VERSION 5.7 ;
BUSBITCHARS "[]" ;
DIVIDERCHAR "/" ;
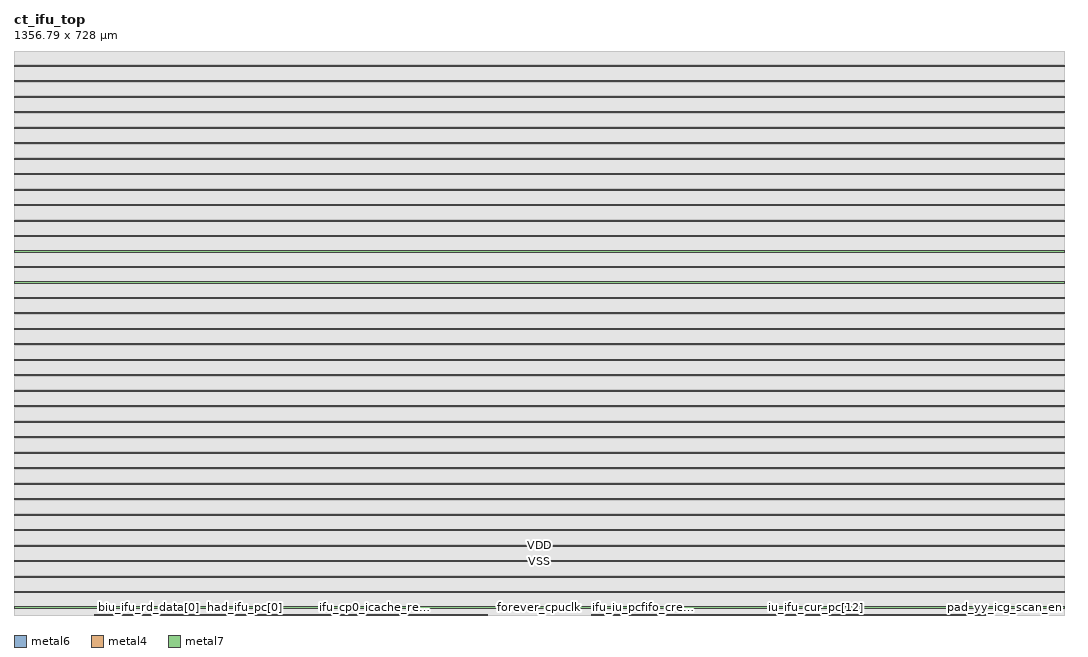
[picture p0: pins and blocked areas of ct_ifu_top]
MACRO ct_ifu_top
  CLASS BLOCK ;
  FOREIGN ct_ifu_top 0 0 ;
  ORIGIN 0 0 ;
  SIZE 1356.79 BY 728 ;
  SYMMETRY X Y ;
  PIN biu_ifu_rd_data[0]
    DIRECTION INPUT ;
    USE SIGNAL ;
    PORT
      LAYER metal6 ;
        RECT 174.185 0.000 174.325 0.560 ;
    END
  END biu_ifu_rd_data[0]
  PIN biu_ifu_rd_data[100]
    DIRECTION INPUT ;
    USE SIGNAL ;
    PORT
      LAYER metal6 ;
        RECT 118.185 0.000 118.325 0.560 ;
    END
  END biu_ifu_rd_data[100]
  PIN biu_ifu_rd_data[101]
    DIRECTION INPUT ;
    USE SIGNAL ;
    PORT
      LAYER metal4 ;
        RECT 118.185 0.000 118.325 0.560 ;
    END
  END biu_ifu_rd_data[101]
  PIN biu_ifu_rd_data[102]
    DIRECTION INPUT ;
    USE SIGNAL ;
    PORT
      LAYER metal6 ;
        RECT 117.065 0.000 117.205 0.560 ;
    END
  END biu_ifu_rd_data[102]
  PIN biu_ifu_rd_data[103]
    DIRECTION INPUT ;
    USE SIGNAL ;
    PORT
      LAYER metal4 ;
        RECT 117.065 0.000 117.205 0.560 ;
    END
  END biu_ifu_rd_data[103]
  PIN biu_ifu_rd_data[104]
    DIRECTION INPUT ;
    USE SIGNAL ;
    PORT
      LAYER metal6 ;
        RECT 115.945 0.000 116.085 0.560 ;
    END
  END biu_ifu_rd_data[104]
  PIN biu_ifu_rd_data[105]
    DIRECTION INPUT ;
    USE SIGNAL ;
    PORT
      LAYER metal4 ;
        RECT 115.945 0.000 116.085 0.560 ;
    END
  END biu_ifu_rd_data[105]
  PIN biu_ifu_rd_data[106]
    DIRECTION INPUT ;
    USE SIGNAL ;
    PORT
      LAYER metal6 ;
        RECT 114.825 0.000 114.965 0.560 ;
    END
  END biu_ifu_rd_data[106]
  PIN biu_ifu_rd_data[107]
    DIRECTION INPUT ;
    USE SIGNAL ;
    PORT
      LAYER metal4 ;
        RECT 114.825 0.000 114.965 0.560 ;
    END
  END biu_ifu_rd_data[107]
  PIN biu_ifu_rd_data[108]
    DIRECTION INPUT ;
    USE SIGNAL ;
    PORT
      LAYER metal6 ;
        RECT 113.705 0.000 113.845 0.560 ;
    END
  END biu_ifu_rd_data[108]
  PIN biu_ifu_rd_data[109]
    DIRECTION INPUT ;
    USE SIGNAL ;
    PORT
      LAYER metal4 ;
        RECT 113.705 0.000 113.845 0.560 ;
    END
  END biu_ifu_rd_data[109]
  PIN biu_ifu_rd_data[10]
    DIRECTION INPUT ;
    USE SIGNAL ;
    PORT
      LAYER metal6 ;
        RECT 168.585 0.000 168.725 0.560 ;
    END
  END biu_ifu_rd_data[10]
  PIN biu_ifu_rd_data[110]
    DIRECTION INPUT ;
    USE SIGNAL ;
    PORT
      LAYER metal6 ;
        RECT 112.585 0.000 112.725 0.560 ;
    END
  END biu_ifu_rd_data[110]
  PIN biu_ifu_rd_data[111]
    DIRECTION INPUT ;
    USE SIGNAL ;
    PORT
      LAYER metal4 ;
        RECT 112.585 0.000 112.725 0.560 ;
    END
  END biu_ifu_rd_data[111]
  PIN biu_ifu_rd_data[112]
    DIRECTION INPUT ;
    USE SIGNAL ;
    PORT
      LAYER metal6 ;
        RECT 111.465 0.000 111.605 0.560 ;
    END
  END biu_ifu_rd_data[112]
  PIN biu_ifu_rd_data[113]
    DIRECTION INPUT ;
    USE SIGNAL ;
    PORT
      LAYER metal4 ;
        RECT 111.465 0.000 111.605 0.560 ;
    END
  END biu_ifu_rd_data[113]
  PIN biu_ifu_rd_data[114]
    DIRECTION INPUT ;
    USE SIGNAL ;
    PORT
      LAYER metal6 ;
        RECT 110.345 0.000 110.485 0.560 ;
    END
  END biu_ifu_rd_data[114]
  PIN biu_ifu_rd_data[115]
    DIRECTION INPUT ;
    USE SIGNAL ;
    PORT
      LAYER metal4 ;
        RECT 110.345 0.000 110.485 0.560 ;
    END
  END biu_ifu_rd_data[115]
  PIN biu_ifu_rd_data[116]
    DIRECTION INPUT ;
    USE SIGNAL ;
    PORT
      LAYER metal6 ;
        RECT 109.225 0.000 109.365 0.560 ;
    END
  END biu_ifu_rd_data[116]
  PIN biu_ifu_rd_data[117]
    DIRECTION INPUT ;
    USE SIGNAL ;
    PORT
      LAYER metal4 ;
        RECT 109.225 0.000 109.365 0.560 ;
    END
  END biu_ifu_rd_data[117]
  PIN biu_ifu_rd_data[118]
    DIRECTION INPUT ;
    USE SIGNAL ;
    PORT
      LAYER metal6 ;
        RECT 108.105 0.000 108.245 0.560 ;
    END
  END biu_ifu_rd_data[118]
  PIN biu_ifu_rd_data[119]
    DIRECTION INPUT ;
    USE SIGNAL ;
    PORT
      LAYER metal4 ;
        RECT 108.105 0.000 108.245 0.560 ;
    END
  END biu_ifu_rd_data[119]
  PIN biu_ifu_rd_data[11]
    DIRECTION INPUT ;
    USE SIGNAL ;
    PORT
      LAYER metal4 ;
        RECT 168.585 0.000 168.725 0.560 ;
    END
  END biu_ifu_rd_data[11]
  PIN biu_ifu_rd_data[120]
    DIRECTION INPUT ;
    USE SIGNAL ;
    PORT
      LAYER metal6 ;
        RECT 106.985 0.000 107.125 0.560 ;
    END
  END biu_ifu_rd_data[120]
  PIN biu_ifu_rd_data[121]
    DIRECTION INPUT ;
    USE SIGNAL ;
    PORT
      LAYER metal4 ;
        RECT 106.985 0.000 107.125 0.560 ;
    END
  END biu_ifu_rd_data[121]
  PIN biu_ifu_rd_data[122]
    DIRECTION INPUT ;
    USE SIGNAL ;
    PORT
      LAYER metal6 ;
        RECT 105.865 0.000 106.005 0.560 ;
    END
  END biu_ifu_rd_data[122]
  PIN biu_ifu_rd_data[123]
    DIRECTION INPUT ;
    USE SIGNAL ;
    PORT
      LAYER metal4 ;
        RECT 105.865 0.000 106.005 0.560 ;
    END
  END biu_ifu_rd_data[123]
  PIN biu_ifu_rd_data[124]
    DIRECTION INPUT ;
    USE SIGNAL ;
    PORT
      LAYER metal6 ;
        RECT 104.745 0.000 104.885 0.560 ;
    END
  END biu_ifu_rd_data[124]
  PIN biu_ifu_rd_data[125]
    DIRECTION INPUT ;
    USE SIGNAL ;
    PORT
      LAYER metal4 ;
        RECT 104.745 0.000 104.885 0.560 ;
    END
  END biu_ifu_rd_data[125]
  PIN biu_ifu_rd_data[126]
    DIRECTION INPUT ;
    USE SIGNAL ;
    PORT
      LAYER metal6 ;
        RECT 103.625 0.000 103.765 0.560 ;
    END
  END biu_ifu_rd_data[126]
  PIN biu_ifu_rd_data[127]
    DIRECTION INPUT ;
    USE SIGNAL ;
    PORT
      LAYER metal4 ;
        RECT 103.625 0.000 103.765 0.560 ;
    END
  END biu_ifu_rd_data[127]
  PIN biu_ifu_rd_data[12]
    DIRECTION INPUT ;
    USE SIGNAL ;
    PORT
      LAYER metal6 ;
        RECT 167.465 0.000 167.605 0.560 ;
    END
  END biu_ifu_rd_data[12]
  PIN biu_ifu_rd_data[13]
    DIRECTION INPUT ;
    USE SIGNAL ;
    PORT
      LAYER metal4 ;
        RECT 167.465 0.000 167.605 0.560 ;
    END
  END biu_ifu_rd_data[13]
  PIN biu_ifu_rd_data[14]
    DIRECTION INPUT ;
    USE SIGNAL ;
    PORT
      LAYER metal6 ;
        RECT 166.345 0.000 166.485 0.560 ;
    END
  END biu_ifu_rd_data[14]
  PIN biu_ifu_rd_data[15]
    DIRECTION INPUT ;
    USE SIGNAL ;
    PORT
      LAYER metal4 ;
        RECT 166.345 0.000 166.485 0.560 ;
    END
  END biu_ifu_rd_data[15]
  PIN biu_ifu_rd_data[16]
    DIRECTION INPUT ;
    USE SIGNAL ;
    PORT
      LAYER metal6 ;
        RECT 165.225 0.000 165.365 0.560 ;
    END
  END biu_ifu_rd_data[16]
  PIN biu_ifu_rd_data[17]
    DIRECTION INPUT ;
    USE SIGNAL ;
    PORT
      LAYER metal4 ;
        RECT 165.225 0.000 165.365 0.560 ;
    END
  END biu_ifu_rd_data[17]
  PIN biu_ifu_rd_data[18]
    DIRECTION INPUT ;
    USE SIGNAL ;
    PORT
      LAYER metal6 ;
        RECT 164.105 0.000 164.245 0.560 ;
    END
  END biu_ifu_rd_data[18]
  PIN biu_ifu_rd_data[19]
    DIRECTION INPUT ;
    USE SIGNAL ;
    PORT
      LAYER metal4 ;
        RECT 164.105 0.000 164.245 0.560 ;
    END
  END biu_ifu_rd_data[19]
  PIN biu_ifu_rd_data[1]
    DIRECTION INPUT ;
    USE SIGNAL ;
    PORT
      LAYER metal4 ;
        RECT 174.185 0.000 174.325 0.560 ;
    END
  END biu_ifu_rd_data[1]
  PIN biu_ifu_rd_data[20]
    DIRECTION INPUT ;
    USE SIGNAL ;
    PORT
      LAYER metal6 ;
        RECT 162.985 0.000 163.125 0.560 ;
    END
  END biu_ifu_rd_data[20]
  PIN biu_ifu_rd_data[21]
    DIRECTION INPUT ;
    USE SIGNAL ;
    PORT
      LAYER metal4 ;
        RECT 162.985 0.000 163.125 0.560 ;
    END
  END biu_ifu_rd_data[21]
  PIN biu_ifu_rd_data[22]
    DIRECTION INPUT ;
    USE SIGNAL ;
    PORT
      LAYER metal6 ;
        RECT 161.865 0.000 162.005 0.560 ;
    END
  END biu_ifu_rd_data[22]
  PIN biu_ifu_rd_data[23]
    DIRECTION INPUT ;
    USE SIGNAL ;
    PORT
      LAYER metal4 ;
        RECT 161.865 0.000 162.005 0.560 ;
    END
  END biu_ifu_rd_data[23]
  PIN biu_ifu_rd_data[24]
    DIRECTION INPUT ;
    USE SIGNAL ;
    PORT
      LAYER metal6 ;
        RECT 160.745 0.000 160.885 0.560 ;
    END
  END biu_ifu_rd_data[24]
  PIN biu_ifu_rd_data[25]
    DIRECTION INPUT ;
    USE SIGNAL ;
    PORT
      LAYER metal4 ;
        RECT 160.745 0.000 160.885 0.560 ;
    END
  END biu_ifu_rd_data[25]
  PIN biu_ifu_rd_data[26]
    DIRECTION INPUT ;
    USE SIGNAL ;
    PORT
      LAYER metal6 ;
        RECT 159.625 0.000 159.765 0.560 ;
    END
  END biu_ifu_rd_data[26]
  PIN biu_ifu_rd_data[27]
    DIRECTION INPUT ;
    USE SIGNAL ;
    PORT
      LAYER metal4 ;
        RECT 159.625 0.000 159.765 0.560 ;
    END
  END biu_ifu_rd_data[27]
  PIN biu_ifu_rd_data[28]
    DIRECTION INPUT ;
    USE SIGNAL ;
    PORT
      LAYER metal6 ;
        RECT 158.505 0.000 158.645 0.560 ;
    END
  END biu_ifu_rd_data[28]
  PIN biu_ifu_rd_data[29]
    DIRECTION INPUT ;
    USE SIGNAL ;
    PORT
      LAYER metal4 ;
        RECT 158.505 0.000 158.645 0.560 ;
    END
  END biu_ifu_rd_data[29]
  PIN biu_ifu_rd_data[2]
    DIRECTION INPUT ;
    USE SIGNAL ;
    PORT
      LAYER metal6 ;
        RECT 173.065 0.000 173.205 0.560 ;
    END
  END biu_ifu_rd_data[2]
  PIN biu_ifu_rd_data[30]
    DIRECTION INPUT ;
    USE SIGNAL ;
    PORT
      LAYER metal6 ;
        RECT 157.385 0.000 157.525 0.560 ;
    END
  END biu_ifu_rd_data[30]
  PIN biu_ifu_rd_data[31]
    DIRECTION INPUT ;
    USE SIGNAL ;
    PORT
      LAYER metal4 ;
        RECT 157.385 0.000 157.525 0.560 ;
    END
  END biu_ifu_rd_data[31]
  PIN biu_ifu_rd_data[32]
    DIRECTION INPUT ;
    USE SIGNAL ;
    PORT
      LAYER metal6 ;
        RECT 156.265 0.000 156.405 0.560 ;
    END
  END biu_ifu_rd_data[32]
  PIN biu_ifu_rd_data[33]
    DIRECTION INPUT ;
    USE SIGNAL ;
    PORT
      LAYER metal4 ;
        RECT 156.265 0.000 156.405 0.560 ;
    END
  END biu_ifu_rd_data[33]
  PIN biu_ifu_rd_data[34]
    DIRECTION INPUT ;
    USE SIGNAL ;
    PORT
      LAYER metal6 ;
        RECT 155.145 0.000 155.285 0.560 ;
    END
  END biu_ifu_rd_data[34]
  PIN biu_ifu_rd_data[35]
    DIRECTION INPUT ;
    USE SIGNAL ;
    PORT
      LAYER metal4 ;
        RECT 155.145 0.000 155.285 0.560 ;
    END
  END biu_ifu_rd_data[35]
  PIN biu_ifu_rd_data[36]
    DIRECTION INPUT ;
    USE SIGNAL ;
    PORT
      LAYER metal6 ;
        RECT 154.025 0.000 154.165 0.560 ;
    END
  END biu_ifu_rd_data[36]
  PIN biu_ifu_rd_data[37]
    DIRECTION INPUT ;
    USE SIGNAL ;
    PORT
      LAYER metal4 ;
        RECT 154.025 0.000 154.165 0.560 ;
    END
  END biu_ifu_rd_data[37]
  PIN biu_ifu_rd_data[38]
    DIRECTION INPUT ;
    USE SIGNAL ;
    PORT
      LAYER metal6 ;
        RECT 152.905 0.000 153.045 0.560 ;
    END
  END biu_ifu_rd_data[38]
  PIN biu_ifu_rd_data[39]
    DIRECTION INPUT ;
    USE SIGNAL ;
    PORT
      LAYER metal4 ;
        RECT 152.905 0.000 153.045 0.560 ;
    END
  END biu_ifu_rd_data[39]
  PIN biu_ifu_rd_data[3]
    DIRECTION INPUT ;
    USE SIGNAL ;
    PORT
      LAYER metal4 ;
        RECT 173.065 0.000 173.205 0.560 ;
    END
  END biu_ifu_rd_data[3]
  PIN biu_ifu_rd_data[40]
    DIRECTION INPUT ;
    USE SIGNAL ;
    PORT
      LAYER metal6 ;
        RECT 151.785 0.000 151.925 0.560 ;
    END
  END biu_ifu_rd_data[40]
  PIN biu_ifu_rd_data[41]
    DIRECTION INPUT ;
    USE SIGNAL ;
    PORT
      LAYER metal4 ;
        RECT 151.785 0.000 151.925 0.560 ;
    END
  END biu_ifu_rd_data[41]
  PIN biu_ifu_rd_data[42]
    DIRECTION INPUT ;
    USE SIGNAL ;
    PORT
      LAYER metal6 ;
        RECT 150.665 0.000 150.805 0.560 ;
    END
  END biu_ifu_rd_data[42]
  PIN biu_ifu_rd_data[43]
    DIRECTION INPUT ;
    USE SIGNAL ;
    PORT
      LAYER metal4 ;
        RECT 150.665 0.000 150.805 0.560 ;
    END
  END biu_ifu_rd_data[43]
  PIN biu_ifu_rd_data[44]
    DIRECTION INPUT ;
    USE SIGNAL ;
    PORT
      LAYER metal6 ;
        RECT 149.545 0.000 149.685 0.560 ;
    END
  END biu_ifu_rd_data[44]
  PIN biu_ifu_rd_data[45]
    DIRECTION INPUT ;
    USE SIGNAL ;
    PORT
      LAYER metal4 ;
        RECT 149.545 0.000 149.685 0.560 ;
    END
  END biu_ifu_rd_data[45]
  PIN biu_ifu_rd_data[46]
    DIRECTION INPUT ;
    USE SIGNAL ;
    PORT
      LAYER metal6 ;
        RECT 148.425 0.000 148.565 0.560 ;
    END
  END biu_ifu_rd_data[46]
  PIN biu_ifu_rd_data[47]
    DIRECTION INPUT ;
    USE SIGNAL ;
    PORT
      LAYER metal4 ;
        RECT 148.425 0.000 148.565 0.560 ;
    END
  END biu_ifu_rd_data[47]
  PIN biu_ifu_rd_data[48]
    DIRECTION INPUT ;
    USE SIGNAL ;
    PORT
      LAYER metal6 ;
        RECT 147.305 0.000 147.445 0.560 ;
    END
  END biu_ifu_rd_data[48]
  PIN biu_ifu_rd_data[49]
    DIRECTION INPUT ;
    USE SIGNAL ;
    PORT
      LAYER metal4 ;
        RECT 147.305 0.000 147.445 0.560 ;
    END
  END biu_ifu_rd_data[49]
  PIN biu_ifu_rd_data[4]
    DIRECTION INPUT ;
    USE SIGNAL ;
    PORT
      LAYER metal6 ;
        RECT 171.945 0.000 172.085 0.560 ;
    END
  END biu_ifu_rd_data[4]
  PIN biu_ifu_rd_data[50]
    DIRECTION INPUT ;
    USE SIGNAL ;
    PORT
      LAYER metal6 ;
        RECT 146.185 0.000 146.325 0.560 ;
    END
  END biu_ifu_rd_data[50]
  PIN biu_ifu_rd_data[51]
    DIRECTION INPUT ;
    USE SIGNAL ;
    PORT
      LAYER metal4 ;
        RECT 146.185 0.000 146.325 0.560 ;
    END
  END biu_ifu_rd_data[51]
  PIN biu_ifu_rd_data[52]
    DIRECTION INPUT ;
    USE SIGNAL ;
    PORT
      LAYER metal6 ;
        RECT 145.065 0.000 145.205 0.560 ;
    END
  END biu_ifu_rd_data[52]
  PIN biu_ifu_rd_data[53]
    DIRECTION INPUT ;
    USE SIGNAL ;
    PORT
      LAYER metal4 ;
        RECT 145.065 0.000 145.205 0.560 ;
    END
  END biu_ifu_rd_data[53]
  PIN biu_ifu_rd_data[54]
    DIRECTION INPUT ;
    USE SIGNAL ;
    PORT
      LAYER metal6 ;
        RECT 143.945 0.000 144.085 0.560 ;
    END
  END biu_ifu_rd_data[54]
  PIN biu_ifu_rd_data[55]
    DIRECTION INPUT ;
    USE SIGNAL ;
    PORT
      LAYER metal4 ;
        RECT 143.945 0.000 144.085 0.560 ;
    END
  END biu_ifu_rd_data[55]
  PIN biu_ifu_rd_data[56]
    DIRECTION INPUT ;
    USE SIGNAL ;
    PORT
      LAYER metal6 ;
        RECT 142.825 0.000 142.965 0.560 ;
    END
  END biu_ifu_rd_data[56]
  PIN biu_ifu_rd_data[57]
    DIRECTION INPUT ;
    USE SIGNAL ;
    PORT
      LAYER metal4 ;
        RECT 142.825 0.000 142.965 0.560 ;
    END
  END biu_ifu_rd_data[57]
  PIN biu_ifu_rd_data[58]
    DIRECTION INPUT ;
    USE SIGNAL ;
    PORT
      LAYER metal6 ;
        RECT 141.705 0.000 141.845 0.560 ;
    END
  END biu_ifu_rd_data[58]
  PIN biu_ifu_rd_data[59]
    DIRECTION INPUT ;
    USE SIGNAL ;
    PORT
      LAYER metal4 ;
        RECT 141.705 0.000 141.845 0.560 ;
    END
  END biu_ifu_rd_data[59]
  PIN biu_ifu_rd_data[5]
    DIRECTION INPUT ;
    USE SIGNAL ;
    PORT
      LAYER metal4 ;
        RECT 171.945 0.000 172.085 0.560 ;
    END
  END biu_ifu_rd_data[5]
  PIN biu_ifu_rd_data[60]
    DIRECTION INPUT ;
    USE SIGNAL ;
    PORT
      LAYER metal6 ;
        RECT 140.585 0.000 140.725 0.560 ;
    END
  END biu_ifu_rd_data[60]
  PIN biu_ifu_rd_data[61]
    DIRECTION INPUT ;
    USE SIGNAL ;
    PORT
      LAYER metal4 ;
        RECT 140.585 0.000 140.725 0.560 ;
    END
  END biu_ifu_rd_data[61]
  PIN biu_ifu_rd_data[62]
    DIRECTION INPUT ;
    USE SIGNAL ;
    PORT
      LAYER metal6 ;
        RECT 139.465 0.000 139.605 0.560 ;
    END
  END biu_ifu_rd_data[62]
  PIN biu_ifu_rd_data[63]
    DIRECTION INPUT ;
    USE SIGNAL ;
    PORT
      LAYER metal4 ;
        RECT 139.465 0.000 139.605 0.560 ;
    END
  END biu_ifu_rd_data[63]
  PIN biu_ifu_rd_data[64]
    DIRECTION INPUT ;
    USE SIGNAL ;
    PORT
      LAYER metal6 ;
        RECT 138.345 0.000 138.485 0.560 ;
    END
  END biu_ifu_rd_data[64]
  PIN biu_ifu_rd_data[65]
    DIRECTION INPUT ;
    USE SIGNAL ;
    PORT
      LAYER metal4 ;
        RECT 138.345 0.000 138.485 0.560 ;
    END
  END biu_ifu_rd_data[65]
  PIN biu_ifu_rd_data[66]
    DIRECTION INPUT ;
    USE SIGNAL ;
    PORT
      LAYER metal6 ;
        RECT 137.225 0.000 137.365 0.560 ;
    END
  END biu_ifu_rd_data[66]
  PIN biu_ifu_rd_data[67]
    DIRECTION INPUT ;
    USE SIGNAL ;
    PORT
      LAYER metal4 ;
        RECT 137.225 0.000 137.365 0.560 ;
    END
  END biu_ifu_rd_data[67]
  PIN biu_ifu_rd_data[68]
    DIRECTION INPUT ;
    USE SIGNAL ;
    PORT
      LAYER metal6 ;
        RECT 136.105 0.000 136.245 0.560 ;
    END
  END biu_ifu_rd_data[68]
  PIN biu_ifu_rd_data[69]
    DIRECTION INPUT ;
    USE SIGNAL ;
    PORT
      LAYER metal4 ;
        RECT 136.105 0.000 136.245 0.560 ;
    END
  END biu_ifu_rd_data[69]
  PIN biu_ifu_rd_data[6]
    DIRECTION INPUT ;
    USE SIGNAL ;
    PORT
      LAYER metal6 ;
        RECT 170.825 0.000 170.965 0.560 ;
    END
  END biu_ifu_rd_data[6]
  PIN biu_ifu_rd_data[70]
    DIRECTION INPUT ;
    USE SIGNAL ;
    PORT
      LAYER metal6 ;
        RECT 134.985 0.000 135.125 0.560 ;
    END
  END biu_ifu_rd_data[70]
  PIN biu_ifu_rd_data[71]
    DIRECTION INPUT ;
    USE SIGNAL ;
    PORT
      LAYER metal4 ;
        RECT 134.985 0.000 135.125 0.560 ;
    END
  END biu_ifu_rd_data[71]
  PIN biu_ifu_rd_data[72]
    DIRECTION INPUT ;
    USE SIGNAL ;
    PORT
      LAYER metal6 ;
        RECT 133.865 0.000 134.005 0.560 ;
    END
  END biu_ifu_rd_data[72]
  PIN biu_ifu_rd_data[73]
    DIRECTION INPUT ;
    USE SIGNAL ;
    PORT
      LAYER metal4 ;
        RECT 133.865 0.000 134.005 0.560 ;
    END
  END biu_ifu_rd_data[73]
  PIN biu_ifu_rd_data[74]
    DIRECTION INPUT ;
    USE SIGNAL ;
    PORT
      LAYER metal6 ;
        RECT 132.745 0.000 132.885 0.560 ;
    END
  END biu_ifu_rd_data[74]
  PIN biu_ifu_rd_data[75]
    DIRECTION INPUT ;
    USE SIGNAL ;
    PORT
      LAYER metal4 ;
        RECT 132.745 0.000 132.885 0.560 ;
    END
  END biu_ifu_rd_data[75]
  PIN biu_ifu_rd_data[76]
    DIRECTION INPUT ;
    USE SIGNAL ;
    PORT
      LAYER metal6 ;
        RECT 131.625 0.000 131.765 0.560 ;
    END
  END biu_ifu_rd_data[76]
  PIN biu_ifu_rd_data[77]
    DIRECTION INPUT ;
    USE SIGNAL ;
    PORT
      LAYER metal4 ;
        RECT 131.625 0.000 131.765 0.560 ;
    END
  END biu_ifu_rd_data[77]
  PIN biu_ifu_rd_data[78]
    DIRECTION INPUT ;
    USE SIGNAL ;
    PORT
      LAYER metal6 ;
        RECT 130.505 0.000 130.645 0.560 ;
    END
  END biu_ifu_rd_data[78]
  PIN biu_ifu_rd_data[79]
    DIRECTION INPUT ;
    USE SIGNAL ;
    PORT
      LAYER metal4 ;
        RECT 130.505 0.000 130.645 0.560 ;
    END
  END biu_ifu_rd_data[79]
  PIN biu_ifu_rd_data[7]
    DIRECTION INPUT ;
    USE SIGNAL ;
    PORT
      LAYER metal4 ;
        RECT 170.825 0.000 170.965 0.560 ;
    END
  END biu_ifu_rd_data[7]
  PIN biu_ifu_rd_data[80]
    DIRECTION INPUT ;
    USE SIGNAL ;
    PORT
      LAYER metal6 ;
        RECT 129.385 0.000 129.525 0.560 ;
    END
  END biu_ifu_rd_data[80]
  PIN biu_ifu_rd_data[81]
    DIRECTION INPUT ;
    USE SIGNAL ;
    PORT
      LAYER metal4 ;
        RECT 129.385 0.000 129.525 0.560 ;
    END
  END biu_ifu_rd_data[81]
  PIN biu_ifu_rd_data[82]
    DIRECTION INPUT ;
    USE SIGNAL ;
    PORT
      LAYER metal6 ;
        RECT 128.265 0.000 128.405 0.560 ;
    END
  END biu_ifu_rd_data[82]
  PIN biu_ifu_rd_data[83]
    DIRECTION INPUT ;
    USE SIGNAL ;
    PORT
      LAYER metal4 ;
        RECT 128.265 0.000 128.405 0.560 ;
    END
  END biu_ifu_rd_data[83]
  PIN biu_ifu_rd_data[84]
    DIRECTION INPUT ;
    USE SIGNAL ;
    PORT
      LAYER metal6 ;
        RECT 127.145 0.000 127.285 0.560 ;
    END
  END biu_ifu_rd_data[84]
  PIN biu_ifu_rd_data[85]
    DIRECTION INPUT ;
    USE SIGNAL ;
    PORT
      LAYER metal4 ;
        RECT 127.145 0.000 127.285 0.560 ;
    END
  END biu_ifu_rd_data[85]
  PIN biu_ifu_rd_data[86]
    DIRECTION INPUT ;
    USE SIGNAL ;
    PORT
      LAYER metal6 ;
        RECT 126.025 0.000 126.165 0.560 ;
    END
  END biu_ifu_rd_data[86]
  PIN biu_ifu_rd_data[87]
    DIRECTION INPUT ;
    USE SIGNAL ;
    PORT
      LAYER metal4 ;
        RECT 126.025 0.000 126.165 0.560 ;
    END
  END biu_ifu_rd_data[87]
  PIN biu_ifu_rd_data[88]
    DIRECTION INPUT ;
    USE SIGNAL ;
    PORT
      LAYER metal6 ;
        RECT 124.905 0.000 125.045 0.560 ;
    END
  END biu_ifu_rd_data[88]
  PIN biu_ifu_rd_data[89]
    DIRECTION INPUT ;
    USE SIGNAL ;
    PORT
      LAYER metal4 ;
        RECT 124.905 0.000 125.045 0.560 ;
    END
  END biu_ifu_rd_data[89]
  PIN biu_ifu_rd_data[8]
    DIRECTION INPUT ;
    USE SIGNAL ;
    PORT
      LAYER metal6 ;
        RECT 169.705 0.000 169.845 0.560 ;
    END
  END biu_ifu_rd_data[8]
  PIN biu_ifu_rd_data[90]
    DIRECTION INPUT ;
    USE SIGNAL ;
    PORT
      LAYER metal6 ;
        RECT 123.785 0.000 123.925 0.560 ;
    END
  END biu_ifu_rd_data[90]
  PIN biu_ifu_rd_data[91]
    DIRECTION INPUT ;
    USE SIGNAL ;
    PORT
      LAYER metal4 ;
        RECT 123.785 0.000 123.925 0.560 ;
    END
  END biu_ifu_rd_data[91]
  PIN biu_ifu_rd_data[92]
    DIRECTION INPUT ;
    USE SIGNAL ;
    PORT
      LAYER metal6 ;
        RECT 122.665 0.000 122.805 0.560 ;
    END
  END biu_ifu_rd_data[92]
  PIN biu_ifu_rd_data[93]
    DIRECTION INPUT ;
    USE SIGNAL ;
    PORT
      LAYER metal4 ;
        RECT 122.665 0.000 122.805 0.560 ;
    END
  END biu_ifu_rd_data[93]
  PIN biu_ifu_rd_data[94]
    DIRECTION INPUT ;
    USE SIGNAL ;
    PORT
      LAYER metal6 ;
        RECT 121.545 0.000 121.685 0.560 ;
    END
  END biu_ifu_rd_data[94]
  PIN biu_ifu_rd_data[95]
    DIRECTION INPUT ;
    USE SIGNAL ;
    PORT
      LAYER metal4 ;
        RECT 121.545 0.000 121.685 0.560 ;
    END
  END biu_ifu_rd_data[95]
  PIN biu_ifu_rd_data[96]
    DIRECTION INPUT ;
    USE SIGNAL ;
    PORT
      LAYER metal6 ;
        RECT 120.425 0.000 120.565 0.560 ;
    END
  END biu_ifu_rd_data[96]
  PIN biu_ifu_rd_data[97]
    DIRECTION INPUT ;
    USE SIGNAL ;
    PORT
      LAYER metal4 ;
        RECT 120.425 0.000 120.565 0.560 ;
    END
  END biu_ifu_rd_data[97]
  PIN biu_ifu_rd_data[98]
    DIRECTION INPUT ;
    USE SIGNAL ;
    PORT
      LAYER metal6 ;
        RECT 119.305 0.000 119.445 0.560 ;
    END
  END biu_ifu_rd_data[98]
  PIN biu_ifu_rd_data[99]
    DIRECTION INPUT ;
    USE SIGNAL ;
    PORT
      LAYER metal4 ;
        RECT 119.305 0.000 119.445 0.560 ;
    END
  END biu_ifu_rd_data[99]
  PIN biu_ifu_rd_data[9]
    DIRECTION INPUT ;
    USE SIGNAL ;
    PORT
      LAYER metal4 ;
        RECT 169.705 0.000 169.845 0.560 ;
    END
  END biu_ifu_rd_data[9]
  PIN biu_ifu_rd_data_vld
    DIRECTION INPUT ;
    USE SIGNAL ;
    PORT
      LAYER metal4 ;
        RECT 175.305 0.000 175.445 0.560 ;
    END
  END biu_ifu_rd_data_vld
  PIN biu_ifu_rd_grnt
    DIRECTION INPUT ;
    USE SIGNAL ;
    PORT
      LAYER metal6 ;
        RECT 175.305 0.000 175.445 0.560 ;
    END
  END biu_ifu_rd_grnt
  PIN biu_ifu_rd_id
    DIRECTION INPUT ;
    USE SIGNAL ;
    PORT
      LAYER metal4 ;
        RECT 176.425 0.000 176.565 0.560 ;
    END
  END biu_ifu_rd_id
  PIN biu_ifu_rd_last
    DIRECTION INPUT ;
    USE SIGNAL ;
    PORT
      LAYER metal6 ;
        RECT 176.425 0.000 176.565 0.560 ;
    END
  END biu_ifu_rd_last
  PIN biu_ifu_rd_resp[0]
    DIRECTION INPUT ;
    USE SIGNAL ;
    PORT
      LAYER metal6 ;
        RECT 177.545 0.000 177.685 0.560 ;
    END
  END biu_ifu_rd_resp[0]
  PIN biu_ifu_rd_resp[1]
    DIRECTION INPUT ;
    USE SIGNAL ;
    PORT
      LAYER metal4 ;
        RECT 177.545 0.000 177.685 0.560 ;
    END
  END biu_ifu_rd_resp[1]
  PIN cp0_idu_cskyee
    DIRECTION INPUT ;
    USE SIGNAL ;
    PORT
      LAYER metal4 ;
        RECT 178.665 0.000 178.805 0.560 ;
    END
  END cp0_idu_cskyee
  PIN cp0_idu_frm[0]
    DIRECTION INPUT ;
    USE SIGNAL ;
    PORT
      LAYER metal6 ;
        RECT 179.785 0.000 179.925 0.560 ;
    END
  END cp0_idu_frm[0]
  PIN cp0_idu_frm[1]
    DIRECTION INPUT ;
    USE SIGNAL ;
    PORT
      LAYER metal4 ;
        RECT 179.785 0.000 179.925 0.560 ;
    END
  END cp0_idu_frm[1]
  PIN cp0_idu_frm[2]
    DIRECTION INPUT ;
    USE SIGNAL ;
    PORT
      LAYER metal6 ;
        RECT 178.665 0.000 178.805 0.560 ;
    END
  END cp0_idu_frm[2]
  PIN cp0_idu_fs[0]
    DIRECTION INPUT ;
    USE SIGNAL ;
    PORT
      LAYER metal6 ;
        RECT 180.905 0.000 181.045 0.560 ;
    END
  END cp0_idu_fs[0]
  PIN cp0_idu_fs[1]
    DIRECTION INPUT ;
    USE SIGNAL ;
    PORT
      LAYER metal4 ;
        RECT 180.905 0.000 181.045 0.560 ;
    END
  END cp0_idu_fs[1]
  PIN cp0_ifu_bht_en
    DIRECTION INPUT ;
    USE SIGNAL ;
    PORT
      LAYER metal4 ;
        RECT 182.025 0.000 182.165 0.560 ;
    END
  END cp0_ifu_bht_en
  PIN cp0_ifu_bht_inv
    DIRECTION INPUT ;
    USE SIGNAL ;
    PORT
      LAYER metal6 ;
        RECT 182.025 0.000 182.165 0.560 ;
    END
  END cp0_ifu_bht_inv
  PIN cp0_ifu_btb_en
    DIRECTION INPUT ;
    USE SIGNAL ;
    PORT
      LAYER metal4 ;
        RECT 183.145 0.000 183.285 0.560 ;
    END
  END cp0_ifu_btb_en
  PIN cp0_ifu_btb_inv
    DIRECTION INPUT ;
    USE SIGNAL ;
    PORT
      LAYER metal6 ;
        RECT 183.145 0.000 183.285 0.560 ;
    END
  END cp0_ifu_btb_inv
  PIN cp0_ifu_icache_en
    DIRECTION INPUT ;
    USE SIGNAL ;
    PORT
      LAYER metal4 ;
        RECT 184.265 0.000 184.405 0.560 ;
    END
  END cp0_ifu_icache_en
  PIN cp0_ifu_icache_inv
    DIRECTION INPUT ;
    USE SIGNAL ;
    PORT
      LAYER metal6 ;
        RECT 184.265 0.000 184.405 0.560 ;
    END
  END cp0_ifu_icache_inv
  PIN cp0_ifu_icache_pref_en
    DIRECTION INPUT ;
    USE SIGNAL ;
    PORT
      LAYER metal4 ;
        RECT 185.385 0.000 185.525 0.560 ;
    END
  END cp0_ifu_icache_pref_en
  PIN cp0_ifu_icache_read_index[0]
    DIRECTION INPUT ;
    USE SIGNAL ;
    PORT
      LAYER metal6 ;
        RECT 194.345 0.000 194.485 0.560 ;
    END
  END cp0_ifu_icache_read_index[0]
  PIN cp0_ifu_icache_read_index[10]
    DIRECTION INPUT ;
    USE SIGNAL ;
    PORT
      LAYER metal6 ;
        RECT 188.745 0.000 188.885 0.560 ;
    END
  END cp0_ifu_icache_read_index[10]
  PIN cp0_ifu_icache_read_index[11]
    DIRECTION INPUT ;
    USE SIGNAL ;
    PORT
      LAYER metal4 ;
        RECT 188.745 0.000 188.885 0.560 ;
    END
  END cp0_ifu_icache_read_index[11]
  PIN cp0_ifu_icache_read_index[12]
    DIRECTION INPUT ;
    USE SIGNAL ;
    PORT
      LAYER metal6 ;
        RECT 187.625 0.000 187.765 0.560 ;
    END
  END cp0_ifu_icache_read_index[12]
  PIN cp0_ifu_icache_read_index[13]
    DIRECTION INPUT ;
    USE SIGNAL ;
    PORT
      LAYER metal4 ;
        RECT 187.625 0.000 187.765 0.560 ;
    END
  END cp0_ifu_icache_read_index[13]
  PIN cp0_ifu_icache_read_index[14]
    DIRECTION INPUT ;
    USE SIGNAL ;
    PORT
      LAYER metal6 ;
        RECT 186.505 0.000 186.645 0.560 ;
    END
  END cp0_ifu_icache_read_index[14]
  PIN cp0_ifu_icache_read_index[15]
    DIRECTION INPUT ;
    USE SIGNAL ;
    PORT
      LAYER metal4 ;
        RECT 186.505 0.000 186.645 0.560 ;
    END
  END cp0_ifu_icache_read_index[15]
  PIN cp0_ifu_icache_read_index[16]
    DIRECTION INPUT ;
    USE SIGNAL ;
    PORT
      LAYER metal6 ;
        RECT 185.385 0.000 185.525 0.560 ;
    END
  END cp0_ifu_icache_read_index[16]
  PIN cp0_ifu_icache_read_index[1]
    DIRECTION INPUT ;
    USE SIGNAL ;
    PORT
      LAYER metal4 ;
        RECT 194.345 0.000 194.485 0.560 ;
    END
  END cp0_ifu_icache_read_index[1]
  PIN cp0_ifu_icache_read_index[2]
    DIRECTION INPUT ;
    USE SIGNAL ;
    PORT
      LAYER metal6 ;
        RECT 193.225 0.000 193.365 0.560 ;
    END
  END cp0_ifu_icache_read_index[2]
  PIN cp0_ifu_icache_read_index[3]
    DIRECTION INPUT ;
    USE SIGNAL ;
    PORT
      LAYER metal4 ;
        RECT 193.225 0.000 193.365 0.560 ;
    END
  END cp0_ifu_icache_read_index[3]
  PIN cp0_ifu_icache_read_index[4]
    DIRECTION INPUT ;
    USE SIGNAL ;
    PORT
      LAYER metal6 ;
        RECT 192.105 0.000 192.245 0.560 ;
    END
  END cp0_ifu_icache_read_index[4]
  PIN cp0_ifu_icache_read_index[5]
    DIRECTION INPUT ;
    USE SIGNAL ;
    PORT
      LAYER metal4 ;
        RECT 192.105 0.000 192.245 0.560 ;
    END
  END cp0_ifu_icache_read_index[5]
  PIN cp0_ifu_icache_read_index[6]
    DIRECTION INPUT ;
    USE SIGNAL ;
    PORT
      LAYER metal6 ;
        RECT 190.985 0.000 191.125 0.560 ;
    END
  END cp0_ifu_icache_read_index[6]
  PIN cp0_ifu_icache_read_index[7]
    DIRECTION INPUT ;
    USE SIGNAL ;
    PORT
      LAYER metal4 ;
        RECT 190.985 0.000 191.125 0.560 ;
    END
  END cp0_ifu_icache_read_index[7]
  PIN cp0_ifu_icache_read_index[8]
    DIRECTION INPUT ;
    USE SIGNAL ;
    PORT
      LAYER metal6 ;
        RECT 189.865 0.000 190.005 0.560 ;
    END
  END cp0_ifu_icache_read_index[8]
  PIN cp0_ifu_icache_read_index[9]
    DIRECTION INPUT ;
    USE SIGNAL ;
    PORT
      LAYER metal4 ;
        RECT 189.865 0.000 190.005 0.560 ;
    END
  END cp0_ifu_icache_read_index[9]
  PIN cp0_ifu_icache_read_req
    DIRECTION INPUT ;
    USE SIGNAL ;
    PORT
      LAYER metal4 ;
        RECT 195.465 0.000 195.605 0.560 ;
    END
  END cp0_ifu_icache_read_req
  PIN cp0_ifu_icache_read_tag
    DIRECTION INPUT ;
    USE SIGNAL ;
    PORT
      LAYER metal6 ;
        RECT 195.465 0.000 195.605 0.560 ;
    END
  END cp0_ifu_icache_read_tag
  PIN cp0_ifu_icache_read_way
    DIRECTION INPUT ;
    USE SIGNAL ;
    PORT
      LAYER metal4 ;
        RECT 196.585 0.000 196.725 0.560 ;
    END
  END cp0_ifu_icache_read_way
  PIN cp0_ifu_icg_en
    DIRECTION INPUT ;
    USE SIGNAL ;
    PORT
      LAYER metal6 ;
        RECT 196.585 0.000 196.725 0.560 ;
    END
  END cp0_ifu_icg_en
  PIN cp0_ifu_ind_btb_en
    DIRECTION INPUT ;
    USE SIGNAL ;
    PORT
      LAYER metal4 ;
        RECT 197.705 0.000 197.845 0.560 ;
    END
  END cp0_ifu_ind_btb_en
  PIN cp0_ifu_ind_btb_inv
    DIRECTION INPUT ;
    USE SIGNAL ;
    PORT
      LAYER metal6 ;
        RECT 197.705 0.000 197.845 0.560 ;
    END
  END cp0_ifu_ind_btb_inv
  PIN cp0_ifu_insde
    DIRECTION INPUT ;
    USE SIGNAL ;
    PORT
      LAYER metal4 ;
        RECT 198.825 0.000 198.965 0.560 ;
    END
  END cp0_ifu_insde
  PIN cp0_ifu_iwpe
    DIRECTION INPUT ;
    USE SIGNAL ;
    PORT
      LAYER metal6 ;
        RECT 198.825 0.000 198.965 0.560 ;
    END
  END cp0_ifu_iwpe
  PIN cp0_ifu_l0btb_en
    DIRECTION INPUT ;
    USE SIGNAL ;
    PORT
      LAYER metal4 ;
        RECT 199.945 0.000 200.085 0.560 ;
    END
  END cp0_ifu_l0btb_en
  PIN cp0_ifu_lbuf_en
    DIRECTION INPUT ;
    USE SIGNAL ;
    PORT
      LAYER metal6 ;
        RECT 199.945 0.000 200.085 0.560 ;
    END
  END cp0_ifu_lbuf_en
  PIN cp0_ifu_no_op_req
    DIRECTION INPUT ;
    USE SIGNAL ;
    PORT
      LAYER metal4 ;
        RECT 201.065 0.000 201.205 0.560 ;
    END
  END cp0_ifu_no_op_req
  PIN cp0_ifu_nsfe
    DIRECTION INPUT ;
    USE SIGNAL ;
    PORT
      LAYER metal6 ;
        RECT 201.065 0.000 201.205 0.560 ;
    END
  END cp0_ifu_nsfe
  PIN cp0_ifu_ras_en
    DIRECTION INPUT ;
    USE SIGNAL ;
    PORT
      LAYER metal4 ;
        RECT 202.185 0.000 202.325 0.560 ;
    END
  END cp0_ifu_ras_en
  PIN cp0_ifu_rst_inv_done
    DIRECTION INPUT ;
    USE SIGNAL ;
    PORT
      LAYER metal6 ;
        RECT 202.185 0.000 202.325 0.560 ;
    END
  END cp0_ifu_rst_inv_done
  PIN cp0_ifu_rvbr[0]
    DIRECTION INPUT ;
    USE SIGNAL ;
    PORT
      LAYER metal6 ;
        RECT 224.585 0.000 224.725 0.560 ;
    END
  END cp0_ifu_rvbr[0]
  PIN cp0_ifu_rvbr[10]
    DIRECTION INPUT ;
    USE SIGNAL ;
    PORT
      LAYER metal6 ;
        RECT 218.985 0.000 219.125 0.560 ;
    END
  END cp0_ifu_rvbr[10]
  PIN cp0_ifu_rvbr[11]
    DIRECTION INPUT ;
    USE SIGNAL ;
    PORT
      LAYER metal4 ;
        RECT 218.985 0.000 219.125 0.560 ;
    END
  END cp0_ifu_rvbr[11]
  PIN cp0_ifu_rvbr[12]
    DIRECTION INPUT ;
    USE SIGNAL ;
    PORT
      LAYER metal6 ;
        RECT 217.865 0.000 218.005 0.560 ;
    END
  END cp0_ifu_rvbr[12]
  PIN cp0_ifu_rvbr[13]
    DIRECTION INPUT ;
    USE SIGNAL ;
    PORT
      LAYER metal4 ;
        RECT 217.865 0.000 218.005 0.560 ;
    END
  END cp0_ifu_rvbr[13]
  PIN cp0_ifu_rvbr[14]
    DIRECTION INPUT ;
    USE SIGNAL ;
    PORT
      LAYER metal6 ;
        RECT 216.745 0.000 216.885 0.560 ;
    END
  END cp0_ifu_rvbr[14]
  PIN cp0_ifu_rvbr[15]
    DIRECTION INPUT ;
    USE SIGNAL ;
    PORT
      LAYER metal4 ;
        RECT 216.745 0.000 216.885 0.560 ;
    END
  END cp0_ifu_rvbr[15]
  PIN cp0_ifu_rvbr[16]
    DIRECTION INPUT ;
    USE SIGNAL ;
    PORT
      LAYER metal6 ;
        RECT 215.625 0.000 215.765 0.560 ;
    END
  END cp0_ifu_rvbr[16]
  PIN cp0_ifu_rvbr[17]
    DIRECTION INPUT ;
    USE SIGNAL ;
    PORT
      LAYER metal4 ;
        RECT 215.625 0.000 215.765 0.560 ;
    END
  END cp0_ifu_rvbr[17]
  PIN cp0_ifu_rvbr[18]
    DIRECTION INPUT ;
    USE SIGNAL ;
    PORT
      LAYER metal6 ;
        RECT 214.505 0.000 214.645 0.560 ;
    END
  END cp0_ifu_rvbr[18]
  PIN cp0_ifu_rvbr[19]
    DIRECTION INPUT ;
    USE SIGNAL ;
    PORT
      LAYER metal4 ;
        RECT 214.505 0.000 214.645 0.560 ;
    END
  END cp0_ifu_rvbr[19]
  PIN cp0_ifu_rvbr[1]
    DIRECTION INPUT ;
    USE SIGNAL ;
    PORT
      LAYER metal4 ;
        RECT 224.585 0.000 224.725 0.560 ;
    END
  END cp0_ifu_rvbr[1]
  PIN cp0_ifu_rvbr[20]
    DIRECTION INPUT ;
    USE SIGNAL ;
    PORT
      LAYER metal6 ;
        RECT 213.385 0.000 213.525 0.560 ;
    END
  END cp0_ifu_rvbr[20]
  PIN cp0_ifu_rvbr[21]
    DIRECTION INPUT ;
    USE SIGNAL ;
    PORT
      LAYER metal4 ;
        RECT 213.385 0.000 213.525 0.560 ;
    END
  END cp0_ifu_rvbr[21]
  PIN cp0_ifu_rvbr[22]
    DIRECTION INPUT ;
    USE SIGNAL ;
    PORT
      LAYER metal6 ;
        RECT 212.265 0.000 212.405 0.560 ;
    END
  END cp0_ifu_rvbr[22]
  PIN cp0_ifu_rvbr[23]
    DIRECTION INPUT ;
    USE SIGNAL ;
    PORT
      LAYER metal4 ;
        RECT 212.265 0.000 212.405 0.560 ;
    END
  END cp0_ifu_rvbr[23]
  PIN cp0_ifu_rvbr[24]
    DIRECTION INPUT ;
    USE SIGNAL ;
    PORT
      LAYER metal6 ;
        RECT 211.145 0.000 211.285 0.560 ;
    END
  END cp0_ifu_rvbr[24]
  PIN cp0_ifu_rvbr[25]
    DIRECTION INPUT ;
    USE SIGNAL ;
    PORT
      LAYER metal4 ;
        RECT 211.145 0.000 211.285 0.560 ;
    END
  END cp0_ifu_rvbr[25]
  PIN cp0_ifu_rvbr[26]
    DIRECTION INPUT ;
    USE SIGNAL ;
    PORT
      LAYER metal6 ;
        RECT 210.025 0.000 210.165 0.560 ;
    END
  END cp0_ifu_rvbr[26]
  PIN cp0_ifu_rvbr[27]
    DIRECTION INPUT ;
    USE SIGNAL ;
    PORT
      LAYER metal4 ;
        RECT 210.025 0.000 210.165 0.560 ;
    END
  END cp0_ifu_rvbr[27]
  PIN cp0_ifu_rvbr[28]
    DIRECTION INPUT ;
    USE SIGNAL ;
    PORT
      LAYER metal6 ;
        RECT 208.905 0.000 209.045 0.560 ;
    END
  END cp0_ifu_rvbr[28]
  PIN cp0_ifu_rvbr[29]
    DIRECTION INPUT ;
    USE SIGNAL ;
    PORT
      LAYER metal4 ;
        RECT 208.905 0.000 209.045 0.560 ;
    END
  END cp0_ifu_rvbr[29]
  PIN cp0_ifu_rvbr[2]
    DIRECTION INPUT ;
    USE SIGNAL ;
    PORT
      LAYER metal6 ;
        RECT 223.465 0.000 223.605 0.560 ;
    END
  END cp0_ifu_rvbr[2]
  PIN cp0_ifu_rvbr[30]
    DIRECTION INPUT ;
    USE SIGNAL ;
    PORT
      LAYER metal6 ;
        RECT 207.785 0.000 207.925 0.560 ;
    END
  END cp0_ifu_rvbr[30]
  PIN cp0_ifu_rvbr[31]
    DIRECTION INPUT ;
    USE SIGNAL ;
    PORT
      LAYER metal4 ;
        RECT 207.785 0.000 207.925 0.560 ;
    END
  END cp0_ifu_rvbr[31]
  PIN cp0_ifu_rvbr[32]
    DIRECTION INPUT ;
    USE SIGNAL ;
    PORT
      LAYER metal6 ;
        RECT 206.665 0.000 206.805 0.560 ;
    END
  END cp0_ifu_rvbr[32]
  PIN cp0_ifu_rvbr[33]
    DIRECTION INPUT ;
    USE SIGNAL ;
    PORT
      LAYER metal4 ;
        RECT 206.665 0.000 206.805 0.560 ;
    END
  END cp0_ifu_rvbr[33]
  PIN cp0_ifu_rvbr[34]
    DIRECTION INPUT ;
    USE SIGNAL ;
    PORT
      LAYER metal6 ;
        RECT 205.545 0.000 205.685 0.560 ;
    END
  END cp0_ifu_rvbr[34]
  PIN cp0_ifu_rvbr[35]
    DIRECTION INPUT ;
    USE SIGNAL ;
    PORT
      LAYER metal4 ;
        RECT 205.545 0.000 205.685 0.560 ;
    END
  END cp0_ifu_rvbr[35]
  PIN cp0_ifu_rvbr[36]
    DIRECTION INPUT ;
    USE SIGNAL ;
    PORT
      LAYER metal6 ;
        RECT 204.425 0.000 204.565 0.560 ;
    END
  END cp0_ifu_rvbr[36]
  PIN cp0_ifu_rvbr[37]
    DIRECTION INPUT ;
    USE SIGNAL ;
    PORT
      LAYER metal4 ;
        RECT 204.425 0.000 204.565 0.560 ;
    END
  END cp0_ifu_rvbr[37]
  PIN cp0_ifu_rvbr[38]
    DIRECTION INPUT ;
    USE SIGNAL ;
    PORT
      LAYER metal6 ;
        RECT 203.305 0.000 203.445 0.560 ;
    END
  END cp0_ifu_rvbr[38]
  PIN cp0_ifu_rvbr[39]
    DIRECTION INPUT ;
    USE SIGNAL ;
    PORT
      LAYER metal4 ;
        RECT 203.305 0.000 203.445 0.560 ;
    END
  END cp0_ifu_rvbr[39]
  PIN cp0_ifu_rvbr[3]
    DIRECTION INPUT ;
    USE SIGNAL ;
    PORT
      LAYER metal4 ;
        RECT 223.465 0.000 223.605 0.560 ;
    END
  END cp0_ifu_rvbr[3]
  PIN cp0_ifu_rvbr[4]
    DIRECTION INPUT ;
    USE SIGNAL ;
    PORT
      LAYER metal6 ;
        RECT 222.345 0.000 222.485 0.560 ;
    END
  END cp0_ifu_rvbr[4]
  PIN cp0_ifu_rvbr[5]
    DIRECTION INPUT ;
    USE SIGNAL ;
    PORT
      LAYER metal4 ;
        RECT 222.345 0.000 222.485 0.560 ;
    END
  END cp0_ifu_rvbr[5]
  PIN cp0_ifu_rvbr[6]
    DIRECTION INPUT ;
    USE SIGNAL ;
    PORT
      LAYER metal6 ;
        RECT 221.225 0.000 221.365 0.560 ;
    END
  END cp0_ifu_rvbr[6]
  PIN cp0_ifu_rvbr[7]
    DIRECTION INPUT ;
    USE SIGNAL ;
    PORT
      LAYER metal4 ;
        RECT 221.225 0.000 221.365 0.560 ;
    END
  END cp0_ifu_rvbr[7]
  PIN cp0_ifu_rvbr[8]
    DIRECTION INPUT ;
    USE SIGNAL ;
    PORT
      LAYER metal6 ;
        RECT 220.105 0.000 220.245 0.560 ;
    END
  END cp0_ifu_rvbr[8]
  PIN cp0_ifu_rvbr[9]
    DIRECTION INPUT ;
    USE SIGNAL ;
    PORT
      LAYER metal4 ;
        RECT 220.105 0.000 220.245 0.560 ;
    END
  END cp0_ifu_rvbr[9]
  PIN cp0_ifu_vbr[0]
    DIRECTION INPUT ;
    USE SIGNAL ;
    PORT
      LAYER metal6 ;
        RECT 246.985 0.000 247.125 0.560 ;
    END
  END cp0_ifu_vbr[0]
  PIN cp0_ifu_vbr[10]
    DIRECTION INPUT ;
    USE SIGNAL ;
    PORT
      LAYER metal6 ;
        RECT 241.385 0.000 241.525 0.560 ;
    END
  END cp0_ifu_vbr[10]
  PIN cp0_ifu_vbr[11]
    DIRECTION INPUT ;
    USE SIGNAL ;
    PORT
      LAYER metal4 ;
        RECT 241.385 0.000 241.525 0.560 ;
    END
  END cp0_ifu_vbr[11]
  PIN cp0_ifu_vbr[12]
    DIRECTION INPUT ;
    USE SIGNAL ;
    PORT
      LAYER metal6 ;
        RECT 240.265 0.000 240.405 0.560 ;
    END
  END cp0_ifu_vbr[12]
  PIN cp0_ifu_vbr[13]
    DIRECTION INPUT ;
    USE SIGNAL ;
    PORT
      LAYER metal4 ;
        RECT 240.265 0.000 240.405 0.560 ;
    END
  END cp0_ifu_vbr[13]
  PIN cp0_ifu_vbr[14]
    DIRECTION INPUT ;
    USE SIGNAL ;
    PORT
      LAYER metal6 ;
        RECT 239.145 0.000 239.285 0.560 ;
    END
  END cp0_ifu_vbr[14]
  PIN cp0_ifu_vbr[15]
    DIRECTION INPUT ;
    USE SIGNAL ;
    PORT
      LAYER metal4 ;
        RECT 239.145 0.000 239.285 0.560 ;
    END
  END cp0_ifu_vbr[15]
  PIN cp0_ifu_vbr[16]
    DIRECTION INPUT ;
    USE SIGNAL ;
    PORT
      LAYER metal6 ;
        RECT 238.025 0.000 238.165 0.560 ;
    END
  END cp0_ifu_vbr[16]
  PIN cp0_ifu_vbr[17]
    DIRECTION INPUT ;
    USE SIGNAL ;
    PORT
      LAYER metal4 ;
        RECT 238.025 0.000 238.165 0.560 ;
    END
  END cp0_ifu_vbr[17]
  PIN cp0_ifu_vbr[18]
    DIRECTION INPUT ;
    USE SIGNAL ;
    PORT
      LAYER metal6 ;
        RECT 236.905 0.000 237.045 0.560 ;
    END
  END cp0_ifu_vbr[18]
  PIN cp0_ifu_vbr[19]
    DIRECTION INPUT ;
    USE SIGNAL ;
    PORT
      LAYER metal4 ;
        RECT 236.905 0.000 237.045 0.560 ;
    END
  END cp0_ifu_vbr[19]
  PIN cp0_ifu_vbr[1]
    DIRECTION INPUT ;
    USE SIGNAL ;
    PORT
      LAYER metal4 ;
        RECT 246.985 0.000 247.125 0.560 ;
    END
  END cp0_ifu_vbr[1]
  PIN cp0_ifu_vbr[20]
    DIRECTION INPUT ;
    USE SIGNAL ;
    PORT
      LAYER metal6 ;
        RECT 235.785 0.000 235.925 0.560 ;
    END
  END cp0_ifu_vbr[20]
  PIN cp0_ifu_vbr[21]
    DIRECTION INPUT ;
    USE SIGNAL ;
    PORT
      LAYER metal4 ;
        RECT 235.785 0.000 235.925 0.560 ;
    END
  END cp0_ifu_vbr[21]
  PIN cp0_ifu_vbr[22]
    DIRECTION INPUT ;
    USE SIGNAL ;
    PORT
      LAYER metal6 ;
        RECT 234.665 0.000 234.805 0.560 ;
    END
  END cp0_ifu_vbr[22]
  PIN cp0_ifu_vbr[23]
    DIRECTION INPUT ;
    USE SIGNAL ;
    PORT
      LAYER metal4 ;
        RECT 234.665 0.000 234.805 0.560 ;
    END
  END cp0_ifu_vbr[23]
  PIN cp0_ifu_vbr[24]
    DIRECTION INPUT ;
    USE SIGNAL ;
    PORT
      LAYER metal6 ;
        RECT 233.545 0.000 233.685 0.560 ;
    END
  END cp0_ifu_vbr[24]
  PIN cp0_ifu_vbr[25]
    DIRECTION INPUT ;
    USE SIGNAL ;
    PORT
      LAYER metal4 ;
        RECT 233.545 0.000 233.685 0.560 ;
    END
  END cp0_ifu_vbr[25]
  PIN cp0_ifu_vbr[26]
    DIRECTION INPUT ;
    USE SIGNAL ;
    PORT
      LAYER metal6 ;
        RECT 232.425 0.000 232.565 0.560 ;
    END
  END cp0_ifu_vbr[26]
  PIN cp0_ifu_vbr[27]
    DIRECTION INPUT ;
    USE SIGNAL ;
    PORT
      LAYER metal4 ;
        RECT 232.425 0.000 232.565 0.560 ;
    END
  END cp0_ifu_vbr[27]
  PIN cp0_ifu_vbr[28]
    DIRECTION INPUT ;
    USE SIGNAL ;
    PORT
      LAYER metal6 ;
        RECT 231.305 0.000 231.445 0.560 ;
    END
  END cp0_ifu_vbr[28]
  PIN cp0_ifu_vbr[29]
    DIRECTION INPUT ;
    USE SIGNAL ;
    PORT
      LAYER metal4 ;
        RECT 231.305 0.000 231.445 0.560 ;
    END
  END cp0_ifu_vbr[29]
  PIN cp0_ifu_vbr[2]
    DIRECTION INPUT ;
    USE SIGNAL ;
    PORT
      LAYER metal6 ;
        RECT 245.865 0.000 246.005 0.560 ;
    END
  END cp0_ifu_vbr[2]
  PIN cp0_ifu_vbr[30]
    DIRECTION INPUT ;
    USE SIGNAL ;
    PORT
      LAYER metal6 ;
        RECT 230.185 0.000 230.325 0.560 ;
    END
  END cp0_ifu_vbr[30]
  PIN cp0_ifu_vbr[31]
    DIRECTION INPUT ;
    USE SIGNAL ;
    PORT
      LAYER metal4 ;
        RECT 230.185 0.000 230.325 0.560 ;
    END
  END cp0_ifu_vbr[31]
  PIN cp0_ifu_vbr[32]
    DIRECTION INPUT ;
    USE SIGNAL ;
    PORT
      LAYER metal6 ;
        RECT 229.065 0.000 229.205 0.560 ;
    END
  END cp0_ifu_vbr[32]
  PIN cp0_ifu_vbr[33]
    DIRECTION INPUT ;
    USE SIGNAL ;
    PORT
      LAYER metal4 ;
        RECT 229.065 0.000 229.205 0.560 ;
    END
  END cp0_ifu_vbr[33]
  PIN cp0_ifu_vbr[34]
    DIRECTION INPUT ;
    USE SIGNAL ;
    PORT
      LAYER metal6 ;
        RECT 227.945 0.000 228.085 0.560 ;
    END
  END cp0_ifu_vbr[34]
  PIN cp0_ifu_vbr[35]
    DIRECTION INPUT ;
    USE SIGNAL ;
    PORT
      LAYER metal4 ;
        RECT 227.945 0.000 228.085 0.560 ;
    END
  END cp0_ifu_vbr[35]
  PIN cp0_ifu_vbr[36]
    DIRECTION INPUT ;
    USE SIGNAL ;
    PORT
      LAYER metal6 ;
        RECT 226.825 0.000 226.965 0.560 ;
    END
  END cp0_ifu_vbr[36]
  PIN cp0_ifu_vbr[37]
    DIRECTION INPUT ;
    USE SIGNAL ;
    PORT
      LAYER metal4 ;
        RECT 226.825 0.000 226.965 0.560 ;
    END
  END cp0_ifu_vbr[37]
  PIN cp0_ifu_vbr[38]
    DIRECTION INPUT ;
    USE SIGNAL ;
    PORT
      LAYER metal6 ;
        RECT 225.705 0.000 225.845 0.560 ;
    END
  END cp0_ifu_vbr[38]
  PIN cp0_ifu_vbr[39]
    DIRECTION INPUT ;
    USE SIGNAL ;
    PORT
      LAYER metal4 ;
        RECT 225.705 0.000 225.845 0.560 ;
    END
  END cp0_ifu_vbr[39]
  PIN cp0_ifu_vbr[3]
    DIRECTION INPUT ;
    USE SIGNAL ;
    PORT
      LAYER metal4 ;
        RECT 245.865 0.000 246.005 0.560 ;
    END
  END cp0_ifu_vbr[3]
  PIN cp0_ifu_vbr[4]
    DIRECTION INPUT ;
    USE SIGNAL ;
    PORT
      LAYER metal6 ;
        RECT 244.745 0.000 244.885 0.560 ;
    END
  END cp0_ifu_vbr[4]
  PIN cp0_ifu_vbr[5]
    DIRECTION INPUT ;
    USE SIGNAL ;
    PORT
      LAYER metal4 ;
        RECT 244.745 0.000 244.885 0.560 ;
    END
  END cp0_ifu_vbr[5]
  PIN cp0_ifu_vbr[6]
    DIRECTION INPUT ;
    USE SIGNAL ;
    PORT
      LAYER metal6 ;
        RECT 243.625 0.000 243.765 0.560 ;
    END
  END cp0_ifu_vbr[6]
  PIN cp0_ifu_vbr[7]
    DIRECTION INPUT ;
    USE SIGNAL ;
    PORT
      LAYER metal4 ;
        RECT 243.625 0.000 243.765 0.560 ;
    END
  END cp0_ifu_vbr[7]
  PIN cp0_ifu_vbr[8]
    DIRECTION INPUT ;
    USE SIGNAL ;
    PORT
      LAYER metal6 ;
        RECT 242.505 0.000 242.645 0.560 ;
    END
  END cp0_ifu_vbr[8]
  PIN cp0_ifu_vbr[9]
    DIRECTION INPUT ;
    USE SIGNAL ;
    PORT
      LAYER metal4 ;
        RECT 242.505 0.000 242.645 0.560 ;
    END
  END cp0_ifu_vbr[9]
  PIN cp0_ifu_vl[0]
    DIRECTION INPUT ;
    USE SIGNAL ;
    PORT
      LAYER metal6 ;
        RECT 251.465 0.000 251.605 0.560 ;
    END
  END cp0_ifu_vl[0]
  PIN cp0_ifu_vl[1]
    DIRECTION INPUT ;
    USE SIGNAL ;
    PORT
      LAYER metal4 ;
        RECT 251.465 0.000 251.605 0.560 ;
    END
  END cp0_ifu_vl[1]
  PIN cp0_ifu_vl[2]
    DIRECTION INPUT ;
    USE SIGNAL ;
    PORT
      LAYER metal6 ;
        RECT 250.345 0.000 250.485 0.560 ;
    END
  END cp0_ifu_vl[2]
  PIN cp0_ifu_vl[3]
    DIRECTION INPUT ;
    USE SIGNAL ;
    PORT
      LAYER metal4 ;
        RECT 250.345 0.000 250.485 0.560 ;
    END
  END cp0_ifu_vl[3]
  PIN cp0_ifu_vl[4]
    DIRECTION INPUT ;
    USE SIGNAL ;
    PORT
      LAYER metal6 ;
        RECT 249.225 0.000 249.365 0.560 ;
    END
  END cp0_ifu_vl[4]
  PIN cp0_ifu_vl[5]
    DIRECTION INPUT ;
    USE SIGNAL ;
    PORT
      LAYER metal4 ;
        RECT 249.225 0.000 249.365 0.560 ;
    END
  END cp0_ifu_vl[5]
  PIN cp0_ifu_vl[6]
    DIRECTION INPUT ;
    USE SIGNAL ;
    PORT
      LAYER metal6 ;
        RECT 248.105 0.000 248.245 0.560 ;
    END
  END cp0_ifu_vl[6]
  PIN cp0_ifu_vl[7]
    DIRECTION INPUT ;
    USE SIGNAL ;
    PORT
      LAYER metal4 ;
        RECT 248.105 0.000 248.245 0.560 ;
    END
  END cp0_ifu_vl[7]
  PIN cp0_ifu_vlmul[0]
    DIRECTION INPUT ;
    USE SIGNAL ;
    PORT
      LAYER metal6 ;
        RECT 252.585 0.000 252.725 0.560 ;
    END
  END cp0_ifu_vlmul[0]
  PIN cp0_ifu_vlmul[1]
    DIRECTION INPUT ;
    USE SIGNAL ;
    PORT
      LAYER metal4 ;
        RECT 252.585 0.000 252.725 0.560 ;
    END
  END cp0_ifu_vlmul[1]
  PIN cp0_ifu_vsetvli_pred_disable
    DIRECTION INPUT ;
    USE SIGNAL ;
    PORT
      LAYER metal4 ;
        RECT 253.705 0.000 253.845 0.560 ;
    END
  END cp0_ifu_vsetvli_pred_disable
  PIN cp0_ifu_vsetvli_pred_mode
    DIRECTION INPUT ;
    USE SIGNAL ;
    PORT
      LAYER metal6 ;
        RECT 253.705 0.000 253.845 0.560 ;
    END
  END cp0_ifu_vsetvli_pred_mode
  PIN cp0_ifu_vsew[0]
    DIRECTION INPUT ;
    USE SIGNAL ;
    PORT
      LAYER metal4 ;
        RECT 255.945 0.000 256.085 0.560 ;
    END
  END cp0_ifu_vsew[0]
  PIN cp0_ifu_vsew[1]
    DIRECTION INPUT ;
    USE SIGNAL ;
    PORT
      LAYER metal6 ;
        RECT 254.825 0.000 254.965 0.560 ;
    END
  END cp0_ifu_vsew[1]
  PIN cp0_ifu_vsew[2]
    DIRECTION INPUT ;
    USE SIGNAL ;
    PORT
      LAYER metal4 ;
        RECT 254.825 0.000 254.965 0.560 ;
    END
  END cp0_ifu_vsew[2]
  PIN cp0_yy_clk_en
    DIRECTION INPUT ;
    USE SIGNAL ;
    PORT
      LAYER metal6 ;
        RECT 255.945 0.000 256.085 0.560 ;
    END
  END cp0_yy_clk_en
  PIN cp0_yy_priv_mode[0]
    DIRECTION INPUT ;
    USE SIGNAL ;
    PORT
      LAYER metal6 ;
        RECT 257.065 0.000 257.205 0.560 ;
    END
  END cp0_yy_priv_mode[0]
  PIN cp0_yy_priv_mode[1]
    DIRECTION INPUT ;
    USE SIGNAL ;
    PORT
      LAYER metal4 ;
        RECT 257.065 0.000 257.205 0.560 ;
    END
  END cp0_yy_priv_mode[1]
  PIN cpurst_b
    DIRECTION INPUT ;
    USE SIGNAL ;
    PORT
      LAYER metal4 ;
        RECT 258.185 0.000 258.325 0.560 ;
    END
  END cpurst_b
  PIN forever_cpuclk
    DIRECTION INPUT ;
    USE CLOCK ;
    PORT
      LAYER metal6 ;
        RECT 678.465 0.000 678.605 0.560 ;
    END
  END forever_cpuclk
  PIN had_ifu_ir[0]
    DIRECTION INPUT ;
    USE SIGNAL ;
    PORT
      LAYER metal4 ;
        RECT 276.105 0.000 276.245 0.560 ;
    END
  END had_ifu_ir[0]
  PIN had_ifu_ir[10]
    DIRECTION INPUT ;
    USE SIGNAL ;
    PORT
      LAYER metal4 ;
        RECT 270.505 0.000 270.645 0.560 ;
    END
  END had_ifu_ir[10]
  PIN had_ifu_ir[11]
    DIRECTION INPUT ;
    USE SIGNAL ;
    PORT
      LAYER metal6 ;
        RECT 269.385 0.000 269.525 0.560 ;
    END
  END had_ifu_ir[11]
  PIN had_ifu_ir[12]
    DIRECTION INPUT ;
    USE SIGNAL ;
    PORT
      LAYER metal4 ;
        RECT 269.385 0.000 269.525 0.560 ;
    END
  END had_ifu_ir[12]
  PIN had_ifu_ir[13]
    DIRECTION INPUT ;
    USE SIGNAL ;
    PORT
      LAYER metal6 ;
        RECT 268.265 0.000 268.405 0.560 ;
    END
  END had_ifu_ir[13]
  PIN had_ifu_ir[14]
    DIRECTION INPUT ;
    USE SIGNAL ;
    PORT
      LAYER metal4 ;
        RECT 268.265 0.000 268.405 0.560 ;
    END
  END had_ifu_ir[14]
  PIN had_ifu_ir[15]
    DIRECTION INPUT ;
    USE SIGNAL ;
    PORT
      LAYER metal6 ;
        RECT 267.145 0.000 267.285 0.560 ;
    END
  END had_ifu_ir[15]
  PIN had_ifu_ir[16]
    DIRECTION INPUT ;
    USE SIGNAL ;
    PORT
      LAYER metal4 ;
        RECT 267.145 0.000 267.285 0.560 ;
    END
  END had_ifu_ir[16]
  PIN had_ifu_ir[17]
    DIRECTION INPUT ;
    USE SIGNAL ;
    PORT
      LAYER metal6 ;
        RECT 266.025 0.000 266.165 0.560 ;
    END
  END had_ifu_ir[17]
  PIN had_ifu_ir[18]
    DIRECTION INPUT ;
    USE SIGNAL ;
    PORT
      LAYER metal4 ;
        RECT 266.025 0.000 266.165 0.560 ;
    END
  END had_ifu_ir[18]
  PIN had_ifu_ir[19]
    DIRECTION INPUT ;
    USE SIGNAL ;
    PORT
      LAYER metal6 ;
        RECT 264.905 0.000 265.045 0.560 ;
    END
  END had_ifu_ir[19]
  PIN had_ifu_ir[1]
    DIRECTION INPUT ;
    USE SIGNAL ;
    PORT
      LAYER metal6 ;
        RECT 274.985 0.000 275.125 0.560 ;
    END
  END had_ifu_ir[1]
  PIN had_ifu_ir[20]
    DIRECTION INPUT ;
    USE SIGNAL ;
    PORT
      LAYER metal4 ;
        RECT 264.905 0.000 265.045 0.560 ;
    END
  END had_ifu_ir[20]
  PIN had_ifu_ir[21]
    DIRECTION INPUT ;
    USE SIGNAL ;
    PORT
      LAYER metal6 ;
        RECT 263.785 0.000 263.925 0.560 ;
    END
  END had_ifu_ir[21]
  PIN had_ifu_ir[22]
    DIRECTION INPUT ;
    USE SIGNAL ;
    PORT
      LAYER metal4 ;
        RECT 263.785 0.000 263.925 0.560 ;
    END
  END had_ifu_ir[22]
  PIN had_ifu_ir[23]
    DIRECTION INPUT ;
    USE SIGNAL ;
    PORT
      LAYER metal6 ;
        RECT 262.665 0.000 262.805 0.560 ;
    END
  END had_ifu_ir[23]
  PIN had_ifu_ir[24]
    DIRECTION INPUT ;
    USE SIGNAL ;
    PORT
      LAYER metal4 ;
        RECT 262.665 0.000 262.805 0.560 ;
    END
  END had_ifu_ir[24]
  PIN had_ifu_ir[25]
    DIRECTION INPUT ;
    USE SIGNAL ;
    PORT
      LAYER metal6 ;
        RECT 261.545 0.000 261.685 0.560 ;
    END
  END had_ifu_ir[25]
  PIN had_ifu_ir[26]
    DIRECTION INPUT ;
    USE SIGNAL ;
    PORT
      LAYER metal4 ;
        RECT 261.545 0.000 261.685 0.560 ;
    END
  END had_ifu_ir[26]
  PIN had_ifu_ir[27]
    DIRECTION INPUT ;
    USE SIGNAL ;
    PORT
      LAYER metal6 ;
        RECT 260.425 0.000 260.565 0.560 ;
    END
  END had_ifu_ir[27]
  PIN had_ifu_ir[28]
    DIRECTION INPUT ;
    USE SIGNAL ;
    PORT
      LAYER metal4 ;
        RECT 260.425 0.000 260.565 0.560 ;
    END
  END had_ifu_ir[28]
  PIN had_ifu_ir[29]
    DIRECTION INPUT ;
    USE SIGNAL ;
    PORT
      LAYER metal6 ;
        RECT 259.305 0.000 259.445 0.560 ;
    END
  END had_ifu_ir[29]
  PIN had_ifu_ir[2]
    DIRECTION INPUT ;
    USE SIGNAL ;
    PORT
      LAYER metal4 ;
        RECT 274.985 0.000 275.125 0.560 ;
    END
  END had_ifu_ir[2]
  PIN had_ifu_ir[30]
    DIRECTION INPUT ;
    USE SIGNAL ;
    PORT
      LAYER metal4 ;
        RECT 259.305 0.000 259.445 0.560 ;
    END
  END had_ifu_ir[30]
  PIN had_ifu_ir[31]
    DIRECTION INPUT ;
    USE SIGNAL ;
    PORT
      LAYER metal6 ;
        RECT 258.185 0.000 258.325 0.560 ;
    END
  END had_ifu_ir[31]
  PIN had_ifu_ir[3]
    DIRECTION INPUT ;
    USE SIGNAL ;
    PORT
      LAYER metal6 ;
        RECT 273.865 0.000 274.005 0.560 ;
    END
  END had_ifu_ir[3]
  PIN had_ifu_ir[4]
    DIRECTION INPUT ;
    USE SIGNAL ;
    PORT
      LAYER metal4 ;
        RECT 273.865 0.000 274.005 0.560 ;
    END
  END had_ifu_ir[4]
  PIN had_ifu_ir[5]
    DIRECTION INPUT ;
    USE SIGNAL ;
    PORT
      LAYER metal6 ;
        RECT 272.745 0.000 272.885 0.560 ;
    END
  END had_ifu_ir[5]
  PIN had_ifu_ir[6]
    DIRECTION INPUT ;
    USE SIGNAL ;
    PORT
      LAYER metal4 ;
        RECT 272.745 0.000 272.885 0.560 ;
    END
  END had_ifu_ir[6]
  PIN had_ifu_ir[7]
    DIRECTION INPUT ;
    USE SIGNAL ;
    PORT
      LAYER metal6 ;
        RECT 271.625 0.000 271.765 0.560 ;
    END
  END had_ifu_ir[7]
  PIN had_ifu_ir[8]
    DIRECTION INPUT ;
    USE SIGNAL ;
    PORT
      LAYER metal4 ;
        RECT 271.625 0.000 271.765 0.560 ;
    END
  END had_ifu_ir[8]
  PIN had_ifu_ir[9]
    DIRECTION INPUT ;
    USE SIGNAL ;
    PORT
      LAYER metal6 ;
        RECT 270.505 0.000 270.645 0.560 ;
    END
  END had_ifu_ir[9]
  PIN had_ifu_ir_vld
    DIRECTION INPUT ;
    USE SIGNAL ;
    PORT
      LAYER metal6 ;
        RECT 276.105 0.000 276.245 0.560 ;
    END
  END had_ifu_ir_vld
  PIN had_ifu_pc[0]
    DIRECTION INPUT ;
    USE SIGNAL ;
    PORT
      LAYER metal4 ;
        RECT 298.505 0.000 298.645 0.560 ;
    END
  END had_ifu_pc[0]
  PIN had_ifu_pc[10]
    DIRECTION INPUT ;
    USE SIGNAL ;
    PORT
      LAYER metal4 ;
        RECT 292.905 0.000 293.045 0.560 ;
    END
  END had_ifu_pc[10]
  PIN had_ifu_pc[11]
    DIRECTION INPUT ;
    USE SIGNAL ;
    PORT
      LAYER metal6 ;
        RECT 291.785 0.000 291.925 0.560 ;
    END
  END had_ifu_pc[11]
  PIN had_ifu_pc[12]
    DIRECTION INPUT ;
    USE SIGNAL ;
    PORT
      LAYER metal4 ;
        RECT 291.785 0.000 291.925 0.560 ;
    END
  END had_ifu_pc[12]
  PIN had_ifu_pc[13]
    DIRECTION INPUT ;
    USE SIGNAL ;
    PORT
      LAYER metal6 ;
        RECT 290.665 0.000 290.805 0.560 ;
    END
  END had_ifu_pc[13]
  PIN had_ifu_pc[14]
    DIRECTION INPUT ;
    USE SIGNAL ;
    PORT
      LAYER metal4 ;
        RECT 290.665 0.000 290.805 0.560 ;
    END
  END had_ifu_pc[14]
  PIN had_ifu_pc[15]
    DIRECTION INPUT ;
    USE SIGNAL ;
    PORT
      LAYER metal6 ;
        RECT 289.545 0.000 289.685 0.560 ;
    END
  END had_ifu_pc[15]
  PIN had_ifu_pc[16]
    DIRECTION INPUT ;
    USE SIGNAL ;
    PORT
      LAYER metal4 ;
        RECT 289.545 0.000 289.685 0.560 ;
    END
  END had_ifu_pc[16]
  PIN had_ifu_pc[17]
    DIRECTION INPUT ;
    USE SIGNAL ;
    PORT
      LAYER metal6 ;
        RECT 288.425 0.000 288.565 0.560 ;
    END
  END had_ifu_pc[17]
  PIN had_ifu_pc[18]
    DIRECTION INPUT ;
    USE SIGNAL ;
    PORT
      LAYER metal4 ;
        RECT 288.425 0.000 288.565 0.560 ;
    END
  END had_ifu_pc[18]
  PIN had_ifu_pc[19]
    DIRECTION INPUT ;
    USE SIGNAL ;
    PORT
      LAYER metal6 ;
        RECT 287.305 0.000 287.445 0.560 ;
    END
  END had_ifu_pc[19]
  PIN had_ifu_pc[1]
    DIRECTION INPUT ;
    USE SIGNAL ;
    PORT
      LAYER metal6 ;
        RECT 297.385 0.000 297.525 0.560 ;
    END
  END had_ifu_pc[1]
  PIN had_ifu_pc[20]
    DIRECTION INPUT ;
    USE SIGNAL ;
    PORT
      LAYER metal4 ;
        RECT 287.305 0.000 287.445 0.560 ;
    END
  END had_ifu_pc[20]
  PIN had_ifu_pc[21]
    DIRECTION INPUT ;
    USE SIGNAL ;
    PORT
      LAYER metal6 ;
        RECT 286.185 0.000 286.325 0.560 ;
    END
  END had_ifu_pc[21]
  PIN had_ifu_pc[22]
    DIRECTION INPUT ;
    USE SIGNAL ;
    PORT
      LAYER metal4 ;
        RECT 286.185 0.000 286.325 0.560 ;
    END
  END had_ifu_pc[22]
  PIN had_ifu_pc[23]
    DIRECTION INPUT ;
    USE SIGNAL ;
    PORT
      LAYER metal6 ;
        RECT 285.065 0.000 285.205 0.560 ;
    END
  END had_ifu_pc[23]
  PIN had_ifu_pc[24]
    DIRECTION INPUT ;
    USE SIGNAL ;
    PORT
      LAYER metal4 ;
        RECT 285.065 0.000 285.205 0.560 ;
    END
  END had_ifu_pc[24]
  PIN had_ifu_pc[25]
    DIRECTION INPUT ;
    USE SIGNAL ;
    PORT
      LAYER metal6 ;
        RECT 283.945 0.000 284.085 0.560 ;
    END
  END had_ifu_pc[25]
  PIN had_ifu_pc[26]
    DIRECTION INPUT ;
    USE SIGNAL ;
    PORT
      LAYER metal4 ;
        RECT 283.945 0.000 284.085 0.560 ;
    END
  END had_ifu_pc[26]
  PIN had_ifu_pc[27]
    DIRECTION INPUT ;
    USE SIGNAL ;
    PORT
      LAYER metal6 ;
        RECT 282.825 0.000 282.965 0.560 ;
    END
  END had_ifu_pc[27]
  PIN had_ifu_pc[28]
    DIRECTION INPUT ;
    USE SIGNAL ;
    PORT
      LAYER metal4 ;
        RECT 282.825 0.000 282.965 0.560 ;
    END
  END had_ifu_pc[28]
  PIN had_ifu_pc[29]
    DIRECTION INPUT ;
    USE SIGNAL ;
    PORT
      LAYER metal6 ;
        RECT 281.705 0.000 281.845 0.560 ;
    END
  END had_ifu_pc[29]
  PIN had_ifu_pc[2]
    DIRECTION INPUT ;
    USE SIGNAL ;
    PORT
      LAYER metal4 ;
        RECT 297.385 0.000 297.525 0.560 ;
    END
  END had_ifu_pc[2]
  PIN had_ifu_pc[30]
    DIRECTION INPUT ;
    USE SIGNAL ;
    PORT
      LAYER metal4 ;
        RECT 281.705 0.000 281.845 0.560 ;
    END
  END had_ifu_pc[30]
  PIN had_ifu_pc[31]
    DIRECTION INPUT ;
    USE SIGNAL ;
    PORT
      LAYER metal6 ;
        RECT 280.585 0.000 280.725 0.560 ;
    END
  END had_ifu_pc[31]
  PIN had_ifu_pc[32]
    DIRECTION INPUT ;
    USE SIGNAL ;
    PORT
      LAYER metal4 ;
        RECT 280.585 0.000 280.725 0.560 ;
    END
  END had_ifu_pc[32]
  PIN had_ifu_pc[33]
    DIRECTION INPUT ;
    USE SIGNAL ;
    PORT
      LAYER metal6 ;
        RECT 279.465 0.000 279.605 0.560 ;
    END
  END had_ifu_pc[33]
  PIN had_ifu_pc[34]
    DIRECTION INPUT ;
    USE SIGNAL ;
    PORT
      LAYER metal4 ;
        RECT 279.465 0.000 279.605 0.560 ;
    END
  END had_ifu_pc[34]
  PIN had_ifu_pc[35]
    DIRECTION INPUT ;
    USE SIGNAL ;
    PORT
      LAYER metal6 ;
        RECT 278.345 0.000 278.485 0.560 ;
    END
  END had_ifu_pc[35]
  PIN had_ifu_pc[36]
    DIRECTION INPUT ;
    USE SIGNAL ;
    PORT
      LAYER metal4 ;
        RECT 278.345 0.000 278.485 0.560 ;
    END
  END had_ifu_pc[36]
  PIN had_ifu_pc[37]
    DIRECTION INPUT ;
    USE SIGNAL ;
    PORT
      LAYER metal6 ;
        RECT 277.225 0.000 277.365 0.560 ;
    END
  END had_ifu_pc[37]
  PIN had_ifu_pc[38]
    DIRECTION INPUT ;
    USE SIGNAL ;
    PORT
      LAYER metal4 ;
        RECT 277.225 0.000 277.365 0.560 ;
    END
  END had_ifu_pc[38]
  PIN had_ifu_pc[3]
    DIRECTION INPUT ;
    USE SIGNAL ;
    PORT
      LAYER metal6 ;
        RECT 296.265 0.000 296.405 0.560 ;
    END
  END had_ifu_pc[3]
  PIN had_ifu_pc[4]
    DIRECTION INPUT ;
    USE SIGNAL ;
    PORT
      LAYER metal4 ;
        RECT 296.265 0.000 296.405 0.560 ;
    END
  END had_ifu_pc[4]
  PIN had_ifu_pc[5]
    DIRECTION INPUT ;
    USE SIGNAL ;
    PORT
      LAYER metal6 ;
        RECT 295.145 0.000 295.285 0.560 ;
    END
  END had_ifu_pc[5]
  PIN had_ifu_pc[6]
    DIRECTION INPUT ;
    USE SIGNAL ;
    PORT
      LAYER metal4 ;
        RECT 295.145 0.000 295.285 0.560 ;
    END
  END had_ifu_pc[6]
  PIN had_ifu_pc[7]
    DIRECTION INPUT ;
    USE SIGNAL ;
    PORT
      LAYER metal6 ;
        RECT 294.025 0.000 294.165 0.560 ;
    END
  END had_ifu_pc[7]
  PIN had_ifu_pc[8]
    DIRECTION INPUT ;
    USE SIGNAL ;
    PORT
      LAYER metal4 ;
        RECT 294.025 0.000 294.165 0.560 ;
    END
  END had_ifu_pc[8]
  PIN had_ifu_pc[9]
    DIRECTION INPUT ;
    USE SIGNAL ;
    PORT
      LAYER metal6 ;
        RECT 292.905 0.000 293.045 0.560 ;
    END
  END had_ifu_pc[9]
  PIN had_ifu_pcload
    DIRECTION INPUT ;
    USE SIGNAL ;
    PORT
      LAYER metal6 ;
        RECT 298.505 0.000 298.645 0.560 ;
    END
  END had_ifu_pcload
  PIN had_rtu_xx_jdbreq
    DIRECTION INPUT ;
    USE SIGNAL ;
    PORT
      LAYER metal4 ;
        RECT 299.625 0.000 299.765 0.560 ;
    END
  END had_rtu_xx_jdbreq
  PIN had_yy_xx_bkpta_base[0]
    DIRECTION INPUT ;
    USE SIGNAL ;
    PORT
      LAYER metal4 ;
        RECT 322.025 0.000 322.165 0.560 ;
    END
  END had_yy_xx_bkpta_base[0]
  PIN had_yy_xx_bkpta_base[10]
    DIRECTION INPUT ;
    USE SIGNAL ;
    PORT
      LAYER metal4 ;
        RECT 316.425 0.000 316.565 0.560 ;
    END
  END had_yy_xx_bkpta_base[10]
  PIN had_yy_xx_bkpta_base[11]
    DIRECTION INPUT ;
    USE SIGNAL ;
    PORT
      LAYER metal6 ;
        RECT 315.305 0.000 315.445 0.560 ;
    END
  END had_yy_xx_bkpta_base[11]
  PIN had_yy_xx_bkpta_base[12]
    DIRECTION INPUT ;
    USE SIGNAL ;
    PORT
      LAYER metal4 ;
        RECT 315.305 0.000 315.445 0.560 ;
    END
  END had_yy_xx_bkpta_base[12]
  PIN had_yy_xx_bkpta_base[13]
    DIRECTION INPUT ;
    USE SIGNAL ;
    PORT
      LAYER metal6 ;
        RECT 314.185 0.000 314.325 0.560 ;
    END
  END had_yy_xx_bkpta_base[13]
  PIN had_yy_xx_bkpta_base[14]
    DIRECTION INPUT ;
    USE SIGNAL ;
    PORT
      LAYER metal4 ;
        RECT 314.185 0.000 314.325 0.560 ;
    END
  END had_yy_xx_bkpta_base[14]
  PIN had_yy_xx_bkpta_base[15]
    DIRECTION INPUT ;
    USE SIGNAL ;
    PORT
      LAYER metal6 ;
        RECT 313.065 0.000 313.205 0.560 ;
    END
  END had_yy_xx_bkpta_base[15]
  PIN had_yy_xx_bkpta_base[16]
    DIRECTION INPUT ;
    USE SIGNAL ;
    PORT
      LAYER metal4 ;
        RECT 313.065 0.000 313.205 0.560 ;
    END
  END had_yy_xx_bkpta_base[16]
  PIN had_yy_xx_bkpta_base[17]
    DIRECTION INPUT ;
    USE SIGNAL ;
    PORT
      LAYER metal6 ;
        RECT 311.945 0.000 312.085 0.560 ;
    END
  END had_yy_xx_bkpta_base[17]
  PIN had_yy_xx_bkpta_base[18]
    DIRECTION INPUT ;
    USE SIGNAL ;
    PORT
      LAYER metal4 ;
        RECT 311.945 0.000 312.085 0.560 ;
    END
  END had_yy_xx_bkpta_base[18]
  PIN had_yy_xx_bkpta_base[19]
    DIRECTION INPUT ;
    USE SIGNAL ;
    PORT
      LAYER metal6 ;
        RECT 310.825 0.000 310.965 0.560 ;
    END
  END had_yy_xx_bkpta_base[19]
  PIN had_yy_xx_bkpta_base[1]
    DIRECTION INPUT ;
    USE SIGNAL ;
    PORT
      LAYER metal6 ;
        RECT 320.905 0.000 321.045 0.560 ;
    END
  END had_yy_xx_bkpta_base[1]
  PIN had_yy_xx_bkpta_base[20]
    DIRECTION INPUT ;
    USE SIGNAL ;
    PORT
      LAYER metal4 ;
        RECT 310.825 0.000 310.965 0.560 ;
    END
  END had_yy_xx_bkpta_base[20]
  PIN had_yy_xx_bkpta_base[21]
    DIRECTION INPUT ;
    USE SIGNAL ;
    PORT
      LAYER metal6 ;
        RECT 309.705 0.000 309.845 0.560 ;
    END
  END had_yy_xx_bkpta_base[21]
  PIN had_yy_xx_bkpta_base[22]
    DIRECTION INPUT ;
    USE SIGNAL ;
    PORT
      LAYER metal4 ;
        RECT 309.705 0.000 309.845 0.560 ;
    END
  END had_yy_xx_bkpta_base[22]
  PIN had_yy_xx_bkpta_base[23]
    DIRECTION INPUT ;
    USE SIGNAL ;
    PORT
      LAYER metal6 ;
        RECT 308.585 0.000 308.725 0.560 ;
    END
  END had_yy_xx_bkpta_base[23]
  PIN had_yy_xx_bkpta_base[24]
    DIRECTION INPUT ;
    USE SIGNAL ;
    PORT
      LAYER metal4 ;
        RECT 308.585 0.000 308.725 0.560 ;
    END
  END had_yy_xx_bkpta_base[24]
  PIN had_yy_xx_bkpta_base[25]
    DIRECTION INPUT ;
    USE SIGNAL ;
    PORT
      LAYER metal6 ;
        RECT 307.465 0.000 307.605 0.560 ;
    END
  END had_yy_xx_bkpta_base[25]
  PIN had_yy_xx_bkpta_base[26]
    DIRECTION INPUT ;
    USE SIGNAL ;
    PORT
      LAYER metal4 ;
        RECT 307.465 0.000 307.605 0.560 ;
    END
  END had_yy_xx_bkpta_base[26]
  PIN had_yy_xx_bkpta_base[27]
    DIRECTION INPUT ;
    USE SIGNAL ;
    PORT
      LAYER metal6 ;
        RECT 306.345 0.000 306.485 0.560 ;
    END
  END had_yy_xx_bkpta_base[27]
  PIN had_yy_xx_bkpta_base[28]
    DIRECTION INPUT ;
    USE SIGNAL ;
    PORT
      LAYER metal4 ;
        RECT 306.345 0.000 306.485 0.560 ;
    END
  END had_yy_xx_bkpta_base[28]
  PIN had_yy_xx_bkpta_base[29]
    DIRECTION INPUT ;
    USE SIGNAL ;
    PORT
      LAYER metal6 ;
        RECT 305.225 0.000 305.365 0.560 ;
    END
  END had_yy_xx_bkpta_base[29]
  PIN had_yy_xx_bkpta_base[2]
    DIRECTION INPUT ;
    USE SIGNAL ;
    PORT
      LAYER metal4 ;
        RECT 320.905 0.000 321.045 0.560 ;
    END
  END had_yy_xx_bkpta_base[2]
  PIN had_yy_xx_bkpta_base[30]
    DIRECTION INPUT ;
    USE SIGNAL ;
    PORT
      LAYER metal4 ;
        RECT 305.225 0.000 305.365 0.560 ;
    END
  END had_yy_xx_bkpta_base[30]
  PIN had_yy_xx_bkpta_base[31]
    DIRECTION INPUT ;
    USE SIGNAL ;
    PORT
      LAYER metal6 ;
        RECT 304.105 0.000 304.245 0.560 ;
    END
  END had_yy_xx_bkpta_base[31]
  PIN had_yy_xx_bkpta_base[32]
    DIRECTION INPUT ;
    USE SIGNAL ;
    PORT
      LAYER metal4 ;
        RECT 304.105 0.000 304.245 0.560 ;
    END
  END had_yy_xx_bkpta_base[32]
  PIN had_yy_xx_bkpta_base[33]
    DIRECTION INPUT ;
    USE SIGNAL ;
    PORT
      LAYER metal6 ;
        RECT 302.985 0.000 303.125 0.560 ;
    END
  END had_yy_xx_bkpta_base[33]
  PIN had_yy_xx_bkpta_base[34]
    DIRECTION INPUT ;
    USE SIGNAL ;
    PORT
      LAYER metal4 ;
        RECT 302.985 0.000 303.125 0.560 ;
    END
  END had_yy_xx_bkpta_base[34]
  PIN had_yy_xx_bkpta_base[35]
    DIRECTION INPUT ;
    USE SIGNAL ;
    PORT
      LAYER metal6 ;
        RECT 301.865 0.000 302.005 0.560 ;
    END
  END had_yy_xx_bkpta_base[35]
  PIN had_yy_xx_bkpta_base[36]
    DIRECTION INPUT ;
    USE SIGNAL ;
    PORT
      LAYER metal4 ;
        RECT 301.865 0.000 302.005 0.560 ;
    END
  END had_yy_xx_bkpta_base[36]
  PIN had_yy_xx_bkpta_base[37]
    DIRECTION INPUT ;
    USE SIGNAL ;
    PORT
      LAYER metal6 ;
        RECT 300.745 0.000 300.885 0.560 ;
    END
  END had_yy_xx_bkpta_base[37]
  PIN had_yy_xx_bkpta_base[38]
    DIRECTION INPUT ;
    USE SIGNAL ;
    PORT
      LAYER metal4 ;
        RECT 300.745 0.000 300.885 0.560 ;
    END
  END had_yy_xx_bkpta_base[38]
  PIN had_yy_xx_bkpta_base[39]
    DIRECTION INPUT ;
    USE SIGNAL ;
    PORT
      LAYER metal6 ;
        RECT 299.625 0.000 299.765 0.560 ;
    END
  END had_yy_xx_bkpta_base[39]
  PIN had_yy_xx_bkpta_base[3]
    DIRECTION INPUT ;
    USE SIGNAL ;
    PORT
      LAYER metal6 ;
        RECT 319.785 0.000 319.925 0.560 ;
    END
  END had_yy_xx_bkpta_base[3]
  PIN had_yy_xx_bkpta_base[4]
    DIRECTION INPUT ;
    USE SIGNAL ;
    PORT
      LAYER metal4 ;
        RECT 319.785 0.000 319.925 0.560 ;
    END
  END had_yy_xx_bkpta_base[4]
  PIN had_yy_xx_bkpta_base[5]
    DIRECTION INPUT ;
    USE SIGNAL ;
    PORT
      LAYER metal6 ;
        RECT 318.665 0.000 318.805 0.560 ;
    END
  END had_yy_xx_bkpta_base[5]
  PIN had_yy_xx_bkpta_base[6]
    DIRECTION INPUT ;
    USE SIGNAL ;
    PORT
      LAYER metal4 ;
        RECT 318.665 0.000 318.805 0.560 ;
    END
  END had_yy_xx_bkpta_base[6]
  PIN had_yy_xx_bkpta_base[7]
    DIRECTION INPUT ;
    USE SIGNAL ;
    PORT
      LAYER metal6 ;
        RECT 317.545 0.000 317.685 0.560 ;
    END
  END had_yy_xx_bkpta_base[7]
  PIN had_yy_xx_bkpta_base[8]
    DIRECTION INPUT ;
    USE SIGNAL ;
    PORT
      LAYER metal4 ;
        RECT 317.545 0.000 317.685 0.560 ;
    END
  END had_yy_xx_bkpta_base[8]
  PIN had_yy_xx_bkpta_base[9]
    DIRECTION INPUT ;
    USE SIGNAL ;
    PORT
      LAYER metal6 ;
        RECT 316.425 0.000 316.565 0.560 ;
    END
  END had_yy_xx_bkpta_base[9]
  PIN had_yy_xx_bkpta_mask[0]
    DIRECTION INPUT ;
    USE SIGNAL ;
    PORT
      LAYER metal4 ;
        RECT 326.505 0.000 326.645 0.560 ;
    END
  END had_yy_xx_bkpta_mask[0]
  PIN had_yy_xx_bkpta_mask[1]
    DIRECTION INPUT ;
    USE SIGNAL ;
    PORT
      LAYER metal6 ;
        RECT 325.385 0.000 325.525 0.560 ;
    END
  END had_yy_xx_bkpta_mask[1]
  PIN had_yy_xx_bkpta_mask[2]
    DIRECTION INPUT ;
    USE SIGNAL ;
    PORT
      LAYER metal4 ;
        RECT 325.385 0.000 325.525 0.560 ;
    END
  END had_yy_xx_bkpta_mask[2]
  PIN had_yy_xx_bkpta_mask[3]
    DIRECTION INPUT ;
    USE SIGNAL ;
    PORT
      LAYER metal6 ;
        RECT 324.265 0.000 324.405 0.560 ;
    END
  END had_yy_xx_bkpta_mask[3]
  PIN had_yy_xx_bkpta_mask[4]
    DIRECTION INPUT ;
    USE SIGNAL ;
    PORT
      LAYER metal4 ;
        RECT 324.265 0.000 324.405 0.560 ;
    END
  END had_yy_xx_bkpta_mask[4]
  PIN had_yy_xx_bkpta_mask[5]
    DIRECTION INPUT ;
    USE SIGNAL ;
    PORT
      LAYER metal6 ;
        RECT 323.145 0.000 323.285 0.560 ;
    END
  END had_yy_xx_bkpta_mask[5]
  PIN had_yy_xx_bkpta_mask[6]
    DIRECTION INPUT ;
    USE SIGNAL ;
    PORT
      LAYER metal4 ;
        RECT 323.145 0.000 323.285 0.560 ;
    END
  END had_yy_xx_bkpta_mask[6]
  PIN had_yy_xx_bkpta_mask[7]
    DIRECTION INPUT ;
    USE SIGNAL ;
    PORT
      LAYER metal6 ;
        RECT 322.025 0.000 322.165 0.560 ;
    END
  END had_yy_xx_bkpta_mask[7]
  PIN had_yy_xx_bkpta_rc
    DIRECTION INPUT ;
    USE SIGNAL ;
    PORT
      LAYER metal6 ;
        RECT 326.505 0.000 326.645 0.560 ;
    END
  END had_yy_xx_bkpta_rc
  PIN had_yy_xx_bkptb_base[0]
    DIRECTION INPUT ;
    USE SIGNAL ;
    PORT
      LAYER metal6 ;
        RECT 348.905 0.000 349.045 0.560 ;
    END
  END had_yy_xx_bkptb_base[0]
  PIN had_yy_xx_bkptb_base[10]
    DIRECTION INPUT ;
    USE SIGNAL ;
    PORT
      LAYER metal6 ;
        RECT 343.305 0.000 343.445 0.560 ;
    END
  END had_yy_xx_bkptb_base[10]
  PIN had_yy_xx_bkptb_base[11]
    DIRECTION INPUT ;
    USE SIGNAL ;
    PORT
      LAYER metal4 ;
        RECT 343.305 0.000 343.445 0.560 ;
    END
  END had_yy_xx_bkptb_base[11]
  PIN had_yy_xx_bkptb_base[12]
    DIRECTION INPUT ;
    USE SIGNAL ;
    PORT
      LAYER metal6 ;
        RECT 342.185 0.000 342.325 0.560 ;
    END
  END had_yy_xx_bkptb_base[12]
  PIN had_yy_xx_bkptb_base[13]
    DIRECTION INPUT ;
    USE SIGNAL ;
    PORT
      LAYER metal4 ;
        RECT 342.185 0.000 342.325 0.560 ;
    END
  END had_yy_xx_bkptb_base[13]
  PIN had_yy_xx_bkptb_base[14]
    DIRECTION INPUT ;
    USE SIGNAL ;
    PORT
      LAYER metal6 ;
        RECT 341.065 0.000 341.205 0.560 ;
    END
  END had_yy_xx_bkptb_base[14]
  PIN had_yy_xx_bkptb_base[15]
    DIRECTION INPUT ;
    USE SIGNAL ;
    PORT
      LAYER metal4 ;
        RECT 341.065 0.000 341.205 0.560 ;
    END
  END had_yy_xx_bkptb_base[15]
  PIN had_yy_xx_bkptb_base[16]
    DIRECTION INPUT ;
    USE SIGNAL ;
    PORT
      LAYER metal6 ;
        RECT 339.945 0.000 340.085 0.560 ;
    END
  END had_yy_xx_bkptb_base[16]
  PIN had_yy_xx_bkptb_base[17]
    DIRECTION INPUT ;
    USE SIGNAL ;
    PORT
      LAYER metal4 ;
        RECT 339.945 0.000 340.085 0.560 ;
    END
  END had_yy_xx_bkptb_base[17]
  PIN had_yy_xx_bkptb_base[18]
    DIRECTION INPUT ;
    USE SIGNAL ;
    PORT
      LAYER metal6 ;
        RECT 338.825 0.000 338.965 0.560 ;
    END
  END had_yy_xx_bkptb_base[18]
  PIN had_yy_xx_bkptb_base[19]
    DIRECTION INPUT ;
    USE SIGNAL ;
    PORT
      LAYER metal4 ;
        RECT 338.825 0.000 338.965 0.560 ;
    END
  END had_yy_xx_bkptb_base[19]
  PIN had_yy_xx_bkptb_base[1]
    DIRECTION INPUT ;
    USE SIGNAL ;
    PORT
      LAYER metal4 ;
        RECT 348.905 0.000 349.045 0.560 ;
    END
  END had_yy_xx_bkptb_base[1]
  PIN had_yy_xx_bkptb_base[20]
    DIRECTION INPUT ;
    USE SIGNAL ;
    PORT
      LAYER metal6 ;
        RECT 337.705 0.000 337.845 0.560 ;
    END
  END had_yy_xx_bkptb_base[20]
  PIN had_yy_xx_bkptb_base[21]
    DIRECTION INPUT ;
    USE SIGNAL ;
    PORT
      LAYER metal4 ;
        RECT 337.705 0.000 337.845 0.560 ;
    END
  END had_yy_xx_bkptb_base[21]
  PIN had_yy_xx_bkptb_base[22]
    DIRECTION INPUT ;
    USE SIGNAL ;
    PORT
      LAYER metal6 ;
        RECT 336.585 0.000 336.725 0.560 ;
    END
  END had_yy_xx_bkptb_base[22]
  PIN had_yy_xx_bkptb_base[23]
    DIRECTION INPUT ;
    USE SIGNAL ;
    PORT
      LAYER metal4 ;
        RECT 336.585 0.000 336.725 0.560 ;
    END
  END had_yy_xx_bkptb_base[23]
  PIN had_yy_xx_bkptb_base[24]
    DIRECTION INPUT ;
    USE SIGNAL ;
    PORT
      LAYER metal6 ;
        RECT 335.465 0.000 335.605 0.560 ;
    END
  END had_yy_xx_bkptb_base[24]
  PIN had_yy_xx_bkptb_base[25]
    DIRECTION INPUT ;
    USE SIGNAL ;
    PORT
      LAYER metal4 ;
        RECT 335.465 0.000 335.605 0.560 ;
    END
  END had_yy_xx_bkptb_base[25]
  PIN had_yy_xx_bkptb_base[26]
    DIRECTION INPUT ;
    USE SIGNAL ;
    PORT
      LAYER metal6 ;
        RECT 334.345 0.000 334.485 0.560 ;
    END
  END had_yy_xx_bkptb_base[26]
  PIN had_yy_xx_bkptb_base[27]
    DIRECTION INPUT ;
    USE SIGNAL ;
    PORT
      LAYER metal4 ;
        RECT 334.345 0.000 334.485 0.560 ;
    END
  END had_yy_xx_bkptb_base[27]
  PIN had_yy_xx_bkptb_base[28]
    DIRECTION INPUT ;
    USE SIGNAL ;
    PORT
      LAYER metal6 ;
        RECT 333.225 0.000 333.365 0.560 ;
    END
  END had_yy_xx_bkptb_base[28]
  PIN had_yy_xx_bkptb_base[29]
    DIRECTION INPUT ;
    USE SIGNAL ;
    PORT
      LAYER metal4 ;
        RECT 333.225 0.000 333.365 0.560 ;
    END
  END had_yy_xx_bkptb_base[29]
  PIN had_yy_xx_bkptb_base[2]
    DIRECTION INPUT ;
    USE SIGNAL ;
    PORT
      LAYER metal6 ;
        RECT 347.785 0.000 347.925 0.560 ;
    END
  END had_yy_xx_bkptb_base[2]
  PIN had_yy_xx_bkptb_base[30]
    DIRECTION INPUT ;
    USE SIGNAL ;
    PORT
      LAYER metal6 ;
        RECT 332.105 0.000 332.245 0.560 ;
    END
  END had_yy_xx_bkptb_base[30]
  PIN had_yy_xx_bkptb_base[31]
    DIRECTION INPUT ;
    USE SIGNAL ;
    PORT
      LAYER metal4 ;
        RECT 332.105 0.000 332.245 0.560 ;
    END
  END had_yy_xx_bkptb_base[31]
  PIN had_yy_xx_bkptb_base[32]
    DIRECTION INPUT ;
    USE SIGNAL ;
    PORT
      LAYER metal6 ;
        RECT 330.985 0.000 331.125 0.560 ;
    END
  END had_yy_xx_bkptb_base[32]
  PIN had_yy_xx_bkptb_base[33]
    DIRECTION INPUT ;
    USE SIGNAL ;
    PORT
      LAYER metal4 ;
        RECT 330.985 0.000 331.125 0.560 ;
    END
  END had_yy_xx_bkptb_base[33]
  PIN had_yy_xx_bkptb_base[34]
    DIRECTION INPUT ;
    USE SIGNAL ;
    PORT
      LAYER metal6 ;
        RECT 329.865 0.000 330.005 0.560 ;
    END
  END had_yy_xx_bkptb_base[34]
  PIN had_yy_xx_bkptb_base[35]
    DIRECTION INPUT ;
    USE SIGNAL ;
    PORT
      LAYER metal4 ;
        RECT 329.865 0.000 330.005 0.560 ;
    END
  END had_yy_xx_bkptb_base[35]
  PIN had_yy_xx_bkptb_base[36]
    DIRECTION INPUT ;
    USE SIGNAL ;
    PORT
      LAYER metal6 ;
        RECT 328.745 0.000 328.885 0.560 ;
    END
  END had_yy_xx_bkptb_base[36]
  PIN had_yy_xx_bkptb_base[37]
    DIRECTION INPUT ;
    USE SIGNAL ;
    PORT
      LAYER metal4 ;
        RECT 328.745 0.000 328.885 0.560 ;
    END
  END had_yy_xx_bkptb_base[37]
  PIN had_yy_xx_bkptb_base[38]
    DIRECTION INPUT ;
    USE SIGNAL ;
    PORT
      LAYER metal6 ;
        RECT 327.625 0.000 327.765 0.560 ;
    END
  END had_yy_xx_bkptb_base[38]
  PIN had_yy_xx_bkptb_base[39]
    DIRECTION INPUT ;
    USE SIGNAL ;
    PORT
      LAYER metal4 ;
        RECT 327.625 0.000 327.765 0.560 ;
    END
  END had_yy_xx_bkptb_base[39]
  PIN had_yy_xx_bkptb_base[3]
    DIRECTION INPUT ;
    USE SIGNAL ;
    PORT
      LAYER metal4 ;
        RECT 347.785 0.000 347.925 0.560 ;
    END
  END had_yy_xx_bkptb_base[3]
  PIN had_yy_xx_bkptb_base[4]
    DIRECTION INPUT ;
    USE SIGNAL ;
    PORT
      LAYER metal6 ;
        RECT 346.665 0.000 346.805 0.560 ;
    END
  END had_yy_xx_bkptb_base[4]
  PIN had_yy_xx_bkptb_base[5]
    DIRECTION INPUT ;
    USE SIGNAL ;
    PORT
      LAYER metal4 ;
        RECT 346.665 0.000 346.805 0.560 ;
    END
  END had_yy_xx_bkptb_base[5]
  PIN had_yy_xx_bkptb_base[6]
    DIRECTION INPUT ;
    USE SIGNAL ;
    PORT
      LAYER metal6 ;
        RECT 345.545 0.000 345.685 0.560 ;
    END
  END had_yy_xx_bkptb_base[6]
  PIN had_yy_xx_bkptb_base[7]
    DIRECTION INPUT ;
    USE SIGNAL ;
    PORT
      LAYER metal4 ;
        RECT 345.545 0.000 345.685 0.560 ;
    END
  END had_yy_xx_bkptb_base[7]
  PIN had_yy_xx_bkptb_base[8]
    DIRECTION INPUT ;
    USE SIGNAL ;
    PORT
      LAYER metal6 ;
        RECT 344.425 0.000 344.565 0.560 ;
    END
  END had_yy_xx_bkptb_base[8]
  PIN had_yy_xx_bkptb_base[9]
    DIRECTION INPUT ;
    USE SIGNAL ;
    PORT
      LAYER metal4 ;
        RECT 344.425 0.000 344.565 0.560 ;
    END
  END had_yy_xx_bkptb_base[9]
  PIN had_yy_xx_bkptb_mask[0]
    DIRECTION INPUT ;
    USE SIGNAL ;
    PORT
      LAYER metal6 ;
        RECT 353.385 0.000 353.525 0.560 ;
    END
  END had_yy_xx_bkptb_mask[0]
  PIN had_yy_xx_bkptb_mask[1]
    DIRECTION INPUT ;
    USE SIGNAL ;
    PORT
      LAYER metal4 ;
        RECT 353.385 0.000 353.525 0.560 ;
    END
  END had_yy_xx_bkptb_mask[1]
  PIN had_yy_xx_bkptb_mask[2]
    DIRECTION INPUT ;
    USE SIGNAL ;
    PORT
      LAYER metal6 ;
        RECT 352.265 0.000 352.405 0.560 ;
    END
  END had_yy_xx_bkptb_mask[2]
  PIN had_yy_xx_bkptb_mask[3]
    DIRECTION INPUT ;
    USE SIGNAL ;
    PORT
      LAYER metal4 ;
        RECT 352.265 0.000 352.405 0.560 ;
    END
  END had_yy_xx_bkptb_mask[3]
  PIN had_yy_xx_bkptb_mask[4]
    DIRECTION INPUT ;
    USE SIGNAL ;
    PORT
      LAYER metal6 ;
        RECT 351.145 0.000 351.285 0.560 ;
    END
  END had_yy_xx_bkptb_mask[4]
  PIN had_yy_xx_bkptb_mask[5]
    DIRECTION INPUT ;
    USE SIGNAL ;
    PORT
      LAYER metal4 ;
        RECT 351.145 0.000 351.285 0.560 ;
    END
  END had_yy_xx_bkptb_mask[5]
  PIN had_yy_xx_bkptb_mask[6]
    DIRECTION INPUT ;
    USE SIGNAL ;
    PORT
      LAYER metal6 ;
        RECT 350.025 0.000 350.165 0.560 ;
    END
  END had_yy_xx_bkptb_mask[6]
  PIN had_yy_xx_bkptb_mask[7]
    DIRECTION INPUT ;
    USE SIGNAL ;
    PORT
      LAYER metal4 ;
        RECT 350.025 0.000 350.165 0.560 ;
    END
  END had_yy_xx_bkptb_mask[7]
  PIN had_yy_xx_bkptb_rc
    DIRECTION INPUT ;
    USE SIGNAL ;
    PORT
      LAYER metal4 ;
        RECT 354.505 0.000 354.645 0.560 ;
    END
  END had_yy_xx_bkptb_rc
  PIN hpcp_ifu_cnt_en
    DIRECTION INPUT ;
    USE SIGNAL ;
    PORT
      LAYER metal6 ;
        RECT 354.505 0.000 354.645 0.560 ;
    END
  END hpcp_ifu_cnt_en
  PIN idu_ifu_id_bypass_stall
    DIRECTION INPUT ;
    USE SIGNAL ;
    PORT
      LAYER metal4 ;
        RECT 355.625 0.000 355.765 0.560 ;
    END
  END idu_ifu_id_bypass_stall
  PIN idu_ifu_id_stall
    DIRECTION INPUT ;
    USE SIGNAL ;
    PORT
      LAYER metal6 ;
        RECT 355.625 0.000 355.765 0.560 ;
    END
  END idu_ifu_id_stall
  PIN ifu_biu_r_ready
    DIRECTION OUTPUT ;
    USE SIGNAL ;
    PORT
      LAYER metal4 ;
        RECT 356.745 0.000 356.885 0.560 ;
    END
  END ifu_biu_r_ready
  PIN ifu_biu_rd_addr[0]
    DIRECTION OUTPUT ;
    USE SIGNAL ;
    PORT
      LAYER metal4 ;
        RECT 379.145 0.000 379.285 0.560 ;
    END
  END ifu_biu_rd_addr[0]
  PIN ifu_biu_rd_addr[10]
    DIRECTION OUTPUT ;
    USE SIGNAL ;
    PORT
      LAYER metal4 ;
        RECT 373.545 0.000 373.685 0.560 ;
    END
  END ifu_biu_rd_addr[10]
  PIN ifu_biu_rd_addr[11]
    DIRECTION OUTPUT ;
    USE SIGNAL ;
    PORT
      LAYER metal6 ;
        RECT 372.425 0.000 372.565 0.560 ;
    END
  END ifu_biu_rd_addr[11]
  PIN ifu_biu_rd_addr[12]
    DIRECTION OUTPUT ;
    USE SIGNAL ;
    PORT
      LAYER metal4 ;
        RECT 372.425 0.000 372.565 0.560 ;
    END
  END ifu_biu_rd_addr[12]
  PIN ifu_biu_rd_addr[13]
    DIRECTION OUTPUT ;
    USE SIGNAL ;
    PORT
      LAYER metal6 ;
        RECT 371.305 0.000 371.445 0.560 ;
    END
  END ifu_biu_rd_addr[13]
  PIN ifu_biu_rd_addr[14]
    DIRECTION OUTPUT ;
    USE SIGNAL ;
    PORT
      LAYER metal4 ;
        RECT 371.305 0.000 371.445 0.560 ;
    END
  END ifu_biu_rd_addr[14]
  PIN ifu_biu_rd_addr[15]
    DIRECTION OUTPUT ;
    USE SIGNAL ;
    PORT
      LAYER metal6 ;
        RECT 370.185 0.000 370.325 0.560 ;
    END
  END ifu_biu_rd_addr[15]
  PIN ifu_biu_rd_addr[16]
    DIRECTION OUTPUT ;
    USE SIGNAL ;
    PORT
      LAYER metal4 ;
        RECT 370.185 0.000 370.325 0.560 ;
    END
  END ifu_biu_rd_addr[16]
  PIN ifu_biu_rd_addr[17]
    DIRECTION OUTPUT ;
    USE SIGNAL ;
    PORT
      LAYER metal6 ;
        RECT 369.065 0.000 369.205 0.560 ;
    END
  END ifu_biu_rd_addr[17]
  PIN ifu_biu_rd_addr[18]
    DIRECTION OUTPUT ;
    USE SIGNAL ;
    PORT
      LAYER metal4 ;
        RECT 369.065 0.000 369.205 0.560 ;
    END
  END ifu_biu_rd_addr[18]
  PIN ifu_biu_rd_addr[19]
    DIRECTION OUTPUT ;
    USE SIGNAL ;
    PORT
      LAYER metal6 ;
        RECT 367.945 0.000 368.085 0.560 ;
    END
  END ifu_biu_rd_addr[19]
  PIN ifu_biu_rd_addr[1]
    DIRECTION OUTPUT ;
    USE SIGNAL ;
    PORT
      LAYER metal6 ;
        RECT 378.025 0.000 378.165 0.560 ;
    END
  END ifu_biu_rd_addr[1]
  PIN ifu_biu_rd_addr[20]
    DIRECTION OUTPUT ;
    USE SIGNAL ;
    PORT
      LAYER metal4 ;
        RECT 367.945 0.000 368.085 0.560 ;
    END
  END ifu_biu_rd_addr[20]
  PIN ifu_biu_rd_addr[21]
    DIRECTION OUTPUT ;
    USE SIGNAL ;
    PORT
      LAYER metal6 ;
        RECT 366.825 0.000 366.965 0.560 ;
    END
  END ifu_biu_rd_addr[21]
  PIN ifu_biu_rd_addr[22]
    DIRECTION OUTPUT ;
    USE SIGNAL ;
    PORT
      LAYER metal4 ;
        RECT 366.825 0.000 366.965 0.560 ;
    END
  END ifu_biu_rd_addr[22]
  PIN ifu_biu_rd_addr[23]
    DIRECTION OUTPUT ;
    USE SIGNAL ;
    PORT
      LAYER metal6 ;
        RECT 365.705 0.000 365.845 0.560 ;
    END
  END ifu_biu_rd_addr[23]
  PIN ifu_biu_rd_addr[24]
    DIRECTION OUTPUT ;
    USE SIGNAL ;
    PORT
      LAYER metal4 ;
        RECT 365.705 0.000 365.845 0.560 ;
    END
  END ifu_biu_rd_addr[24]
  PIN ifu_biu_rd_addr[25]
    DIRECTION OUTPUT ;
    USE SIGNAL ;
    PORT
      LAYER metal6 ;
        RECT 364.585 0.000 364.725 0.560 ;
    END
  END ifu_biu_rd_addr[25]
  PIN ifu_biu_rd_addr[26]
    DIRECTION OUTPUT ;
    USE SIGNAL ;
    PORT
      LAYER metal4 ;
        RECT 364.585 0.000 364.725 0.560 ;
    END
  END ifu_biu_rd_addr[26]
  PIN ifu_biu_rd_addr[27]
    DIRECTION OUTPUT ;
    USE SIGNAL ;
    PORT
      LAYER metal6 ;
        RECT 363.465 0.000 363.605 0.560 ;
    END
  END ifu_biu_rd_addr[27]
  PIN ifu_biu_rd_addr[28]
    DIRECTION OUTPUT ;
    USE SIGNAL ;
    PORT
      LAYER metal4 ;
        RECT 363.465 0.000 363.605 0.560 ;
    END
  END ifu_biu_rd_addr[28]
  PIN ifu_biu_rd_addr[29]
    DIRECTION OUTPUT ;
    USE SIGNAL ;
    PORT
      LAYER metal6 ;
        RECT 362.345 0.000 362.485 0.560 ;
    END
  END ifu_biu_rd_addr[29]
  PIN ifu_biu_rd_addr[2]
    DIRECTION OUTPUT ;
    USE SIGNAL ;
    PORT
      LAYER metal4 ;
        RECT 378.025 0.000 378.165 0.560 ;
    END
  END ifu_biu_rd_addr[2]
  PIN ifu_biu_rd_addr[30]
    DIRECTION OUTPUT ;
    USE SIGNAL ;
    PORT
      LAYER metal4 ;
        RECT 362.345 0.000 362.485 0.560 ;
    END
  END ifu_biu_rd_addr[30]
  PIN ifu_biu_rd_addr[31]
    DIRECTION OUTPUT ;
    USE SIGNAL ;
    PORT
      LAYER metal6 ;
        RECT 361.225 0.000 361.365 0.560 ;
    END
  END ifu_biu_rd_addr[31]
  PIN ifu_biu_rd_addr[32]
    DIRECTION OUTPUT ;
    USE SIGNAL ;
    PORT
      LAYER metal4 ;
        RECT 361.225 0.000 361.365 0.560 ;
    END
  END ifu_biu_rd_addr[32]
  PIN ifu_biu_rd_addr[33]
    DIRECTION OUTPUT ;
    USE SIGNAL ;
    PORT
      LAYER metal6 ;
        RECT 360.105 0.000 360.245 0.560 ;
    END
  END ifu_biu_rd_addr[33]
  PIN ifu_biu_rd_addr[34]
    DIRECTION OUTPUT ;
    USE SIGNAL ;
    PORT
      LAYER metal4 ;
        RECT 360.105 0.000 360.245 0.560 ;
    END
  END ifu_biu_rd_addr[34]
  PIN ifu_biu_rd_addr[35]
    DIRECTION OUTPUT ;
    USE SIGNAL ;
    PORT
      LAYER metal6 ;
        RECT 358.985 0.000 359.125 0.560 ;
    END
  END ifu_biu_rd_addr[35]
  PIN ifu_biu_rd_addr[36]
    DIRECTION OUTPUT ;
    USE SIGNAL ;
    PORT
      LAYER metal4 ;
        RECT 358.985 0.000 359.125 0.560 ;
    END
  END ifu_biu_rd_addr[36]
  PIN ifu_biu_rd_addr[37]
    DIRECTION OUTPUT ;
    USE SIGNAL ;
    PORT
      LAYER metal6 ;
        RECT 357.865 0.000 358.005 0.560 ;
    END
  END ifu_biu_rd_addr[37]
  PIN ifu_biu_rd_addr[38]
    DIRECTION OUTPUT ;
    USE SIGNAL ;
    PORT
      LAYER metal4 ;
        RECT 357.865 0.000 358.005 0.560 ;
    END
  END ifu_biu_rd_addr[38]
  PIN ifu_biu_rd_addr[39]
    DIRECTION OUTPUT ;
    USE SIGNAL ;
    PORT
      LAYER metal6 ;
        RECT 356.745 0.000 356.885 0.560 ;
    END
  END ifu_biu_rd_addr[39]
  PIN ifu_biu_rd_addr[3]
    DIRECTION OUTPUT ;
    USE SIGNAL ;
    PORT
      LAYER metal6 ;
        RECT 376.905 0.000 377.045 0.560 ;
    END
  END ifu_biu_rd_addr[3]
  PIN ifu_biu_rd_addr[4]
    DIRECTION OUTPUT ;
    USE SIGNAL ;
    PORT
      LAYER metal4 ;
        RECT 376.905 0.000 377.045 0.560 ;
    END
  END ifu_biu_rd_addr[4]
  PIN ifu_biu_rd_addr[5]
    DIRECTION OUTPUT ;
    USE SIGNAL ;
    PORT
      LAYER metal6 ;
        RECT 375.785 0.000 375.925 0.560 ;
    END
  END ifu_biu_rd_addr[5]
  PIN ifu_biu_rd_addr[6]
    DIRECTION OUTPUT ;
    USE SIGNAL ;
    PORT
      LAYER metal4 ;
        RECT 375.785 0.000 375.925 0.560 ;
    END
  END ifu_biu_rd_addr[6]
  PIN ifu_biu_rd_addr[7]
    DIRECTION OUTPUT ;
    USE SIGNAL ;
    PORT
      LAYER metal6 ;
        RECT 374.665 0.000 374.805 0.560 ;
    END
  END ifu_biu_rd_addr[7]
  PIN ifu_biu_rd_addr[8]
    DIRECTION OUTPUT ;
    USE SIGNAL ;
    PORT
      LAYER metal4 ;
        RECT 374.665 0.000 374.805 0.560 ;
    END
  END ifu_biu_rd_addr[8]
  PIN ifu_biu_rd_addr[9]
    DIRECTION OUTPUT ;
    USE SIGNAL ;
    PORT
      LAYER metal6 ;
        RECT 373.545 0.000 373.685 0.560 ;
    END
  END ifu_biu_rd_addr[9]
  PIN ifu_biu_rd_burst[0]
    DIRECTION OUTPUT ;
    USE SIGNAL ;
    PORT
      LAYER metal4 ;
        RECT 380.265 0.000 380.405 0.560 ;
    END
  END ifu_biu_rd_burst[0]
  PIN ifu_biu_rd_burst[1]
    DIRECTION OUTPUT ;
    USE SIGNAL ;
    PORT
      LAYER metal6 ;
        RECT 379.145 0.000 379.285 0.560 ;
    END
  END ifu_biu_rd_burst[1]
  PIN ifu_biu_rd_cache[0]
    DIRECTION OUTPUT ;
    USE SIGNAL ;
    PORT
      LAYER metal4 ;
        RECT 382.505 0.000 382.645 0.560 ;
    END
  END ifu_biu_rd_cache[0]
  PIN ifu_biu_rd_cache[1]
    DIRECTION OUTPUT ;
    USE SIGNAL ;
    PORT
      LAYER metal6 ;
        RECT 381.385 0.000 381.525 0.560 ;
    END
  END ifu_biu_rd_cache[1]
  PIN ifu_biu_rd_cache[2]
    DIRECTION OUTPUT ;
    USE SIGNAL ;
    PORT
      LAYER metal4 ;
        RECT 381.385 0.000 381.525 0.560 ;
    END
  END ifu_biu_rd_cache[2]
  PIN ifu_biu_rd_cache[3]
    DIRECTION OUTPUT ;
    USE SIGNAL ;
    PORT
      LAYER metal6 ;
        RECT 380.265 0.000 380.405 0.560 ;
    END
  END ifu_biu_rd_cache[3]
  PIN ifu_biu_rd_domain[0]
    DIRECTION OUTPUT ;
    USE SIGNAL ;
    PORT
      LAYER metal4 ;
        RECT 383.625 0.000 383.765 0.560 ;
    END
  END ifu_biu_rd_domain[0]
  PIN ifu_biu_rd_domain[1]
    DIRECTION OUTPUT ;
    USE SIGNAL ;
    PORT
      LAYER metal6 ;
        RECT 382.505 0.000 382.645 0.560 ;
    END
  END ifu_biu_rd_domain[1]
  PIN ifu_biu_rd_id
    DIRECTION OUTPUT ;
    USE SIGNAL ;
    PORT
      LAYER metal6 ;
        RECT 383.625 0.000 383.765 0.560 ;
    END
  END ifu_biu_rd_id
  PIN ifu_biu_rd_len[0]
    DIRECTION OUTPUT ;
    USE SIGNAL ;
    PORT
      LAYER metal6 ;
        RECT 384.745 0.000 384.885 0.560 ;
    END
  END ifu_biu_rd_len[0]
  PIN ifu_biu_rd_len[1]
    DIRECTION OUTPUT ;
    USE SIGNAL ;
    PORT
      LAYER metal4 ;
        RECT 384.745 0.000 384.885 0.560 ;
    END
  END ifu_biu_rd_len[1]
  PIN ifu_biu_rd_prot[0]
    DIRECTION OUTPUT ;
    USE SIGNAL ;
    PORT
      LAYER metal4 ;
        RECT 386.985 0.000 387.125 0.560 ;
    END
  END ifu_biu_rd_prot[0]
  PIN ifu_biu_rd_prot[1]
    DIRECTION OUTPUT ;
    USE SIGNAL ;
    PORT
      LAYER metal6 ;
        RECT 385.865 0.000 386.005 0.560 ;
    END
  END ifu_biu_rd_prot[1]
  PIN ifu_biu_rd_prot[2]
    DIRECTION OUTPUT ;
    USE SIGNAL ;
    PORT
      LAYER metal4 ;
        RECT 385.865 0.000 386.005 0.560 ;
    END
  END ifu_biu_rd_prot[2]
  PIN ifu_biu_rd_req
    DIRECTION OUTPUT ;
    USE SIGNAL ;
    PORT
      LAYER metal6 ;
        RECT 386.985 0.000 387.125 0.560 ;
    END
  END ifu_biu_rd_req
  PIN ifu_biu_rd_req_gate
    DIRECTION OUTPUT ;
    USE SIGNAL ;
    PORT
      LAYER metal4 ;
        RECT 388.105 0.000 388.245 0.560 ;
    END
  END ifu_biu_rd_req_gate
  PIN ifu_biu_rd_size[0]
    DIRECTION OUTPUT ;
    USE SIGNAL ;
    PORT
      LAYER metal6 ;
        RECT 389.225 0.000 389.365 0.560 ;
    END
  END ifu_biu_rd_size[0]
  PIN ifu_biu_rd_size[1]
    DIRECTION OUTPUT ;
    USE SIGNAL ;
    PORT
      LAYER metal4 ;
        RECT 389.225 0.000 389.365 0.560 ;
    END
  END ifu_biu_rd_size[1]
  PIN ifu_biu_rd_size[2]
    DIRECTION OUTPUT ;
    USE SIGNAL ;
    PORT
      LAYER metal6 ;
        RECT 388.105 0.000 388.245 0.560 ;
    END
  END ifu_biu_rd_size[2]
  PIN ifu_biu_rd_snoop[0]
    DIRECTION OUTPUT ;
    USE SIGNAL ;
    PORT
      LAYER metal6 ;
        RECT 391.465 0.000 391.605 0.560 ;
    END
  END ifu_biu_rd_snoop[0]
  PIN ifu_biu_rd_snoop[1]
    DIRECTION OUTPUT ;
    USE SIGNAL ;
    PORT
      LAYER metal4 ;
        RECT 391.465 0.000 391.605 0.560 ;
    END
  END ifu_biu_rd_snoop[1]
  PIN ifu_biu_rd_snoop[2]
    DIRECTION OUTPUT ;
    USE SIGNAL ;
    PORT
      LAYER metal6 ;
        RECT 390.345 0.000 390.485 0.560 ;
    END
  END ifu_biu_rd_snoop[2]
  PIN ifu_biu_rd_snoop[3]
    DIRECTION OUTPUT ;
    USE SIGNAL ;
    PORT
      LAYER metal4 ;
        RECT 390.345 0.000 390.485 0.560 ;
    END
  END ifu_biu_rd_snoop[3]
  PIN ifu_biu_rd_user[0]
    DIRECTION OUTPUT ;
    USE SIGNAL ;
    PORT
      LAYER metal6 ;
        RECT 392.585 0.000 392.725 0.560 ;
    END
  END ifu_biu_rd_user[0]
  PIN ifu_biu_rd_user[1]
    DIRECTION OUTPUT ;
    USE SIGNAL ;
    PORT
      LAYER metal4 ;
        RECT 392.585 0.000 392.725 0.560 ;
    END
  END ifu_biu_rd_user[1]
  PIN ifu_cp0_bht_inv_done
    DIRECTION OUTPUT ;
    USE SIGNAL ;
    PORT
      LAYER metal4 ;
        RECT 393.705 0.000 393.845 0.560 ;
    END
  END ifu_cp0_bht_inv_done
  PIN ifu_cp0_btb_inv_done
    DIRECTION OUTPUT ;
    USE SIGNAL ;
    PORT
      LAYER metal6 ;
        RECT 393.705 0.000 393.845 0.560 ;
    END
  END ifu_cp0_btb_inv_done
  PIN ifu_cp0_icache_inv_done
    DIRECTION OUTPUT ;
    USE SIGNAL ;
    PORT
      LAYER metal4 ;
        RECT 394.825 0.000 394.965 0.560 ;
    END
  END ifu_cp0_icache_inv_done
  PIN ifu_cp0_icache_read_data[0]
    DIRECTION OUTPUT ;
    USE SIGNAL ;
    PORT
      LAYER metal4 ;
        RECT 466.505 0.000 466.645 0.560 ;
    END
  END ifu_cp0_icache_read_data[0]
  PIN ifu_cp0_icache_read_data[100]
    DIRECTION OUTPUT ;
    USE SIGNAL ;
    PORT
      LAYER metal4 ;
        RECT 410.505 0.000 410.645 0.560 ;
    END
  END ifu_cp0_icache_read_data[100]
  PIN ifu_cp0_icache_read_data[101]
    DIRECTION OUTPUT ;
    USE SIGNAL ;
    PORT
      LAYER metal6 ;
        RECT 409.385 0.000 409.525 0.560 ;
    END
  END ifu_cp0_icache_read_data[101]
  PIN ifu_cp0_icache_read_data[102]
    DIRECTION OUTPUT ;
    USE SIGNAL ;
    PORT
      LAYER metal4 ;
        RECT 409.385 0.000 409.525 0.560 ;
    END
  END ifu_cp0_icache_read_data[102]
  PIN ifu_cp0_icache_read_data[103]
    DIRECTION OUTPUT ;
    USE SIGNAL ;
    PORT
      LAYER metal6 ;
        RECT 408.265 0.000 408.405 0.560 ;
    END
  END ifu_cp0_icache_read_data[103]
  PIN ifu_cp0_icache_read_data[104]
    DIRECTION OUTPUT ;
    USE SIGNAL ;
    PORT
      LAYER metal4 ;
        RECT 408.265 0.000 408.405 0.560 ;
    END
  END ifu_cp0_icache_read_data[104]
  PIN ifu_cp0_icache_read_data[105]
    DIRECTION OUTPUT ;
    USE SIGNAL ;
    PORT
      LAYER metal6 ;
        RECT 407.145 0.000 407.285 0.560 ;
    END
  END ifu_cp0_icache_read_data[105]
  PIN ifu_cp0_icache_read_data[106]
    DIRECTION OUTPUT ;
    USE SIGNAL ;
    PORT
      LAYER metal4 ;
        RECT 407.145 0.000 407.285 0.560 ;
    END
  END ifu_cp0_icache_read_data[106]
  PIN ifu_cp0_icache_read_data[107]
    DIRECTION OUTPUT ;
    USE SIGNAL ;
    PORT
      LAYER metal6 ;
        RECT 406.025 0.000 406.165 0.560 ;
    END
  END ifu_cp0_icache_read_data[107]
  PIN ifu_cp0_icache_read_data[108]
    DIRECTION OUTPUT ;
    USE SIGNAL ;
    PORT
      LAYER metal4 ;
        RECT 406.025 0.000 406.165 0.560 ;
    END
  END ifu_cp0_icache_read_data[108]
  PIN ifu_cp0_icache_read_data[109]
    DIRECTION OUTPUT ;
    USE SIGNAL ;
    PORT
      LAYER metal6 ;
        RECT 404.905 0.000 405.045 0.560 ;
    END
  END ifu_cp0_icache_read_data[109]
  PIN ifu_cp0_icache_read_data[10]
    DIRECTION OUTPUT ;
    USE SIGNAL ;
    PORT
      LAYER metal4 ;
        RECT 460.905 0.000 461.045 0.560 ;
    END
  END ifu_cp0_icache_read_data[10]
  PIN ifu_cp0_icache_read_data[110]
    DIRECTION OUTPUT ;
    USE SIGNAL ;
    PORT
      LAYER metal4 ;
        RECT 404.905 0.000 405.045 0.560 ;
    END
  END ifu_cp0_icache_read_data[110]
  PIN ifu_cp0_icache_read_data[111]
    DIRECTION OUTPUT ;
    USE SIGNAL ;
    PORT
      LAYER metal6 ;
        RECT 403.785 0.000 403.925 0.560 ;
    END
  END ifu_cp0_icache_read_data[111]
  PIN ifu_cp0_icache_read_data[112]
    DIRECTION OUTPUT ;
    USE SIGNAL ;
    PORT
      LAYER metal4 ;
        RECT 403.785 0.000 403.925 0.560 ;
    END
  END ifu_cp0_icache_read_data[112]
  PIN ifu_cp0_icache_read_data[113]
    DIRECTION OUTPUT ;
    USE SIGNAL ;
    PORT
      LAYER metal6 ;
        RECT 402.665 0.000 402.805 0.560 ;
    END
  END ifu_cp0_icache_read_data[113]
  PIN ifu_cp0_icache_read_data[114]
    DIRECTION OUTPUT ;
    USE SIGNAL ;
    PORT
      LAYER metal4 ;
        RECT 402.665 0.000 402.805 0.560 ;
    END
  END ifu_cp0_icache_read_data[114]
  PIN ifu_cp0_icache_read_data[115]
    DIRECTION OUTPUT ;
    USE SIGNAL ;
    PORT
      LAYER metal6 ;
        RECT 401.545 0.000 401.685 0.560 ;
    END
  END ifu_cp0_icache_read_data[115]
  PIN ifu_cp0_icache_read_data[116]
    DIRECTION OUTPUT ;
    USE SIGNAL ;
    PORT
      LAYER metal4 ;
        RECT 401.545 0.000 401.685 0.560 ;
    END
  END ifu_cp0_icache_read_data[116]
  PIN ifu_cp0_icache_read_data[117]
    DIRECTION OUTPUT ;
    USE SIGNAL ;
    PORT
      LAYER metal6 ;
        RECT 400.425 0.000 400.565 0.560 ;
    END
  END ifu_cp0_icache_read_data[117]
  PIN ifu_cp0_icache_read_data[118]
    DIRECTION OUTPUT ;
    USE SIGNAL ;
    PORT
      LAYER metal4 ;
        RECT 400.425 0.000 400.565 0.560 ;
    END
  END ifu_cp0_icache_read_data[118]
  PIN ifu_cp0_icache_read_data[119]
    DIRECTION OUTPUT ;
    USE SIGNAL ;
    PORT
      LAYER metal6 ;
        RECT 399.305 0.000 399.445 0.560 ;
    END
  END ifu_cp0_icache_read_data[119]
  PIN ifu_cp0_icache_read_data[11]
    DIRECTION OUTPUT ;
    USE SIGNAL ;
    PORT
      LAYER metal6 ;
        RECT 459.785 0.000 459.925 0.560 ;
    END
  END ifu_cp0_icache_read_data[11]
  PIN ifu_cp0_icache_read_data[120]
    DIRECTION OUTPUT ;
    USE SIGNAL ;
    PORT
      LAYER metal4 ;
        RECT 399.305 0.000 399.445 0.560 ;
    END
  END ifu_cp0_icache_read_data[120]
  PIN ifu_cp0_icache_read_data[121]
    DIRECTION OUTPUT ;
    USE SIGNAL ;
    PORT
      LAYER metal6 ;
        RECT 398.185 0.000 398.325 0.560 ;
    END
  END ifu_cp0_icache_read_data[121]
  PIN ifu_cp0_icache_read_data[122]
    DIRECTION OUTPUT ;
    USE SIGNAL ;
    PORT
      LAYER metal4 ;
        RECT 398.185 0.000 398.325 0.560 ;
    END
  END ifu_cp0_icache_read_data[122]
  PIN ifu_cp0_icache_read_data[123]
    DIRECTION OUTPUT ;
    USE SIGNAL ;
    PORT
      LAYER metal6 ;
        RECT 397.065 0.000 397.205 0.560 ;
    END
  END ifu_cp0_icache_read_data[123]
  PIN ifu_cp0_icache_read_data[124]
    DIRECTION OUTPUT ;
    USE SIGNAL ;
    PORT
      LAYER metal4 ;
        RECT 397.065 0.000 397.205 0.560 ;
    END
  END ifu_cp0_icache_read_data[124]
  PIN ifu_cp0_icache_read_data[125]
    DIRECTION OUTPUT ;
    USE SIGNAL ;
    PORT
      LAYER metal6 ;
        RECT 395.945 0.000 396.085 0.560 ;
    END
  END ifu_cp0_icache_read_data[125]
  PIN ifu_cp0_icache_read_data[126]
    DIRECTION OUTPUT ;
    USE SIGNAL ;
    PORT
      LAYER metal4 ;
        RECT 395.945 0.000 396.085 0.560 ;
    END
  END ifu_cp0_icache_read_data[126]
  PIN ifu_cp0_icache_read_data[127]
    DIRECTION OUTPUT ;
    USE SIGNAL ;
    PORT
      LAYER metal6 ;
        RECT 394.825 0.000 394.965 0.560 ;
    END
  END ifu_cp0_icache_read_data[127]
  PIN ifu_cp0_icache_read_data[12]
    DIRECTION OUTPUT ;
    USE SIGNAL ;
    PORT
      LAYER metal4 ;
        RECT 459.785 0.000 459.925 0.560 ;
    END
  END ifu_cp0_icache_read_data[12]
  PIN ifu_cp0_icache_read_data[13]
    DIRECTION OUTPUT ;
    USE SIGNAL ;
    PORT
      LAYER metal6 ;
        RECT 458.665 0.000 458.805 0.560 ;
    END
  END ifu_cp0_icache_read_data[13]
  PIN ifu_cp0_icache_read_data[14]
    DIRECTION OUTPUT ;
    USE SIGNAL ;
    PORT
      LAYER metal4 ;
        RECT 458.665 0.000 458.805 0.560 ;
    END
  END ifu_cp0_icache_read_data[14]
  PIN ifu_cp0_icache_read_data[15]
    DIRECTION OUTPUT ;
    USE SIGNAL ;
    PORT
      LAYER metal6 ;
        RECT 457.545 0.000 457.685 0.560 ;
    END
  END ifu_cp0_icache_read_data[15]
  PIN ifu_cp0_icache_read_data[16]
    DIRECTION OUTPUT ;
    USE SIGNAL ;
    PORT
      LAYER metal4 ;
        RECT 457.545 0.000 457.685 0.560 ;
    END
  END ifu_cp0_icache_read_data[16]
  PIN ifu_cp0_icache_read_data[17]
    DIRECTION OUTPUT ;
    USE SIGNAL ;
    PORT
      LAYER metal6 ;
        RECT 456.425 0.000 456.565 0.560 ;
    END
  END ifu_cp0_icache_read_data[17]
  PIN ifu_cp0_icache_read_data[18]
    DIRECTION OUTPUT ;
    USE SIGNAL ;
    PORT
      LAYER metal4 ;
        RECT 456.425 0.000 456.565 0.560 ;
    END
  END ifu_cp0_icache_read_data[18]
  PIN ifu_cp0_icache_read_data[19]
    DIRECTION OUTPUT ;
    USE SIGNAL ;
    PORT
      LAYER metal6 ;
        RECT 455.305 0.000 455.445 0.560 ;
    END
  END ifu_cp0_icache_read_data[19]
  PIN ifu_cp0_icache_read_data[1]
    DIRECTION OUTPUT ;
    USE SIGNAL ;
    PORT
      LAYER metal6 ;
        RECT 465.385 0.000 465.525 0.560 ;
    END
  END ifu_cp0_icache_read_data[1]
  PIN ifu_cp0_icache_read_data[20]
    DIRECTION OUTPUT ;
    USE SIGNAL ;
    PORT
      LAYER metal4 ;
        RECT 455.305 0.000 455.445 0.560 ;
    END
  END ifu_cp0_icache_read_data[20]
  PIN ifu_cp0_icache_read_data[21]
    DIRECTION OUTPUT ;
    USE SIGNAL ;
    PORT
      LAYER metal6 ;
        RECT 454.185 0.000 454.325 0.560 ;
    END
  END ifu_cp0_icache_read_data[21]
  PIN ifu_cp0_icache_read_data[22]
    DIRECTION OUTPUT ;
    USE SIGNAL ;
    PORT
      LAYER metal4 ;
        RECT 454.185 0.000 454.325 0.560 ;
    END
  END ifu_cp0_icache_read_data[22]
  PIN ifu_cp0_icache_read_data[23]
    DIRECTION OUTPUT ;
    USE SIGNAL ;
    PORT
      LAYER metal6 ;
        RECT 453.065 0.000 453.205 0.560 ;
    END
  END ifu_cp0_icache_read_data[23]
  PIN ifu_cp0_icache_read_data[24]
    DIRECTION OUTPUT ;
    USE SIGNAL ;
    PORT
      LAYER metal4 ;
        RECT 453.065 0.000 453.205 0.560 ;
    END
  END ifu_cp0_icache_read_data[24]
  PIN ifu_cp0_icache_read_data[25]
    DIRECTION OUTPUT ;
    USE SIGNAL ;
    PORT
      LAYER metal6 ;
        RECT 451.945 0.000 452.085 0.560 ;
    END
  END ifu_cp0_icache_read_data[25]
  PIN ifu_cp0_icache_read_data[26]
    DIRECTION OUTPUT ;
    USE SIGNAL ;
    PORT
      LAYER metal4 ;
        RECT 451.945 0.000 452.085 0.560 ;
    END
  END ifu_cp0_icache_read_data[26]
  PIN ifu_cp0_icache_read_data[27]
    DIRECTION OUTPUT ;
    USE SIGNAL ;
    PORT
      LAYER metal6 ;
        RECT 450.825 0.000 450.965 0.560 ;
    END
  END ifu_cp0_icache_read_data[27]
  PIN ifu_cp0_icache_read_data[28]
    DIRECTION OUTPUT ;
    USE SIGNAL ;
    PORT
      LAYER metal4 ;
        RECT 450.825 0.000 450.965 0.560 ;
    END
  END ifu_cp0_icache_read_data[28]
  PIN ifu_cp0_icache_read_data[29]
    DIRECTION OUTPUT ;
    USE SIGNAL ;
    PORT
      LAYER metal6 ;
        RECT 449.705 0.000 449.845 0.560 ;
    END
  END ifu_cp0_icache_read_data[29]
  PIN ifu_cp0_icache_read_data[2]
    DIRECTION OUTPUT ;
    USE SIGNAL ;
    PORT
      LAYER metal4 ;
        RECT 465.385 0.000 465.525 0.560 ;
    END
  END ifu_cp0_icache_read_data[2]
  PIN ifu_cp0_icache_read_data[30]
    DIRECTION OUTPUT ;
    USE SIGNAL ;
    PORT
      LAYER metal4 ;
        RECT 449.705 0.000 449.845 0.560 ;
    END
  END ifu_cp0_icache_read_data[30]
  PIN ifu_cp0_icache_read_data[31]
    DIRECTION OUTPUT ;
    USE SIGNAL ;
    PORT
      LAYER metal6 ;
        RECT 448.585 0.000 448.725 0.560 ;
    END
  END ifu_cp0_icache_read_data[31]
  PIN ifu_cp0_icache_read_data[32]
    DIRECTION OUTPUT ;
    USE SIGNAL ;
    PORT
      LAYER metal4 ;
        RECT 448.585 0.000 448.725 0.560 ;
    END
  END ifu_cp0_icache_read_data[32]
  PIN ifu_cp0_icache_read_data[33]
    DIRECTION OUTPUT ;
    USE SIGNAL ;
    PORT
      LAYER metal6 ;
        RECT 447.465 0.000 447.605 0.560 ;
    END
  END ifu_cp0_icache_read_data[33]
  PIN ifu_cp0_icache_read_data[34]
    DIRECTION OUTPUT ;
    USE SIGNAL ;
    PORT
      LAYER metal4 ;
        RECT 447.465 0.000 447.605 0.560 ;
    END
  END ifu_cp0_icache_read_data[34]
  PIN ifu_cp0_icache_read_data[35]
    DIRECTION OUTPUT ;
    USE SIGNAL ;
    PORT
      LAYER metal6 ;
        RECT 446.345 0.000 446.485 0.560 ;
    END
  END ifu_cp0_icache_read_data[35]
  PIN ifu_cp0_icache_read_data[36]
    DIRECTION OUTPUT ;
    USE SIGNAL ;
    PORT
      LAYER metal4 ;
        RECT 446.345 0.000 446.485 0.560 ;
    END
  END ifu_cp0_icache_read_data[36]
  PIN ifu_cp0_icache_read_data[37]
    DIRECTION OUTPUT ;
    USE SIGNAL ;
    PORT
      LAYER metal6 ;
        RECT 445.225 0.000 445.365 0.560 ;
    END
  END ifu_cp0_icache_read_data[37]
  PIN ifu_cp0_icache_read_data[38]
    DIRECTION OUTPUT ;
    USE SIGNAL ;
    PORT
      LAYER metal4 ;
        RECT 445.225 0.000 445.365 0.560 ;
    END
  END ifu_cp0_icache_read_data[38]
  PIN ifu_cp0_icache_read_data[39]
    DIRECTION OUTPUT ;
    USE SIGNAL ;
    PORT
      LAYER metal6 ;
        RECT 444.105 0.000 444.245 0.560 ;
    END
  END ifu_cp0_icache_read_data[39]
  PIN ifu_cp0_icache_read_data[3]
    DIRECTION OUTPUT ;
    USE SIGNAL ;
    PORT
      LAYER metal6 ;
        RECT 464.265 0.000 464.405 0.560 ;
    END
  END ifu_cp0_icache_read_data[3]
  PIN ifu_cp0_icache_read_data[40]
    DIRECTION OUTPUT ;
    USE SIGNAL ;
    PORT
      LAYER metal4 ;
        RECT 444.105 0.000 444.245 0.560 ;
    END
  END ifu_cp0_icache_read_data[40]
  PIN ifu_cp0_icache_read_data[41]
    DIRECTION OUTPUT ;
    USE SIGNAL ;
    PORT
      LAYER metal6 ;
        RECT 442.985 0.000 443.125 0.560 ;
    END
  END ifu_cp0_icache_read_data[41]
  PIN ifu_cp0_icache_read_data[42]
    DIRECTION OUTPUT ;
    USE SIGNAL ;
    PORT
      LAYER metal4 ;
        RECT 442.985 0.000 443.125 0.560 ;
    END
  END ifu_cp0_icache_read_data[42]
  PIN ifu_cp0_icache_read_data[43]
    DIRECTION OUTPUT ;
    USE SIGNAL ;
    PORT
      LAYER metal6 ;
        RECT 441.865 0.000 442.005 0.560 ;
    END
  END ifu_cp0_icache_read_data[43]
  PIN ifu_cp0_icache_read_data[44]
    DIRECTION OUTPUT ;
    USE SIGNAL ;
    PORT
      LAYER metal4 ;
        RECT 441.865 0.000 442.005 0.560 ;
    END
  END ifu_cp0_icache_read_data[44]
  PIN ifu_cp0_icache_read_data[45]
    DIRECTION OUTPUT ;
    USE SIGNAL ;
    PORT
      LAYER metal6 ;
        RECT 440.745 0.000 440.885 0.560 ;
    END
  END ifu_cp0_icache_read_data[45]
  PIN ifu_cp0_icache_read_data[46]
    DIRECTION OUTPUT ;
    USE SIGNAL ;
    PORT
      LAYER metal4 ;
        RECT 440.745 0.000 440.885 0.560 ;
    END
  END ifu_cp0_icache_read_data[46]
  PIN ifu_cp0_icache_read_data[47]
    DIRECTION OUTPUT ;
    USE SIGNAL ;
    PORT
      LAYER metal6 ;
        RECT 439.625 0.000 439.765 0.560 ;
    END
  END ifu_cp0_icache_read_data[47]
  PIN ifu_cp0_icache_read_data[48]
    DIRECTION OUTPUT ;
    USE SIGNAL ;
    PORT
      LAYER metal4 ;
        RECT 439.625 0.000 439.765 0.560 ;
    END
  END ifu_cp0_icache_read_data[48]
  PIN ifu_cp0_icache_read_data[49]
    DIRECTION OUTPUT ;
    USE SIGNAL ;
    PORT
      LAYER metal6 ;
        RECT 438.505 0.000 438.645 0.560 ;
    END
  END ifu_cp0_icache_read_data[49]
  PIN ifu_cp0_icache_read_data[4]
    DIRECTION OUTPUT ;
    USE SIGNAL ;
    PORT
      LAYER metal4 ;
        RECT 464.265 0.000 464.405 0.560 ;
    END
  END ifu_cp0_icache_read_data[4]
  PIN ifu_cp0_icache_read_data[50]
    DIRECTION OUTPUT ;
    USE SIGNAL ;
    PORT
      LAYER metal4 ;
        RECT 438.505 0.000 438.645 0.560 ;
    END
  END ifu_cp0_icache_read_data[50]
  PIN ifu_cp0_icache_read_data[51]
    DIRECTION OUTPUT ;
    USE SIGNAL ;
    PORT
      LAYER metal6 ;
        RECT 437.385 0.000 437.525 0.560 ;
    END
  END ifu_cp0_icache_read_data[51]
  PIN ifu_cp0_icache_read_data[52]
    DIRECTION OUTPUT ;
    USE SIGNAL ;
    PORT
      LAYER metal4 ;
        RECT 437.385 0.000 437.525 0.560 ;
    END
  END ifu_cp0_icache_read_data[52]
  PIN ifu_cp0_icache_read_data[53]
    DIRECTION OUTPUT ;
    USE SIGNAL ;
    PORT
      LAYER metal6 ;
        RECT 436.265 0.000 436.405 0.560 ;
    END
  END ifu_cp0_icache_read_data[53]
  PIN ifu_cp0_icache_read_data[54]
    DIRECTION OUTPUT ;
    USE SIGNAL ;
    PORT
      LAYER metal4 ;
        RECT 436.265 0.000 436.405 0.560 ;
    END
  END ifu_cp0_icache_read_data[54]
  PIN ifu_cp0_icache_read_data[55]
    DIRECTION OUTPUT ;
    USE SIGNAL ;
    PORT
      LAYER metal6 ;
        RECT 435.145 0.000 435.285 0.560 ;
    END
  END ifu_cp0_icache_read_data[55]
  PIN ifu_cp0_icache_read_data[56]
    DIRECTION OUTPUT ;
    USE SIGNAL ;
    PORT
      LAYER metal4 ;
        RECT 435.145 0.000 435.285 0.560 ;
    END
  END ifu_cp0_icache_read_data[56]
  PIN ifu_cp0_icache_read_data[57]
    DIRECTION OUTPUT ;
    USE SIGNAL ;
    PORT
      LAYER metal6 ;
        RECT 434.025 0.000 434.165 0.560 ;
    END
  END ifu_cp0_icache_read_data[57]
  PIN ifu_cp0_icache_read_data[58]
    DIRECTION OUTPUT ;
    USE SIGNAL ;
    PORT
      LAYER metal4 ;
        RECT 434.025 0.000 434.165 0.560 ;
    END
  END ifu_cp0_icache_read_data[58]
  PIN ifu_cp0_icache_read_data[59]
    DIRECTION OUTPUT ;
    USE SIGNAL ;
    PORT
      LAYER metal6 ;
        RECT 432.905 0.000 433.045 0.560 ;
    END
  END ifu_cp0_icache_read_data[59]
  PIN ifu_cp0_icache_read_data[5]
    DIRECTION OUTPUT ;
    USE SIGNAL ;
    PORT
      LAYER metal6 ;
        RECT 463.145 0.000 463.285 0.560 ;
    END
  END ifu_cp0_icache_read_data[5]
  PIN ifu_cp0_icache_read_data[60]
    DIRECTION OUTPUT ;
    USE SIGNAL ;
    PORT
      LAYER metal4 ;
        RECT 432.905 0.000 433.045 0.560 ;
    END
  END ifu_cp0_icache_read_data[60]
  PIN ifu_cp0_icache_read_data[61]
    DIRECTION OUTPUT ;
    USE SIGNAL ;
    PORT
      LAYER metal6 ;
        RECT 431.785 0.000 431.925 0.560 ;
    END
  END ifu_cp0_icache_read_data[61]
  PIN ifu_cp0_icache_read_data[62]
    DIRECTION OUTPUT ;
    USE SIGNAL ;
    PORT
      LAYER metal4 ;
        RECT 431.785 0.000 431.925 0.560 ;
    END
  END ifu_cp0_icache_read_data[62]
  PIN ifu_cp0_icache_read_data[63]
    DIRECTION OUTPUT ;
    USE SIGNAL ;
    PORT
      LAYER metal6 ;
        RECT 430.665 0.000 430.805 0.560 ;
    END
  END ifu_cp0_icache_read_data[63]
  PIN ifu_cp0_icache_read_data[64]
    DIRECTION OUTPUT ;
    USE SIGNAL ;
    PORT
      LAYER metal4 ;
        RECT 430.665 0.000 430.805 0.560 ;
    END
  END ifu_cp0_icache_read_data[64]
  PIN ifu_cp0_icache_read_data[65]
    DIRECTION OUTPUT ;
    USE SIGNAL ;
    PORT
      LAYER metal6 ;
        RECT 429.545 0.000 429.685 0.560 ;
    END
  END ifu_cp0_icache_read_data[65]
  PIN ifu_cp0_icache_read_data[66]
    DIRECTION OUTPUT ;
    USE SIGNAL ;
    PORT
      LAYER metal4 ;
        RECT 429.545 0.000 429.685 0.560 ;
    END
  END ifu_cp0_icache_read_data[66]
  PIN ifu_cp0_icache_read_data[67]
    DIRECTION OUTPUT ;
    USE SIGNAL ;
    PORT
      LAYER metal6 ;
        RECT 428.425 0.000 428.565 0.560 ;
    END
  END ifu_cp0_icache_read_data[67]
  PIN ifu_cp0_icache_read_data[68]
    DIRECTION OUTPUT ;
    USE SIGNAL ;
    PORT
      LAYER metal4 ;
        RECT 428.425 0.000 428.565 0.560 ;
    END
  END ifu_cp0_icache_read_data[68]
  PIN ifu_cp0_icache_read_data[69]
    DIRECTION OUTPUT ;
    USE SIGNAL ;
    PORT
      LAYER metal6 ;
        RECT 427.305 0.000 427.445 0.560 ;
    END
  END ifu_cp0_icache_read_data[69]
  PIN ifu_cp0_icache_read_data[6]
    DIRECTION OUTPUT ;
    USE SIGNAL ;
    PORT
      LAYER metal4 ;
        RECT 463.145 0.000 463.285 0.560 ;
    END
  END ifu_cp0_icache_read_data[6]
  PIN ifu_cp0_icache_read_data[70]
    DIRECTION OUTPUT ;
    USE SIGNAL ;
    PORT
      LAYER metal4 ;
        RECT 427.305 0.000 427.445 0.560 ;
    END
  END ifu_cp0_icache_read_data[70]
  PIN ifu_cp0_icache_read_data[71]
    DIRECTION OUTPUT ;
    USE SIGNAL ;
    PORT
      LAYER metal6 ;
        RECT 426.185 0.000 426.325 0.560 ;
    END
  END ifu_cp0_icache_read_data[71]
  PIN ifu_cp0_icache_read_data[72]
    DIRECTION OUTPUT ;
    USE SIGNAL ;
    PORT
      LAYER metal4 ;
        RECT 426.185 0.000 426.325 0.560 ;
    END
  END ifu_cp0_icache_read_data[72]
  PIN ifu_cp0_icache_read_data[73]
    DIRECTION OUTPUT ;
    USE SIGNAL ;
    PORT
      LAYER metal6 ;
        RECT 425.065 0.000 425.205 0.560 ;
    END
  END ifu_cp0_icache_read_data[73]
  PIN ifu_cp0_icache_read_data[74]
    DIRECTION OUTPUT ;
    USE SIGNAL ;
    PORT
      LAYER metal4 ;
        RECT 425.065 0.000 425.205 0.560 ;
    END
  END ifu_cp0_icache_read_data[74]
  PIN ifu_cp0_icache_read_data[75]
    DIRECTION OUTPUT ;
    USE SIGNAL ;
    PORT
      LAYER metal6 ;
        RECT 423.945 0.000 424.085 0.560 ;
    END
  END ifu_cp0_icache_read_data[75]
  PIN ifu_cp0_icache_read_data[76]
    DIRECTION OUTPUT ;
    USE SIGNAL ;
    PORT
      LAYER metal4 ;
        RECT 423.945 0.000 424.085 0.560 ;
    END
  END ifu_cp0_icache_read_data[76]
  PIN ifu_cp0_icache_read_data[77]
    DIRECTION OUTPUT ;
    USE SIGNAL ;
    PORT
      LAYER metal6 ;
        RECT 422.825 0.000 422.965 0.560 ;
    END
  END ifu_cp0_icache_read_data[77]
  PIN ifu_cp0_icache_read_data[78]
    DIRECTION OUTPUT ;
    USE SIGNAL ;
    PORT
      LAYER metal4 ;
        RECT 422.825 0.000 422.965 0.560 ;
    END
  END ifu_cp0_icache_read_data[78]
  PIN ifu_cp0_icache_read_data[79]
    DIRECTION OUTPUT ;
    USE SIGNAL ;
    PORT
      LAYER metal6 ;
        RECT 421.705 0.000 421.845 0.560 ;
    END
  END ifu_cp0_icache_read_data[79]
  PIN ifu_cp0_icache_read_data[7]
    DIRECTION OUTPUT ;
    USE SIGNAL ;
    PORT
      LAYER metal6 ;
        RECT 462.025 0.000 462.165 0.560 ;
    END
  END ifu_cp0_icache_read_data[7]
  PIN ifu_cp0_icache_read_data[80]
    DIRECTION OUTPUT ;
    USE SIGNAL ;
    PORT
      LAYER metal4 ;
        RECT 421.705 0.000 421.845 0.560 ;
    END
  END ifu_cp0_icache_read_data[80]
  PIN ifu_cp0_icache_read_data[81]
    DIRECTION OUTPUT ;
    USE SIGNAL ;
    PORT
      LAYER metal6 ;
        RECT 420.585 0.000 420.725 0.560 ;
    END
  END ifu_cp0_icache_read_data[81]
  PIN ifu_cp0_icache_read_data[82]
    DIRECTION OUTPUT ;
    USE SIGNAL ;
    PORT
      LAYER metal4 ;
        RECT 420.585 0.000 420.725 0.560 ;
    END
  END ifu_cp0_icache_read_data[82]
  PIN ifu_cp0_icache_read_data[83]
    DIRECTION OUTPUT ;
    USE SIGNAL ;
    PORT
      LAYER metal6 ;
        RECT 419.465 0.000 419.605 0.560 ;
    END
  END ifu_cp0_icache_read_data[83]
  PIN ifu_cp0_icache_read_data[84]
    DIRECTION OUTPUT ;
    USE SIGNAL ;
    PORT
      LAYER metal4 ;
        RECT 419.465 0.000 419.605 0.560 ;
    END
  END ifu_cp0_icache_read_data[84]
  PIN ifu_cp0_icache_read_data[85]
    DIRECTION OUTPUT ;
    USE SIGNAL ;
    PORT
      LAYER metal6 ;
        RECT 418.345 0.000 418.485 0.560 ;
    END
  END ifu_cp0_icache_read_data[85]
  PIN ifu_cp0_icache_read_data[86]
    DIRECTION OUTPUT ;
    USE SIGNAL ;
    PORT
      LAYER metal4 ;
        RECT 418.345 0.000 418.485 0.560 ;
    END
  END ifu_cp0_icache_read_data[86]
  PIN ifu_cp0_icache_read_data[87]
    DIRECTION OUTPUT ;
    USE SIGNAL ;
    PORT
      LAYER metal6 ;
        RECT 417.225 0.000 417.365 0.560 ;
    END
  END ifu_cp0_icache_read_data[87]
  PIN ifu_cp0_icache_read_data[88]
    DIRECTION OUTPUT ;
    USE SIGNAL ;
    PORT
      LAYER metal4 ;
        RECT 417.225 0.000 417.365 0.560 ;
    END
  END ifu_cp0_icache_read_data[88]
  PIN ifu_cp0_icache_read_data[89]
    DIRECTION OUTPUT ;
    USE SIGNAL ;
    PORT
      LAYER metal6 ;
        RECT 416.105 0.000 416.245 0.560 ;
    END
  END ifu_cp0_icache_read_data[89]
  PIN ifu_cp0_icache_read_data[8]
    DIRECTION OUTPUT ;
    USE SIGNAL ;
    PORT
      LAYER metal4 ;
        RECT 462.025 0.000 462.165 0.560 ;
    END
  END ifu_cp0_icache_read_data[8]
  PIN ifu_cp0_icache_read_data[90]
    DIRECTION OUTPUT ;
    USE SIGNAL ;
    PORT
      LAYER metal4 ;
        RECT 416.105 0.000 416.245 0.560 ;
    END
  END ifu_cp0_icache_read_data[90]
  PIN ifu_cp0_icache_read_data[91]
    DIRECTION OUTPUT ;
    USE SIGNAL ;
    PORT
      LAYER metal6 ;
        RECT 414.985 0.000 415.125 0.560 ;
    END
  END ifu_cp0_icache_read_data[91]
  PIN ifu_cp0_icache_read_data[92]
    DIRECTION OUTPUT ;
    USE SIGNAL ;
    PORT
      LAYER metal4 ;
        RECT 414.985 0.000 415.125 0.560 ;
    END
  END ifu_cp0_icache_read_data[92]
  PIN ifu_cp0_icache_read_data[93]
    DIRECTION OUTPUT ;
    USE SIGNAL ;
    PORT
      LAYER metal6 ;
        RECT 413.865 0.000 414.005 0.560 ;
    END
  END ifu_cp0_icache_read_data[93]
  PIN ifu_cp0_icache_read_data[94]
    DIRECTION OUTPUT ;
    USE SIGNAL ;
    PORT
      LAYER metal4 ;
        RECT 413.865 0.000 414.005 0.560 ;
    END
  END ifu_cp0_icache_read_data[94]
  PIN ifu_cp0_icache_read_data[95]
    DIRECTION OUTPUT ;
    USE SIGNAL ;
    PORT
      LAYER metal6 ;
        RECT 412.745 0.000 412.885 0.560 ;
    END
  END ifu_cp0_icache_read_data[95]
  PIN ifu_cp0_icache_read_data[96]
    DIRECTION OUTPUT ;
    USE SIGNAL ;
    PORT
      LAYER metal4 ;
        RECT 412.745 0.000 412.885 0.560 ;
    END
  END ifu_cp0_icache_read_data[96]
  PIN ifu_cp0_icache_read_data[97]
    DIRECTION OUTPUT ;
    USE SIGNAL ;
    PORT
      LAYER metal6 ;
        RECT 411.625 0.000 411.765 0.560 ;
    END
  END ifu_cp0_icache_read_data[97]
  PIN ifu_cp0_icache_read_data[98]
    DIRECTION OUTPUT ;
    USE SIGNAL ;
    PORT
      LAYER metal4 ;
        RECT 411.625 0.000 411.765 0.560 ;
    END
  END ifu_cp0_icache_read_data[98]
  PIN ifu_cp0_icache_read_data[99]
    DIRECTION OUTPUT ;
    USE SIGNAL ;
    PORT
      LAYER metal6 ;
        RECT 410.505 0.000 410.645 0.560 ;
    END
  END ifu_cp0_icache_read_data[99]
  PIN ifu_cp0_icache_read_data[9]
    DIRECTION OUTPUT ;
    USE SIGNAL ;
    PORT
      LAYER metal6 ;
        RECT 460.905 0.000 461.045 0.560 ;
    END
  END ifu_cp0_icache_read_data[9]
  PIN ifu_cp0_icache_read_data_vld
    DIRECTION OUTPUT ;
    USE SIGNAL ;
    PORT
      LAYER metal6 ;
        RECT 466.505 0.000 466.645 0.560 ;
    END
  END ifu_cp0_icache_read_data_vld
  PIN ifu_cp0_ind_btb_inv_done
    DIRECTION OUTPUT ;
    USE SIGNAL ;
    PORT
      LAYER metal4 ;
        RECT 467.625 0.000 467.765 0.560 ;
    END
  END ifu_cp0_ind_btb_inv_done
  PIN ifu_cp0_rst_inv_req
    DIRECTION OUTPUT ;
    USE SIGNAL ;
    PORT
      LAYER metal6 ;
        RECT 467.625 0.000 467.765 0.560 ;
    END
  END ifu_cp0_rst_inv_req
  PIN ifu_had_debug_info[0]
    DIRECTION OUTPUT ;
    USE SIGNAL ;
    PORT
      LAYER metal4 ;
        RECT 514.665 0.000 514.805 0.560 ;
    END
  END ifu_had_debug_info[0]
  PIN ifu_had_debug_info[10]
    DIRECTION OUTPUT ;
    USE SIGNAL ;
    PORT
      LAYER metal4 ;
        RECT 509.065 0.000 509.205 0.560 ;
    END
  END ifu_had_debug_info[10]
  PIN ifu_had_debug_info[11]
    DIRECTION OUTPUT ;
    USE SIGNAL ;
    PORT
      LAYER metal6 ;
        RECT 507.945 0.000 508.085 0.560 ;
    END
  END ifu_had_debug_info[11]
  PIN ifu_had_debug_info[12]
    DIRECTION OUTPUT ;
    USE SIGNAL ;
    PORT
      LAYER metal4 ;
        RECT 507.945 0.000 508.085 0.560 ;
    END
  END ifu_had_debug_info[12]
  PIN ifu_had_debug_info[13]
    DIRECTION OUTPUT ;
    USE SIGNAL ;
    PORT
      LAYER metal6 ;
        RECT 506.825 0.000 506.965 0.560 ;
    END
  END ifu_had_debug_info[13]
  PIN ifu_had_debug_info[14]
    DIRECTION OUTPUT ;
    USE SIGNAL ;
    PORT
      LAYER metal4 ;
        RECT 506.825 0.000 506.965 0.560 ;
    END
  END ifu_had_debug_info[14]
  PIN ifu_had_debug_info[15]
    DIRECTION OUTPUT ;
    USE SIGNAL ;
    PORT
      LAYER metal6 ;
        RECT 505.705 0.000 505.845 0.560 ;
    END
  END ifu_had_debug_info[15]
  PIN ifu_had_debug_info[16]
    DIRECTION OUTPUT ;
    USE SIGNAL ;
    PORT
      LAYER metal4 ;
        RECT 505.705 0.000 505.845 0.560 ;
    END
  END ifu_had_debug_info[16]
  PIN ifu_had_debug_info[17]
    DIRECTION OUTPUT ;
    USE SIGNAL ;
    PORT
      LAYER metal6 ;
        RECT 504.585 0.000 504.725 0.560 ;
    END
  END ifu_had_debug_info[17]
  PIN ifu_had_debug_info[18]
    DIRECTION OUTPUT ;
    USE SIGNAL ;
    PORT
      LAYER metal4 ;
        RECT 504.585 0.000 504.725 0.560 ;
    END
  END ifu_had_debug_info[18]
  PIN ifu_had_debug_info[19]
    DIRECTION OUTPUT ;
    USE SIGNAL ;
    PORT
      LAYER metal6 ;
        RECT 503.465 0.000 503.605 0.560 ;
    END
  END ifu_had_debug_info[19]
  PIN ifu_had_debug_info[1]
    DIRECTION OUTPUT ;
    USE SIGNAL ;
    PORT
      LAYER metal6 ;
        RECT 513.545 0.000 513.685 0.560 ;
    END
  END ifu_had_debug_info[1]
  PIN ifu_had_debug_info[20]
    DIRECTION OUTPUT ;
    USE SIGNAL ;
    PORT
      LAYER metal4 ;
        RECT 503.465 0.000 503.605 0.560 ;
    END
  END ifu_had_debug_info[20]
  PIN ifu_had_debug_info[21]
    DIRECTION OUTPUT ;
    USE SIGNAL ;
    PORT
      LAYER metal6 ;
        RECT 502.345 0.000 502.485 0.560 ;
    END
  END ifu_had_debug_info[21]
  PIN ifu_had_debug_info[22]
    DIRECTION OUTPUT ;
    USE SIGNAL ;
    PORT
      LAYER metal4 ;
        RECT 502.345 0.000 502.485 0.560 ;
    END
  END ifu_had_debug_info[22]
  PIN ifu_had_debug_info[23]
    DIRECTION OUTPUT ;
    USE SIGNAL ;
    PORT
      LAYER metal6 ;
        RECT 501.225 0.000 501.365 0.560 ;
    END
  END ifu_had_debug_info[23]
  PIN ifu_had_debug_info[24]
    DIRECTION OUTPUT ;
    USE SIGNAL ;
    PORT
      LAYER metal4 ;
        RECT 501.225 0.000 501.365 0.560 ;
    END
  END ifu_had_debug_info[24]
  PIN ifu_had_debug_info[25]
    DIRECTION OUTPUT ;
    USE SIGNAL ;
    PORT
      LAYER metal6 ;
        RECT 500.105 0.000 500.245 0.560 ;
    END
  END ifu_had_debug_info[25]
  PIN ifu_had_debug_info[26]
    DIRECTION OUTPUT ;
    USE SIGNAL ;
    PORT
      LAYER metal4 ;
        RECT 500.105 0.000 500.245 0.560 ;
    END
  END ifu_had_debug_info[26]
  PIN ifu_had_debug_info[27]
    DIRECTION OUTPUT ;
    USE SIGNAL ;
    PORT
      LAYER metal6 ;
        RECT 498.985 0.000 499.125 0.560 ;
    END
  END ifu_had_debug_info[27]
  PIN ifu_had_debug_info[28]
    DIRECTION OUTPUT ;
    USE SIGNAL ;
    PORT
      LAYER metal4 ;
        RECT 498.985 0.000 499.125 0.560 ;
    END
  END ifu_had_debug_info[28]
  PIN ifu_had_debug_info[29]
    DIRECTION OUTPUT ;
    USE SIGNAL ;
    PORT
      LAYER metal6 ;
        RECT 497.865 0.000 498.005 0.560 ;
    END
  END ifu_had_debug_info[29]
  PIN ifu_had_debug_info[2]
    DIRECTION OUTPUT ;
    USE SIGNAL ;
    PORT
      LAYER metal4 ;
        RECT 513.545 0.000 513.685 0.560 ;
    END
  END ifu_had_debug_info[2]
  PIN ifu_had_debug_info[30]
    DIRECTION OUTPUT ;
    USE SIGNAL ;
    PORT
      LAYER metal4 ;
        RECT 497.865 0.000 498.005 0.560 ;
    END
  END ifu_had_debug_info[30]
  PIN ifu_had_debug_info[31]
    DIRECTION OUTPUT ;
    USE SIGNAL ;
    PORT
      LAYER metal6 ;
        RECT 496.745 0.000 496.885 0.560 ;
    END
  END ifu_had_debug_info[31]
  PIN ifu_had_debug_info[32]
    DIRECTION OUTPUT ;
    USE SIGNAL ;
    PORT
      LAYER metal4 ;
        RECT 496.745 0.000 496.885 0.560 ;
    END
  END ifu_had_debug_info[32]
  PIN ifu_had_debug_info[33]
    DIRECTION OUTPUT ;
    USE SIGNAL ;
    PORT
      LAYER metal6 ;
        RECT 495.625 0.000 495.765 0.560 ;
    END
  END ifu_had_debug_info[33]
  PIN ifu_had_debug_info[34]
    DIRECTION OUTPUT ;
    USE SIGNAL ;
    PORT
      LAYER metal4 ;
        RECT 495.625 0.000 495.765 0.560 ;
    END
  END ifu_had_debug_info[34]
  PIN ifu_had_debug_info[35]
    DIRECTION OUTPUT ;
    USE SIGNAL ;
    PORT
      LAYER metal6 ;
        RECT 494.505 0.000 494.645 0.560 ;
    END
  END ifu_had_debug_info[35]
  PIN ifu_had_debug_info[36]
    DIRECTION OUTPUT ;
    USE SIGNAL ;
    PORT
      LAYER metal4 ;
        RECT 494.505 0.000 494.645 0.560 ;
    END
  END ifu_had_debug_info[36]
  PIN ifu_had_debug_info[37]
    DIRECTION OUTPUT ;
    USE SIGNAL ;
    PORT
      LAYER metal6 ;
        RECT 493.385 0.000 493.525 0.560 ;
    END
  END ifu_had_debug_info[37]
  PIN ifu_had_debug_info[38]
    DIRECTION OUTPUT ;
    USE SIGNAL ;
    PORT
      LAYER metal4 ;
        RECT 493.385 0.000 493.525 0.560 ;
    END
  END ifu_had_debug_info[38]
  PIN ifu_had_debug_info[39]
    DIRECTION OUTPUT ;
    USE SIGNAL ;
    PORT
      LAYER metal6 ;
        RECT 492.265 0.000 492.405 0.560 ;
    END
  END ifu_had_debug_info[39]
  PIN ifu_had_debug_info[3]
    DIRECTION OUTPUT ;
    USE SIGNAL ;
    PORT
      LAYER metal6 ;
        RECT 512.425 0.000 512.565 0.560 ;
    END
  END ifu_had_debug_info[3]
  PIN ifu_had_debug_info[40]
    DIRECTION OUTPUT ;
    USE SIGNAL ;
    PORT
      LAYER metal4 ;
        RECT 492.265 0.000 492.405 0.560 ;
    END
  END ifu_had_debug_info[40]
  PIN ifu_had_debug_info[41]
    DIRECTION OUTPUT ;
    USE SIGNAL ;
    PORT
      LAYER metal6 ;
        RECT 491.145 0.000 491.285 0.560 ;
    END
  END ifu_had_debug_info[41]
  PIN ifu_had_debug_info[42]
    DIRECTION OUTPUT ;
    USE SIGNAL ;
    PORT
      LAYER metal4 ;
        RECT 491.145 0.000 491.285 0.560 ;
    END
  END ifu_had_debug_info[42]
  PIN ifu_had_debug_info[43]
    DIRECTION OUTPUT ;
    USE SIGNAL ;
    PORT
      LAYER metal6 ;
        RECT 490.025 0.000 490.165 0.560 ;
    END
  END ifu_had_debug_info[43]
  PIN ifu_had_debug_info[44]
    DIRECTION OUTPUT ;
    USE SIGNAL ;
    PORT
      LAYER metal4 ;
        RECT 490.025 0.000 490.165 0.560 ;
    END
  END ifu_had_debug_info[44]
  PIN ifu_had_debug_info[45]
    DIRECTION OUTPUT ;
    USE SIGNAL ;
    PORT
      LAYER metal6 ;
        RECT 488.905 0.000 489.045 0.560 ;
    END
  END ifu_had_debug_info[45]
  PIN ifu_had_debug_info[46]
    DIRECTION OUTPUT ;
    USE SIGNAL ;
    PORT
      LAYER metal4 ;
        RECT 488.905 0.000 489.045 0.560 ;
    END
  END ifu_had_debug_info[46]
  PIN ifu_had_debug_info[47]
    DIRECTION OUTPUT ;
    USE SIGNAL ;
    PORT
      LAYER metal6 ;
        RECT 487.785 0.000 487.925 0.560 ;
    END
  END ifu_had_debug_info[47]
  PIN ifu_had_debug_info[48]
    DIRECTION OUTPUT ;
    USE SIGNAL ;
    PORT
      LAYER metal4 ;
        RECT 487.785 0.000 487.925 0.560 ;
    END
  END ifu_had_debug_info[48]
  PIN ifu_had_debug_info[49]
    DIRECTION OUTPUT ;
    USE SIGNAL ;
    PORT
      LAYER metal6 ;
        RECT 486.665 0.000 486.805 0.560 ;
    END
  END ifu_had_debug_info[49]
  PIN ifu_had_debug_info[4]
    DIRECTION OUTPUT ;
    USE SIGNAL ;
    PORT
      LAYER metal4 ;
        RECT 512.425 0.000 512.565 0.560 ;
    END
  END ifu_had_debug_info[4]
  PIN ifu_had_debug_info[50]
    DIRECTION OUTPUT ;
    USE SIGNAL ;
    PORT
      LAYER metal4 ;
        RECT 486.665 0.000 486.805 0.560 ;
    END
  END ifu_had_debug_info[50]
  PIN ifu_had_debug_info[51]
    DIRECTION OUTPUT ;
    USE SIGNAL ;
    PORT
      LAYER metal6 ;
        RECT 485.545 0.000 485.685 0.560 ;
    END
  END ifu_had_debug_info[51]
  PIN ifu_had_debug_info[52]
    DIRECTION OUTPUT ;
    USE SIGNAL ;
    PORT
      LAYER metal4 ;
        RECT 485.545 0.000 485.685 0.560 ;
    END
  END ifu_had_debug_info[52]
  PIN ifu_had_debug_info[53]
    DIRECTION OUTPUT ;
    USE SIGNAL ;
    PORT
      LAYER metal6 ;
        RECT 484.425 0.000 484.565 0.560 ;
    END
  END ifu_had_debug_info[53]
  PIN ifu_had_debug_info[54]
    DIRECTION OUTPUT ;
    USE SIGNAL ;
    PORT
      LAYER metal4 ;
        RECT 484.425 0.000 484.565 0.560 ;
    END
  END ifu_had_debug_info[54]
  PIN ifu_had_debug_info[55]
    DIRECTION OUTPUT ;
    USE SIGNAL ;
    PORT
      LAYER metal6 ;
        RECT 483.305 0.000 483.445 0.560 ;
    END
  END ifu_had_debug_info[55]
  PIN ifu_had_debug_info[56]
    DIRECTION OUTPUT ;
    USE SIGNAL ;
    PORT
      LAYER metal4 ;
        RECT 483.305 0.000 483.445 0.560 ;
    END
  END ifu_had_debug_info[56]
  PIN ifu_had_debug_info[57]
    DIRECTION OUTPUT ;
    USE SIGNAL ;
    PORT
      LAYER metal6 ;
        RECT 482.185 0.000 482.325 0.560 ;
    END
  END ifu_had_debug_info[57]
  PIN ifu_had_debug_info[58]
    DIRECTION OUTPUT ;
    USE SIGNAL ;
    PORT
      LAYER metal4 ;
        RECT 482.185 0.000 482.325 0.560 ;
    END
  END ifu_had_debug_info[58]
  PIN ifu_had_debug_info[59]
    DIRECTION OUTPUT ;
    USE SIGNAL ;
    PORT
      LAYER metal6 ;
        RECT 481.065 0.000 481.205 0.560 ;
    END
  END ifu_had_debug_info[59]
  PIN ifu_had_debug_info[5]
    DIRECTION OUTPUT ;
    USE SIGNAL ;
    PORT
      LAYER metal6 ;
        RECT 511.305 0.000 511.445 0.560 ;
    END
  END ifu_had_debug_info[5]
  PIN ifu_had_debug_info[60]
    DIRECTION OUTPUT ;
    USE SIGNAL ;
    PORT
      LAYER metal4 ;
        RECT 481.065 0.000 481.205 0.560 ;
    END
  END ifu_had_debug_info[60]
  PIN ifu_had_debug_info[61]
    DIRECTION OUTPUT ;
    USE SIGNAL ;
    PORT
      LAYER metal6 ;
        RECT 479.945 0.000 480.085 0.560 ;
    END
  END ifu_had_debug_info[61]
  PIN ifu_had_debug_info[62]
    DIRECTION OUTPUT ;
    USE SIGNAL ;
    PORT
      LAYER metal4 ;
        RECT 479.945 0.000 480.085 0.560 ;
    END
  END ifu_had_debug_info[62]
  PIN ifu_had_debug_info[63]
    DIRECTION OUTPUT ;
    USE SIGNAL ;
    PORT
      LAYER metal6 ;
        RECT 478.825 0.000 478.965 0.560 ;
    END
  END ifu_had_debug_info[63]
  PIN ifu_had_debug_info[64]
    DIRECTION OUTPUT ;
    USE SIGNAL ;
    PORT
      LAYER metal4 ;
        RECT 478.825 0.000 478.965 0.560 ;
    END
  END ifu_had_debug_info[64]
  PIN ifu_had_debug_info[65]
    DIRECTION OUTPUT ;
    USE SIGNAL ;
    PORT
      LAYER metal6 ;
        RECT 477.705 0.000 477.845 0.560 ;
    END
  END ifu_had_debug_info[65]
  PIN ifu_had_debug_info[66]
    DIRECTION OUTPUT ;
    USE SIGNAL ;
    PORT
      LAYER metal4 ;
        RECT 477.705 0.000 477.845 0.560 ;
    END
  END ifu_had_debug_info[66]
  PIN ifu_had_debug_info[67]
    DIRECTION OUTPUT ;
    USE SIGNAL ;
    PORT
      LAYER metal6 ;
        RECT 476.585 0.000 476.725 0.560 ;
    END
  END ifu_had_debug_info[67]
  PIN ifu_had_debug_info[68]
    DIRECTION OUTPUT ;
    USE SIGNAL ;
    PORT
      LAYER metal4 ;
        RECT 476.585 0.000 476.725 0.560 ;
    END
  END ifu_had_debug_info[68]
  PIN ifu_had_debug_info[69]
    DIRECTION OUTPUT ;
    USE SIGNAL ;
    PORT
      LAYER metal6 ;
        RECT 475.465 0.000 475.605 0.560 ;
    END
  END ifu_had_debug_info[69]
  PIN ifu_had_debug_info[6]
    DIRECTION OUTPUT ;
    USE SIGNAL ;
    PORT
      LAYER metal4 ;
        RECT 511.305 0.000 511.445 0.560 ;
    END
  END ifu_had_debug_info[6]
  PIN ifu_had_debug_info[70]
    DIRECTION OUTPUT ;
    USE SIGNAL ;
    PORT
      LAYER metal4 ;
        RECT 475.465 0.000 475.605 0.560 ;
    END
  END ifu_had_debug_info[70]
  PIN ifu_had_debug_info[71]
    DIRECTION OUTPUT ;
    USE SIGNAL ;
    PORT
      LAYER metal6 ;
        RECT 474.345 0.000 474.485 0.560 ;
    END
  END ifu_had_debug_info[71]
  PIN ifu_had_debug_info[72]
    DIRECTION OUTPUT ;
    USE SIGNAL ;
    PORT
      LAYER metal4 ;
        RECT 474.345 0.000 474.485 0.560 ;
    END
  END ifu_had_debug_info[72]
  PIN ifu_had_debug_info[73]
    DIRECTION OUTPUT ;
    USE SIGNAL ;
    PORT
      LAYER metal6 ;
        RECT 473.225 0.000 473.365 0.560 ;
    END
  END ifu_had_debug_info[73]
  PIN ifu_had_debug_info[74]
    DIRECTION OUTPUT ;
    USE SIGNAL ;
    PORT
      LAYER metal4 ;
        RECT 473.225 0.000 473.365 0.560 ;
    END
  END ifu_had_debug_info[74]
  PIN ifu_had_debug_info[75]
    DIRECTION OUTPUT ;
    USE SIGNAL ;
    PORT
      LAYER metal6 ;
        RECT 472.105 0.000 472.245 0.560 ;
    END
  END ifu_had_debug_info[75]
  PIN ifu_had_debug_info[76]
    DIRECTION OUTPUT ;
    USE SIGNAL ;
    PORT
      LAYER metal4 ;
        RECT 472.105 0.000 472.245 0.560 ;
    END
  END ifu_had_debug_info[76]
  PIN ifu_had_debug_info[77]
    DIRECTION OUTPUT ;
    USE SIGNAL ;
    PORT
      LAYER metal6 ;
        RECT 470.985 0.000 471.125 0.560 ;
    END
  END ifu_had_debug_info[77]
  PIN ifu_had_debug_info[78]
    DIRECTION OUTPUT ;
    USE SIGNAL ;
    PORT
      LAYER metal4 ;
        RECT 470.985 0.000 471.125 0.560 ;
    END
  END ifu_had_debug_info[78]
  PIN ifu_had_debug_info[79]
    DIRECTION OUTPUT ;
    USE SIGNAL ;
    PORT
      LAYER metal6 ;
        RECT 469.865 0.000 470.005 0.560 ;
    END
  END ifu_had_debug_info[79]
  PIN ifu_had_debug_info[7]
    DIRECTION OUTPUT ;
    USE SIGNAL ;
    PORT
      LAYER metal6 ;
        RECT 510.185 0.000 510.325 0.560 ;
    END
  END ifu_had_debug_info[7]
  PIN ifu_had_debug_info[80]
    DIRECTION OUTPUT ;
    USE SIGNAL ;
    PORT
      LAYER metal4 ;
        RECT 469.865 0.000 470.005 0.560 ;
    END
  END ifu_had_debug_info[80]
  PIN ifu_had_debug_info[81]
    DIRECTION OUTPUT ;
    USE SIGNAL ;
    PORT
      LAYER metal6 ;
        RECT 468.745 0.000 468.885 0.560 ;
    END
  END ifu_had_debug_info[81]
  PIN ifu_had_debug_info[82]
    DIRECTION OUTPUT ;
    USE SIGNAL ;
    PORT
      LAYER metal4 ;
        RECT 468.745 0.000 468.885 0.560 ;
    END
  END ifu_had_debug_info[82]
  PIN ifu_had_debug_info[8]
    DIRECTION OUTPUT ;
    USE SIGNAL ;
    PORT
      LAYER metal4 ;
        RECT 510.185 0.000 510.325 0.560 ;
    END
  END ifu_had_debug_info[8]
  PIN ifu_had_debug_info[9]
    DIRECTION OUTPUT ;
    USE SIGNAL ;
    PORT
      LAYER metal6 ;
        RECT 509.065 0.000 509.205 0.560 ;
    END
  END ifu_had_debug_info[9]
  PIN ifu_had_no_inst
    DIRECTION OUTPUT ;
    USE SIGNAL ;
    PORT
      LAYER metal6 ;
        RECT 514.665 0.000 514.805 0.560 ;
    END
  END ifu_had_no_inst
  PIN ifu_had_no_op
    DIRECTION OUTPUT ;
    USE SIGNAL ;
    PORT
      LAYER metal4 ;
        RECT 515.785 0.000 515.925 0.560 ;
    END
  END ifu_had_no_op
  PIN ifu_had_reset_on
    DIRECTION OUTPUT ;
    USE SIGNAL ;
    PORT
      LAYER metal6 ;
        RECT 515.785 0.000 515.925 0.560 ;
    END
  END ifu_had_reset_on
  PIN ifu_hpcp_btb_inst
    DIRECTION OUTPUT ;
    USE SIGNAL ;
    PORT
      LAYER metal4 ;
        RECT 516.905 0.000 517.045 0.560 ;
    END
  END ifu_hpcp_btb_inst
  PIN ifu_hpcp_btb_mispred
    DIRECTION OUTPUT ;
    USE SIGNAL ;
    PORT
      LAYER metal6 ;
        RECT 516.905 0.000 517.045 0.560 ;
    END
  END ifu_hpcp_btb_mispred
  PIN ifu_hpcp_frontend_stall
    DIRECTION OUTPUT ;
    USE SIGNAL ;
    PORT
      LAYER metal4 ;
        RECT 518.025 0.000 518.165 0.560 ;
    END
  END ifu_hpcp_frontend_stall
  PIN ifu_hpcp_icache_access
    DIRECTION OUTPUT ;
    USE SIGNAL ;
    PORT
      LAYER metal6 ;
        RECT 518.025 0.000 518.165 0.560 ;
    END
  END ifu_hpcp_icache_access
  PIN ifu_hpcp_icache_miss
    DIRECTION OUTPUT ;
    USE SIGNAL ;
    PORT
      LAYER metal4 ;
        RECT 519.145 0.000 519.285 0.560 ;
    END
  END ifu_hpcp_icache_miss
  PIN ifu_idu_ib_inst0_data[0]
    DIRECTION OUTPUT ;
    USE SIGNAL ;
    PORT
      LAYER metal6 ;
        RECT 559.465 0.000 559.605 0.560 ;
    END
  END ifu_idu_ib_inst0_data[0]
  PIN ifu_idu_ib_inst0_data[10]
    DIRECTION OUTPUT ;
    USE SIGNAL ;
    PORT
      LAYER metal6 ;
        RECT 553.865 0.000 554.005 0.560 ;
    END
  END ifu_idu_ib_inst0_data[10]
  PIN ifu_idu_ib_inst0_data[11]
    DIRECTION OUTPUT ;
    USE SIGNAL ;
    PORT
      LAYER metal4 ;
        RECT 553.865 0.000 554.005 0.560 ;
    END
  END ifu_idu_ib_inst0_data[11]
  PIN ifu_idu_ib_inst0_data[12]
    DIRECTION OUTPUT ;
    USE SIGNAL ;
    PORT
      LAYER metal6 ;
        RECT 552.745 0.000 552.885 0.560 ;
    END
  END ifu_idu_ib_inst0_data[12]
  PIN ifu_idu_ib_inst0_data[13]
    DIRECTION OUTPUT ;
    USE SIGNAL ;
    PORT
      LAYER metal4 ;
        RECT 552.745 0.000 552.885 0.560 ;
    END
  END ifu_idu_ib_inst0_data[13]
  PIN ifu_idu_ib_inst0_data[14]
    DIRECTION OUTPUT ;
    USE SIGNAL ;
    PORT
      LAYER metal6 ;
        RECT 551.625 0.000 551.765 0.560 ;
    END
  END ifu_idu_ib_inst0_data[14]
  PIN ifu_idu_ib_inst0_data[15]
    DIRECTION OUTPUT ;
    USE SIGNAL ;
    PORT
      LAYER metal4 ;
        RECT 551.625 0.000 551.765 0.560 ;
    END
  END ifu_idu_ib_inst0_data[15]
  PIN ifu_idu_ib_inst0_data[16]
    DIRECTION OUTPUT ;
    USE SIGNAL ;
    PORT
      LAYER metal6 ;
        RECT 550.505 0.000 550.645 0.560 ;
    END
  END ifu_idu_ib_inst0_data[16]
  PIN ifu_idu_ib_inst0_data[17]
    DIRECTION OUTPUT ;
    USE SIGNAL ;
    PORT
      LAYER metal4 ;
        RECT 550.505 0.000 550.645 0.560 ;
    END
  END ifu_idu_ib_inst0_data[17]
  PIN ifu_idu_ib_inst0_data[18]
    DIRECTION OUTPUT ;
    USE SIGNAL ;
    PORT
      LAYER metal6 ;
        RECT 549.385 0.000 549.525 0.560 ;
    END
  END ifu_idu_ib_inst0_data[18]
  PIN ifu_idu_ib_inst0_data[19]
    DIRECTION OUTPUT ;
    USE SIGNAL ;
    PORT
      LAYER metal4 ;
        RECT 549.385 0.000 549.525 0.560 ;
    END
  END ifu_idu_ib_inst0_data[19]
  PIN ifu_idu_ib_inst0_data[1]
    DIRECTION OUTPUT ;
    USE SIGNAL ;
    PORT
      LAYER metal4 ;
        RECT 559.465 0.000 559.605 0.560 ;
    END
  END ifu_idu_ib_inst0_data[1]
  PIN ifu_idu_ib_inst0_data[20]
    DIRECTION OUTPUT ;
    USE SIGNAL ;
    PORT
      LAYER metal6 ;
        RECT 548.265 0.000 548.405 0.560 ;
    END
  END ifu_idu_ib_inst0_data[20]
  PIN ifu_idu_ib_inst0_data[21]
    DIRECTION OUTPUT ;
    USE SIGNAL ;
    PORT
      LAYER metal4 ;
        RECT 548.265 0.000 548.405 0.560 ;
    END
  END ifu_idu_ib_inst0_data[21]
  PIN ifu_idu_ib_inst0_data[22]
    DIRECTION OUTPUT ;
    USE SIGNAL ;
    PORT
      LAYER metal6 ;
        RECT 547.145 0.000 547.285 0.560 ;
    END
  END ifu_idu_ib_inst0_data[22]
  PIN ifu_idu_ib_inst0_data[23]
    DIRECTION OUTPUT ;
    USE SIGNAL ;
    PORT
      LAYER metal4 ;
        RECT 547.145 0.000 547.285 0.560 ;
    END
  END ifu_idu_ib_inst0_data[23]
  PIN ifu_idu_ib_inst0_data[24]
    DIRECTION OUTPUT ;
    USE SIGNAL ;
    PORT
      LAYER metal6 ;
        RECT 546.025 0.000 546.165 0.560 ;
    END
  END ifu_idu_ib_inst0_data[24]
  PIN ifu_idu_ib_inst0_data[25]
    DIRECTION OUTPUT ;
    USE SIGNAL ;
    PORT
      LAYER metal4 ;
        RECT 546.025 0.000 546.165 0.560 ;
    END
  END ifu_idu_ib_inst0_data[25]
  PIN ifu_idu_ib_inst0_data[26]
    DIRECTION OUTPUT ;
    USE SIGNAL ;
    PORT
      LAYER metal6 ;
        RECT 544.905 0.000 545.045 0.560 ;
    END
  END ifu_idu_ib_inst0_data[26]
  PIN ifu_idu_ib_inst0_data[27]
    DIRECTION OUTPUT ;
    USE SIGNAL ;
    PORT
      LAYER metal4 ;
        RECT 544.905 0.000 545.045 0.560 ;
    END
  END ifu_idu_ib_inst0_data[27]
  PIN ifu_idu_ib_inst0_data[28]
    DIRECTION OUTPUT ;
    USE SIGNAL ;
    PORT
      LAYER metal6 ;
        RECT 543.785 0.000 543.925 0.560 ;
    END
  END ifu_idu_ib_inst0_data[28]
  PIN ifu_idu_ib_inst0_data[29]
    DIRECTION OUTPUT ;
    USE SIGNAL ;
    PORT
      LAYER metal4 ;
        RECT 543.785 0.000 543.925 0.560 ;
    END
  END ifu_idu_ib_inst0_data[29]
  PIN ifu_idu_ib_inst0_data[2]
    DIRECTION OUTPUT ;
    USE SIGNAL ;
    PORT
      LAYER metal6 ;
        RECT 558.345 0.000 558.485 0.560 ;
    END
  END ifu_idu_ib_inst0_data[2]
  PIN ifu_idu_ib_inst0_data[30]
    DIRECTION OUTPUT ;
    USE SIGNAL ;
    PORT
      LAYER metal6 ;
        RECT 542.665 0.000 542.805 0.560 ;
    END
  END ifu_idu_ib_inst0_data[30]
  PIN ifu_idu_ib_inst0_data[31]
    DIRECTION OUTPUT ;
    USE SIGNAL ;
    PORT
      LAYER metal4 ;
        RECT 542.665 0.000 542.805 0.560 ;
    END
  END ifu_idu_ib_inst0_data[31]
  PIN ifu_idu_ib_inst0_data[32]
    DIRECTION OUTPUT ;
    USE SIGNAL ;
    PORT
      LAYER metal6 ;
        RECT 541.545 0.000 541.685 0.560 ;
    END
  END ifu_idu_ib_inst0_data[32]
  PIN ifu_idu_ib_inst0_data[33]
    DIRECTION OUTPUT ;
    USE SIGNAL ;
    PORT
      LAYER metal4 ;
        RECT 541.545 0.000 541.685 0.560 ;
    END
  END ifu_idu_ib_inst0_data[33]
  PIN ifu_idu_ib_inst0_data[34]
    DIRECTION OUTPUT ;
    USE SIGNAL ;
    PORT
      LAYER metal6 ;
        RECT 540.425 0.000 540.565 0.560 ;
    END
  END ifu_idu_ib_inst0_data[34]
  PIN ifu_idu_ib_inst0_data[35]
    DIRECTION OUTPUT ;
    USE SIGNAL ;
    PORT
      LAYER metal4 ;
        RECT 540.425 0.000 540.565 0.560 ;
    END
  END ifu_idu_ib_inst0_data[35]
  PIN ifu_idu_ib_inst0_data[36]
    DIRECTION OUTPUT ;
    USE SIGNAL ;
    PORT
      LAYER metal6 ;
        RECT 539.305 0.000 539.445 0.560 ;
    END
  END ifu_idu_ib_inst0_data[36]
  PIN ifu_idu_ib_inst0_data[37]
    DIRECTION OUTPUT ;
    USE SIGNAL ;
    PORT
      LAYER metal4 ;
        RECT 539.305 0.000 539.445 0.560 ;
    END
  END ifu_idu_ib_inst0_data[37]
  PIN ifu_idu_ib_inst0_data[38]
    DIRECTION OUTPUT ;
    USE SIGNAL ;
    PORT
      LAYER metal6 ;
        RECT 538.185 0.000 538.325 0.560 ;
    END
  END ifu_idu_ib_inst0_data[38]
  PIN ifu_idu_ib_inst0_data[39]
    DIRECTION OUTPUT ;
    USE SIGNAL ;
    PORT
      LAYER metal4 ;
        RECT 538.185 0.000 538.325 0.560 ;
    END
  END ifu_idu_ib_inst0_data[39]
  PIN ifu_idu_ib_inst0_data[3]
    DIRECTION OUTPUT ;
    USE SIGNAL ;
    PORT
      LAYER metal4 ;
        RECT 558.345 0.000 558.485 0.560 ;
    END
  END ifu_idu_ib_inst0_data[3]
  PIN ifu_idu_ib_inst0_data[40]
    DIRECTION OUTPUT ;
    USE SIGNAL ;
    PORT
      LAYER metal6 ;
        RECT 537.065 0.000 537.205 0.560 ;
    END
  END ifu_idu_ib_inst0_data[40]
  PIN ifu_idu_ib_inst0_data[41]
    DIRECTION OUTPUT ;
    USE SIGNAL ;
    PORT
      LAYER metal4 ;
        RECT 537.065 0.000 537.205 0.560 ;
    END
  END ifu_idu_ib_inst0_data[41]
  PIN ifu_idu_ib_inst0_data[42]
    DIRECTION OUTPUT ;
    USE SIGNAL ;
    PORT
      LAYER metal6 ;
        RECT 535.945 0.000 536.085 0.560 ;
    END
  END ifu_idu_ib_inst0_data[42]
  PIN ifu_idu_ib_inst0_data[43]
    DIRECTION OUTPUT ;
    USE SIGNAL ;
    PORT
      LAYER metal4 ;
        RECT 535.945 0.000 536.085 0.560 ;
    END
  END ifu_idu_ib_inst0_data[43]
  PIN ifu_idu_ib_inst0_data[44]
    DIRECTION OUTPUT ;
    USE SIGNAL ;
    PORT
      LAYER metal6 ;
        RECT 534.825 0.000 534.965 0.560 ;
    END
  END ifu_idu_ib_inst0_data[44]
  PIN ifu_idu_ib_inst0_data[45]
    DIRECTION OUTPUT ;
    USE SIGNAL ;
    PORT
      LAYER metal4 ;
        RECT 534.825 0.000 534.965 0.560 ;
    END
  END ifu_idu_ib_inst0_data[45]
  PIN ifu_idu_ib_inst0_data[46]
    DIRECTION OUTPUT ;
    USE SIGNAL ;
    PORT
      LAYER metal6 ;
        RECT 533.705 0.000 533.845 0.560 ;
    END
  END ifu_idu_ib_inst0_data[46]
  PIN ifu_idu_ib_inst0_data[47]
    DIRECTION OUTPUT ;
    USE SIGNAL ;
    PORT
      LAYER metal4 ;
        RECT 533.705 0.000 533.845 0.560 ;
    END
  END ifu_idu_ib_inst0_data[47]
  PIN ifu_idu_ib_inst0_data[48]
    DIRECTION OUTPUT ;
    USE SIGNAL ;
    PORT
      LAYER metal6 ;
        RECT 532.585 0.000 532.725 0.560 ;
    END
  END ifu_idu_ib_inst0_data[48]
  PIN ifu_idu_ib_inst0_data[49]
    DIRECTION OUTPUT ;
    USE SIGNAL ;
    PORT
      LAYER metal4 ;
        RECT 532.585 0.000 532.725 0.560 ;
    END
  END ifu_idu_ib_inst0_data[49]
  PIN ifu_idu_ib_inst0_data[4]
    DIRECTION OUTPUT ;
    USE SIGNAL ;
    PORT
      LAYER metal6 ;
        RECT 557.225 0.000 557.365 0.560 ;
    END
  END ifu_idu_ib_inst0_data[4]
  PIN ifu_idu_ib_inst0_data[50]
    DIRECTION OUTPUT ;
    USE SIGNAL ;
    PORT
      LAYER metal6 ;
        RECT 531.465 0.000 531.605 0.560 ;
    END
  END ifu_idu_ib_inst0_data[50]
  PIN ifu_idu_ib_inst0_data[51]
    DIRECTION OUTPUT ;
    USE SIGNAL ;
    PORT
      LAYER metal4 ;
        RECT 531.465 0.000 531.605 0.560 ;
    END
  END ifu_idu_ib_inst0_data[51]
  PIN ifu_idu_ib_inst0_data[52]
    DIRECTION OUTPUT ;
    USE SIGNAL ;
    PORT
      LAYER metal6 ;
        RECT 530.345 0.000 530.485 0.560 ;
    END
  END ifu_idu_ib_inst0_data[52]
  PIN ifu_idu_ib_inst0_data[53]
    DIRECTION OUTPUT ;
    USE SIGNAL ;
    PORT
      LAYER metal4 ;
        RECT 530.345 0.000 530.485 0.560 ;
    END
  END ifu_idu_ib_inst0_data[53]
  PIN ifu_idu_ib_inst0_data[54]
    DIRECTION OUTPUT ;
    USE SIGNAL ;
    PORT
      LAYER metal6 ;
        RECT 529.225 0.000 529.365 0.560 ;
    END
  END ifu_idu_ib_inst0_data[54]
  PIN ifu_idu_ib_inst0_data[55]
    DIRECTION OUTPUT ;
    USE SIGNAL ;
    PORT
      LAYER metal4 ;
        RECT 529.225 0.000 529.365 0.560 ;
    END
  END ifu_idu_ib_inst0_data[55]
  PIN ifu_idu_ib_inst0_data[56]
    DIRECTION OUTPUT ;
    USE SIGNAL ;
    PORT
      LAYER metal6 ;
        RECT 528.105 0.000 528.245 0.560 ;
    END
  END ifu_idu_ib_inst0_data[56]
  PIN ifu_idu_ib_inst0_data[57]
    DIRECTION OUTPUT ;
    USE SIGNAL ;
    PORT
      LAYER metal4 ;
        RECT 528.105 0.000 528.245 0.560 ;
    END
  END ifu_idu_ib_inst0_data[57]
  PIN ifu_idu_ib_inst0_data[58]
    DIRECTION OUTPUT ;
    USE SIGNAL ;
    PORT
      LAYER metal6 ;
        RECT 526.985 0.000 527.125 0.560 ;
    END
  END ifu_idu_ib_inst0_data[58]
  PIN ifu_idu_ib_inst0_data[59]
    DIRECTION OUTPUT ;
    USE SIGNAL ;
    PORT
      LAYER metal4 ;
        RECT 526.985 0.000 527.125 0.560 ;
    END
  END ifu_idu_ib_inst0_data[59]
  PIN ifu_idu_ib_inst0_data[5]
    DIRECTION OUTPUT ;
    USE SIGNAL ;
    PORT
      LAYER metal4 ;
        RECT 557.225 0.000 557.365 0.560 ;
    END
  END ifu_idu_ib_inst0_data[5]
  PIN ifu_idu_ib_inst0_data[60]
    DIRECTION OUTPUT ;
    USE SIGNAL ;
    PORT
      LAYER metal6 ;
        RECT 525.865 0.000 526.005 0.560 ;
    END
  END ifu_idu_ib_inst0_data[60]
  PIN ifu_idu_ib_inst0_data[61]
    DIRECTION OUTPUT ;
    USE SIGNAL ;
    PORT
      LAYER metal4 ;
        RECT 525.865 0.000 526.005 0.560 ;
    END
  END ifu_idu_ib_inst0_data[61]
  PIN ifu_idu_ib_inst0_data[62]
    DIRECTION OUTPUT ;
    USE SIGNAL ;
    PORT
      LAYER metal6 ;
        RECT 524.745 0.000 524.885 0.560 ;
    END
  END ifu_idu_ib_inst0_data[62]
  PIN ifu_idu_ib_inst0_data[63]
    DIRECTION OUTPUT ;
    USE SIGNAL ;
    PORT
      LAYER metal4 ;
        RECT 524.745 0.000 524.885 0.560 ;
    END
  END ifu_idu_ib_inst0_data[63]
  PIN ifu_idu_ib_inst0_data[64]
    DIRECTION OUTPUT ;
    USE SIGNAL ;
    PORT
      LAYER metal6 ;
        RECT 523.625 0.000 523.765 0.560 ;
    END
  END ifu_idu_ib_inst0_data[64]
  PIN ifu_idu_ib_inst0_data[65]
    DIRECTION OUTPUT ;
    USE SIGNAL ;
    PORT
      LAYER metal4 ;
        RECT 523.625 0.000 523.765 0.560 ;
    END
  END ifu_idu_ib_inst0_data[65]
  PIN ifu_idu_ib_inst0_data[66]
    DIRECTION OUTPUT ;
    USE SIGNAL ;
    PORT
      LAYER metal6 ;
        RECT 522.505 0.000 522.645 0.560 ;
    END
  END ifu_idu_ib_inst0_data[66]
  PIN ifu_idu_ib_inst0_data[67]
    DIRECTION OUTPUT ;
    USE SIGNAL ;
    PORT
      LAYER metal4 ;
        RECT 522.505 0.000 522.645 0.560 ;
    END
  END ifu_idu_ib_inst0_data[67]
  PIN ifu_idu_ib_inst0_data[68]
    DIRECTION OUTPUT ;
    USE SIGNAL ;
    PORT
      LAYER metal6 ;
        RECT 521.385 0.000 521.525 0.560 ;
    END
  END ifu_idu_ib_inst0_data[68]
  PIN ifu_idu_ib_inst0_data[69]
    DIRECTION OUTPUT ;
    USE SIGNAL ;
    PORT
      LAYER metal4 ;
        RECT 521.385 0.000 521.525 0.560 ;
    END
  END ifu_idu_ib_inst0_data[69]
  PIN ifu_idu_ib_inst0_data[6]
    DIRECTION OUTPUT ;
    USE SIGNAL ;
    PORT
      LAYER metal6 ;
        RECT 556.105 0.000 556.245 0.560 ;
    END
  END ifu_idu_ib_inst0_data[6]
  PIN ifu_idu_ib_inst0_data[70]
    DIRECTION OUTPUT ;
    USE SIGNAL ;
    PORT
      LAYER metal6 ;
        RECT 520.265 0.000 520.405 0.560 ;
    END
  END ifu_idu_ib_inst0_data[70]
  PIN ifu_idu_ib_inst0_data[71]
    DIRECTION OUTPUT ;
    USE SIGNAL ;
    PORT
      LAYER metal4 ;
        RECT 520.265 0.000 520.405 0.560 ;
    END
  END ifu_idu_ib_inst0_data[71]
  PIN ifu_idu_ib_inst0_data[72]
    DIRECTION OUTPUT ;
    USE SIGNAL ;
    PORT
      LAYER metal6 ;
        RECT 519.145 0.000 519.285 0.560 ;
    END
  END ifu_idu_ib_inst0_data[72]
  PIN ifu_idu_ib_inst0_data[7]
    DIRECTION OUTPUT ;
    USE SIGNAL ;
    PORT
      LAYER metal4 ;
        RECT 556.105 0.000 556.245 0.560 ;
    END
  END ifu_idu_ib_inst0_data[7]
  PIN ifu_idu_ib_inst0_data[8]
    DIRECTION OUTPUT ;
    USE SIGNAL ;
    PORT
      LAYER metal6 ;
        RECT 554.985 0.000 555.125 0.560 ;
    END
  END ifu_idu_ib_inst0_data[8]
  PIN ifu_idu_ib_inst0_data[9]
    DIRECTION OUTPUT ;
    USE SIGNAL ;
    PORT
      LAYER metal4 ;
        RECT 554.985 0.000 555.125 0.560 ;
    END
  END ifu_idu_ib_inst0_data[9]
  PIN ifu_idu_ib_inst0_vld
    DIRECTION OUTPUT ;
    USE SIGNAL ;
    PORT
      LAYER metal4 ;
        RECT 560.585 0.000 560.725 0.560 ;
    END
  END ifu_idu_ib_inst0_vld
  PIN ifu_idu_ib_inst1_data[0]
    DIRECTION OUTPUT ;
    USE SIGNAL ;
    PORT
      LAYER metal6 ;
        RECT 600.905 0.000 601.045 0.560 ;
    END
  END ifu_idu_ib_inst1_data[0]
  PIN ifu_idu_ib_inst1_data[10]
    DIRECTION OUTPUT ;
    USE SIGNAL ;
    PORT
      LAYER metal6 ;
        RECT 595.305 0.000 595.445 0.560 ;
    END
  END ifu_idu_ib_inst1_data[10]
  PIN ifu_idu_ib_inst1_data[11]
    DIRECTION OUTPUT ;
    USE SIGNAL ;
    PORT
      LAYER metal4 ;
        RECT 595.305 0.000 595.445 0.560 ;
    END
  END ifu_idu_ib_inst1_data[11]
  PIN ifu_idu_ib_inst1_data[12]
    DIRECTION OUTPUT ;
    USE SIGNAL ;
    PORT
      LAYER metal6 ;
        RECT 594.185 0.000 594.325 0.560 ;
    END
  END ifu_idu_ib_inst1_data[12]
  PIN ifu_idu_ib_inst1_data[13]
    DIRECTION OUTPUT ;
    USE SIGNAL ;
    PORT
      LAYER metal4 ;
        RECT 594.185 0.000 594.325 0.560 ;
    END
  END ifu_idu_ib_inst1_data[13]
  PIN ifu_idu_ib_inst1_data[14]
    DIRECTION OUTPUT ;
    USE SIGNAL ;
    PORT
      LAYER metal6 ;
        RECT 593.065 0.000 593.205 0.560 ;
    END
  END ifu_idu_ib_inst1_data[14]
  PIN ifu_idu_ib_inst1_data[15]
    DIRECTION OUTPUT ;
    USE SIGNAL ;
    PORT
      LAYER metal4 ;
        RECT 593.065 0.000 593.205 0.560 ;
    END
  END ifu_idu_ib_inst1_data[15]
  PIN ifu_idu_ib_inst1_data[16]
    DIRECTION OUTPUT ;
    USE SIGNAL ;
    PORT
      LAYER metal6 ;
        RECT 591.945 0.000 592.085 0.560 ;
    END
  END ifu_idu_ib_inst1_data[16]
  PIN ifu_idu_ib_inst1_data[17]
    DIRECTION OUTPUT ;
    USE SIGNAL ;
    PORT
      LAYER metal4 ;
        RECT 591.945 0.000 592.085 0.560 ;
    END
  END ifu_idu_ib_inst1_data[17]
  PIN ifu_idu_ib_inst1_data[18]
    DIRECTION OUTPUT ;
    USE SIGNAL ;
    PORT
      LAYER metal6 ;
        RECT 590.825 0.000 590.965 0.560 ;
    END
  END ifu_idu_ib_inst1_data[18]
  PIN ifu_idu_ib_inst1_data[19]
    DIRECTION OUTPUT ;
    USE SIGNAL ;
    PORT
      LAYER metal4 ;
        RECT 590.825 0.000 590.965 0.560 ;
    END
  END ifu_idu_ib_inst1_data[19]
  PIN ifu_idu_ib_inst1_data[1]
    DIRECTION OUTPUT ;
    USE SIGNAL ;
    PORT
      LAYER metal4 ;
        RECT 600.905 0.000 601.045 0.560 ;
    END
  END ifu_idu_ib_inst1_data[1]
  PIN ifu_idu_ib_inst1_data[20]
    DIRECTION OUTPUT ;
    USE SIGNAL ;
    PORT
      LAYER metal6 ;
        RECT 589.705 0.000 589.845 0.560 ;
    END
  END ifu_idu_ib_inst1_data[20]
  PIN ifu_idu_ib_inst1_data[21]
    DIRECTION OUTPUT ;
    USE SIGNAL ;
    PORT
      LAYER metal4 ;
        RECT 589.705 0.000 589.845 0.560 ;
    END
  END ifu_idu_ib_inst1_data[21]
  PIN ifu_idu_ib_inst1_data[22]
    DIRECTION OUTPUT ;
    USE SIGNAL ;
    PORT
      LAYER metal6 ;
        RECT 588.585 0.000 588.725 0.560 ;
    END
  END ifu_idu_ib_inst1_data[22]
  PIN ifu_idu_ib_inst1_data[23]
    DIRECTION OUTPUT ;
    USE SIGNAL ;
    PORT
      LAYER metal4 ;
        RECT 588.585 0.000 588.725 0.560 ;
    END
  END ifu_idu_ib_inst1_data[23]
  PIN ifu_idu_ib_inst1_data[24]
    DIRECTION OUTPUT ;
    USE SIGNAL ;
    PORT
      LAYER metal6 ;
        RECT 587.465 0.000 587.605 0.560 ;
    END
  END ifu_idu_ib_inst1_data[24]
  PIN ifu_idu_ib_inst1_data[25]
    DIRECTION OUTPUT ;
    USE SIGNAL ;
    PORT
      LAYER metal4 ;
        RECT 587.465 0.000 587.605 0.560 ;
    END
  END ifu_idu_ib_inst1_data[25]
  PIN ifu_idu_ib_inst1_data[26]
    DIRECTION OUTPUT ;
    USE SIGNAL ;
    PORT
      LAYER metal6 ;
        RECT 586.345 0.000 586.485 0.560 ;
    END
  END ifu_idu_ib_inst1_data[26]
  PIN ifu_idu_ib_inst1_data[27]
    DIRECTION OUTPUT ;
    USE SIGNAL ;
    PORT
      LAYER metal4 ;
        RECT 586.345 0.000 586.485 0.560 ;
    END
  END ifu_idu_ib_inst1_data[27]
  PIN ifu_idu_ib_inst1_data[28]
    DIRECTION OUTPUT ;
    USE SIGNAL ;
    PORT
      LAYER metal6 ;
        RECT 585.225 0.000 585.365 0.560 ;
    END
  END ifu_idu_ib_inst1_data[28]
  PIN ifu_idu_ib_inst1_data[29]
    DIRECTION OUTPUT ;
    USE SIGNAL ;
    PORT
      LAYER metal4 ;
        RECT 585.225 0.000 585.365 0.560 ;
    END
  END ifu_idu_ib_inst1_data[29]
  PIN ifu_idu_ib_inst1_data[2]
    DIRECTION OUTPUT ;
    USE SIGNAL ;
    PORT
      LAYER metal6 ;
        RECT 599.785 0.000 599.925 0.560 ;
    END
  END ifu_idu_ib_inst1_data[2]
  PIN ifu_idu_ib_inst1_data[30]
    DIRECTION OUTPUT ;
    USE SIGNAL ;
    PORT
      LAYER metal6 ;
        RECT 584.105 0.000 584.245 0.560 ;
    END
  END ifu_idu_ib_inst1_data[30]
  PIN ifu_idu_ib_inst1_data[31]
    DIRECTION OUTPUT ;
    USE SIGNAL ;
    PORT
      LAYER metal4 ;
        RECT 584.105 0.000 584.245 0.560 ;
    END
  END ifu_idu_ib_inst1_data[31]
  PIN ifu_idu_ib_inst1_data[32]
    DIRECTION OUTPUT ;
    USE SIGNAL ;
    PORT
      LAYER metal6 ;
        RECT 582.985 0.000 583.125 0.560 ;
    END
  END ifu_idu_ib_inst1_data[32]
  PIN ifu_idu_ib_inst1_data[33]
    DIRECTION OUTPUT ;
    USE SIGNAL ;
    PORT
      LAYER metal4 ;
        RECT 582.985 0.000 583.125 0.560 ;
    END
  END ifu_idu_ib_inst1_data[33]
  PIN ifu_idu_ib_inst1_data[34]
    DIRECTION OUTPUT ;
    USE SIGNAL ;
    PORT
      LAYER metal6 ;
        RECT 581.865 0.000 582.005 0.560 ;
    END
  END ifu_idu_ib_inst1_data[34]
  PIN ifu_idu_ib_inst1_data[35]
    DIRECTION OUTPUT ;
    USE SIGNAL ;
    PORT
      LAYER metal4 ;
        RECT 581.865 0.000 582.005 0.560 ;
    END
  END ifu_idu_ib_inst1_data[35]
  PIN ifu_idu_ib_inst1_data[36]
    DIRECTION OUTPUT ;
    USE SIGNAL ;
    PORT
      LAYER metal6 ;
        RECT 580.745 0.000 580.885 0.560 ;
    END
  END ifu_idu_ib_inst1_data[36]
  PIN ifu_idu_ib_inst1_data[37]
    DIRECTION OUTPUT ;
    USE SIGNAL ;
    PORT
      LAYER metal4 ;
        RECT 580.745 0.000 580.885 0.560 ;
    END
  END ifu_idu_ib_inst1_data[37]
  PIN ifu_idu_ib_inst1_data[38]
    DIRECTION OUTPUT ;
    USE SIGNAL ;
    PORT
      LAYER metal6 ;
        RECT 579.625 0.000 579.765 0.560 ;
    END
  END ifu_idu_ib_inst1_data[38]
  PIN ifu_idu_ib_inst1_data[39]
    DIRECTION OUTPUT ;
    USE SIGNAL ;
    PORT
      LAYER metal4 ;
        RECT 579.625 0.000 579.765 0.560 ;
    END
  END ifu_idu_ib_inst1_data[39]
  PIN ifu_idu_ib_inst1_data[3]
    DIRECTION OUTPUT ;
    USE SIGNAL ;
    PORT
      LAYER metal4 ;
        RECT 599.785 0.000 599.925 0.560 ;
    END
  END ifu_idu_ib_inst1_data[3]
  PIN ifu_idu_ib_inst1_data[40]
    DIRECTION OUTPUT ;
    USE SIGNAL ;
    PORT
      LAYER metal6 ;
        RECT 578.505 0.000 578.645 0.560 ;
    END
  END ifu_idu_ib_inst1_data[40]
  PIN ifu_idu_ib_inst1_data[41]
    DIRECTION OUTPUT ;
    USE SIGNAL ;
    PORT
      LAYER metal4 ;
        RECT 578.505 0.000 578.645 0.560 ;
    END
  END ifu_idu_ib_inst1_data[41]
  PIN ifu_idu_ib_inst1_data[42]
    DIRECTION OUTPUT ;
    USE SIGNAL ;
    PORT
      LAYER metal6 ;
        RECT 577.385 0.000 577.525 0.560 ;
    END
  END ifu_idu_ib_inst1_data[42]
  PIN ifu_idu_ib_inst1_data[43]
    DIRECTION OUTPUT ;
    USE SIGNAL ;
    PORT
      LAYER metal4 ;
        RECT 577.385 0.000 577.525 0.560 ;
    END
  END ifu_idu_ib_inst1_data[43]
  PIN ifu_idu_ib_inst1_data[44]
    DIRECTION OUTPUT ;
    USE SIGNAL ;
    PORT
      LAYER metal6 ;
        RECT 576.265 0.000 576.405 0.560 ;
    END
  END ifu_idu_ib_inst1_data[44]
  PIN ifu_idu_ib_inst1_data[45]
    DIRECTION OUTPUT ;
    USE SIGNAL ;
    PORT
      LAYER metal4 ;
        RECT 576.265 0.000 576.405 0.560 ;
    END
  END ifu_idu_ib_inst1_data[45]
  PIN ifu_idu_ib_inst1_data[46]
    DIRECTION OUTPUT ;
    USE SIGNAL ;
    PORT
      LAYER metal6 ;
        RECT 575.145 0.000 575.285 0.560 ;
    END
  END ifu_idu_ib_inst1_data[46]
  PIN ifu_idu_ib_inst1_data[47]
    DIRECTION OUTPUT ;
    USE SIGNAL ;
    PORT
      LAYER metal4 ;
        RECT 575.145 0.000 575.285 0.560 ;
    END
  END ifu_idu_ib_inst1_data[47]
  PIN ifu_idu_ib_inst1_data[48]
    DIRECTION OUTPUT ;
    USE SIGNAL ;
    PORT
      LAYER metal6 ;
        RECT 574.025 0.000 574.165 0.560 ;
    END
  END ifu_idu_ib_inst1_data[48]
  PIN ifu_idu_ib_inst1_data[49]
    DIRECTION OUTPUT ;
    USE SIGNAL ;
    PORT
      LAYER metal4 ;
        RECT 574.025 0.000 574.165 0.560 ;
    END
  END ifu_idu_ib_inst1_data[49]
  PIN ifu_idu_ib_inst1_data[4]
    DIRECTION OUTPUT ;
    USE SIGNAL ;
    PORT
      LAYER metal6 ;
        RECT 598.665 0.000 598.805 0.560 ;
    END
  END ifu_idu_ib_inst1_data[4]
  PIN ifu_idu_ib_inst1_data[50]
    DIRECTION OUTPUT ;
    USE SIGNAL ;
    PORT
      LAYER metal6 ;
        RECT 572.905 0.000 573.045 0.560 ;
    END
  END ifu_idu_ib_inst1_data[50]
  PIN ifu_idu_ib_inst1_data[51]
    DIRECTION OUTPUT ;
    USE SIGNAL ;
    PORT
      LAYER metal4 ;
        RECT 572.905 0.000 573.045 0.560 ;
    END
  END ifu_idu_ib_inst1_data[51]
  PIN ifu_idu_ib_inst1_data[52]
    DIRECTION OUTPUT ;
    USE SIGNAL ;
    PORT
      LAYER metal6 ;
        RECT 571.785 0.000 571.925 0.560 ;
    END
  END ifu_idu_ib_inst1_data[52]
  PIN ifu_idu_ib_inst1_data[53]
    DIRECTION OUTPUT ;
    USE SIGNAL ;
    PORT
      LAYER metal4 ;
        RECT 571.785 0.000 571.925 0.560 ;
    END
  END ifu_idu_ib_inst1_data[53]
  PIN ifu_idu_ib_inst1_data[54]
    DIRECTION OUTPUT ;
    USE SIGNAL ;
    PORT
      LAYER metal6 ;
        RECT 570.665 0.000 570.805 0.560 ;
    END
  END ifu_idu_ib_inst1_data[54]
  PIN ifu_idu_ib_inst1_data[55]
    DIRECTION OUTPUT ;
    USE SIGNAL ;
    PORT
      LAYER metal4 ;
        RECT 570.665 0.000 570.805 0.560 ;
    END
  END ifu_idu_ib_inst1_data[55]
  PIN ifu_idu_ib_inst1_data[56]
    DIRECTION OUTPUT ;
    USE SIGNAL ;
    PORT
      LAYER metal6 ;
        RECT 569.545 0.000 569.685 0.560 ;
    END
  END ifu_idu_ib_inst1_data[56]
  PIN ifu_idu_ib_inst1_data[57]
    DIRECTION OUTPUT ;
    USE SIGNAL ;
    PORT
      LAYER metal4 ;
        RECT 569.545 0.000 569.685 0.560 ;
    END
  END ifu_idu_ib_inst1_data[57]
  PIN ifu_idu_ib_inst1_data[58]
    DIRECTION OUTPUT ;
    USE SIGNAL ;
    PORT
      LAYER metal6 ;
        RECT 568.425 0.000 568.565 0.560 ;
    END
  END ifu_idu_ib_inst1_data[58]
  PIN ifu_idu_ib_inst1_data[59]
    DIRECTION OUTPUT ;
    USE SIGNAL ;
    PORT
      LAYER metal4 ;
        RECT 568.425 0.000 568.565 0.560 ;
    END
  END ifu_idu_ib_inst1_data[59]
  PIN ifu_idu_ib_inst1_data[5]
    DIRECTION OUTPUT ;
    USE SIGNAL ;
    PORT
      LAYER metal4 ;
        RECT 598.665 0.000 598.805 0.560 ;
    END
  END ifu_idu_ib_inst1_data[5]
  PIN ifu_idu_ib_inst1_data[60]
    DIRECTION OUTPUT ;
    USE SIGNAL ;
    PORT
      LAYER metal6 ;
        RECT 567.305 0.000 567.445 0.560 ;
    END
  END ifu_idu_ib_inst1_data[60]
  PIN ifu_idu_ib_inst1_data[61]
    DIRECTION OUTPUT ;
    USE SIGNAL ;
    PORT
      LAYER metal4 ;
        RECT 567.305 0.000 567.445 0.560 ;
    END
  END ifu_idu_ib_inst1_data[61]
  PIN ifu_idu_ib_inst1_data[62]
    DIRECTION OUTPUT ;
    USE SIGNAL ;
    PORT
      LAYER metal6 ;
        RECT 566.185 0.000 566.325 0.560 ;
    END
  END ifu_idu_ib_inst1_data[62]
  PIN ifu_idu_ib_inst1_data[63]
    DIRECTION OUTPUT ;
    USE SIGNAL ;
    PORT
      LAYER metal4 ;
        RECT 566.185 0.000 566.325 0.560 ;
    END
  END ifu_idu_ib_inst1_data[63]
  PIN ifu_idu_ib_inst1_data[64]
    DIRECTION OUTPUT ;
    USE SIGNAL ;
    PORT
      LAYER metal6 ;
        RECT 565.065 0.000 565.205 0.560 ;
    END
  END ifu_idu_ib_inst1_data[64]
  PIN ifu_idu_ib_inst1_data[65]
    DIRECTION OUTPUT ;
    USE SIGNAL ;
    PORT
      LAYER metal4 ;
        RECT 565.065 0.000 565.205 0.560 ;
    END
  END ifu_idu_ib_inst1_data[65]
  PIN ifu_idu_ib_inst1_data[66]
    DIRECTION OUTPUT ;
    USE SIGNAL ;
    PORT
      LAYER metal6 ;
        RECT 563.945 0.000 564.085 0.560 ;
    END
  END ifu_idu_ib_inst1_data[66]
  PIN ifu_idu_ib_inst1_data[67]
    DIRECTION OUTPUT ;
    USE SIGNAL ;
    PORT
      LAYER metal4 ;
        RECT 563.945 0.000 564.085 0.560 ;
    END
  END ifu_idu_ib_inst1_data[67]
  PIN ifu_idu_ib_inst1_data[68]
    DIRECTION OUTPUT ;
    USE SIGNAL ;
    PORT
      LAYER metal6 ;
        RECT 562.825 0.000 562.965 0.560 ;
    END
  END ifu_idu_ib_inst1_data[68]
  PIN ifu_idu_ib_inst1_data[69]
    DIRECTION OUTPUT ;
    USE SIGNAL ;
    PORT
      LAYER metal4 ;
        RECT 562.825 0.000 562.965 0.560 ;
    END
  END ifu_idu_ib_inst1_data[69]
  PIN ifu_idu_ib_inst1_data[6]
    DIRECTION OUTPUT ;
    USE SIGNAL ;
    PORT
      LAYER metal6 ;
        RECT 597.545 0.000 597.685 0.560 ;
    END
  END ifu_idu_ib_inst1_data[6]
  PIN ifu_idu_ib_inst1_data[70]
    DIRECTION OUTPUT ;
    USE SIGNAL ;
    PORT
      LAYER metal6 ;
        RECT 561.705 0.000 561.845 0.560 ;
    END
  END ifu_idu_ib_inst1_data[70]
  PIN ifu_idu_ib_inst1_data[71]
    DIRECTION OUTPUT ;
    USE SIGNAL ;
    PORT
      LAYER metal4 ;
        RECT 561.705 0.000 561.845 0.560 ;
    END
  END ifu_idu_ib_inst1_data[71]
  PIN ifu_idu_ib_inst1_data[72]
    DIRECTION OUTPUT ;
    USE SIGNAL ;
    PORT
      LAYER metal6 ;
        RECT 560.585 0.000 560.725 0.560 ;
    END
  END ifu_idu_ib_inst1_data[72]
  PIN ifu_idu_ib_inst1_data[7]
    DIRECTION OUTPUT ;
    USE SIGNAL ;
    PORT
      LAYER metal4 ;
        RECT 597.545 0.000 597.685 0.560 ;
    END
  END ifu_idu_ib_inst1_data[7]
  PIN ifu_idu_ib_inst1_data[8]
    DIRECTION OUTPUT ;
    USE SIGNAL ;
    PORT
      LAYER metal6 ;
        RECT 596.425 0.000 596.565 0.560 ;
    END
  END ifu_idu_ib_inst1_data[8]
  PIN ifu_idu_ib_inst1_data[9]
    DIRECTION OUTPUT ;
    USE SIGNAL ;
    PORT
      LAYER metal4 ;
        RECT 596.425 0.000 596.565 0.560 ;
    END
  END ifu_idu_ib_inst1_data[9]
  PIN ifu_idu_ib_inst1_vld
    DIRECTION OUTPUT ;
    USE SIGNAL ;
    PORT
      LAYER metal4 ;
        RECT 602.025 0.000 602.165 0.560 ;
    END
  END ifu_idu_ib_inst1_vld
  PIN ifu_idu_ib_inst2_data[0]
    DIRECTION OUTPUT ;
    USE SIGNAL ;
    PORT
      LAYER metal6 ;
        RECT 775.065 0.000 775.205 0.560 ;
    END
  END ifu_idu_ib_inst2_data[0]
  PIN ifu_idu_ib_inst2_data[10]
    DIRECTION OUTPUT ;
    USE SIGNAL ;
    PORT
      LAYER metal6 ;
        RECT 769.465 0.000 769.605 0.560 ;
    END
  END ifu_idu_ib_inst2_data[10]
  PIN ifu_idu_ib_inst2_data[11]
    DIRECTION OUTPUT ;
    USE SIGNAL ;
    PORT
      LAYER metal4 ;
        RECT 769.465 0.000 769.605 0.560 ;
    END
  END ifu_idu_ib_inst2_data[11]
  PIN ifu_idu_ib_inst2_data[12]
    DIRECTION OUTPUT ;
    USE SIGNAL ;
    PORT
      LAYER metal6 ;
        RECT 768.345 0.000 768.485 0.560 ;
    END
  END ifu_idu_ib_inst2_data[12]
  PIN ifu_idu_ib_inst2_data[13]
    DIRECTION OUTPUT ;
    USE SIGNAL ;
    PORT
      LAYER metal4 ;
        RECT 768.345 0.000 768.485 0.560 ;
    END
  END ifu_idu_ib_inst2_data[13]
  PIN ifu_idu_ib_inst2_data[14]
    DIRECTION OUTPUT ;
    USE SIGNAL ;
    PORT
      LAYER metal6 ;
        RECT 767.225 0.000 767.365 0.560 ;
    END
  END ifu_idu_ib_inst2_data[14]
  PIN ifu_idu_ib_inst2_data[15]
    DIRECTION OUTPUT ;
    USE SIGNAL ;
    PORT
      LAYER metal4 ;
        RECT 767.225 0.000 767.365 0.560 ;
    END
  END ifu_idu_ib_inst2_data[15]
  PIN ifu_idu_ib_inst2_data[16]
    DIRECTION OUTPUT ;
    USE SIGNAL ;
    PORT
      LAYER metal6 ;
        RECT 766.105 0.000 766.245 0.560 ;
    END
  END ifu_idu_ib_inst2_data[16]
  PIN ifu_idu_ib_inst2_data[17]
    DIRECTION OUTPUT ;
    USE SIGNAL ;
    PORT
      LAYER metal4 ;
        RECT 766.105 0.000 766.245 0.560 ;
    END
  END ifu_idu_ib_inst2_data[17]
  PIN ifu_idu_ib_inst2_data[18]
    DIRECTION OUTPUT ;
    USE SIGNAL ;
    PORT
      LAYER metal6 ;
        RECT 764.985 0.000 765.125 0.560 ;
    END
  END ifu_idu_ib_inst2_data[18]
  PIN ifu_idu_ib_inst2_data[19]
    DIRECTION OUTPUT ;
    USE SIGNAL ;
    PORT
      LAYER metal4 ;
        RECT 764.985 0.000 765.125 0.560 ;
    END
  END ifu_idu_ib_inst2_data[19]
  PIN ifu_idu_ib_inst2_data[1]
    DIRECTION OUTPUT ;
    USE SIGNAL ;
    PORT
      LAYER metal4 ;
        RECT 775.065 0.000 775.205 0.560 ;
    END
  END ifu_idu_ib_inst2_data[1]
  PIN ifu_idu_ib_inst2_data[20]
    DIRECTION OUTPUT ;
    USE SIGNAL ;
    PORT
      LAYER metal6 ;
        RECT 763.865 0.000 764.005 0.560 ;
    END
  END ifu_idu_ib_inst2_data[20]
  PIN ifu_idu_ib_inst2_data[21]
    DIRECTION OUTPUT ;
    USE SIGNAL ;
    PORT
      LAYER metal4 ;
        RECT 763.865 0.000 764.005 0.560 ;
    END
  END ifu_idu_ib_inst2_data[21]
  PIN ifu_idu_ib_inst2_data[22]
    DIRECTION OUTPUT ;
    USE SIGNAL ;
    PORT
      LAYER metal6 ;
        RECT 762.745 0.000 762.885 0.560 ;
    END
  END ifu_idu_ib_inst2_data[22]
  PIN ifu_idu_ib_inst2_data[23]
    DIRECTION OUTPUT ;
    USE SIGNAL ;
    PORT
      LAYER metal4 ;
        RECT 762.745 0.000 762.885 0.560 ;
    END
  END ifu_idu_ib_inst2_data[23]
  PIN ifu_idu_ib_inst2_data[24]
    DIRECTION OUTPUT ;
    USE SIGNAL ;
    PORT
      LAYER metal6 ;
        RECT 761.625 0.000 761.765 0.560 ;
    END
  END ifu_idu_ib_inst2_data[24]
  PIN ifu_idu_ib_inst2_data[25]
    DIRECTION OUTPUT ;
    USE SIGNAL ;
    PORT
      LAYER metal4 ;
        RECT 761.625 0.000 761.765 0.560 ;
    END
  END ifu_idu_ib_inst2_data[25]
  PIN ifu_idu_ib_inst2_data[26]
    DIRECTION OUTPUT ;
    USE SIGNAL ;
    PORT
      LAYER metal6 ;
        RECT 760.505 0.000 760.645 0.560 ;
    END
  END ifu_idu_ib_inst2_data[26]
  PIN ifu_idu_ib_inst2_data[27]
    DIRECTION OUTPUT ;
    USE SIGNAL ;
    PORT
      LAYER metal4 ;
        RECT 760.505 0.000 760.645 0.560 ;
    END
  END ifu_idu_ib_inst2_data[27]
  PIN ifu_idu_ib_inst2_data[28]
    DIRECTION OUTPUT ;
    USE SIGNAL ;
    PORT
      LAYER metal6 ;
        RECT 759.385 0.000 759.525 0.560 ;
    END
  END ifu_idu_ib_inst2_data[28]
  PIN ifu_idu_ib_inst2_data[29]
    DIRECTION OUTPUT ;
    USE SIGNAL ;
    PORT
      LAYER metal4 ;
        RECT 759.385 0.000 759.525 0.560 ;
    END
  END ifu_idu_ib_inst2_data[29]
  PIN ifu_idu_ib_inst2_data[2]
    DIRECTION OUTPUT ;
    USE SIGNAL ;
    PORT
      LAYER metal6 ;
        RECT 773.945 0.000 774.085 0.560 ;
    END
  END ifu_idu_ib_inst2_data[2]
  PIN ifu_idu_ib_inst2_data[30]
    DIRECTION OUTPUT ;
    USE SIGNAL ;
    PORT
      LAYER metal6 ;
        RECT 758.265 0.000 758.405 0.560 ;
    END
  END ifu_idu_ib_inst2_data[30]
  PIN ifu_idu_ib_inst2_data[31]
    DIRECTION OUTPUT ;
    USE SIGNAL ;
    PORT
      LAYER metal4 ;
        RECT 758.265 0.000 758.405 0.560 ;
    END
  END ifu_idu_ib_inst2_data[31]
  PIN ifu_idu_ib_inst2_data[32]
    DIRECTION OUTPUT ;
    USE SIGNAL ;
    PORT
      LAYER metal6 ;
        RECT 757.145 0.000 757.285 0.560 ;
    END
  END ifu_idu_ib_inst2_data[32]
  PIN ifu_idu_ib_inst2_data[33]
    DIRECTION OUTPUT ;
    USE SIGNAL ;
    PORT
      LAYER metal4 ;
        RECT 757.145 0.000 757.285 0.560 ;
    END
  END ifu_idu_ib_inst2_data[33]
  PIN ifu_idu_ib_inst2_data[34]
    DIRECTION OUTPUT ;
    USE SIGNAL ;
    PORT
      LAYER metal6 ;
        RECT 756.025 0.000 756.165 0.560 ;
    END
  END ifu_idu_ib_inst2_data[34]
  PIN ifu_idu_ib_inst2_data[35]
    DIRECTION OUTPUT ;
    USE SIGNAL ;
    PORT
      LAYER metal4 ;
        RECT 756.025 0.000 756.165 0.560 ;
    END
  END ifu_idu_ib_inst2_data[35]
  PIN ifu_idu_ib_inst2_data[36]
    DIRECTION OUTPUT ;
    USE SIGNAL ;
    PORT
      LAYER metal6 ;
        RECT 754.905 0.000 755.045 0.560 ;
    END
  END ifu_idu_ib_inst2_data[36]
  PIN ifu_idu_ib_inst2_data[37]
    DIRECTION OUTPUT ;
    USE SIGNAL ;
    PORT
      LAYER metal4 ;
        RECT 754.905 0.000 755.045 0.560 ;
    END
  END ifu_idu_ib_inst2_data[37]
  PIN ifu_idu_ib_inst2_data[38]
    DIRECTION OUTPUT ;
    USE SIGNAL ;
    PORT
      LAYER metal6 ;
        RECT 753.785 0.000 753.925 0.560 ;
    END
  END ifu_idu_ib_inst2_data[38]
  PIN ifu_idu_ib_inst2_data[39]
    DIRECTION OUTPUT ;
    USE SIGNAL ;
    PORT
      LAYER metal4 ;
        RECT 753.785 0.000 753.925 0.560 ;
    END
  END ifu_idu_ib_inst2_data[39]
  PIN ifu_idu_ib_inst2_data[3]
    DIRECTION OUTPUT ;
    USE SIGNAL ;
    PORT
      LAYER metal4 ;
        RECT 773.945 0.000 774.085 0.560 ;
    END
  END ifu_idu_ib_inst2_data[3]
  PIN ifu_idu_ib_inst2_data[40]
    DIRECTION OUTPUT ;
    USE SIGNAL ;
    PORT
      LAYER metal6 ;
        RECT 752.665 0.000 752.805 0.560 ;
    END
  END ifu_idu_ib_inst2_data[40]
  PIN ifu_idu_ib_inst2_data[41]
    DIRECTION OUTPUT ;
    USE SIGNAL ;
    PORT
      LAYER metal4 ;
        RECT 752.665 0.000 752.805 0.560 ;
    END
  END ifu_idu_ib_inst2_data[41]
  PIN ifu_idu_ib_inst2_data[42]
    DIRECTION OUTPUT ;
    USE SIGNAL ;
    PORT
      LAYER metal6 ;
        RECT 751.545 0.000 751.685 0.560 ;
    END
  END ifu_idu_ib_inst2_data[42]
  PIN ifu_idu_ib_inst2_data[43]
    DIRECTION OUTPUT ;
    USE SIGNAL ;
    PORT
      LAYER metal4 ;
        RECT 751.545 0.000 751.685 0.560 ;
    END
  END ifu_idu_ib_inst2_data[43]
  PIN ifu_idu_ib_inst2_data[44]
    DIRECTION OUTPUT ;
    USE SIGNAL ;
    PORT
      LAYER metal6 ;
        RECT 750.425 0.000 750.565 0.560 ;
    END
  END ifu_idu_ib_inst2_data[44]
  PIN ifu_idu_ib_inst2_data[45]
    DIRECTION OUTPUT ;
    USE SIGNAL ;
    PORT
      LAYER metal4 ;
        RECT 750.425 0.000 750.565 0.560 ;
    END
  END ifu_idu_ib_inst2_data[45]
  PIN ifu_idu_ib_inst2_data[46]
    DIRECTION OUTPUT ;
    USE SIGNAL ;
    PORT
      LAYER metal6 ;
        RECT 749.305 0.000 749.445 0.560 ;
    END
  END ifu_idu_ib_inst2_data[46]
  PIN ifu_idu_ib_inst2_data[47]
    DIRECTION OUTPUT ;
    USE SIGNAL ;
    PORT
      LAYER metal4 ;
        RECT 749.305 0.000 749.445 0.560 ;
    END
  END ifu_idu_ib_inst2_data[47]
  PIN ifu_idu_ib_inst2_data[48]
    DIRECTION OUTPUT ;
    USE SIGNAL ;
    PORT
      LAYER metal6 ;
        RECT 748.185 0.000 748.325 0.560 ;
    END
  END ifu_idu_ib_inst2_data[48]
  PIN ifu_idu_ib_inst2_data[49]
    DIRECTION OUTPUT ;
    USE SIGNAL ;
    PORT
      LAYER metal4 ;
        RECT 748.185 0.000 748.325 0.560 ;
    END
  END ifu_idu_ib_inst2_data[49]
  PIN ifu_idu_ib_inst2_data[4]
    DIRECTION OUTPUT ;
    USE SIGNAL ;
    PORT
      LAYER metal6 ;
        RECT 772.825 0.000 772.965 0.560 ;
    END
  END ifu_idu_ib_inst2_data[4]
  PIN ifu_idu_ib_inst2_data[50]
    DIRECTION OUTPUT ;
    USE SIGNAL ;
    PORT
      LAYER metal6 ;
        RECT 747.065 0.000 747.205 0.560 ;
    END
  END ifu_idu_ib_inst2_data[50]
  PIN ifu_idu_ib_inst2_data[51]
    DIRECTION OUTPUT ;
    USE SIGNAL ;
    PORT
      LAYER metal4 ;
        RECT 747.065 0.000 747.205 0.560 ;
    END
  END ifu_idu_ib_inst2_data[51]
  PIN ifu_idu_ib_inst2_data[52]
    DIRECTION OUTPUT ;
    USE SIGNAL ;
    PORT
      LAYER metal6 ;
        RECT 745.945 0.000 746.085 0.560 ;
    END
  END ifu_idu_ib_inst2_data[52]
  PIN ifu_idu_ib_inst2_data[53]
    DIRECTION OUTPUT ;
    USE SIGNAL ;
    PORT
      LAYER metal4 ;
        RECT 745.945 0.000 746.085 0.560 ;
    END
  END ifu_idu_ib_inst2_data[53]
  PIN ifu_idu_ib_inst2_data[54]
    DIRECTION OUTPUT ;
    USE SIGNAL ;
    PORT
      LAYER metal6 ;
        RECT 612.105 0.000 612.245 0.560 ;
    END
  END ifu_idu_ib_inst2_data[54]
  PIN ifu_idu_ib_inst2_data[55]
    DIRECTION OUTPUT ;
    USE SIGNAL ;
    PORT
      LAYER metal4 ;
        RECT 612.105 0.000 612.245 0.560 ;
    END
  END ifu_idu_ib_inst2_data[55]
  PIN ifu_idu_ib_inst2_data[56]
    DIRECTION OUTPUT ;
    USE SIGNAL ;
    PORT
      LAYER metal6 ;
        RECT 610.985 0.000 611.125 0.560 ;
    END
  END ifu_idu_ib_inst2_data[56]
  PIN ifu_idu_ib_inst2_data[57]
    DIRECTION OUTPUT ;
    USE SIGNAL ;
    PORT
      LAYER metal4 ;
        RECT 610.985 0.000 611.125 0.560 ;
    END
  END ifu_idu_ib_inst2_data[57]
  PIN ifu_idu_ib_inst2_data[58]
    DIRECTION OUTPUT ;
    USE SIGNAL ;
    PORT
      LAYER metal6 ;
        RECT 609.865 0.000 610.005 0.560 ;
    END
  END ifu_idu_ib_inst2_data[58]
  PIN ifu_idu_ib_inst2_data[59]
    DIRECTION OUTPUT ;
    USE SIGNAL ;
    PORT
      LAYER metal4 ;
        RECT 609.865 0.000 610.005 0.560 ;
    END
  END ifu_idu_ib_inst2_data[59]
  PIN ifu_idu_ib_inst2_data[5]
    DIRECTION OUTPUT ;
    USE SIGNAL ;
    PORT
      LAYER metal4 ;
        RECT 772.825 0.000 772.965 0.560 ;
    END
  END ifu_idu_ib_inst2_data[5]
  PIN ifu_idu_ib_inst2_data[60]
    DIRECTION OUTPUT ;
    USE SIGNAL ;
    PORT
      LAYER metal6 ;
        RECT 608.745 0.000 608.885 0.560 ;
    END
  END ifu_idu_ib_inst2_data[60]
  PIN ifu_idu_ib_inst2_data[61]
    DIRECTION OUTPUT ;
    USE SIGNAL ;
    PORT
      LAYER metal4 ;
        RECT 608.745 0.000 608.885 0.560 ;
    END
  END ifu_idu_ib_inst2_data[61]
  PIN ifu_idu_ib_inst2_data[62]
    DIRECTION OUTPUT ;
    USE SIGNAL ;
    PORT
      LAYER metal6 ;
        RECT 607.625 0.000 607.765 0.560 ;
    END
  END ifu_idu_ib_inst2_data[62]
  PIN ifu_idu_ib_inst2_data[63]
    DIRECTION OUTPUT ;
    USE SIGNAL ;
    PORT
      LAYER metal4 ;
        RECT 607.625 0.000 607.765 0.560 ;
    END
  END ifu_idu_ib_inst2_data[63]
  PIN ifu_idu_ib_inst2_data[64]
    DIRECTION OUTPUT ;
    USE SIGNAL ;
    PORT
      LAYER metal6 ;
        RECT 606.505 0.000 606.645 0.560 ;
    END
  END ifu_idu_ib_inst2_data[64]
  PIN ifu_idu_ib_inst2_data[65]
    DIRECTION OUTPUT ;
    USE SIGNAL ;
    PORT
      LAYER metal4 ;
        RECT 606.505 0.000 606.645 0.560 ;
    END
  END ifu_idu_ib_inst2_data[65]
  PIN ifu_idu_ib_inst2_data[66]
    DIRECTION OUTPUT ;
    USE SIGNAL ;
    PORT
      LAYER metal6 ;
        RECT 605.385 0.000 605.525 0.560 ;
    END
  END ifu_idu_ib_inst2_data[66]
  PIN ifu_idu_ib_inst2_data[67]
    DIRECTION OUTPUT ;
    USE SIGNAL ;
    PORT
      LAYER metal4 ;
        RECT 605.385 0.000 605.525 0.560 ;
    END
  END ifu_idu_ib_inst2_data[67]
  PIN ifu_idu_ib_inst2_data[68]
    DIRECTION OUTPUT ;
    USE SIGNAL ;
    PORT
      LAYER metal6 ;
        RECT 604.265 0.000 604.405 0.560 ;
    END
  END ifu_idu_ib_inst2_data[68]
  PIN ifu_idu_ib_inst2_data[69]
    DIRECTION OUTPUT ;
    USE SIGNAL ;
    PORT
      LAYER metal4 ;
        RECT 604.265 0.000 604.405 0.560 ;
    END
  END ifu_idu_ib_inst2_data[69]
  PIN ifu_idu_ib_inst2_data[6]
    DIRECTION OUTPUT ;
    USE SIGNAL ;
    PORT
      LAYER metal6 ;
        RECT 771.705 0.000 771.845 0.560 ;
    END
  END ifu_idu_ib_inst2_data[6]
  PIN ifu_idu_ib_inst2_data[70]
    DIRECTION OUTPUT ;
    USE SIGNAL ;
    PORT
      LAYER metal6 ;
        RECT 603.145 0.000 603.285 0.560 ;
    END
  END ifu_idu_ib_inst2_data[70]
  PIN ifu_idu_ib_inst2_data[71]
    DIRECTION OUTPUT ;
    USE SIGNAL ;
    PORT
      LAYER metal4 ;
        RECT 603.145 0.000 603.285 0.560 ;
    END
  END ifu_idu_ib_inst2_data[71]
  PIN ifu_idu_ib_inst2_data[72]
    DIRECTION OUTPUT ;
    USE SIGNAL ;
    PORT
      LAYER metal6 ;
        RECT 602.025 0.000 602.165 0.560 ;
    END
  END ifu_idu_ib_inst2_data[72]
  PIN ifu_idu_ib_inst2_data[7]
    DIRECTION OUTPUT ;
    USE SIGNAL ;
    PORT
      LAYER metal4 ;
        RECT 771.705 0.000 771.845 0.560 ;
    END
  END ifu_idu_ib_inst2_data[7]
  PIN ifu_idu_ib_inst2_data[8]
    DIRECTION OUTPUT ;
    USE SIGNAL ;
    PORT
      LAYER metal6 ;
        RECT 770.585 0.000 770.725 0.560 ;
    END
  END ifu_idu_ib_inst2_data[8]
  PIN ifu_idu_ib_inst2_data[9]
    DIRECTION OUTPUT ;
    USE SIGNAL ;
    PORT
      LAYER metal4 ;
        RECT 770.585 0.000 770.725 0.560 ;
    END
  END ifu_idu_ib_inst2_data[9]
  PIN ifu_idu_ib_inst2_vld
    DIRECTION OUTPUT ;
    USE SIGNAL ;
    PORT
      LAYER metal4 ;
        RECT 776.185 0.000 776.325 0.560 ;
    END
  END ifu_idu_ib_inst2_vld
  PIN ifu_idu_ib_pipedown_gateclk
    DIRECTION OUTPUT ;
    USE SIGNAL ;
    PORT
      LAYER metal6 ;
        RECT 776.185 0.000 776.325 0.560 ;
    END
  END ifu_idu_ib_pipedown_gateclk
  PIN ifu_iu_pcfifo_create0_bht_pred
    DIRECTION OUTPUT ;
    USE SIGNAL ;
    PORT
      LAYER metal4 ;
        RECT 777.305 0.000 777.445 0.560 ;
    END
  END ifu_iu_pcfifo_create0_bht_pred
  PIN ifu_iu_pcfifo_create0_chk_idx[0]
    DIRECTION OUTPUT ;
    USE SIGNAL ;
    PORT
      LAYER metal6 ;
        RECT 790.745 0.000 790.885 0.560 ;
    END
  END ifu_iu_pcfifo_create0_chk_idx[0]
  PIN ifu_iu_pcfifo_create0_chk_idx[10]
    DIRECTION OUTPUT ;
    USE SIGNAL ;
    PORT
      LAYER metal6 ;
        RECT 785.145 0.000 785.285 0.560 ;
    END
  END ifu_iu_pcfifo_create0_chk_idx[10]
  PIN ifu_iu_pcfifo_create0_chk_idx[11]
    DIRECTION OUTPUT ;
    USE SIGNAL ;
    PORT
      LAYER metal4 ;
        RECT 785.145 0.000 785.285 0.560 ;
    END
  END ifu_iu_pcfifo_create0_chk_idx[11]
  PIN ifu_iu_pcfifo_create0_chk_idx[12]
    DIRECTION OUTPUT ;
    USE SIGNAL ;
    PORT
      LAYER metal6 ;
        RECT 784.025 0.000 784.165 0.560 ;
    END
  END ifu_iu_pcfifo_create0_chk_idx[12]
  PIN ifu_iu_pcfifo_create0_chk_idx[13]
    DIRECTION OUTPUT ;
    USE SIGNAL ;
    PORT
      LAYER metal4 ;
        RECT 784.025 0.000 784.165 0.560 ;
    END
  END ifu_iu_pcfifo_create0_chk_idx[13]
  PIN ifu_iu_pcfifo_create0_chk_idx[14]
    DIRECTION OUTPUT ;
    USE SIGNAL ;
    PORT
      LAYER metal6 ;
        RECT 782.905 0.000 783.045 0.560 ;
    END
  END ifu_iu_pcfifo_create0_chk_idx[14]
  PIN ifu_iu_pcfifo_create0_chk_idx[15]
    DIRECTION OUTPUT ;
    USE SIGNAL ;
    PORT
      LAYER metal4 ;
        RECT 782.905 0.000 783.045 0.560 ;
    END
  END ifu_iu_pcfifo_create0_chk_idx[15]
  PIN ifu_iu_pcfifo_create0_chk_idx[16]
    DIRECTION OUTPUT ;
    USE SIGNAL ;
    PORT
      LAYER metal6 ;
        RECT 781.785 0.000 781.925 0.560 ;
    END
  END ifu_iu_pcfifo_create0_chk_idx[16]
  PIN ifu_iu_pcfifo_create0_chk_idx[17]
    DIRECTION OUTPUT ;
    USE SIGNAL ;
    PORT
      LAYER metal4 ;
        RECT 781.785 0.000 781.925 0.560 ;
    END
  END ifu_iu_pcfifo_create0_chk_idx[17]
  PIN ifu_iu_pcfifo_create0_chk_idx[18]
    DIRECTION OUTPUT ;
    USE SIGNAL ;
    PORT
      LAYER metal6 ;
        RECT 780.665 0.000 780.805 0.560 ;
    END
  END ifu_iu_pcfifo_create0_chk_idx[18]
  PIN ifu_iu_pcfifo_create0_chk_idx[19]
    DIRECTION OUTPUT ;
    USE SIGNAL ;
    PORT
      LAYER metal4 ;
        RECT 780.665 0.000 780.805 0.560 ;
    END
  END ifu_iu_pcfifo_create0_chk_idx[19]
  PIN ifu_iu_pcfifo_create0_chk_idx[1]
    DIRECTION OUTPUT ;
    USE SIGNAL ;
    PORT
      LAYER metal4 ;
        RECT 790.745 0.000 790.885 0.560 ;
    END
  END ifu_iu_pcfifo_create0_chk_idx[1]
  PIN ifu_iu_pcfifo_create0_chk_idx[20]
    DIRECTION OUTPUT ;
    USE SIGNAL ;
    PORT
      LAYER metal6 ;
        RECT 779.545 0.000 779.685 0.560 ;
    END
  END ifu_iu_pcfifo_create0_chk_idx[20]
  PIN ifu_iu_pcfifo_create0_chk_idx[21]
    DIRECTION OUTPUT ;
    USE SIGNAL ;
    PORT
      LAYER metal4 ;
        RECT 779.545 0.000 779.685 0.560 ;
    END
  END ifu_iu_pcfifo_create0_chk_idx[21]
  PIN ifu_iu_pcfifo_create0_chk_idx[22]
    DIRECTION OUTPUT ;
    USE SIGNAL ;
    PORT
      LAYER metal6 ;
        RECT 778.425 0.000 778.565 0.560 ;
    END
  END ifu_iu_pcfifo_create0_chk_idx[22]
  PIN ifu_iu_pcfifo_create0_chk_idx[23]
    DIRECTION OUTPUT ;
    USE SIGNAL ;
    PORT
      LAYER metal4 ;
        RECT 778.425 0.000 778.565 0.560 ;
    END
  END ifu_iu_pcfifo_create0_chk_idx[23]
  PIN ifu_iu_pcfifo_create0_chk_idx[24]
    DIRECTION OUTPUT ;
    USE SIGNAL ;
    PORT
      LAYER metal6 ;
        RECT 777.305 0.000 777.445 0.560 ;
    END
  END ifu_iu_pcfifo_create0_chk_idx[24]
  PIN ifu_iu_pcfifo_create0_chk_idx[2]
    DIRECTION OUTPUT ;
    USE SIGNAL ;
    PORT
      LAYER metal6 ;
        RECT 789.625 0.000 789.765 0.560 ;
    END
  END ifu_iu_pcfifo_create0_chk_idx[2]
  PIN ifu_iu_pcfifo_create0_chk_idx[3]
    DIRECTION OUTPUT ;
    USE SIGNAL ;
    PORT
      LAYER metal4 ;
        RECT 789.625 0.000 789.765 0.560 ;
    END
  END ifu_iu_pcfifo_create0_chk_idx[3]
  PIN ifu_iu_pcfifo_create0_chk_idx[4]
    DIRECTION OUTPUT ;
    USE SIGNAL ;
    PORT
      LAYER metal6 ;
        RECT 788.505 0.000 788.645 0.560 ;
    END
  END ifu_iu_pcfifo_create0_chk_idx[4]
  PIN ifu_iu_pcfifo_create0_chk_idx[5]
    DIRECTION OUTPUT ;
    USE SIGNAL ;
    PORT
      LAYER metal4 ;
        RECT 788.505 0.000 788.645 0.560 ;
    END
  END ifu_iu_pcfifo_create0_chk_idx[5]
  PIN ifu_iu_pcfifo_create0_chk_idx[6]
    DIRECTION OUTPUT ;
    USE SIGNAL ;
    PORT
      LAYER metal6 ;
        RECT 787.385 0.000 787.525 0.560 ;
    END
  END ifu_iu_pcfifo_create0_chk_idx[6]
  PIN ifu_iu_pcfifo_create0_chk_idx[7]
    DIRECTION OUTPUT ;
    USE SIGNAL ;
    PORT
      LAYER metal4 ;
        RECT 787.385 0.000 787.525 0.560 ;
    END
  END ifu_iu_pcfifo_create0_chk_idx[7]
  PIN ifu_iu_pcfifo_create0_chk_idx[8]
    DIRECTION OUTPUT ;
    USE SIGNAL ;
    PORT
      LAYER metal6 ;
        RECT 786.265 0.000 786.405 0.560 ;
    END
  END ifu_iu_pcfifo_create0_chk_idx[8]
  PIN ifu_iu_pcfifo_create0_chk_idx[9]
    DIRECTION OUTPUT ;
    USE SIGNAL ;
    PORT
      LAYER metal4 ;
        RECT 786.265 0.000 786.405 0.560 ;
    END
  END ifu_iu_pcfifo_create0_chk_idx[9]
  PIN ifu_iu_pcfifo_create0_cur_pc[0]
    DIRECTION OUTPUT ;
    USE SIGNAL ;
    PORT
      LAYER metal6 ;
        RECT 813.145 0.000 813.285 0.560 ;
    END
  END ifu_iu_pcfifo_create0_cur_pc[0]
  PIN ifu_iu_pcfifo_create0_cur_pc[10]
    DIRECTION OUTPUT ;
    USE SIGNAL ;
    PORT
      LAYER metal6 ;
        RECT 807.545 0.000 807.685 0.560 ;
    END
  END ifu_iu_pcfifo_create0_cur_pc[10]
  PIN ifu_iu_pcfifo_create0_cur_pc[11]
    DIRECTION OUTPUT ;
    USE SIGNAL ;
    PORT
      LAYER metal4 ;
        RECT 807.545 0.000 807.685 0.560 ;
    END
  END ifu_iu_pcfifo_create0_cur_pc[11]
  PIN ifu_iu_pcfifo_create0_cur_pc[12]
    DIRECTION OUTPUT ;
    USE SIGNAL ;
    PORT
      LAYER metal6 ;
        RECT 806.425 0.000 806.565 0.560 ;
    END
  END ifu_iu_pcfifo_create0_cur_pc[12]
  PIN ifu_iu_pcfifo_create0_cur_pc[13]
    DIRECTION OUTPUT ;
    USE SIGNAL ;
    PORT
      LAYER metal4 ;
        RECT 806.425 0.000 806.565 0.560 ;
    END
  END ifu_iu_pcfifo_create0_cur_pc[13]
  PIN ifu_iu_pcfifo_create0_cur_pc[14]
    DIRECTION OUTPUT ;
    USE SIGNAL ;
    PORT
      LAYER metal6 ;
        RECT 805.305 0.000 805.445 0.560 ;
    END
  END ifu_iu_pcfifo_create0_cur_pc[14]
  PIN ifu_iu_pcfifo_create0_cur_pc[15]
    DIRECTION OUTPUT ;
    USE SIGNAL ;
    PORT
      LAYER metal4 ;
        RECT 805.305 0.000 805.445 0.560 ;
    END
  END ifu_iu_pcfifo_create0_cur_pc[15]
  PIN ifu_iu_pcfifo_create0_cur_pc[16]
    DIRECTION OUTPUT ;
    USE SIGNAL ;
    PORT
      LAYER metal6 ;
        RECT 804.185 0.000 804.325 0.560 ;
    END
  END ifu_iu_pcfifo_create0_cur_pc[16]
  PIN ifu_iu_pcfifo_create0_cur_pc[17]
    DIRECTION OUTPUT ;
    USE SIGNAL ;
    PORT
      LAYER metal4 ;
        RECT 804.185 0.000 804.325 0.560 ;
    END
  END ifu_iu_pcfifo_create0_cur_pc[17]
  PIN ifu_iu_pcfifo_create0_cur_pc[18]
    DIRECTION OUTPUT ;
    USE SIGNAL ;
    PORT
      LAYER metal6 ;
        RECT 803.065 0.000 803.205 0.560 ;
    END
  END ifu_iu_pcfifo_create0_cur_pc[18]
  PIN ifu_iu_pcfifo_create0_cur_pc[19]
    DIRECTION OUTPUT ;
    USE SIGNAL ;
    PORT
      LAYER metal4 ;
        RECT 803.065 0.000 803.205 0.560 ;
    END
  END ifu_iu_pcfifo_create0_cur_pc[19]
  PIN ifu_iu_pcfifo_create0_cur_pc[1]
    DIRECTION OUTPUT ;
    USE SIGNAL ;
    PORT
      LAYER metal4 ;
        RECT 813.145 0.000 813.285 0.560 ;
    END
  END ifu_iu_pcfifo_create0_cur_pc[1]
  PIN ifu_iu_pcfifo_create0_cur_pc[20]
    DIRECTION OUTPUT ;
    USE SIGNAL ;
    PORT
      LAYER metal6 ;
        RECT 801.945 0.000 802.085 0.560 ;
    END
  END ifu_iu_pcfifo_create0_cur_pc[20]
  PIN ifu_iu_pcfifo_create0_cur_pc[21]
    DIRECTION OUTPUT ;
    USE SIGNAL ;
    PORT
      LAYER metal4 ;
        RECT 801.945 0.000 802.085 0.560 ;
    END
  END ifu_iu_pcfifo_create0_cur_pc[21]
  PIN ifu_iu_pcfifo_create0_cur_pc[22]
    DIRECTION OUTPUT ;
    USE SIGNAL ;
    PORT
      LAYER metal6 ;
        RECT 800.825 0.000 800.965 0.560 ;
    END
  END ifu_iu_pcfifo_create0_cur_pc[22]
  PIN ifu_iu_pcfifo_create0_cur_pc[23]
    DIRECTION OUTPUT ;
    USE SIGNAL ;
    PORT
      LAYER metal4 ;
        RECT 800.825 0.000 800.965 0.560 ;
    END
  END ifu_iu_pcfifo_create0_cur_pc[23]
  PIN ifu_iu_pcfifo_create0_cur_pc[24]
    DIRECTION OUTPUT ;
    USE SIGNAL ;
    PORT
      LAYER metal6 ;
        RECT 799.705 0.000 799.845 0.560 ;
    END
  END ifu_iu_pcfifo_create0_cur_pc[24]
  PIN ifu_iu_pcfifo_create0_cur_pc[25]
    DIRECTION OUTPUT ;
    USE SIGNAL ;
    PORT
      LAYER metal4 ;
        RECT 799.705 0.000 799.845 0.560 ;
    END
  END ifu_iu_pcfifo_create0_cur_pc[25]
  PIN ifu_iu_pcfifo_create0_cur_pc[26]
    DIRECTION OUTPUT ;
    USE SIGNAL ;
    PORT
      LAYER metal6 ;
        RECT 798.585 0.000 798.725 0.560 ;
    END
  END ifu_iu_pcfifo_create0_cur_pc[26]
  PIN ifu_iu_pcfifo_create0_cur_pc[27]
    DIRECTION OUTPUT ;
    USE SIGNAL ;
    PORT
      LAYER metal4 ;
        RECT 798.585 0.000 798.725 0.560 ;
    END
  END ifu_iu_pcfifo_create0_cur_pc[27]
  PIN ifu_iu_pcfifo_create0_cur_pc[28]
    DIRECTION OUTPUT ;
    USE SIGNAL ;
    PORT
      LAYER metal6 ;
        RECT 797.465 0.000 797.605 0.560 ;
    END
  END ifu_iu_pcfifo_create0_cur_pc[28]
  PIN ifu_iu_pcfifo_create0_cur_pc[29]
    DIRECTION OUTPUT ;
    USE SIGNAL ;
    PORT
      LAYER metal4 ;
        RECT 797.465 0.000 797.605 0.560 ;
    END
  END ifu_iu_pcfifo_create0_cur_pc[29]
  PIN ifu_iu_pcfifo_create0_cur_pc[2]
    DIRECTION OUTPUT ;
    USE SIGNAL ;
    PORT
      LAYER metal6 ;
        RECT 812.025 0.000 812.165 0.560 ;
    END
  END ifu_iu_pcfifo_create0_cur_pc[2]
  PIN ifu_iu_pcfifo_create0_cur_pc[30]
    DIRECTION OUTPUT ;
    USE SIGNAL ;
    PORT
      LAYER metal6 ;
        RECT 796.345 0.000 796.485 0.560 ;
    END
  END ifu_iu_pcfifo_create0_cur_pc[30]
  PIN ifu_iu_pcfifo_create0_cur_pc[31]
    DIRECTION OUTPUT ;
    USE SIGNAL ;
    PORT
      LAYER metal4 ;
        RECT 796.345 0.000 796.485 0.560 ;
    END
  END ifu_iu_pcfifo_create0_cur_pc[31]
  PIN ifu_iu_pcfifo_create0_cur_pc[32]
    DIRECTION OUTPUT ;
    USE SIGNAL ;
    PORT
      LAYER metal6 ;
        RECT 795.225 0.000 795.365 0.560 ;
    END
  END ifu_iu_pcfifo_create0_cur_pc[32]
  PIN ifu_iu_pcfifo_create0_cur_pc[33]
    DIRECTION OUTPUT ;
    USE SIGNAL ;
    PORT
      LAYER metal4 ;
        RECT 795.225 0.000 795.365 0.560 ;
    END
  END ifu_iu_pcfifo_create0_cur_pc[33]
  PIN ifu_iu_pcfifo_create0_cur_pc[34]
    DIRECTION OUTPUT ;
    USE SIGNAL ;
    PORT
      LAYER metal6 ;
        RECT 794.105 0.000 794.245 0.560 ;
    END
  END ifu_iu_pcfifo_create0_cur_pc[34]
  PIN ifu_iu_pcfifo_create0_cur_pc[35]
    DIRECTION OUTPUT ;
    USE SIGNAL ;
    PORT
      LAYER metal4 ;
        RECT 794.105 0.000 794.245 0.560 ;
    END
  END ifu_iu_pcfifo_create0_cur_pc[35]
  PIN ifu_iu_pcfifo_create0_cur_pc[36]
    DIRECTION OUTPUT ;
    USE SIGNAL ;
    PORT
      LAYER metal6 ;
        RECT 792.985 0.000 793.125 0.560 ;
    END
  END ifu_iu_pcfifo_create0_cur_pc[36]
  PIN ifu_iu_pcfifo_create0_cur_pc[37]
    DIRECTION OUTPUT ;
    USE SIGNAL ;
    PORT
      LAYER metal4 ;
        RECT 792.985 0.000 793.125 0.560 ;
    END
  END ifu_iu_pcfifo_create0_cur_pc[37]
  PIN ifu_iu_pcfifo_create0_cur_pc[38]
    DIRECTION OUTPUT ;
    USE SIGNAL ;
    PORT
      LAYER metal6 ;
        RECT 791.865 0.000 792.005 0.560 ;
    END
  END ifu_iu_pcfifo_create0_cur_pc[38]
  PIN ifu_iu_pcfifo_create0_cur_pc[39]
    DIRECTION OUTPUT ;
    USE SIGNAL ;
    PORT
      LAYER metal4 ;
        RECT 791.865 0.000 792.005 0.560 ;
    END
  END ifu_iu_pcfifo_create0_cur_pc[39]
  PIN ifu_iu_pcfifo_create0_cur_pc[3]
    DIRECTION OUTPUT ;
    USE SIGNAL ;
    PORT
      LAYER metal4 ;
        RECT 812.025 0.000 812.165 0.560 ;
    END
  END ifu_iu_pcfifo_create0_cur_pc[3]
  PIN ifu_iu_pcfifo_create0_cur_pc[4]
    DIRECTION OUTPUT ;
    USE SIGNAL ;
    PORT
      LAYER metal6 ;
        RECT 810.905 0.000 811.045 0.560 ;
    END
  END ifu_iu_pcfifo_create0_cur_pc[4]
  PIN ifu_iu_pcfifo_create0_cur_pc[5]
    DIRECTION OUTPUT ;
    USE SIGNAL ;
    PORT
      LAYER metal4 ;
        RECT 810.905 0.000 811.045 0.560 ;
    END
  END ifu_iu_pcfifo_create0_cur_pc[5]
  PIN ifu_iu_pcfifo_create0_cur_pc[6]
    DIRECTION OUTPUT ;
    USE SIGNAL ;
    PORT
      LAYER metal6 ;
        RECT 809.785 0.000 809.925 0.560 ;
    END
  END ifu_iu_pcfifo_create0_cur_pc[6]
  PIN ifu_iu_pcfifo_create0_cur_pc[7]
    DIRECTION OUTPUT ;
    USE SIGNAL ;
    PORT
      LAYER metal4 ;
        RECT 809.785 0.000 809.925 0.560 ;
    END
  END ifu_iu_pcfifo_create0_cur_pc[7]
  PIN ifu_iu_pcfifo_create0_cur_pc[8]
    DIRECTION OUTPUT ;
    USE SIGNAL ;
    PORT
      LAYER metal6 ;
        RECT 808.665 0.000 808.805 0.560 ;
    END
  END ifu_iu_pcfifo_create0_cur_pc[8]
  PIN ifu_iu_pcfifo_create0_cur_pc[9]
    DIRECTION OUTPUT ;
    USE SIGNAL ;
    PORT
      LAYER metal4 ;
        RECT 808.665 0.000 808.805 0.560 ;
    END
  END ifu_iu_pcfifo_create0_cur_pc[9]
  PIN ifu_iu_pcfifo_create0_dst_vld
    DIRECTION OUTPUT ;
    USE SIGNAL ;
    PORT
      LAYER metal4 ;
        RECT 814.265 0.000 814.405 0.560 ;
    END
  END ifu_iu_pcfifo_create0_dst_vld
  PIN ifu_iu_pcfifo_create0_en
    DIRECTION OUTPUT ;
    USE SIGNAL ;
    PORT
      LAYER metal6 ;
        RECT 814.265 0.000 814.405 0.560 ;
    END
  END ifu_iu_pcfifo_create0_en
  PIN ifu_iu_pcfifo_create0_gateclk_en
    DIRECTION OUTPUT ;
    USE SIGNAL ;
    PORT
      LAYER metal4 ;
        RECT 815.385 0.000 815.525 0.560 ;
    END
  END ifu_iu_pcfifo_create0_gateclk_en
  PIN ifu_iu_pcfifo_create0_jal
    DIRECTION OUTPUT ;
    USE SIGNAL ;
    PORT
      LAYER metal6 ;
        RECT 815.385 0.000 815.525 0.560 ;
    END
  END ifu_iu_pcfifo_create0_jal
  PIN ifu_iu_pcfifo_create0_jalr
    DIRECTION OUTPUT ;
    USE SIGNAL ;
    PORT
      LAYER metal4 ;
        RECT 816.505 0.000 816.645 0.560 ;
    END
  END ifu_iu_pcfifo_create0_jalr
  PIN ifu_iu_pcfifo_create0_jmp_mispred
    DIRECTION OUTPUT ;
    USE SIGNAL ;
    PORT
      LAYER metal6 ;
        RECT 816.505 0.000 816.645 0.560 ;
    END
  END ifu_iu_pcfifo_create0_jmp_mispred
  PIN ifu_iu_pcfifo_create0_tar_pc[0]
    DIRECTION OUTPUT ;
    USE SIGNAL ;
    PORT
      LAYER metal6 ;
        RECT 838.905 0.000 839.045 0.560 ;
    END
  END ifu_iu_pcfifo_create0_tar_pc[0]
  PIN ifu_iu_pcfifo_create0_tar_pc[10]
    DIRECTION OUTPUT ;
    USE SIGNAL ;
    PORT
      LAYER metal6 ;
        RECT 833.305 0.000 833.445 0.560 ;
    END
  END ifu_iu_pcfifo_create0_tar_pc[10]
  PIN ifu_iu_pcfifo_create0_tar_pc[11]
    DIRECTION OUTPUT ;
    USE SIGNAL ;
    PORT
      LAYER metal4 ;
        RECT 833.305 0.000 833.445 0.560 ;
    END
  END ifu_iu_pcfifo_create0_tar_pc[11]
  PIN ifu_iu_pcfifo_create0_tar_pc[12]
    DIRECTION OUTPUT ;
    USE SIGNAL ;
    PORT
      LAYER metal6 ;
        RECT 832.185 0.000 832.325 0.560 ;
    END
  END ifu_iu_pcfifo_create0_tar_pc[12]
  PIN ifu_iu_pcfifo_create0_tar_pc[13]
    DIRECTION OUTPUT ;
    USE SIGNAL ;
    PORT
      LAYER metal4 ;
        RECT 832.185 0.000 832.325 0.560 ;
    END
  END ifu_iu_pcfifo_create0_tar_pc[13]
  PIN ifu_iu_pcfifo_create0_tar_pc[14]
    DIRECTION OUTPUT ;
    USE SIGNAL ;
    PORT
      LAYER metal6 ;
        RECT 831.065 0.000 831.205 0.560 ;
    END
  END ifu_iu_pcfifo_create0_tar_pc[14]
  PIN ifu_iu_pcfifo_create0_tar_pc[15]
    DIRECTION OUTPUT ;
    USE SIGNAL ;
    PORT
      LAYER metal4 ;
        RECT 831.065 0.000 831.205 0.560 ;
    END
  END ifu_iu_pcfifo_create0_tar_pc[15]
  PIN ifu_iu_pcfifo_create0_tar_pc[16]
    DIRECTION OUTPUT ;
    USE SIGNAL ;
    PORT
      LAYER metal6 ;
        RECT 829.945 0.000 830.085 0.560 ;
    END
  END ifu_iu_pcfifo_create0_tar_pc[16]
  PIN ifu_iu_pcfifo_create0_tar_pc[17]
    DIRECTION OUTPUT ;
    USE SIGNAL ;
    PORT
      LAYER metal4 ;
        RECT 829.945 0.000 830.085 0.560 ;
    END
  END ifu_iu_pcfifo_create0_tar_pc[17]
  PIN ifu_iu_pcfifo_create0_tar_pc[18]
    DIRECTION OUTPUT ;
    USE SIGNAL ;
    PORT
      LAYER metal6 ;
        RECT 828.825 0.000 828.965 0.560 ;
    END
  END ifu_iu_pcfifo_create0_tar_pc[18]
  PIN ifu_iu_pcfifo_create0_tar_pc[19]
    DIRECTION OUTPUT ;
    USE SIGNAL ;
    PORT
      LAYER metal4 ;
        RECT 828.825 0.000 828.965 0.560 ;
    END
  END ifu_iu_pcfifo_create0_tar_pc[19]
  PIN ifu_iu_pcfifo_create0_tar_pc[1]
    DIRECTION OUTPUT ;
    USE SIGNAL ;
    PORT
      LAYER metal4 ;
        RECT 838.905 0.000 839.045 0.560 ;
    END
  END ifu_iu_pcfifo_create0_tar_pc[1]
  PIN ifu_iu_pcfifo_create0_tar_pc[20]
    DIRECTION OUTPUT ;
    USE SIGNAL ;
    PORT
      LAYER metal6 ;
        RECT 827.705 0.000 827.845 0.560 ;
    END
  END ifu_iu_pcfifo_create0_tar_pc[20]
  PIN ifu_iu_pcfifo_create0_tar_pc[21]
    DIRECTION OUTPUT ;
    USE SIGNAL ;
    PORT
      LAYER metal4 ;
        RECT 827.705 0.000 827.845 0.560 ;
    END
  END ifu_iu_pcfifo_create0_tar_pc[21]
  PIN ifu_iu_pcfifo_create0_tar_pc[22]
    DIRECTION OUTPUT ;
    USE SIGNAL ;
    PORT
      LAYER metal6 ;
        RECT 826.585 0.000 826.725 0.560 ;
    END
  END ifu_iu_pcfifo_create0_tar_pc[22]
  PIN ifu_iu_pcfifo_create0_tar_pc[23]
    DIRECTION OUTPUT ;
    USE SIGNAL ;
    PORT
      LAYER metal4 ;
        RECT 826.585 0.000 826.725 0.560 ;
    END
  END ifu_iu_pcfifo_create0_tar_pc[23]
  PIN ifu_iu_pcfifo_create0_tar_pc[24]
    DIRECTION OUTPUT ;
    USE SIGNAL ;
    PORT
      LAYER metal6 ;
        RECT 825.465 0.000 825.605 0.560 ;
    END
  END ifu_iu_pcfifo_create0_tar_pc[24]
  PIN ifu_iu_pcfifo_create0_tar_pc[25]
    DIRECTION OUTPUT ;
    USE SIGNAL ;
    PORT
      LAYER metal4 ;
        RECT 825.465 0.000 825.605 0.560 ;
    END
  END ifu_iu_pcfifo_create0_tar_pc[25]
  PIN ifu_iu_pcfifo_create0_tar_pc[26]
    DIRECTION OUTPUT ;
    USE SIGNAL ;
    PORT
      LAYER metal6 ;
        RECT 824.345 0.000 824.485 0.560 ;
    END
  END ifu_iu_pcfifo_create0_tar_pc[26]
  PIN ifu_iu_pcfifo_create0_tar_pc[27]
    DIRECTION OUTPUT ;
    USE SIGNAL ;
    PORT
      LAYER metal4 ;
        RECT 824.345 0.000 824.485 0.560 ;
    END
  END ifu_iu_pcfifo_create0_tar_pc[27]
  PIN ifu_iu_pcfifo_create0_tar_pc[28]
    DIRECTION OUTPUT ;
    USE SIGNAL ;
    PORT
      LAYER metal6 ;
        RECT 823.225 0.000 823.365 0.560 ;
    END
  END ifu_iu_pcfifo_create0_tar_pc[28]
  PIN ifu_iu_pcfifo_create0_tar_pc[29]
    DIRECTION OUTPUT ;
    USE SIGNAL ;
    PORT
      LAYER metal4 ;
        RECT 823.225 0.000 823.365 0.560 ;
    END
  END ifu_iu_pcfifo_create0_tar_pc[29]
  PIN ifu_iu_pcfifo_create0_tar_pc[2]
    DIRECTION OUTPUT ;
    USE SIGNAL ;
    PORT
      LAYER metal6 ;
        RECT 837.785 0.000 837.925 0.560 ;
    END
  END ifu_iu_pcfifo_create0_tar_pc[2]
  PIN ifu_iu_pcfifo_create0_tar_pc[30]
    DIRECTION OUTPUT ;
    USE SIGNAL ;
    PORT
      LAYER metal6 ;
        RECT 822.105 0.000 822.245 0.560 ;
    END
  END ifu_iu_pcfifo_create0_tar_pc[30]
  PIN ifu_iu_pcfifo_create0_tar_pc[31]
    DIRECTION OUTPUT ;
    USE SIGNAL ;
    PORT
      LAYER metal4 ;
        RECT 822.105 0.000 822.245 0.560 ;
    END
  END ifu_iu_pcfifo_create0_tar_pc[31]
  PIN ifu_iu_pcfifo_create0_tar_pc[32]
    DIRECTION OUTPUT ;
    USE SIGNAL ;
    PORT
      LAYER metal6 ;
        RECT 820.985 0.000 821.125 0.560 ;
    END
  END ifu_iu_pcfifo_create0_tar_pc[32]
  PIN ifu_iu_pcfifo_create0_tar_pc[33]
    DIRECTION OUTPUT ;
    USE SIGNAL ;
    PORT
      LAYER metal4 ;
        RECT 820.985 0.000 821.125 0.560 ;
    END
  END ifu_iu_pcfifo_create0_tar_pc[33]
  PIN ifu_iu_pcfifo_create0_tar_pc[34]
    DIRECTION OUTPUT ;
    USE SIGNAL ;
    PORT
      LAYER metal6 ;
        RECT 819.865 0.000 820.005 0.560 ;
    END
  END ifu_iu_pcfifo_create0_tar_pc[34]
  PIN ifu_iu_pcfifo_create0_tar_pc[35]
    DIRECTION OUTPUT ;
    USE SIGNAL ;
    PORT
      LAYER metal4 ;
        RECT 819.865 0.000 820.005 0.560 ;
    END
  END ifu_iu_pcfifo_create0_tar_pc[35]
  PIN ifu_iu_pcfifo_create0_tar_pc[36]
    DIRECTION OUTPUT ;
    USE SIGNAL ;
    PORT
      LAYER metal6 ;
        RECT 818.745 0.000 818.885 0.560 ;
    END
  END ifu_iu_pcfifo_create0_tar_pc[36]
  PIN ifu_iu_pcfifo_create0_tar_pc[37]
    DIRECTION OUTPUT ;
    USE SIGNAL ;
    PORT
      LAYER metal4 ;
        RECT 818.745 0.000 818.885 0.560 ;
    END
  END ifu_iu_pcfifo_create0_tar_pc[37]
  PIN ifu_iu_pcfifo_create0_tar_pc[38]
    DIRECTION OUTPUT ;
    USE SIGNAL ;
    PORT
      LAYER metal6 ;
        RECT 817.625 0.000 817.765 0.560 ;
    END
  END ifu_iu_pcfifo_create0_tar_pc[38]
  PIN ifu_iu_pcfifo_create0_tar_pc[39]
    DIRECTION OUTPUT ;
    USE SIGNAL ;
    PORT
      LAYER metal4 ;
        RECT 817.625 0.000 817.765 0.560 ;
    END
  END ifu_iu_pcfifo_create0_tar_pc[39]
  PIN ifu_iu_pcfifo_create0_tar_pc[3]
    DIRECTION OUTPUT ;
    USE SIGNAL ;
    PORT
      LAYER metal4 ;
        RECT 837.785 0.000 837.925 0.560 ;
    END
  END ifu_iu_pcfifo_create0_tar_pc[3]
  PIN ifu_iu_pcfifo_create0_tar_pc[4]
    DIRECTION OUTPUT ;
    USE SIGNAL ;
    PORT
      LAYER metal6 ;
        RECT 836.665 0.000 836.805 0.560 ;
    END
  END ifu_iu_pcfifo_create0_tar_pc[4]
  PIN ifu_iu_pcfifo_create0_tar_pc[5]
    DIRECTION OUTPUT ;
    USE SIGNAL ;
    PORT
      LAYER metal4 ;
        RECT 836.665 0.000 836.805 0.560 ;
    END
  END ifu_iu_pcfifo_create0_tar_pc[5]
  PIN ifu_iu_pcfifo_create0_tar_pc[6]
    DIRECTION OUTPUT ;
    USE SIGNAL ;
    PORT
      LAYER metal6 ;
        RECT 835.545 0.000 835.685 0.560 ;
    END
  END ifu_iu_pcfifo_create0_tar_pc[6]
  PIN ifu_iu_pcfifo_create0_tar_pc[7]
    DIRECTION OUTPUT ;
    USE SIGNAL ;
    PORT
      LAYER metal4 ;
        RECT 835.545 0.000 835.685 0.560 ;
    END
  END ifu_iu_pcfifo_create0_tar_pc[7]
  PIN ifu_iu_pcfifo_create0_tar_pc[8]
    DIRECTION OUTPUT ;
    USE SIGNAL ;
    PORT
      LAYER metal6 ;
        RECT 834.425 0.000 834.565 0.560 ;
    END
  END ifu_iu_pcfifo_create0_tar_pc[8]
  PIN ifu_iu_pcfifo_create0_tar_pc[9]
    DIRECTION OUTPUT ;
    USE SIGNAL ;
    PORT
      LAYER metal4 ;
        RECT 834.425 0.000 834.565 0.560 ;
    END
  END ifu_iu_pcfifo_create0_tar_pc[9]
  PIN ifu_iu_pcfifo_create1_bht_pred
    DIRECTION OUTPUT ;
    USE SIGNAL ;
    PORT
      LAYER metal4 ;
        RECT 840.025 0.000 840.165 0.560 ;
    END
  END ifu_iu_pcfifo_create1_bht_pred
  PIN ifu_iu_pcfifo_create1_chk_idx[0]
    DIRECTION OUTPUT ;
    USE SIGNAL ;
    PORT
      LAYER metal6 ;
        RECT 853.465 0.000 853.605 0.560 ;
    END
  END ifu_iu_pcfifo_create1_chk_idx[0]
  PIN ifu_iu_pcfifo_create1_chk_idx[10]
    DIRECTION OUTPUT ;
    USE SIGNAL ;
    PORT
      LAYER metal6 ;
        RECT 847.865 0.000 848.005 0.560 ;
    END
  END ifu_iu_pcfifo_create1_chk_idx[10]
  PIN ifu_iu_pcfifo_create1_chk_idx[11]
    DIRECTION OUTPUT ;
    USE SIGNAL ;
    PORT
      LAYER metal4 ;
        RECT 847.865 0.000 848.005 0.560 ;
    END
  END ifu_iu_pcfifo_create1_chk_idx[11]
  PIN ifu_iu_pcfifo_create1_chk_idx[12]
    DIRECTION OUTPUT ;
    USE SIGNAL ;
    PORT
      LAYER metal6 ;
        RECT 846.745 0.000 846.885 0.560 ;
    END
  END ifu_iu_pcfifo_create1_chk_idx[12]
  PIN ifu_iu_pcfifo_create1_chk_idx[13]
    DIRECTION OUTPUT ;
    USE SIGNAL ;
    PORT
      LAYER metal4 ;
        RECT 846.745 0.000 846.885 0.560 ;
    END
  END ifu_iu_pcfifo_create1_chk_idx[13]
  PIN ifu_iu_pcfifo_create1_chk_idx[14]
    DIRECTION OUTPUT ;
    USE SIGNAL ;
    PORT
      LAYER metal6 ;
        RECT 845.625 0.000 845.765 0.560 ;
    END
  END ifu_iu_pcfifo_create1_chk_idx[14]
  PIN ifu_iu_pcfifo_create1_chk_idx[15]
    DIRECTION OUTPUT ;
    USE SIGNAL ;
    PORT
      LAYER metal4 ;
        RECT 845.625 0.000 845.765 0.560 ;
    END
  END ifu_iu_pcfifo_create1_chk_idx[15]
  PIN ifu_iu_pcfifo_create1_chk_idx[16]
    DIRECTION OUTPUT ;
    USE SIGNAL ;
    PORT
      LAYER metal6 ;
        RECT 844.505 0.000 844.645 0.560 ;
    END
  END ifu_iu_pcfifo_create1_chk_idx[16]
  PIN ifu_iu_pcfifo_create1_chk_idx[17]
    DIRECTION OUTPUT ;
    USE SIGNAL ;
    PORT
      LAYER metal4 ;
        RECT 844.505 0.000 844.645 0.560 ;
    END
  END ifu_iu_pcfifo_create1_chk_idx[17]
  PIN ifu_iu_pcfifo_create1_chk_idx[18]
    DIRECTION OUTPUT ;
    USE SIGNAL ;
    PORT
      LAYER metal6 ;
        RECT 843.385 0.000 843.525 0.560 ;
    END
  END ifu_iu_pcfifo_create1_chk_idx[18]
  PIN ifu_iu_pcfifo_create1_chk_idx[19]
    DIRECTION OUTPUT ;
    USE SIGNAL ;
    PORT
      LAYER metal4 ;
        RECT 843.385 0.000 843.525 0.560 ;
    END
  END ifu_iu_pcfifo_create1_chk_idx[19]
  PIN ifu_iu_pcfifo_create1_chk_idx[1]
    DIRECTION OUTPUT ;
    USE SIGNAL ;
    PORT
      LAYER metal4 ;
        RECT 853.465 0.000 853.605 0.560 ;
    END
  END ifu_iu_pcfifo_create1_chk_idx[1]
  PIN ifu_iu_pcfifo_create1_chk_idx[20]
    DIRECTION OUTPUT ;
    USE SIGNAL ;
    PORT
      LAYER metal6 ;
        RECT 842.265 0.000 842.405 0.560 ;
    END
  END ifu_iu_pcfifo_create1_chk_idx[20]
  PIN ifu_iu_pcfifo_create1_chk_idx[21]
    DIRECTION OUTPUT ;
    USE SIGNAL ;
    PORT
      LAYER metal4 ;
        RECT 842.265 0.000 842.405 0.560 ;
    END
  END ifu_iu_pcfifo_create1_chk_idx[21]
  PIN ifu_iu_pcfifo_create1_chk_idx[22]
    DIRECTION OUTPUT ;
    USE SIGNAL ;
    PORT
      LAYER metal6 ;
        RECT 841.145 0.000 841.285 0.560 ;
    END
  END ifu_iu_pcfifo_create1_chk_idx[22]
  PIN ifu_iu_pcfifo_create1_chk_idx[23]
    DIRECTION OUTPUT ;
    USE SIGNAL ;
    PORT
      LAYER metal4 ;
        RECT 841.145 0.000 841.285 0.560 ;
    END
  END ifu_iu_pcfifo_create1_chk_idx[23]
  PIN ifu_iu_pcfifo_create1_chk_idx[24]
    DIRECTION OUTPUT ;
    USE SIGNAL ;
    PORT
      LAYER metal6 ;
        RECT 840.025 0.000 840.165 0.560 ;
    END
  END ifu_iu_pcfifo_create1_chk_idx[24]
  PIN ifu_iu_pcfifo_create1_chk_idx[2]
    DIRECTION OUTPUT ;
    USE SIGNAL ;
    PORT
      LAYER metal6 ;
        RECT 852.345 0.000 852.485 0.560 ;
    END
  END ifu_iu_pcfifo_create1_chk_idx[2]
  PIN ifu_iu_pcfifo_create1_chk_idx[3]
    DIRECTION OUTPUT ;
    USE SIGNAL ;
    PORT
      LAYER metal4 ;
        RECT 852.345 0.000 852.485 0.560 ;
    END
  END ifu_iu_pcfifo_create1_chk_idx[3]
  PIN ifu_iu_pcfifo_create1_chk_idx[4]
    DIRECTION OUTPUT ;
    USE SIGNAL ;
    PORT
      LAYER metal6 ;
        RECT 851.225 0.000 851.365 0.560 ;
    END
  END ifu_iu_pcfifo_create1_chk_idx[4]
  PIN ifu_iu_pcfifo_create1_chk_idx[5]
    DIRECTION OUTPUT ;
    USE SIGNAL ;
    PORT
      LAYER metal4 ;
        RECT 851.225 0.000 851.365 0.560 ;
    END
  END ifu_iu_pcfifo_create1_chk_idx[5]
  PIN ifu_iu_pcfifo_create1_chk_idx[6]
    DIRECTION OUTPUT ;
    USE SIGNAL ;
    PORT
      LAYER metal6 ;
        RECT 850.105 0.000 850.245 0.560 ;
    END
  END ifu_iu_pcfifo_create1_chk_idx[6]
  PIN ifu_iu_pcfifo_create1_chk_idx[7]
    DIRECTION OUTPUT ;
    USE SIGNAL ;
    PORT
      LAYER metal4 ;
        RECT 850.105 0.000 850.245 0.560 ;
    END
  END ifu_iu_pcfifo_create1_chk_idx[7]
  PIN ifu_iu_pcfifo_create1_chk_idx[8]
    DIRECTION OUTPUT ;
    USE SIGNAL ;
    PORT
      LAYER metal6 ;
        RECT 848.985 0.000 849.125 0.560 ;
    END
  END ifu_iu_pcfifo_create1_chk_idx[8]
  PIN ifu_iu_pcfifo_create1_chk_idx[9]
    DIRECTION OUTPUT ;
    USE SIGNAL ;
    PORT
      LAYER metal4 ;
        RECT 848.985 0.000 849.125 0.560 ;
    END
  END ifu_iu_pcfifo_create1_chk_idx[9]
  PIN ifu_iu_pcfifo_create1_cur_pc[0]
    DIRECTION OUTPUT ;
    USE SIGNAL ;
    PORT
      LAYER metal6 ;
        RECT 875.865 0.000 876.005 0.560 ;
    END
  END ifu_iu_pcfifo_create1_cur_pc[0]
  PIN ifu_iu_pcfifo_create1_cur_pc[10]
    DIRECTION OUTPUT ;
    USE SIGNAL ;
    PORT
      LAYER metal6 ;
        RECT 870.265 0.000 870.405 0.560 ;
    END
  END ifu_iu_pcfifo_create1_cur_pc[10]
  PIN ifu_iu_pcfifo_create1_cur_pc[11]
    DIRECTION OUTPUT ;
    USE SIGNAL ;
    PORT
      LAYER metal4 ;
        RECT 870.265 0.000 870.405 0.560 ;
    END
  END ifu_iu_pcfifo_create1_cur_pc[11]
  PIN ifu_iu_pcfifo_create1_cur_pc[12]
    DIRECTION OUTPUT ;
    USE SIGNAL ;
    PORT
      LAYER metal6 ;
        RECT 869.145 0.000 869.285 0.560 ;
    END
  END ifu_iu_pcfifo_create1_cur_pc[12]
  PIN ifu_iu_pcfifo_create1_cur_pc[13]
    DIRECTION OUTPUT ;
    USE SIGNAL ;
    PORT
      LAYER metal4 ;
        RECT 869.145 0.000 869.285 0.560 ;
    END
  END ifu_iu_pcfifo_create1_cur_pc[13]
  PIN ifu_iu_pcfifo_create1_cur_pc[14]
    DIRECTION OUTPUT ;
    USE SIGNAL ;
    PORT
      LAYER metal6 ;
        RECT 868.025 0.000 868.165 0.560 ;
    END
  END ifu_iu_pcfifo_create1_cur_pc[14]
  PIN ifu_iu_pcfifo_create1_cur_pc[15]
    DIRECTION OUTPUT ;
    USE SIGNAL ;
    PORT
      LAYER metal4 ;
        RECT 868.025 0.000 868.165 0.560 ;
    END
  END ifu_iu_pcfifo_create1_cur_pc[15]
  PIN ifu_iu_pcfifo_create1_cur_pc[16]
    DIRECTION OUTPUT ;
    USE SIGNAL ;
    PORT
      LAYER metal6 ;
        RECT 866.905 0.000 867.045 0.560 ;
    END
  END ifu_iu_pcfifo_create1_cur_pc[16]
  PIN ifu_iu_pcfifo_create1_cur_pc[17]
    DIRECTION OUTPUT ;
    USE SIGNAL ;
    PORT
      LAYER metal4 ;
        RECT 866.905 0.000 867.045 0.560 ;
    END
  END ifu_iu_pcfifo_create1_cur_pc[17]
  PIN ifu_iu_pcfifo_create1_cur_pc[18]
    DIRECTION OUTPUT ;
    USE SIGNAL ;
    PORT
      LAYER metal6 ;
        RECT 865.785 0.000 865.925 0.560 ;
    END
  END ifu_iu_pcfifo_create1_cur_pc[18]
  PIN ifu_iu_pcfifo_create1_cur_pc[19]
    DIRECTION OUTPUT ;
    USE SIGNAL ;
    PORT
      LAYER metal4 ;
        RECT 865.785 0.000 865.925 0.560 ;
    END
  END ifu_iu_pcfifo_create1_cur_pc[19]
  PIN ifu_iu_pcfifo_create1_cur_pc[1]
    DIRECTION OUTPUT ;
    USE SIGNAL ;
    PORT
      LAYER metal4 ;
        RECT 875.865 0.000 876.005 0.560 ;
    END
  END ifu_iu_pcfifo_create1_cur_pc[1]
  PIN ifu_iu_pcfifo_create1_cur_pc[20]
    DIRECTION OUTPUT ;
    USE SIGNAL ;
    PORT
      LAYER metal6 ;
        RECT 864.665 0.000 864.805 0.560 ;
    END
  END ifu_iu_pcfifo_create1_cur_pc[20]
  PIN ifu_iu_pcfifo_create1_cur_pc[21]
    DIRECTION OUTPUT ;
    USE SIGNAL ;
    PORT
      LAYER metal4 ;
        RECT 864.665 0.000 864.805 0.560 ;
    END
  END ifu_iu_pcfifo_create1_cur_pc[21]
  PIN ifu_iu_pcfifo_create1_cur_pc[22]
    DIRECTION OUTPUT ;
    USE SIGNAL ;
    PORT
      LAYER metal6 ;
        RECT 863.545 0.000 863.685 0.560 ;
    END
  END ifu_iu_pcfifo_create1_cur_pc[22]
  PIN ifu_iu_pcfifo_create1_cur_pc[23]
    DIRECTION OUTPUT ;
    USE SIGNAL ;
    PORT
      LAYER metal4 ;
        RECT 863.545 0.000 863.685 0.560 ;
    END
  END ifu_iu_pcfifo_create1_cur_pc[23]
  PIN ifu_iu_pcfifo_create1_cur_pc[24]
    DIRECTION OUTPUT ;
    USE SIGNAL ;
    PORT
      LAYER metal6 ;
        RECT 862.425 0.000 862.565 0.560 ;
    END
  END ifu_iu_pcfifo_create1_cur_pc[24]
  PIN ifu_iu_pcfifo_create1_cur_pc[25]
    DIRECTION OUTPUT ;
    USE SIGNAL ;
    PORT
      LAYER metal4 ;
        RECT 862.425 0.000 862.565 0.560 ;
    END
  END ifu_iu_pcfifo_create1_cur_pc[25]
  PIN ifu_iu_pcfifo_create1_cur_pc[26]
    DIRECTION OUTPUT ;
    USE SIGNAL ;
    PORT
      LAYER metal6 ;
        RECT 861.305 0.000 861.445 0.560 ;
    END
  END ifu_iu_pcfifo_create1_cur_pc[26]
  PIN ifu_iu_pcfifo_create1_cur_pc[27]
    DIRECTION OUTPUT ;
    USE SIGNAL ;
    PORT
      LAYER metal4 ;
        RECT 861.305 0.000 861.445 0.560 ;
    END
  END ifu_iu_pcfifo_create1_cur_pc[27]
  PIN ifu_iu_pcfifo_create1_cur_pc[28]
    DIRECTION OUTPUT ;
    USE SIGNAL ;
    PORT
      LAYER metal6 ;
        RECT 860.185 0.000 860.325 0.560 ;
    END
  END ifu_iu_pcfifo_create1_cur_pc[28]
  PIN ifu_iu_pcfifo_create1_cur_pc[29]
    DIRECTION OUTPUT ;
    USE SIGNAL ;
    PORT
      LAYER metal4 ;
        RECT 860.185 0.000 860.325 0.560 ;
    END
  END ifu_iu_pcfifo_create1_cur_pc[29]
  PIN ifu_iu_pcfifo_create1_cur_pc[2]
    DIRECTION OUTPUT ;
    USE SIGNAL ;
    PORT
      LAYER metal6 ;
        RECT 874.745 0.000 874.885 0.560 ;
    END
  END ifu_iu_pcfifo_create1_cur_pc[2]
  PIN ifu_iu_pcfifo_create1_cur_pc[30]
    DIRECTION OUTPUT ;
    USE SIGNAL ;
    PORT
      LAYER metal6 ;
        RECT 859.065 0.000 859.205 0.560 ;
    END
  END ifu_iu_pcfifo_create1_cur_pc[30]
  PIN ifu_iu_pcfifo_create1_cur_pc[31]
    DIRECTION OUTPUT ;
    USE SIGNAL ;
    PORT
      LAYER metal4 ;
        RECT 859.065 0.000 859.205 0.560 ;
    END
  END ifu_iu_pcfifo_create1_cur_pc[31]
  PIN ifu_iu_pcfifo_create1_cur_pc[32]
    DIRECTION OUTPUT ;
    USE SIGNAL ;
    PORT
      LAYER metal6 ;
        RECT 857.945 0.000 858.085 0.560 ;
    END
  END ifu_iu_pcfifo_create1_cur_pc[32]
  PIN ifu_iu_pcfifo_create1_cur_pc[33]
    DIRECTION OUTPUT ;
    USE SIGNAL ;
    PORT
      LAYER metal4 ;
        RECT 857.945 0.000 858.085 0.560 ;
    END
  END ifu_iu_pcfifo_create1_cur_pc[33]
  PIN ifu_iu_pcfifo_create1_cur_pc[34]
    DIRECTION OUTPUT ;
    USE SIGNAL ;
    PORT
      LAYER metal6 ;
        RECT 856.825 0.000 856.965 0.560 ;
    END
  END ifu_iu_pcfifo_create1_cur_pc[34]
  PIN ifu_iu_pcfifo_create1_cur_pc[35]
    DIRECTION OUTPUT ;
    USE SIGNAL ;
    PORT
      LAYER metal4 ;
        RECT 856.825 0.000 856.965 0.560 ;
    END
  END ifu_iu_pcfifo_create1_cur_pc[35]
  PIN ifu_iu_pcfifo_create1_cur_pc[36]
    DIRECTION OUTPUT ;
    USE SIGNAL ;
    PORT
      LAYER metal6 ;
        RECT 855.705 0.000 855.845 0.560 ;
    END
  END ifu_iu_pcfifo_create1_cur_pc[36]
  PIN ifu_iu_pcfifo_create1_cur_pc[37]
    DIRECTION OUTPUT ;
    USE SIGNAL ;
    PORT
      LAYER metal4 ;
        RECT 855.705 0.000 855.845 0.560 ;
    END
  END ifu_iu_pcfifo_create1_cur_pc[37]
  PIN ifu_iu_pcfifo_create1_cur_pc[38]
    DIRECTION OUTPUT ;
    USE SIGNAL ;
    PORT
      LAYER metal6 ;
        RECT 854.585 0.000 854.725 0.560 ;
    END
  END ifu_iu_pcfifo_create1_cur_pc[38]
  PIN ifu_iu_pcfifo_create1_cur_pc[39]
    DIRECTION OUTPUT ;
    USE SIGNAL ;
    PORT
      LAYER metal4 ;
        RECT 854.585 0.000 854.725 0.560 ;
    END
  END ifu_iu_pcfifo_create1_cur_pc[39]
  PIN ifu_iu_pcfifo_create1_cur_pc[3]
    DIRECTION OUTPUT ;
    USE SIGNAL ;
    PORT
      LAYER metal4 ;
        RECT 874.745 0.000 874.885 0.560 ;
    END
  END ifu_iu_pcfifo_create1_cur_pc[3]
  PIN ifu_iu_pcfifo_create1_cur_pc[4]
    DIRECTION OUTPUT ;
    USE SIGNAL ;
    PORT
      LAYER metal6 ;
        RECT 873.625 0.000 873.765 0.560 ;
    END
  END ifu_iu_pcfifo_create1_cur_pc[4]
  PIN ifu_iu_pcfifo_create1_cur_pc[5]
    DIRECTION OUTPUT ;
    USE SIGNAL ;
    PORT
      LAYER metal4 ;
        RECT 873.625 0.000 873.765 0.560 ;
    END
  END ifu_iu_pcfifo_create1_cur_pc[5]
  PIN ifu_iu_pcfifo_create1_cur_pc[6]
    DIRECTION OUTPUT ;
    USE SIGNAL ;
    PORT
      LAYER metal6 ;
        RECT 872.505 0.000 872.645 0.560 ;
    END
  END ifu_iu_pcfifo_create1_cur_pc[6]
  PIN ifu_iu_pcfifo_create1_cur_pc[7]
    DIRECTION OUTPUT ;
    USE SIGNAL ;
    PORT
      LAYER metal4 ;
        RECT 872.505 0.000 872.645 0.560 ;
    END
  END ifu_iu_pcfifo_create1_cur_pc[7]
  PIN ifu_iu_pcfifo_create1_cur_pc[8]
    DIRECTION OUTPUT ;
    USE SIGNAL ;
    PORT
      LAYER metal6 ;
        RECT 871.385 0.000 871.525 0.560 ;
    END
  END ifu_iu_pcfifo_create1_cur_pc[8]
  PIN ifu_iu_pcfifo_create1_cur_pc[9]
    DIRECTION OUTPUT ;
    USE SIGNAL ;
    PORT
      LAYER metal4 ;
        RECT 871.385 0.000 871.525 0.560 ;
    END
  END ifu_iu_pcfifo_create1_cur_pc[9]
  PIN ifu_iu_pcfifo_create1_dst_vld
    DIRECTION OUTPUT ;
    USE SIGNAL ;
    PORT
      LAYER metal4 ;
        RECT 876.985 0.000 877.125 0.560 ;
    END
  END ifu_iu_pcfifo_create1_dst_vld
  PIN ifu_iu_pcfifo_create1_en
    DIRECTION OUTPUT ;
    USE SIGNAL ;
    PORT
      LAYER metal6 ;
        RECT 876.985 0.000 877.125 0.560 ;
    END
  END ifu_iu_pcfifo_create1_en
  PIN ifu_iu_pcfifo_create1_gateclk_en
    DIRECTION OUTPUT ;
    USE SIGNAL ;
    PORT
      LAYER metal4 ;
        RECT 878.105 0.000 878.245 0.560 ;
    END
  END ifu_iu_pcfifo_create1_gateclk_en
  PIN ifu_iu_pcfifo_create1_jal
    DIRECTION OUTPUT ;
    USE SIGNAL ;
    PORT
      LAYER metal6 ;
        RECT 878.105 0.000 878.245 0.560 ;
    END
  END ifu_iu_pcfifo_create1_jal
  PIN ifu_iu_pcfifo_create1_jalr
    DIRECTION OUTPUT ;
    USE SIGNAL ;
    PORT
      LAYER metal4 ;
        RECT 879.225 0.000 879.365 0.560 ;
    END
  END ifu_iu_pcfifo_create1_jalr
  PIN ifu_iu_pcfifo_create1_jmp_mispred
    DIRECTION OUTPUT ;
    USE SIGNAL ;
    PORT
      LAYER metal6 ;
        RECT 879.225 0.000 879.365 0.560 ;
    END
  END ifu_iu_pcfifo_create1_jmp_mispred
  PIN ifu_iu_pcfifo_create1_tar_pc[0]
    DIRECTION OUTPUT ;
    USE SIGNAL ;
    PORT
      LAYER metal6 ;
        RECT 901.625 0.000 901.765 0.560 ;
    END
  END ifu_iu_pcfifo_create1_tar_pc[0]
  PIN ifu_iu_pcfifo_create1_tar_pc[10]
    DIRECTION OUTPUT ;
    USE SIGNAL ;
    PORT
      LAYER metal6 ;
        RECT 896.025 0.000 896.165 0.560 ;
    END
  END ifu_iu_pcfifo_create1_tar_pc[10]
  PIN ifu_iu_pcfifo_create1_tar_pc[11]
    DIRECTION OUTPUT ;
    USE SIGNAL ;
    PORT
      LAYER metal4 ;
        RECT 896.025 0.000 896.165 0.560 ;
    END
  END ifu_iu_pcfifo_create1_tar_pc[11]
  PIN ifu_iu_pcfifo_create1_tar_pc[12]
    DIRECTION OUTPUT ;
    USE SIGNAL ;
    PORT
      LAYER metal6 ;
        RECT 894.905 0.000 895.045 0.560 ;
    END
  END ifu_iu_pcfifo_create1_tar_pc[12]
  PIN ifu_iu_pcfifo_create1_tar_pc[13]
    DIRECTION OUTPUT ;
    USE SIGNAL ;
    PORT
      LAYER metal4 ;
        RECT 894.905 0.000 895.045 0.560 ;
    END
  END ifu_iu_pcfifo_create1_tar_pc[13]
  PIN ifu_iu_pcfifo_create1_tar_pc[14]
    DIRECTION OUTPUT ;
    USE SIGNAL ;
    PORT
      LAYER metal6 ;
        RECT 893.785 0.000 893.925 0.560 ;
    END
  END ifu_iu_pcfifo_create1_tar_pc[14]
  PIN ifu_iu_pcfifo_create1_tar_pc[15]
    DIRECTION OUTPUT ;
    USE SIGNAL ;
    PORT
      LAYER metal4 ;
        RECT 893.785 0.000 893.925 0.560 ;
    END
  END ifu_iu_pcfifo_create1_tar_pc[15]
  PIN ifu_iu_pcfifo_create1_tar_pc[16]
    DIRECTION OUTPUT ;
    USE SIGNAL ;
    PORT
      LAYER metal6 ;
        RECT 892.665 0.000 892.805 0.560 ;
    END
  END ifu_iu_pcfifo_create1_tar_pc[16]
  PIN ifu_iu_pcfifo_create1_tar_pc[17]
    DIRECTION OUTPUT ;
    USE SIGNAL ;
    PORT
      LAYER metal4 ;
        RECT 892.665 0.000 892.805 0.560 ;
    END
  END ifu_iu_pcfifo_create1_tar_pc[17]
  PIN ifu_iu_pcfifo_create1_tar_pc[18]
    DIRECTION OUTPUT ;
    USE SIGNAL ;
    PORT
      LAYER metal6 ;
        RECT 891.545 0.000 891.685 0.560 ;
    END
  END ifu_iu_pcfifo_create1_tar_pc[18]
  PIN ifu_iu_pcfifo_create1_tar_pc[19]
    DIRECTION OUTPUT ;
    USE SIGNAL ;
    PORT
      LAYER metal4 ;
        RECT 891.545 0.000 891.685 0.560 ;
    END
  END ifu_iu_pcfifo_create1_tar_pc[19]
  PIN ifu_iu_pcfifo_create1_tar_pc[1]
    DIRECTION OUTPUT ;
    USE SIGNAL ;
    PORT
      LAYER metal4 ;
        RECT 901.625 0.000 901.765 0.560 ;
    END
  END ifu_iu_pcfifo_create1_tar_pc[1]
  PIN ifu_iu_pcfifo_create1_tar_pc[20]
    DIRECTION OUTPUT ;
    USE SIGNAL ;
    PORT
      LAYER metal6 ;
        RECT 890.425 0.000 890.565 0.560 ;
    END
  END ifu_iu_pcfifo_create1_tar_pc[20]
  PIN ifu_iu_pcfifo_create1_tar_pc[21]
    DIRECTION OUTPUT ;
    USE SIGNAL ;
    PORT
      LAYER metal4 ;
        RECT 890.425 0.000 890.565 0.560 ;
    END
  END ifu_iu_pcfifo_create1_tar_pc[21]
  PIN ifu_iu_pcfifo_create1_tar_pc[22]
    DIRECTION OUTPUT ;
    USE SIGNAL ;
    PORT
      LAYER metal6 ;
        RECT 889.305 0.000 889.445 0.560 ;
    END
  END ifu_iu_pcfifo_create1_tar_pc[22]
  PIN ifu_iu_pcfifo_create1_tar_pc[23]
    DIRECTION OUTPUT ;
    USE SIGNAL ;
    PORT
      LAYER metal4 ;
        RECT 889.305 0.000 889.445 0.560 ;
    END
  END ifu_iu_pcfifo_create1_tar_pc[23]
  PIN ifu_iu_pcfifo_create1_tar_pc[24]
    DIRECTION OUTPUT ;
    USE SIGNAL ;
    PORT
      LAYER metal6 ;
        RECT 888.185 0.000 888.325 0.560 ;
    END
  END ifu_iu_pcfifo_create1_tar_pc[24]
  PIN ifu_iu_pcfifo_create1_tar_pc[25]
    DIRECTION OUTPUT ;
    USE SIGNAL ;
    PORT
      LAYER metal4 ;
        RECT 888.185 0.000 888.325 0.560 ;
    END
  END ifu_iu_pcfifo_create1_tar_pc[25]
  PIN ifu_iu_pcfifo_create1_tar_pc[26]
    DIRECTION OUTPUT ;
    USE SIGNAL ;
    PORT
      LAYER metal6 ;
        RECT 887.065 0.000 887.205 0.560 ;
    END
  END ifu_iu_pcfifo_create1_tar_pc[26]
  PIN ifu_iu_pcfifo_create1_tar_pc[27]
    DIRECTION OUTPUT ;
    USE SIGNAL ;
    PORT
      LAYER metal4 ;
        RECT 887.065 0.000 887.205 0.560 ;
    END
  END ifu_iu_pcfifo_create1_tar_pc[27]
  PIN ifu_iu_pcfifo_create1_tar_pc[28]
    DIRECTION OUTPUT ;
    USE SIGNAL ;
    PORT
      LAYER metal6 ;
        RECT 885.945 0.000 886.085 0.560 ;
    END
  END ifu_iu_pcfifo_create1_tar_pc[28]
  PIN ifu_iu_pcfifo_create1_tar_pc[29]
    DIRECTION OUTPUT ;
    USE SIGNAL ;
    PORT
      LAYER metal4 ;
        RECT 885.945 0.000 886.085 0.560 ;
    END
  END ifu_iu_pcfifo_create1_tar_pc[29]
  PIN ifu_iu_pcfifo_create1_tar_pc[2]
    DIRECTION OUTPUT ;
    USE SIGNAL ;
    PORT
      LAYER metal6 ;
        RECT 900.505 0.000 900.645 0.560 ;
    END
  END ifu_iu_pcfifo_create1_tar_pc[2]
  PIN ifu_iu_pcfifo_create1_tar_pc[30]
    DIRECTION OUTPUT ;
    USE SIGNAL ;
    PORT
      LAYER metal6 ;
        RECT 884.825 0.000 884.965 0.560 ;
    END
  END ifu_iu_pcfifo_create1_tar_pc[30]
  PIN ifu_iu_pcfifo_create1_tar_pc[31]
    DIRECTION OUTPUT ;
    USE SIGNAL ;
    PORT
      LAYER metal4 ;
        RECT 884.825 0.000 884.965 0.560 ;
    END
  END ifu_iu_pcfifo_create1_tar_pc[31]
  PIN ifu_iu_pcfifo_create1_tar_pc[32]
    DIRECTION OUTPUT ;
    USE SIGNAL ;
    PORT
      LAYER metal6 ;
        RECT 883.705 0.000 883.845 0.560 ;
    END
  END ifu_iu_pcfifo_create1_tar_pc[32]
  PIN ifu_iu_pcfifo_create1_tar_pc[33]
    DIRECTION OUTPUT ;
    USE SIGNAL ;
    PORT
      LAYER metal4 ;
        RECT 883.705 0.000 883.845 0.560 ;
    END
  END ifu_iu_pcfifo_create1_tar_pc[33]
  PIN ifu_iu_pcfifo_create1_tar_pc[34]
    DIRECTION OUTPUT ;
    USE SIGNAL ;
    PORT
      LAYER metal6 ;
        RECT 882.585 0.000 882.725 0.560 ;
    END
  END ifu_iu_pcfifo_create1_tar_pc[34]
  PIN ifu_iu_pcfifo_create1_tar_pc[35]
    DIRECTION OUTPUT ;
    USE SIGNAL ;
    PORT
      LAYER metal4 ;
        RECT 882.585 0.000 882.725 0.560 ;
    END
  END ifu_iu_pcfifo_create1_tar_pc[35]
  PIN ifu_iu_pcfifo_create1_tar_pc[36]
    DIRECTION OUTPUT ;
    USE SIGNAL ;
    PORT
      LAYER metal6 ;
        RECT 881.465 0.000 881.605 0.560 ;
    END
  END ifu_iu_pcfifo_create1_tar_pc[36]
  PIN ifu_iu_pcfifo_create1_tar_pc[37]
    DIRECTION OUTPUT ;
    USE SIGNAL ;
    PORT
      LAYER metal4 ;
        RECT 881.465 0.000 881.605 0.560 ;
    END
  END ifu_iu_pcfifo_create1_tar_pc[37]
  PIN ifu_iu_pcfifo_create1_tar_pc[38]
    DIRECTION OUTPUT ;
    USE SIGNAL ;
    PORT
      LAYER metal6 ;
        RECT 880.345 0.000 880.485 0.560 ;
    END
  END ifu_iu_pcfifo_create1_tar_pc[38]
  PIN ifu_iu_pcfifo_create1_tar_pc[39]
    DIRECTION OUTPUT ;
    USE SIGNAL ;
    PORT
      LAYER metal4 ;
        RECT 880.345 0.000 880.485 0.560 ;
    END
  END ifu_iu_pcfifo_create1_tar_pc[39]
  PIN ifu_iu_pcfifo_create1_tar_pc[3]
    DIRECTION OUTPUT ;
    USE SIGNAL ;
    PORT
      LAYER metal4 ;
        RECT 900.505 0.000 900.645 0.560 ;
    END
  END ifu_iu_pcfifo_create1_tar_pc[3]
  PIN ifu_iu_pcfifo_create1_tar_pc[4]
    DIRECTION OUTPUT ;
    USE SIGNAL ;
    PORT
      LAYER metal6 ;
        RECT 899.385 0.000 899.525 0.560 ;
    END
  END ifu_iu_pcfifo_create1_tar_pc[4]
  PIN ifu_iu_pcfifo_create1_tar_pc[5]
    DIRECTION OUTPUT ;
    USE SIGNAL ;
    PORT
      LAYER metal4 ;
        RECT 899.385 0.000 899.525 0.560 ;
    END
  END ifu_iu_pcfifo_create1_tar_pc[5]
  PIN ifu_iu_pcfifo_create1_tar_pc[6]
    DIRECTION OUTPUT ;
    USE SIGNAL ;
    PORT
      LAYER metal6 ;
        RECT 898.265 0.000 898.405 0.560 ;
    END
  END ifu_iu_pcfifo_create1_tar_pc[6]
  PIN ifu_iu_pcfifo_create1_tar_pc[7]
    DIRECTION OUTPUT ;
    USE SIGNAL ;
    PORT
      LAYER metal4 ;
        RECT 898.265 0.000 898.405 0.560 ;
    END
  END ifu_iu_pcfifo_create1_tar_pc[7]
  PIN ifu_iu_pcfifo_create1_tar_pc[8]
    DIRECTION OUTPUT ;
    USE SIGNAL ;
    PORT
      LAYER metal6 ;
        RECT 897.145 0.000 897.285 0.560 ;
    END
  END ifu_iu_pcfifo_create1_tar_pc[8]
  PIN ifu_iu_pcfifo_create1_tar_pc[9]
    DIRECTION OUTPUT ;
    USE SIGNAL ;
    PORT
      LAYER metal4 ;
        RECT 897.145 0.000 897.285 0.560 ;
    END
  END ifu_iu_pcfifo_create1_tar_pc[9]
  PIN ifu_lsu_icache_inv_done
    DIRECTION OUTPUT ;
    USE SIGNAL ;
    PORT
      LAYER metal4 ;
        RECT 902.745 0.000 902.885 0.560 ;
    END
  END ifu_lsu_icache_inv_done
  PIN ifu_mmu_abort
    DIRECTION OUTPUT ;
    USE SIGNAL ;
    PORT
      LAYER metal6 ;
        RECT 902.745 0.000 902.885 0.560 ;
    END
  END ifu_mmu_abort
  PIN ifu_mmu_va[0]
    DIRECTION OUTPUT ;
    USE SIGNAL ;
    PORT
      LAYER metal4 ;
        RECT 938.585 0.000 938.725 0.560 ;
    END
  END ifu_mmu_va[0]
  PIN ifu_mmu_va[10]
    DIRECTION OUTPUT ;
    USE SIGNAL ;
    PORT
      LAYER metal4 ;
        RECT 932.985 0.000 933.125 0.560 ;
    END
  END ifu_mmu_va[10]
  PIN ifu_mmu_va[11]
    DIRECTION OUTPUT ;
    USE SIGNAL ;
    PORT
      LAYER metal6 ;
        RECT 931.865 0.000 932.005 0.560 ;
    END
  END ifu_mmu_va[11]
  PIN ifu_mmu_va[12]
    DIRECTION OUTPUT ;
    USE SIGNAL ;
    PORT
      LAYER metal4 ;
        RECT 931.865 0.000 932.005 0.560 ;
    END
  END ifu_mmu_va[12]
  PIN ifu_mmu_va[13]
    DIRECTION OUTPUT ;
    USE SIGNAL ;
    PORT
      LAYER metal6 ;
        RECT 930.745 0.000 930.885 0.560 ;
    END
  END ifu_mmu_va[13]
  PIN ifu_mmu_va[14]
    DIRECTION OUTPUT ;
    USE SIGNAL ;
    PORT
      LAYER metal4 ;
        RECT 930.745 0.000 930.885 0.560 ;
    END
  END ifu_mmu_va[14]
  PIN ifu_mmu_va[15]
    DIRECTION OUTPUT ;
    USE SIGNAL ;
    PORT
      LAYER metal6 ;
        RECT 929.625 0.000 929.765 0.560 ;
    END
  END ifu_mmu_va[15]
  PIN ifu_mmu_va[16]
    DIRECTION OUTPUT ;
    USE SIGNAL ;
    PORT
      LAYER metal4 ;
        RECT 929.625 0.000 929.765 0.560 ;
    END
  END ifu_mmu_va[16]
  PIN ifu_mmu_va[17]
    DIRECTION OUTPUT ;
    USE SIGNAL ;
    PORT
      LAYER metal6 ;
        RECT 928.505 0.000 928.645 0.560 ;
    END
  END ifu_mmu_va[17]
  PIN ifu_mmu_va[18]
    DIRECTION OUTPUT ;
    USE SIGNAL ;
    PORT
      LAYER metal4 ;
        RECT 928.505 0.000 928.645 0.560 ;
    END
  END ifu_mmu_va[18]
  PIN ifu_mmu_va[19]
    DIRECTION OUTPUT ;
    USE SIGNAL ;
    PORT
      LAYER metal6 ;
        RECT 927.385 0.000 927.525 0.560 ;
    END
  END ifu_mmu_va[19]
  PIN ifu_mmu_va[1]
    DIRECTION OUTPUT ;
    USE SIGNAL ;
    PORT
      LAYER metal6 ;
        RECT 937.465 0.000 937.605 0.560 ;
    END
  END ifu_mmu_va[1]
  PIN ifu_mmu_va[20]
    DIRECTION OUTPUT ;
    USE SIGNAL ;
    PORT
      LAYER metal4 ;
        RECT 927.385 0.000 927.525 0.560 ;
    END
  END ifu_mmu_va[20]
  PIN ifu_mmu_va[21]
    DIRECTION OUTPUT ;
    USE SIGNAL ;
    PORT
      LAYER metal6 ;
        RECT 926.265 0.000 926.405 0.560 ;
    END
  END ifu_mmu_va[21]
  PIN ifu_mmu_va[22]
    DIRECTION OUTPUT ;
    USE SIGNAL ;
    PORT
      LAYER metal4 ;
        RECT 926.265 0.000 926.405 0.560 ;
    END
  END ifu_mmu_va[22]
  PIN ifu_mmu_va[23]
    DIRECTION OUTPUT ;
    USE SIGNAL ;
    PORT
      LAYER metal6 ;
        RECT 925.145 0.000 925.285 0.560 ;
    END
  END ifu_mmu_va[23]
  PIN ifu_mmu_va[24]
    DIRECTION OUTPUT ;
    USE SIGNAL ;
    PORT
      LAYER metal4 ;
        RECT 925.145 0.000 925.285 0.560 ;
    END
  END ifu_mmu_va[24]
  PIN ifu_mmu_va[25]
    DIRECTION OUTPUT ;
    USE SIGNAL ;
    PORT
      LAYER metal6 ;
        RECT 924.025 0.000 924.165 0.560 ;
    END
  END ifu_mmu_va[25]
  PIN ifu_mmu_va[26]
    DIRECTION OUTPUT ;
    USE SIGNAL ;
    PORT
      LAYER metal4 ;
        RECT 924.025 0.000 924.165 0.560 ;
    END
  END ifu_mmu_va[26]
  PIN ifu_mmu_va[27]
    DIRECTION OUTPUT ;
    USE SIGNAL ;
    PORT
      LAYER metal6 ;
        RECT 922.905 0.000 923.045 0.560 ;
    END
  END ifu_mmu_va[27]
  PIN ifu_mmu_va[28]
    DIRECTION OUTPUT ;
    USE SIGNAL ;
    PORT
      LAYER metal4 ;
        RECT 922.905 0.000 923.045 0.560 ;
    END
  END ifu_mmu_va[28]
  PIN ifu_mmu_va[29]
    DIRECTION OUTPUT ;
    USE SIGNAL ;
    PORT
      LAYER metal6 ;
        RECT 921.785 0.000 921.925 0.560 ;
    END
  END ifu_mmu_va[29]
  PIN ifu_mmu_va[2]
    DIRECTION OUTPUT ;
    USE SIGNAL ;
    PORT
      LAYER metal4 ;
        RECT 937.465 0.000 937.605 0.560 ;
    END
  END ifu_mmu_va[2]
  PIN ifu_mmu_va[30]
    DIRECTION OUTPUT ;
    USE SIGNAL ;
    PORT
      LAYER metal4 ;
        RECT 921.785 0.000 921.925 0.560 ;
    END
  END ifu_mmu_va[30]
  PIN ifu_mmu_va[31]
    DIRECTION OUTPUT ;
    USE SIGNAL ;
    PORT
      LAYER metal6 ;
        RECT 920.665 0.000 920.805 0.560 ;
    END
  END ifu_mmu_va[31]
  PIN ifu_mmu_va[32]
    DIRECTION OUTPUT ;
    USE SIGNAL ;
    PORT
      LAYER metal4 ;
        RECT 920.665 0.000 920.805 0.560 ;
    END
  END ifu_mmu_va[32]
  PIN ifu_mmu_va[33]
    DIRECTION OUTPUT ;
    USE SIGNAL ;
    PORT
      LAYER metal6 ;
        RECT 919.545 0.000 919.685 0.560 ;
    END
  END ifu_mmu_va[33]
  PIN ifu_mmu_va[34]
    DIRECTION OUTPUT ;
    USE SIGNAL ;
    PORT
      LAYER metal4 ;
        RECT 919.545 0.000 919.685 0.560 ;
    END
  END ifu_mmu_va[34]
  PIN ifu_mmu_va[35]
    DIRECTION OUTPUT ;
    USE SIGNAL ;
    PORT
      LAYER metal6 ;
        RECT 918.425 0.000 918.565 0.560 ;
    END
  END ifu_mmu_va[35]
  PIN ifu_mmu_va[36]
    DIRECTION OUTPUT ;
    USE SIGNAL ;
    PORT
      LAYER metal4 ;
        RECT 918.425 0.000 918.565 0.560 ;
    END
  END ifu_mmu_va[36]
  PIN ifu_mmu_va[37]
    DIRECTION OUTPUT ;
    USE SIGNAL ;
    PORT
      LAYER metal6 ;
        RECT 917.305 0.000 917.445 0.560 ;
    END
  END ifu_mmu_va[37]
  PIN ifu_mmu_va[38]
    DIRECTION OUTPUT ;
    USE SIGNAL ;
    PORT
      LAYER metal4 ;
        RECT 917.305 0.000 917.445 0.560 ;
    END
  END ifu_mmu_va[38]
  PIN ifu_mmu_va[39]
    DIRECTION OUTPUT ;
    USE SIGNAL ;
    PORT
      LAYER metal6 ;
        RECT 916.185 0.000 916.325 0.560 ;
    END
  END ifu_mmu_va[39]
  PIN ifu_mmu_va[3]
    DIRECTION OUTPUT ;
    USE SIGNAL ;
    PORT
      LAYER metal6 ;
        RECT 936.345 0.000 936.485 0.560 ;
    END
  END ifu_mmu_va[3]
  PIN ifu_mmu_va[40]
    DIRECTION OUTPUT ;
    USE SIGNAL ;
    PORT
      LAYER metal4 ;
        RECT 916.185 0.000 916.325 0.560 ;
    END
  END ifu_mmu_va[40]
  PIN ifu_mmu_va[41]
    DIRECTION OUTPUT ;
    USE SIGNAL ;
    PORT
      LAYER metal6 ;
        RECT 915.065 0.000 915.205 0.560 ;
    END
  END ifu_mmu_va[41]
  PIN ifu_mmu_va[42]
    DIRECTION OUTPUT ;
    USE SIGNAL ;
    PORT
      LAYER metal4 ;
        RECT 915.065 0.000 915.205 0.560 ;
    END
  END ifu_mmu_va[42]
  PIN ifu_mmu_va[43]
    DIRECTION OUTPUT ;
    USE SIGNAL ;
    PORT
      LAYER metal6 ;
        RECT 913.945 0.000 914.085 0.560 ;
    END
  END ifu_mmu_va[43]
  PIN ifu_mmu_va[44]
    DIRECTION OUTPUT ;
    USE SIGNAL ;
    PORT
      LAYER metal4 ;
        RECT 913.945 0.000 914.085 0.560 ;
    END
  END ifu_mmu_va[44]
  PIN ifu_mmu_va[45]
    DIRECTION OUTPUT ;
    USE SIGNAL ;
    PORT
      LAYER metal6 ;
        RECT 912.825 0.000 912.965 0.560 ;
    END
  END ifu_mmu_va[45]
  PIN ifu_mmu_va[46]
    DIRECTION OUTPUT ;
    USE SIGNAL ;
    PORT
      LAYER metal4 ;
        RECT 912.825 0.000 912.965 0.560 ;
    END
  END ifu_mmu_va[46]
  PIN ifu_mmu_va[47]
    DIRECTION OUTPUT ;
    USE SIGNAL ;
    PORT
      LAYER metal6 ;
        RECT 911.705 0.000 911.845 0.560 ;
    END
  END ifu_mmu_va[47]
  PIN ifu_mmu_va[48]
    DIRECTION OUTPUT ;
    USE SIGNAL ;
    PORT
      LAYER metal4 ;
        RECT 911.705 0.000 911.845 0.560 ;
    END
  END ifu_mmu_va[48]
  PIN ifu_mmu_va[49]
    DIRECTION OUTPUT ;
    USE SIGNAL ;
    PORT
      LAYER metal6 ;
        RECT 910.585 0.000 910.725 0.560 ;
    END
  END ifu_mmu_va[49]
  PIN ifu_mmu_va[4]
    DIRECTION OUTPUT ;
    USE SIGNAL ;
    PORT
      LAYER metal4 ;
        RECT 936.345 0.000 936.485 0.560 ;
    END
  END ifu_mmu_va[4]
  PIN ifu_mmu_va[50]
    DIRECTION OUTPUT ;
    USE SIGNAL ;
    PORT
      LAYER metal4 ;
        RECT 910.585 0.000 910.725 0.560 ;
    END
  END ifu_mmu_va[50]
  PIN ifu_mmu_va[51]
    DIRECTION OUTPUT ;
    USE SIGNAL ;
    PORT
      LAYER metal6 ;
        RECT 909.465 0.000 909.605 0.560 ;
    END
  END ifu_mmu_va[51]
  PIN ifu_mmu_va[52]
    DIRECTION OUTPUT ;
    USE SIGNAL ;
    PORT
      LAYER metal4 ;
        RECT 909.465 0.000 909.605 0.560 ;
    END
  END ifu_mmu_va[52]
  PIN ifu_mmu_va[53]
    DIRECTION OUTPUT ;
    USE SIGNAL ;
    PORT
      LAYER metal6 ;
        RECT 908.345 0.000 908.485 0.560 ;
    END
  END ifu_mmu_va[53]
  PIN ifu_mmu_va[54]
    DIRECTION OUTPUT ;
    USE SIGNAL ;
    PORT
      LAYER metal4 ;
        RECT 908.345 0.000 908.485 0.560 ;
    END
  END ifu_mmu_va[54]
  PIN ifu_mmu_va[55]
    DIRECTION OUTPUT ;
    USE SIGNAL ;
    PORT
      LAYER metal6 ;
        RECT 907.225 0.000 907.365 0.560 ;
    END
  END ifu_mmu_va[55]
  PIN ifu_mmu_va[56]
    DIRECTION OUTPUT ;
    USE SIGNAL ;
    PORT
      LAYER metal4 ;
        RECT 907.225 0.000 907.365 0.560 ;
    END
  END ifu_mmu_va[56]
  PIN ifu_mmu_va[57]
    DIRECTION OUTPUT ;
    USE SIGNAL ;
    PORT
      LAYER metal6 ;
        RECT 906.105 0.000 906.245 0.560 ;
    END
  END ifu_mmu_va[57]
  PIN ifu_mmu_va[58]
    DIRECTION OUTPUT ;
    USE SIGNAL ;
    PORT
      LAYER metal4 ;
        RECT 906.105 0.000 906.245 0.560 ;
    END
  END ifu_mmu_va[58]
  PIN ifu_mmu_va[59]
    DIRECTION OUTPUT ;
    USE SIGNAL ;
    PORT
      LAYER metal6 ;
        RECT 904.985 0.000 905.125 0.560 ;
    END
  END ifu_mmu_va[59]
  PIN ifu_mmu_va[5]
    DIRECTION OUTPUT ;
    USE SIGNAL ;
    PORT
      LAYER metal6 ;
        RECT 935.225 0.000 935.365 0.560 ;
    END
  END ifu_mmu_va[5]
  PIN ifu_mmu_va[60]
    DIRECTION OUTPUT ;
    USE SIGNAL ;
    PORT
      LAYER metal4 ;
        RECT 904.985 0.000 905.125 0.560 ;
    END
  END ifu_mmu_va[60]
  PIN ifu_mmu_va[61]
    DIRECTION OUTPUT ;
    USE SIGNAL ;
    PORT
      LAYER metal6 ;
        RECT 903.865 0.000 904.005 0.560 ;
    END
  END ifu_mmu_va[61]
  PIN ifu_mmu_va[62]
    DIRECTION OUTPUT ;
    USE SIGNAL ;
    PORT
      LAYER metal4 ;
        RECT 903.865 0.000 904.005 0.560 ;
    END
  END ifu_mmu_va[62]
  PIN ifu_mmu_va[6]
    DIRECTION OUTPUT ;
    USE SIGNAL ;
    PORT
      LAYER metal4 ;
        RECT 935.225 0.000 935.365 0.560 ;
    END
  END ifu_mmu_va[6]
  PIN ifu_mmu_va[7]
    DIRECTION OUTPUT ;
    USE SIGNAL ;
    PORT
      LAYER metal6 ;
        RECT 934.105 0.000 934.245 0.560 ;
    END
  END ifu_mmu_va[7]
  PIN ifu_mmu_va[8]
    DIRECTION OUTPUT ;
    USE SIGNAL ;
    PORT
      LAYER metal4 ;
        RECT 934.105 0.000 934.245 0.560 ;
    END
  END ifu_mmu_va[8]
  PIN ifu_mmu_va[9]
    DIRECTION OUTPUT ;
    USE SIGNAL ;
    PORT
      LAYER metal6 ;
        RECT 932.985 0.000 933.125 0.560 ;
    END
  END ifu_mmu_va[9]
  PIN ifu_mmu_va_vld
    DIRECTION OUTPUT ;
    USE SIGNAL ;
    PORT
      LAYER metal6 ;
        RECT 938.585 0.000 938.725 0.560 ;
    END
  END ifu_mmu_va_vld
  PIN ifu_rtu_cur_pc[0]
    DIRECTION OUTPUT ;
    USE SIGNAL ;
    PORT
      LAYER metal4 ;
        RECT 960.985 0.000 961.125 0.560 ;
    END
  END ifu_rtu_cur_pc[0]
  PIN ifu_rtu_cur_pc[10]
    DIRECTION OUTPUT ;
    USE SIGNAL ;
    PORT
      LAYER metal4 ;
        RECT 955.385 0.000 955.525 0.560 ;
    END
  END ifu_rtu_cur_pc[10]
  PIN ifu_rtu_cur_pc[11]
    DIRECTION OUTPUT ;
    USE SIGNAL ;
    PORT
      LAYER metal6 ;
        RECT 954.265 0.000 954.405 0.560 ;
    END
  END ifu_rtu_cur_pc[11]
  PIN ifu_rtu_cur_pc[12]
    DIRECTION OUTPUT ;
    USE SIGNAL ;
    PORT
      LAYER metal4 ;
        RECT 954.265 0.000 954.405 0.560 ;
    END
  END ifu_rtu_cur_pc[12]
  PIN ifu_rtu_cur_pc[13]
    DIRECTION OUTPUT ;
    USE SIGNAL ;
    PORT
      LAYER metal6 ;
        RECT 953.145 0.000 953.285 0.560 ;
    END
  END ifu_rtu_cur_pc[13]
  PIN ifu_rtu_cur_pc[14]
    DIRECTION OUTPUT ;
    USE SIGNAL ;
    PORT
      LAYER metal4 ;
        RECT 953.145 0.000 953.285 0.560 ;
    END
  END ifu_rtu_cur_pc[14]
  PIN ifu_rtu_cur_pc[15]
    DIRECTION OUTPUT ;
    USE SIGNAL ;
    PORT
      LAYER metal6 ;
        RECT 952.025 0.000 952.165 0.560 ;
    END
  END ifu_rtu_cur_pc[15]
  PIN ifu_rtu_cur_pc[16]
    DIRECTION OUTPUT ;
    USE SIGNAL ;
    PORT
      LAYER metal4 ;
        RECT 952.025 0.000 952.165 0.560 ;
    END
  END ifu_rtu_cur_pc[16]
  PIN ifu_rtu_cur_pc[17]
    DIRECTION OUTPUT ;
    USE SIGNAL ;
    PORT
      LAYER metal6 ;
        RECT 950.905 0.000 951.045 0.560 ;
    END
  END ifu_rtu_cur_pc[17]
  PIN ifu_rtu_cur_pc[18]
    DIRECTION OUTPUT ;
    USE SIGNAL ;
    PORT
      LAYER metal4 ;
        RECT 950.905 0.000 951.045 0.560 ;
    END
  END ifu_rtu_cur_pc[18]
  PIN ifu_rtu_cur_pc[19]
    DIRECTION OUTPUT ;
    USE SIGNAL ;
    PORT
      LAYER metal6 ;
        RECT 949.785 0.000 949.925 0.560 ;
    END
  END ifu_rtu_cur_pc[19]
  PIN ifu_rtu_cur_pc[1]
    DIRECTION OUTPUT ;
    USE SIGNAL ;
    PORT
      LAYER metal6 ;
        RECT 959.865 0.000 960.005 0.560 ;
    END
  END ifu_rtu_cur_pc[1]
  PIN ifu_rtu_cur_pc[20]
    DIRECTION OUTPUT ;
    USE SIGNAL ;
    PORT
      LAYER metal4 ;
        RECT 949.785 0.000 949.925 0.560 ;
    END
  END ifu_rtu_cur_pc[20]
  PIN ifu_rtu_cur_pc[21]
    DIRECTION OUTPUT ;
    USE SIGNAL ;
    PORT
      LAYER metal6 ;
        RECT 948.665 0.000 948.805 0.560 ;
    END
  END ifu_rtu_cur_pc[21]
  PIN ifu_rtu_cur_pc[22]
    DIRECTION OUTPUT ;
    USE SIGNAL ;
    PORT
      LAYER metal4 ;
        RECT 948.665 0.000 948.805 0.560 ;
    END
  END ifu_rtu_cur_pc[22]
  PIN ifu_rtu_cur_pc[23]
    DIRECTION OUTPUT ;
    USE SIGNAL ;
    PORT
      LAYER metal6 ;
        RECT 947.545 0.000 947.685 0.560 ;
    END
  END ifu_rtu_cur_pc[23]
  PIN ifu_rtu_cur_pc[24]
    DIRECTION OUTPUT ;
    USE SIGNAL ;
    PORT
      LAYER metal4 ;
        RECT 947.545 0.000 947.685 0.560 ;
    END
  END ifu_rtu_cur_pc[24]
  PIN ifu_rtu_cur_pc[25]
    DIRECTION OUTPUT ;
    USE SIGNAL ;
    PORT
      LAYER metal6 ;
        RECT 946.425 0.000 946.565 0.560 ;
    END
  END ifu_rtu_cur_pc[25]
  PIN ifu_rtu_cur_pc[26]
    DIRECTION OUTPUT ;
    USE SIGNAL ;
    PORT
      LAYER metal4 ;
        RECT 946.425 0.000 946.565 0.560 ;
    END
  END ifu_rtu_cur_pc[26]
  PIN ifu_rtu_cur_pc[27]
    DIRECTION OUTPUT ;
    USE SIGNAL ;
    PORT
      LAYER metal6 ;
        RECT 945.305 0.000 945.445 0.560 ;
    END
  END ifu_rtu_cur_pc[27]
  PIN ifu_rtu_cur_pc[28]
    DIRECTION OUTPUT ;
    USE SIGNAL ;
    PORT
      LAYER metal4 ;
        RECT 945.305 0.000 945.445 0.560 ;
    END
  END ifu_rtu_cur_pc[28]
  PIN ifu_rtu_cur_pc[29]
    DIRECTION OUTPUT ;
    USE SIGNAL ;
    PORT
      LAYER metal6 ;
        RECT 944.185 0.000 944.325 0.560 ;
    END
  END ifu_rtu_cur_pc[29]
  PIN ifu_rtu_cur_pc[2]
    DIRECTION OUTPUT ;
    USE SIGNAL ;
    PORT
      LAYER metal4 ;
        RECT 959.865 0.000 960.005 0.560 ;
    END
  END ifu_rtu_cur_pc[2]
  PIN ifu_rtu_cur_pc[30]
    DIRECTION OUTPUT ;
    USE SIGNAL ;
    PORT
      LAYER metal4 ;
        RECT 944.185 0.000 944.325 0.560 ;
    END
  END ifu_rtu_cur_pc[30]
  PIN ifu_rtu_cur_pc[31]
    DIRECTION OUTPUT ;
    USE SIGNAL ;
    PORT
      LAYER metal6 ;
        RECT 943.065 0.000 943.205 0.560 ;
    END
  END ifu_rtu_cur_pc[31]
  PIN ifu_rtu_cur_pc[32]
    DIRECTION OUTPUT ;
    USE SIGNAL ;
    PORT
      LAYER metal4 ;
        RECT 943.065 0.000 943.205 0.560 ;
    END
  END ifu_rtu_cur_pc[32]
  PIN ifu_rtu_cur_pc[33]
    DIRECTION OUTPUT ;
    USE SIGNAL ;
    PORT
      LAYER metal6 ;
        RECT 941.945 0.000 942.085 0.560 ;
    END
  END ifu_rtu_cur_pc[33]
  PIN ifu_rtu_cur_pc[34]
    DIRECTION OUTPUT ;
    USE SIGNAL ;
    PORT
      LAYER metal4 ;
        RECT 941.945 0.000 942.085 0.560 ;
    END
  END ifu_rtu_cur_pc[34]
  PIN ifu_rtu_cur_pc[35]
    DIRECTION OUTPUT ;
    USE SIGNAL ;
    PORT
      LAYER metal6 ;
        RECT 940.825 0.000 940.965 0.560 ;
    END
  END ifu_rtu_cur_pc[35]
  PIN ifu_rtu_cur_pc[36]
    DIRECTION OUTPUT ;
    USE SIGNAL ;
    PORT
      LAYER metal4 ;
        RECT 940.825 0.000 940.965 0.560 ;
    END
  END ifu_rtu_cur_pc[36]
  PIN ifu_rtu_cur_pc[37]
    DIRECTION OUTPUT ;
    USE SIGNAL ;
    PORT
      LAYER metal6 ;
        RECT 939.705 0.000 939.845 0.560 ;
    END
  END ifu_rtu_cur_pc[37]
  PIN ifu_rtu_cur_pc[38]
    DIRECTION OUTPUT ;
    USE SIGNAL ;
    PORT
      LAYER metal4 ;
        RECT 939.705 0.000 939.845 0.560 ;
    END
  END ifu_rtu_cur_pc[38]
  PIN ifu_rtu_cur_pc[3]
    DIRECTION OUTPUT ;
    USE SIGNAL ;
    PORT
      LAYER metal6 ;
        RECT 958.745 0.000 958.885 0.560 ;
    END
  END ifu_rtu_cur_pc[3]
  PIN ifu_rtu_cur_pc[4]
    DIRECTION OUTPUT ;
    USE SIGNAL ;
    PORT
      LAYER metal4 ;
        RECT 958.745 0.000 958.885 0.560 ;
    END
  END ifu_rtu_cur_pc[4]
  PIN ifu_rtu_cur_pc[5]
    DIRECTION OUTPUT ;
    USE SIGNAL ;
    PORT
      LAYER metal6 ;
        RECT 957.625 0.000 957.765 0.560 ;
    END
  END ifu_rtu_cur_pc[5]
  PIN ifu_rtu_cur_pc[6]
    DIRECTION OUTPUT ;
    USE SIGNAL ;
    PORT
      LAYER metal4 ;
        RECT 957.625 0.000 957.765 0.560 ;
    END
  END ifu_rtu_cur_pc[6]
  PIN ifu_rtu_cur_pc[7]
    DIRECTION OUTPUT ;
    USE SIGNAL ;
    PORT
      LAYER metal6 ;
        RECT 956.505 0.000 956.645 0.560 ;
    END
  END ifu_rtu_cur_pc[7]
  PIN ifu_rtu_cur_pc[8]
    DIRECTION OUTPUT ;
    USE SIGNAL ;
    PORT
      LAYER metal4 ;
        RECT 956.505 0.000 956.645 0.560 ;
    END
  END ifu_rtu_cur_pc[8]
  PIN ifu_rtu_cur_pc[9]
    DIRECTION OUTPUT ;
    USE SIGNAL ;
    PORT
      LAYER metal6 ;
        RECT 955.385 0.000 955.525 0.560 ;
    END
  END ifu_rtu_cur_pc[9]
  PIN ifu_rtu_cur_pc_load
    DIRECTION OUTPUT ;
    USE SIGNAL ;
    PORT
      LAYER metal6 ;
        RECT 960.985 0.000 961.125 0.560 ;
    END
  END ifu_rtu_cur_pc_load
  PIN ifu_xx_sync_reset
    DIRECTION OUTPUT ;
    USE SIGNAL ;
    PORT
      LAYER metal4 ;
        RECT 962.105 0.000 962.245 0.560 ;
    END
  END ifu_xx_sync_reset
  PIN ifu_yy_xx_no_op
    DIRECTION OUTPUT ;
    USE SIGNAL ;
    PORT
      LAYER metal6 ;
        RECT 962.105 0.000 962.245 0.560 ;
    END
  END ifu_yy_xx_no_op
  PIN iu_ifu_bht_check_vld
    DIRECTION INPUT ;
    USE SIGNAL ;
    PORT
      LAYER metal4 ;
        RECT 963.225 0.000 963.365 0.560 ;
    END
  END iu_ifu_bht_check_vld
  PIN iu_ifu_bht_condbr_taken
    DIRECTION INPUT ;
    USE SIGNAL ;
    PORT
      LAYER metal6 ;
        RECT 963.225 0.000 963.365 0.560 ;
    END
  END iu_ifu_bht_condbr_taken
  PIN iu_ifu_bht_pred
    DIRECTION INPUT ;
    USE SIGNAL ;
    PORT
      LAYER metal4 ;
        RECT 964.345 0.000 964.485 0.560 ;
    END
  END iu_ifu_bht_pred
  PIN iu_ifu_chgflw_pc[0]
    DIRECTION INPUT ;
    USE SIGNAL ;
    PORT
      LAYER metal6 ;
        RECT 999.065 0.000 999.205 0.560 ;
    END
  END iu_ifu_chgflw_pc[0]
  PIN iu_ifu_chgflw_pc[10]
    DIRECTION INPUT ;
    USE SIGNAL ;
    PORT
      LAYER metal6 ;
        RECT 993.465 0.000 993.605 0.560 ;
    END
  END iu_ifu_chgflw_pc[10]
  PIN iu_ifu_chgflw_pc[11]
    DIRECTION INPUT ;
    USE SIGNAL ;
    PORT
      LAYER metal4 ;
        RECT 993.465 0.000 993.605 0.560 ;
    END
  END iu_ifu_chgflw_pc[11]
  PIN iu_ifu_chgflw_pc[12]
    DIRECTION INPUT ;
    USE SIGNAL ;
    PORT
      LAYER metal6 ;
        RECT 992.345 0.000 992.485 0.560 ;
    END
  END iu_ifu_chgflw_pc[12]
  PIN iu_ifu_chgflw_pc[13]
    DIRECTION INPUT ;
    USE SIGNAL ;
    PORT
      LAYER metal4 ;
        RECT 992.345 0.000 992.485 0.560 ;
    END
  END iu_ifu_chgflw_pc[13]
  PIN iu_ifu_chgflw_pc[14]
    DIRECTION INPUT ;
    USE SIGNAL ;
    PORT
      LAYER metal6 ;
        RECT 991.225 0.000 991.365 0.560 ;
    END
  END iu_ifu_chgflw_pc[14]
  PIN iu_ifu_chgflw_pc[15]
    DIRECTION INPUT ;
    USE SIGNAL ;
    PORT
      LAYER metal4 ;
        RECT 991.225 0.000 991.365 0.560 ;
    END
  END iu_ifu_chgflw_pc[15]
  PIN iu_ifu_chgflw_pc[16]
    DIRECTION INPUT ;
    USE SIGNAL ;
    PORT
      LAYER metal6 ;
        RECT 990.105 0.000 990.245 0.560 ;
    END
  END iu_ifu_chgflw_pc[16]
  PIN iu_ifu_chgflw_pc[17]
    DIRECTION INPUT ;
    USE SIGNAL ;
    PORT
      LAYER metal4 ;
        RECT 990.105 0.000 990.245 0.560 ;
    END
  END iu_ifu_chgflw_pc[17]
  PIN iu_ifu_chgflw_pc[18]
    DIRECTION INPUT ;
    USE SIGNAL ;
    PORT
      LAYER metal6 ;
        RECT 988.985 0.000 989.125 0.560 ;
    END
  END iu_ifu_chgflw_pc[18]
  PIN iu_ifu_chgflw_pc[19]
    DIRECTION INPUT ;
    USE SIGNAL ;
    PORT
      LAYER metal4 ;
        RECT 988.985 0.000 989.125 0.560 ;
    END
  END iu_ifu_chgflw_pc[19]
  PIN iu_ifu_chgflw_pc[1]
    DIRECTION INPUT ;
    USE SIGNAL ;
    PORT
      LAYER metal4 ;
        RECT 999.065 0.000 999.205 0.560 ;
    END
  END iu_ifu_chgflw_pc[1]
  PIN iu_ifu_chgflw_pc[20]
    DIRECTION INPUT ;
    USE SIGNAL ;
    PORT
      LAYER metal6 ;
        RECT 987.865 0.000 988.005 0.560 ;
    END
  END iu_ifu_chgflw_pc[20]
  PIN iu_ifu_chgflw_pc[21]
    DIRECTION INPUT ;
    USE SIGNAL ;
    PORT
      LAYER metal4 ;
        RECT 987.865 0.000 988.005 0.560 ;
    END
  END iu_ifu_chgflw_pc[21]
  PIN iu_ifu_chgflw_pc[22]
    DIRECTION INPUT ;
    USE SIGNAL ;
    PORT
      LAYER metal6 ;
        RECT 986.745 0.000 986.885 0.560 ;
    END
  END iu_ifu_chgflw_pc[22]
  PIN iu_ifu_chgflw_pc[23]
    DIRECTION INPUT ;
    USE SIGNAL ;
    PORT
      LAYER metal4 ;
        RECT 986.745 0.000 986.885 0.560 ;
    END
  END iu_ifu_chgflw_pc[23]
  PIN iu_ifu_chgflw_pc[24]
    DIRECTION INPUT ;
    USE SIGNAL ;
    PORT
      LAYER metal6 ;
        RECT 985.625 0.000 985.765 0.560 ;
    END
  END iu_ifu_chgflw_pc[24]
  PIN iu_ifu_chgflw_pc[25]
    DIRECTION INPUT ;
    USE SIGNAL ;
    PORT
      LAYER metal4 ;
        RECT 985.625 0.000 985.765 0.560 ;
    END
  END iu_ifu_chgflw_pc[25]
  PIN iu_ifu_chgflw_pc[26]
    DIRECTION INPUT ;
    USE SIGNAL ;
    PORT
      LAYER metal6 ;
        RECT 984.505 0.000 984.645 0.560 ;
    END
  END iu_ifu_chgflw_pc[26]
  PIN iu_ifu_chgflw_pc[27]
    DIRECTION INPUT ;
    USE SIGNAL ;
    PORT
      LAYER metal4 ;
        RECT 984.505 0.000 984.645 0.560 ;
    END
  END iu_ifu_chgflw_pc[27]
  PIN iu_ifu_chgflw_pc[28]
    DIRECTION INPUT ;
    USE SIGNAL ;
    PORT
      LAYER metal6 ;
        RECT 983.385 0.000 983.525 0.560 ;
    END
  END iu_ifu_chgflw_pc[28]
  PIN iu_ifu_chgflw_pc[29]
    DIRECTION INPUT ;
    USE SIGNAL ;
    PORT
      LAYER metal4 ;
        RECT 983.385 0.000 983.525 0.560 ;
    END
  END iu_ifu_chgflw_pc[29]
  PIN iu_ifu_chgflw_pc[2]
    DIRECTION INPUT ;
    USE SIGNAL ;
    PORT
      LAYER metal6 ;
        RECT 997.945 0.000 998.085 0.560 ;
    END
  END iu_ifu_chgflw_pc[2]
  PIN iu_ifu_chgflw_pc[30]
    DIRECTION INPUT ;
    USE SIGNAL ;
    PORT
      LAYER metal6 ;
        RECT 982.265 0.000 982.405 0.560 ;
    END
  END iu_ifu_chgflw_pc[30]
  PIN iu_ifu_chgflw_pc[31]
    DIRECTION INPUT ;
    USE SIGNAL ;
    PORT
      LAYER metal4 ;
        RECT 982.265 0.000 982.405 0.560 ;
    END
  END iu_ifu_chgflw_pc[31]
  PIN iu_ifu_chgflw_pc[32]
    DIRECTION INPUT ;
    USE SIGNAL ;
    PORT
      LAYER metal6 ;
        RECT 981.145 0.000 981.285 0.560 ;
    END
  END iu_ifu_chgflw_pc[32]
  PIN iu_ifu_chgflw_pc[33]
    DIRECTION INPUT ;
    USE SIGNAL ;
    PORT
      LAYER metal4 ;
        RECT 981.145 0.000 981.285 0.560 ;
    END
  END iu_ifu_chgflw_pc[33]
  PIN iu_ifu_chgflw_pc[34]
    DIRECTION INPUT ;
    USE SIGNAL ;
    PORT
      LAYER metal6 ;
        RECT 980.025 0.000 980.165 0.560 ;
    END
  END iu_ifu_chgflw_pc[34]
  PIN iu_ifu_chgflw_pc[35]
    DIRECTION INPUT ;
    USE SIGNAL ;
    PORT
      LAYER metal4 ;
        RECT 980.025 0.000 980.165 0.560 ;
    END
  END iu_ifu_chgflw_pc[35]
  PIN iu_ifu_chgflw_pc[36]
    DIRECTION INPUT ;
    USE SIGNAL ;
    PORT
      LAYER metal6 ;
        RECT 978.905 0.000 979.045 0.560 ;
    END
  END iu_ifu_chgflw_pc[36]
  PIN iu_ifu_chgflw_pc[37]
    DIRECTION INPUT ;
    USE SIGNAL ;
    PORT
      LAYER metal4 ;
        RECT 978.905 0.000 979.045 0.560 ;
    END
  END iu_ifu_chgflw_pc[37]
  PIN iu_ifu_chgflw_pc[38]
    DIRECTION INPUT ;
    USE SIGNAL ;
    PORT
      LAYER metal6 ;
        RECT 977.785 0.000 977.925 0.560 ;
    END
  END iu_ifu_chgflw_pc[38]
  PIN iu_ifu_chgflw_pc[39]
    DIRECTION INPUT ;
    USE SIGNAL ;
    PORT
      LAYER metal4 ;
        RECT 977.785 0.000 977.925 0.560 ;
    END
  END iu_ifu_chgflw_pc[39]
  PIN iu_ifu_chgflw_pc[3]
    DIRECTION INPUT ;
    USE SIGNAL ;
    PORT
      LAYER metal4 ;
        RECT 997.945 0.000 998.085 0.560 ;
    END
  END iu_ifu_chgflw_pc[3]
  PIN iu_ifu_chgflw_pc[40]
    DIRECTION INPUT ;
    USE SIGNAL ;
    PORT
      LAYER metal6 ;
        RECT 976.665 0.000 976.805 0.560 ;
    END
  END iu_ifu_chgflw_pc[40]
  PIN iu_ifu_chgflw_pc[41]
    DIRECTION INPUT ;
    USE SIGNAL ;
    PORT
      LAYER metal4 ;
        RECT 976.665 0.000 976.805 0.560 ;
    END
  END iu_ifu_chgflw_pc[41]
  PIN iu_ifu_chgflw_pc[42]
    DIRECTION INPUT ;
    USE SIGNAL ;
    PORT
      LAYER metal6 ;
        RECT 975.545 0.000 975.685 0.560 ;
    END
  END iu_ifu_chgflw_pc[42]
  PIN iu_ifu_chgflw_pc[43]
    DIRECTION INPUT ;
    USE SIGNAL ;
    PORT
      LAYER metal4 ;
        RECT 975.545 0.000 975.685 0.560 ;
    END
  END iu_ifu_chgflw_pc[43]
  PIN iu_ifu_chgflw_pc[44]
    DIRECTION INPUT ;
    USE SIGNAL ;
    PORT
      LAYER metal6 ;
        RECT 974.425 0.000 974.565 0.560 ;
    END
  END iu_ifu_chgflw_pc[44]
  PIN iu_ifu_chgflw_pc[45]
    DIRECTION INPUT ;
    USE SIGNAL ;
    PORT
      LAYER metal4 ;
        RECT 974.425 0.000 974.565 0.560 ;
    END
  END iu_ifu_chgflw_pc[45]
  PIN iu_ifu_chgflw_pc[46]
    DIRECTION INPUT ;
    USE SIGNAL ;
    PORT
      LAYER metal6 ;
        RECT 973.305 0.000 973.445 0.560 ;
    END
  END iu_ifu_chgflw_pc[46]
  PIN iu_ifu_chgflw_pc[47]
    DIRECTION INPUT ;
    USE SIGNAL ;
    PORT
      LAYER metal4 ;
        RECT 973.305 0.000 973.445 0.560 ;
    END
  END iu_ifu_chgflw_pc[47]
  PIN iu_ifu_chgflw_pc[48]
    DIRECTION INPUT ;
    USE SIGNAL ;
    PORT
      LAYER metal6 ;
        RECT 972.185 0.000 972.325 0.560 ;
    END
  END iu_ifu_chgflw_pc[48]
  PIN iu_ifu_chgflw_pc[49]
    DIRECTION INPUT ;
    USE SIGNAL ;
    PORT
      LAYER metal4 ;
        RECT 972.185 0.000 972.325 0.560 ;
    END
  END iu_ifu_chgflw_pc[49]
  PIN iu_ifu_chgflw_pc[4]
    DIRECTION INPUT ;
    USE SIGNAL ;
    PORT
      LAYER metal6 ;
        RECT 996.825 0.000 996.965 0.560 ;
    END
  END iu_ifu_chgflw_pc[4]
  PIN iu_ifu_chgflw_pc[50]
    DIRECTION INPUT ;
    USE SIGNAL ;
    PORT
      LAYER metal6 ;
        RECT 971.065 0.000 971.205 0.560 ;
    END
  END iu_ifu_chgflw_pc[50]
  PIN iu_ifu_chgflw_pc[51]
    DIRECTION INPUT ;
    USE SIGNAL ;
    PORT
      LAYER metal4 ;
        RECT 971.065 0.000 971.205 0.560 ;
    END
  END iu_ifu_chgflw_pc[51]
  PIN iu_ifu_chgflw_pc[52]
    DIRECTION INPUT ;
    USE SIGNAL ;
    PORT
      LAYER metal6 ;
        RECT 969.945 0.000 970.085 0.560 ;
    END
  END iu_ifu_chgflw_pc[52]
  PIN iu_ifu_chgflw_pc[53]
    DIRECTION INPUT ;
    USE SIGNAL ;
    PORT
      LAYER metal4 ;
        RECT 969.945 0.000 970.085 0.560 ;
    END
  END iu_ifu_chgflw_pc[53]
  PIN iu_ifu_chgflw_pc[54]
    DIRECTION INPUT ;
    USE SIGNAL ;
    PORT
      LAYER metal6 ;
        RECT 968.825 0.000 968.965 0.560 ;
    END
  END iu_ifu_chgflw_pc[54]
  PIN iu_ifu_chgflw_pc[55]
    DIRECTION INPUT ;
    USE SIGNAL ;
    PORT
      LAYER metal4 ;
        RECT 968.825 0.000 968.965 0.560 ;
    END
  END iu_ifu_chgflw_pc[55]
  PIN iu_ifu_chgflw_pc[56]
    DIRECTION INPUT ;
    USE SIGNAL ;
    PORT
      LAYER metal6 ;
        RECT 967.705 0.000 967.845 0.560 ;
    END
  END iu_ifu_chgflw_pc[56]
  PIN iu_ifu_chgflw_pc[57]
    DIRECTION INPUT ;
    USE SIGNAL ;
    PORT
      LAYER metal4 ;
        RECT 967.705 0.000 967.845 0.560 ;
    END
  END iu_ifu_chgflw_pc[57]
  PIN iu_ifu_chgflw_pc[58]
    DIRECTION INPUT ;
    USE SIGNAL ;
    PORT
      LAYER metal6 ;
        RECT 966.585 0.000 966.725 0.560 ;
    END
  END iu_ifu_chgflw_pc[58]
  PIN iu_ifu_chgflw_pc[59]
    DIRECTION INPUT ;
    USE SIGNAL ;
    PORT
      LAYER metal4 ;
        RECT 966.585 0.000 966.725 0.560 ;
    END
  END iu_ifu_chgflw_pc[59]
  PIN iu_ifu_chgflw_pc[5]
    DIRECTION INPUT ;
    USE SIGNAL ;
    PORT
      LAYER metal4 ;
        RECT 996.825 0.000 996.965 0.560 ;
    END
  END iu_ifu_chgflw_pc[5]
  PIN iu_ifu_chgflw_pc[60]
    DIRECTION INPUT ;
    USE SIGNAL ;
    PORT
      LAYER metal6 ;
        RECT 965.465 0.000 965.605 0.560 ;
    END
  END iu_ifu_chgflw_pc[60]
  PIN iu_ifu_chgflw_pc[61]
    DIRECTION INPUT ;
    USE SIGNAL ;
    PORT
      LAYER metal4 ;
        RECT 965.465 0.000 965.605 0.560 ;
    END
  END iu_ifu_chgflw_pc[61]
  PIN iu_ifu_chgflw_pc[62]
    DIRECTION INPUT ;
    USE SIGNAL ;
    PORT
      LAYER metal6 ;
        RECT 964.345 0.000 964.485 0.560 ;
    END
  END iu_ifu_chgflw_pc[62]
  PIN iu_ifu_chgflw_pc[6]
    DIRECTION INPUT ;
    USE SIGNAL ;
    PORT
      LAYER metal6 ;
        RECT 995.705 0.000 995.845 0.560 ;
    END
  END iu_ifu_chgflw_pc[6]
  PIN iu_ifu_chgflw_pc[7]
    DIRECTION INPUT ;
    USE SIGNAL ;
    PORT
      LAYER metal4 ;
        RECT 995.705 0.000 995.845 0.560 ;
    END
  END iu_ifu_chgflw_pc[7]
  PIN iu_ifu_chgflw_pc[8]
    DIRECTION INPUT ;
    USE SIGNAL ;
    PORT
      LAYER metal6 ;
        RECT 994.585 0.000 994.725 0.560 ;
    END
  END iu_ifu_chgflw_pc[8]
  PIN iu_ifu_chgflw_pc[9]
    DIRECTION INPUT ;
    USE SIGNAL ;
    PORT
      LAYER metal4 ;
        RECT 994.585 0.000 994.725 0.560 ;
    END
  END iu_ifu_chgflw_pc[9]
  PIN iu_ifu_chgflw_vl[0]
    DIRECTION INPUT ;
    USE SIGNAL ;
    PORT
      LAYER metal6 ;
        RECT 1003.545 0.000 1003.685 0.560 ;
    END
  END iu_ifu_chgflw_vl[0]
  PIN iu_ifu_chgflw_vl[1]
    DIRECTION INPUT ;
    USE SIGNAL ;
    PORT
      LAYER metal4 ;
        RECT 1003.545 0.000 1003.685 0.560 ;
    END
  END iu_ifu_chgflw_vl[1]
  PIN iu_ifu_chgflw_vl[2]
    DIRECTION INPUT ;
    USE SIGNAL ;
    PORT
      LAYER metal6 ;
        RECT 1002.425 0.000 1002.565 0.560 ;
    END
  END iu_ifu_chgflw_vl[2]
  PIN iu_ifu_chgflw_vl[3]
    DIRECTION INPUT ;
    USE SIGNAL ;
    PORT
      LAYER metal4 ;
        RECT 1002.425 0.000 1002.565 0.560 ;
    END
  END iu_ifu_chgflw_vl[3]
  PIN iu_ifu_chgflw_vl[4]
    DIRECTION INPUT ;
    USE SIGNAL ;
    PORT
      LAYER metal6 ;
        RECT 1001.305 0.000 1001.445 0.560 ;
    END
  END iu_ifu_chgflw_vl[4]
  PIN iu_ifu_chgflw_vl[5]
    DIRECTION INPUT ;
    USE SIGNAL ;
    PORT
      LAYER metal4 ;
        RECT 1001.305 0.000 1001.445 0.560 ;
    END
  END iu_ifu_chgflw_vl[5]
  PIN iu_ifu_chgflw_vl[6]
    DIRECTION INPUT ;
    USE SIGNAL ;
    PORT
      LAYER metal6 ;
        RECT 1000.185 0.000 1000.325 0.560 ;
    END
  END iu_ifu_chgflw_vl[6]
  PIN iu_ifu_chgflw_vl[7]
    DIRECTION INPUT ;
    USE SIGNAL ;
    PORT
      LAYER metal4 ;
        RECT 1000.185 0.000 1000.325 0.560 ;
    END
  END iu_ifu_chgflw_vl[7]
  PIN iu_ifu_chgflw_vld
    DIRECTION INPUT ;
    USE SIGNAL ;
    PORT
      LAYER metal4 ;
        RECT 1004.665 0.000 1004.805 0.560 ;
    END
  END iu_ifu_chgflw_vld
  PIN iu_ifu_chgflw_vlmul[0]
    DIRECTION INPUT ;
    USE SIGNAL ;
    PORT
      LAYER metal4 ;
        RECT 1005.785 0.000 1005.925 0.560 ;
    END
  END iu_ifu_chgflw_vlmul[0]
  PIN iu_ifu_chgflw_vlmul[1]
    DIRECTION INPUT ;
    USE SIGNAL ;
    PORT
      LAYER metal6 ;
        RECT 1004.665 0.000 1004.805 0.560 ;
    END
  END iu_ifu_chgflw_vlmul[1]
  PIN iu_ifu_chgflw_vsew[0]
    DIRECTION INPUT ;
    USE SIGNAL ;
    PORT
      LAYER metal6 ;
        RECT 1006.905 0.000 1007.045 0.560 ;
    END
  END iu_ifu_chgflw_vsew[0]
  PIN iu_ifu_chgflw_vsew[1]
    DIRECTION INPUT ;
    USE SIGNAL ;
    PORT
      LAYER metal4 ;
        RECT 1006.905 0.000 1007.045 0.560 ;
    END
  END iu_ifu_chgflw_vsew[1]
  PIN iu_ifu_chgflw_vsew[2]
    DIRECTION INPUT ;
    USE SIGNAL ;
    PORT
      LAYER metal6 ;
        RECT 1005.785 0.000 1005.925 0.560 ;
    END
  END iu_ifu_chgflw_vsew[2]
  PIN iu_ifu_chk_idx[0]
    DIRECTION INPUT ;
    USE SIGNAL ;
    PORT
      LAYER metal4 ;
        RECT 1021.465 0.000 1021.605 0.560 ;
    END
  END iu_ifu_chk_idx[0]
  PIN iu_ifu_chk_idx[10]
    DIRECTION INPUT ;
    USE SIGNAL ;
    PORT
      LAYER metal4 ;
        RECT 1015.865 0.000 1016.005 0.560 ;
    END
  END iu_ifu_chk_idx[10]
  PIN iu_ifu_chk_idx[11]
    DIRECTION INPUT ;
    USE SIGNAL ;
    PORT
      LAYER metal6 ;
        RECT 1014.745 0.000 1014.885 0.560 ;
    END
  END iu_ifu_chk_idx[11]
  PIN iu_ifu_chk_idx[12]
    DIRECTION INPUT ;
    USE SIGNAL ;
    PORT
      LAYER metal4 ;
        RECT 1014.745 0.000 1014.885 0.560 ;
    END
  END iu_ifu_chk_idx[12]
  PIN iu_ifu_chk_idx[13]
    DIRECTION INPUT ;
    USE SIGNAL ;
    PORT
      LAYER metal6 ;
        RECT 1013.625 0.000 1013.765 0.560 ;
    END
  END iu_ifu_chk_idx[13]
  PIN iu_ifu_chk_idx[14]
    DIRECTION INPUT ;
    USE SIGNAL ;
    PORT
      LAYER metal4 ;
        RECT 1013.625 0.000 1013.765 0.560 ;
    END
  END iu_ifu_chk_idx[14]
  PIN iu_ifu_chk_idx[15]
    DIRECTION INPUT ;
    USE SIGNAL ;
    PORT
      LAYER metal6 ;
        RECT 1012.505 0.000 1012.645 0.560 ;
    END
  END iu_ifu_chk_idx[15]
  PIN iu_ifu_chk_idx[16]
    DIRECTION INPUT ;
    USE SIGNAL ;
    PORT
      LAYER metal4 ;
        RECT 1012.505 0.000 1012.645 0.560 ;
    END
  END iu_ifu_chk_idx[16]
  PIN iu_ifu_chk_idx[17]
    DIRECTION INPUT ;
    USE SIGNAL ;
    PORT
      LAYER metal6 ;
        RECT 1011.385 0.000 1011.525 0.560 ;
    END
  END iu_ifu_chk_idx[17]
  PIN iu_ifu_chk_idx[18]
    DIRECTION INPUT ;
    USE SIGNAL ;
    PORT
      LAYER metal4 ;
        RECT 1011.385 0.000 1011.525 0.560 ;
    END
  END iu_ifu_chk_idx[18]
  PIN iu_ifu_chk_idx[19]
    DIRECTION INPUT ;
    USE SIGNAL ;
    PORT
      LAYER metal6 ;
        RECT 1010.265 0.000 1010.405 0.560 ;
    END
  END iu_ifu_chk_idx[19]
  PIN iu_ifu_chk_idx[1]
    DIRECTION INPUT ;
    USE SIGNAL ;
    PORT
      LAYER metal6 ;
        RECT 1020.345 0.000 1020.485 0.560 ;
    END
  END iu_ifu_chk_idx[1]
  PIN iu_ifu_chk_idx[20]
    DIRECTION INPUT ;
    USE SIGNAL ;
    PORT
      LAYER metal4 ;
        RECT 1010.265 0.000 1010.405 0.560 ;
    END
  END iu_ifu_chk_idx[20]
  PIN iu_ifu_chk_idx[21]
    DIRECTION INPUT ;
    USE SIGNAL ;
    PORT
      LAYER metal6 ;
        RECT 1009.145 0.000 1009.285 0.560 ;
    END
  END iu_ifu_chk_idx[21]
  PIN iu_ifu_chk_idx[22]
    DIRECTION INPUT ;
    USE SIGNAL ;
    PORT
      LAYER metal4 ;
        RECT 1009.145 0.000 1009.285 0.560 ;
    END
  END iu_ifu_chk_idx[22]
  PIN iu_ifu_chk_idx[23]
    DIRECTION INPUT ;
    USE SIGNAL ;
    PORT
      LAYER metal6 ;
        RECT 1008.025 0.000 1008.165 0.560 ;
    END
  END iu_ifu_chk_idx[23]
  PIN iu_ifu_chk_idx[24]
    DIRECTION INPUT ;
    USE SIGNAL ;
    PORT
      LAYER metal4 ;
        RECT 1008.025 0.000 1008.165 0.560 ;
    END
  END iu_ifu_chk_idx[24]
  PIN iu_ifu_chk_idx[2]
    DIRECTION INPUT ;
    USE SIGNAL ;
    PORT
      LAYER metal4 ;
        RECT 1020.345 0.000 1020.485 0.560 ;
    END
  END iu_ifu_chk_idx[2]
  PIN iu_ifu_chk_idx[3]
    DIRECTION INPUT ;
    USE SIGNAL ;
    PORT
      LAYER metal6 ;
        RECT 1019.225 0.000 1019.365 0.560 ;
    END
  END iu_ifu_chk_idx[3]
  PIN iu_ifu_chk_idx[4]
    DIRECTION INPUT ;
    USE SIGNAL ;
    PORT
      LAYER metal4 ;
        RECT 1019.225 0.000 1019.365 0.560 ;
    END
  END iu_ifu_chk_idx[4]
  PIN iu_ifu_chk_idx[5]
    DIRECTION INPUT ;
    USE SIGNAL ;
    PORT
      LAYER metal6 ;
        RECT 1018.105 0.000 1018.245 0.560 ;
    END
  END iu_ifu_chk_idx[5]
  PIN iu_ifu_chk_idx[6]
    DIRECTION INPUT ;
    USE SIGNAL ;
    PORT
      LAYER metal4 ;
        RECT 1018.105 0.000 1018.245 0.560 ;
    END
  END iu_ifu_chk_idx[6]
  PIN iu_ifu_chk_idx[7]
    DIRECTION INPUT ;
    USE SIGNAL ;
    PORT
      LAYER metal6 ;
        RECT 1016.985 0.000 1017.125 0.560 ;
    END
  END iu_ifu_chk_idx[7]
  PIN iu_ifu_chk_idx[8]
    DIRECTION INPUT ;
    USE SIGNAL ;
    PORT
      LAYER metal4 ;
        RECT 1016.985 0.000 1017.125 0.560 ;
    END
  END iu_ifu_chk_idx[8]
  PIN iu_ifu_chk_idx[9]
    DIRECTION INPUT ;
    USE SIGNAL ;
    PORT
      LAYER metal6 ;
        RECT 1015.865 0.000 1016.005 0.560 ;
    END
  END iu_ifu_chk_idx[9]
  PIN iu_ifu_cur_pc[0]
    DIRECTION INPUT ;
    USE SIGNAL ;
    PORT
      LAYER metal6 ;
        RECT 1042.745 0.000 1042.885 0.560 ;
    END
  END iu_ifu_cur_pc[0]
  PIN iu_ifu_cur_pc[10]
    DIRECTION INPUT ;
    USE SIGNAL ;
    PORT
      LAYER metal6 ;
        RECT 1037.145 0.000 1037.285 0.560 ;
    END
  END iu_ifu_cur_pc[10]
  PIN iu_ifu_cur_pc[11]
    DIRECTION INPUT ;
    USE SIGNAL ;
    PORT
      LAYER metal4 ;
        RECT 1037.145 0.000 1037.285 0.560 ;
    END
  END iu_ifu_cur_pc[11]
  PIN iu_ifu_cur_pc[12]
    DIRECTION INPUT ;
    USE SIGNAL ;
    PORT
      LAYER metal6 ;
        RECT 1036.025 0.000 1036.165 0.560 ;
    END
  END iu_ifu_cur_pc[12]
  PIN iu_ifu_cur_pc[13]
    DIRECTION INPUT ;
    USE SIGNAL ;
    PORT
      LAYER metal4 ;
        RECT 1036.025 0.000 1036.165 0.560 ;
    END
  END iu_ifu_cur_pc[13]
  PIN iu_ifu_cur_pc[14]
    DIRECTION INPUT ;
    USE SIGNAL ;
    PORT
      LAYER metal6 ;
        RECT 1034.905 0.000 1035.045 0.560 ;
    END
  END iu_ifu_cur_pc[14]
  PIN iu_ifu_cur_pc[15]
    DIRECTION INPUT ;
    USE SIGNAL ;
    PORT
      LAYER metal4 ;
        RECT 1034.905 0.000 1035.045 0.560 ;
    END
  END iu_ifu_cur_pc[15]
  PIN iu_ifu_cur_pc[16]
    DIRECTION INPUT ;
    USE SIGNAL ;
    PORT
      LAYER metal6 ;
        RECT 1033.785 0.000 1033.925 0.560 ;
    END
  END iu_ifu_cur_pc[16]
  PIN iu_ifu_cur_pc[17]
    DIRECTION INPUT ;
    USE SIGNAL ;
    PORT
      LAYER metal4 ;
        RECT 1033.785 0.000 1033.925 0.560 ;
    END
  END iu_ifu_cur_pc[17]
  PIN iu_ifu_cur_pc[18]
    DIRECTION INPUT ;
    USE SIGNAL ;
    PORT
      LAYER metal6 ;
        RECT 1032.665 0.000 1032.805 0.560 ;
    END
  END iu_ifu_cur_pc[18]
  PIN iu_ifu_cur_pc[19]
    DIRECTION INPUT ;
    USE SIGNAL ;
    PORT
      LAYER metal4 ;
        RECT 1032.665 0.000 1032.805 0.560 ;
    END
  END iu_ifu_cur_pc[19]
  PIN iu_ifu_cur_pc[1]
    DIRECTION INPUT ;
    USE SIGNAL ;
    PORT
      LAYER metal4 ;
        RECT 1042.745 0.000 1042.885 0.560 ;
    END
  END iu_ifu_cur_pc[1]
  PIN iu_ifu_cur_pc[20]
    DIRECTION INPUT ;
    USE SIGNAL ;
    PORT
      LAYER metal6 ;
        RECT 1031.545 0.000 1031.685 0.560 ;
    END
  END iu_ifu_cur_pc[20]
  PIN iu_ifu_cur_pc[21]
    DIRECTION INPUT ;
    USE SIGNAL ;
    PORT
      LAYER metal4 ;
        RECT 1031.545 0.000 1031.685 0.560 ;
    END
  END iu_ifu_cur_pc[21]
  PIN iu_ifu_cur_pc[22]
    DIRECTION INPUT ;
    USE SIGNAL ;
    PORT
      LAYER metal6 ;
        RECT 1030.425 0.000 1030.565 0.560 ;
    END
  END iu_ifu_cur_pc[22]
  PIN iu_ifu_cur_pc[23]
    DIRECTION INPUT ;
    USE SIGNAL ;
    PORT
      LAYER metal4 ;
        RECT 1030.425 0.000 1030.565 0.560 ;
    END
  END iu_ifu_cur_pc[23]
  PIN iu_ifu_cur_pc[24]
    DIRECTION INPUT ;
    USE SIGNAL ;
    PORT
      LAYER metal6 ;
        RECT 1029.305 0.000 1029.445 0.560 ;
    END
  END iu_ifu_cur_pc[24]
  PIN iu_ifu_cur_pc[25]
    DIRECTION INPUT ;
    USE SIGNAL ;
    PORT
      LAYER metal4 ;
        RECT 1029.305 0.000 1029.445 0.560 ;
    END
  END iu_ifu_cur_pc[25]
  PIN iu_ifu_cur_pc[26]
    DIRECTION INPUT ;
    USE SIGNAL ;
    PORT
      LAYER metal6 ;
        RECT 1028.185 0.000 1028.325 0.560 ;
    END
  END iu_ifu_cur_pc[26]
  PIN iu_ifu_cur_pc[27]
    DIRECTION INPUT ;
    USE SIGNAL ;
    PORT
      LAYER metal4 ;
        RECT 1028.185 0.000 1028.325 0.560 ;
    END
  END iu_ifu_cur_pc[27]
  PIN iu_ifu_cur_pc[28]
    DIRECTION INPUT ;
    USE SIGNAL ;
    PORT
      LAYER metal6 ;
        RECT 1027.065 0.000 1027.205 0.560 ;
    END
  END iu_ifu_cur_pc[28]
  PIN iu_ifu_cur_pc[29]
    DIRECTION INPUT ;
    USE SIGNAL ;
    PORT
      LAYER metal4 ;
        RECT 1027.065 0.000 1027.205 0.560 ;
    END
  END iu_ifu_cur_pc[29]
  PIN iu_ifu_cur_pc[2]
    DIRECTION INPUT ;
    USE SIGNAL ;
    PORT
      LAYER metal6 ;
        RECT 1041.625 0.000 1041.765 0.560 ;
    END
  END iu_ifu_cur_pc[2]
  PIN iu_ifu_cur_pc[30]
    DIRECTION INPUT ;
    USE SIGNAL ;
    PORT
      LAYER metal6 ;
        RECT 1025.945 0.000 1026.085 0.560 ;
    END
  END iu_ifu_cur_pc[30]
  PIN iu_ifu_cur_pc[31]
    DIRECTION INPUT ;
    USE SIGNAL ;
    PORT
      LAYER metal4 ;
        RECT 1025.945 0.000 1026.085 0.560 ;
    END
  END iu_ifu_cur_pc[31]
  PIN iu_ifu_cur_pc[32]
    DIRECTION INPUT ;
    USE SIGNAL ;
    PORT
      LAYER metal6 ;
        RECT 1024.825 0.000 1024.965 0.560 ;
    END
  END iu_ifu_cur_pc[32]
  PIN iu_ifu_cur_pc[33]
    DIRECTION INPUT ;
    USE SIGNAL ;
    PORT
      LAYER metal4 ;
        RECT 1024.825 0.000 1024.965 0.560 ;
    END
  END iu_ifu_cur_pc[33]
  PIN iu_ifu_cur_pc[34]
    DIRECTION INPUT ;
    USE SIGNAL ;
    PORT
      LAYER metal6 ;
        RECT 1023.705 0.000 1023.845 0.560 ;
    END
  END iu_ifu_cur_pc[34]
  PIN iu_ifu_cur_pc[35]
    DIRECTION INPUT ;
    USE SIGNAL ;
    PORT
      LAYER metal4 ;
        RECT 1023.705 0.000 1023.845 0.560 ;
    END
  END iu_ifu_cur_pc[35]
  PIN iu_ifu_cur_pc[36]
    DIRECTION INPUT ;
    USE SIGNAL ;
    PORT
      LAYER metal6 ;
        RECT 1022.585 0.000 1022.725 0.560 ;
    END
  END iu_ifu_cur_pc[36]
  PIN iu_ifu_cur_pc[37]
    DIRECTION INPUT ;
    USE SIGNAL ;
    PORT
      LAYER metal4 ;
        RECT 1022.585 0.000 1022.725 0.560 ;
    END
  END iu_ifu_cur_pc[37]
  PIN iu_ifu_cur_pc[38]
    DIRECTION INPUT ;
    USE SIGNAL ;
    PORT
      LAYER metal6 ;
        RECT 1021.465 0.000 1021.605 0.560 ;
    END
  END iu_ifu_cur_pc[38]
  PIN iu_ifu_cur_pc[3]
    DIRECTION INPUT ;
    USE SIGNAL ;
    PORT
      LAYER metal4 ;
        RECT 1041.625 0.000 1041.765 0.560 ;
    END
  END iu_ifu_cur_pc[3]
  PIN iu_ifu_cur_pc[4]
    DIRECTION INPUT ;
    USE SIGNAL ;
    PORT
      LAYER metal6 ;
        RECT 1040.505 0.000 1040.645 0.560 ;
    END
  END iu_ifu_cur_pc[4]
  PIN iu_ifu_cur_pc[5]
    DIRECTION INPUT ;
    USE SIGNAL ;
    PORT
      LAYER metal4 ;
        RECT 1040.505 0.000 1040.645 0.560 ;
    END
  END iu_ifu_cur_pc[5]
  PIN iu_ifu_cur_pc[6]
    DIRECTION INPUT ;
    USE SIGNAL ;
    PORT
      LAYER metal6 ;
        RECT 1039.385 0.000 1039.525 0.560 ;
    END
  END iu_ifu_cur_pc[6]
  PIN iu_ifu_cur_pc[7]
    DIRECTION INPUT ;
    USE SIGNAL ;
    PORT
      LAYER metal4 ;
        RECT 1039.385 0.000 1039.525 0.560 ;
    END
  END iu_ifu_cur_pc[7]
  PIN iu_ifu_cur_pc[8]
    DIRECTION INPUT ;
    USE SIGNAL ;
    PORT
      LAYER metal6 ;
        RECT 1038.265 0.000 1038.405 0.560 ;
    END
  END iu_ifu_cur_pc[8]
  PIN iu_ifu_cur_pc[9]
    DIRECTION INPUT ;
    USE SIGNAL ;
    PORT
      LAYER metal4 ;
        RECT 1038.265 0.000 1038.405 0.560 ;
    END
  END iu_ifu_cur_pc[9]
  PIN iu_ifu_mispred_stall
    DIRECTION INPUT ;
    USE SIGNAL ;
    PORT
      LAYER metal4 ;
        RECT 1043.865 0.000 1044.005 0.560 ;
    END
  END iu_ifu_mispred_stall
  PIN iu_ifu_pcfifo_full
    DIRECTION INPUT ;
    USE SIGNAL ;
    PORT
      LAYER metal6 ;
        RECT 1043.865 0.000 1044.005 0.560 ;
    END
  END iu_ifu_pcfifo_full
  PIN lsu_ifu_icache_all_inv
    DIRECTION INPUT ;
    USE SIGNAL ;
    PORT
      LAYER metal4 ;
        RECT 1044.985 0.000 1045.125 0.560 ;
    END
  END lsu_ifu_icache_all_inv
  PIN lsu_ifu_icache_index[0]
    DIRECTION INPUT ;
    USE SIGNAL ;
    PORT
      LAYER metal4 ;
        RECT 1048.345 0.000 1048.485 0.560 ;
    END
  END lsu_ifu_icache_index[0]
  PIN lsu_ifu_icache_index[1]
    DIRECTION INPUT ;
    USE SIGNAL ;
    PORT
      LAYER metal6 ;
        RECT 1047.225 0.000 1047.365 0.560 ;
    END
  END lsu_ifu_icache_index[1]
  PIN lsu_ifu_icache_index[2]
    DIRECTION INPUT ;
    USE SIGNAL ;
    PORT
      LAYER metal4 ;
        RECT 1047.225 0.000 1047.365 0.560 ;
    END
  END lsu_ifu_icache_index[2]
  PIN lsu_ifu_icache_index[3]
    DIRECTION INPUT ;
    USE SIGNAL ;
    PORT
      LAYER metal6 ;
        RECT 1046.105 0.000 1046.245 0.560 ;
    END
  END lsu_ifu_icache_index[3]
  PIN lsu_ifu_icache_index[4]
    DIRECTION INPUT ;
    USE SIGNAL ;
    PORT
      LAYER metal4 ;
        RECT 1046.105 0.000 1046.245 0.560 ;
    END
  END lsu_ifu_icache_index[4]
  PIN lsu_ifu_icache_index[5]
    DIRECTION INPUT ;
    USE SIGNAL ;
    PORT
      LAYER metal6 ;
        RECT 1044.985 0.000 1045.125 0.560 ;
    END
  END lsu_ifu_icache_index[5]
  PIN lsu_ifu_icache_line_inv
    DIRECTION INPUT ;
    USE SIGNAL ;
    PORT
      LAYER metal6 ;
        RECT 1048.345 0.000 1048.485 0.560 ;
    END
  END lsu_ifu_icache_line_inv
  PIN lsu_ifu_icache_ptag[0]
    DIRECTION INPUT ;
    USE SIGNAL ;
    PORT
      LAYER metal6 ;
        RECT 1064.025 0.000 1064.165 0.560 ;
    END
  END lsu_ifu_icache_ptag[0]
  PIN lsu_ifu_icache_ptag[10]
    DIRECTION INPUT ;
    USE SIGNAL ;
    PORT
      LAYER metal6 ;
        RECT 1058.425 0.000 1058.565 0.560 ;
    END
  END lsu_ifu_icache_ptag[10]
  PIN lsu_ifu_icache_ptag[11]
    DIRECTION INPUT ;
    USE SIGNAL ;
    PORT
      LAYER metal4 ;
        RECT 1058.425 0.000 1058.565 0.560 ;
    END
  END lsu_ifu_icache_ptag[11]
  PIN lsu_ifu_icache_ptag[12]
    DIRECTION INPUT ;
    USE SIGNAL ;
    PORT
      LAYER metal6 ;
        RECT 1057.305 0.000 1057.445 0.560 ;
    END
  END lsu_ifu_icache_ptag[12]
  PIN lsu_ifu_icache_ptag[13]
    DIRECTION INPUT ;
    USE SIGNAL ;
    PORT
      LAYER metal4 ;
        RECT 1057.305 0.000 1057.445 0.560 ;
    END
  END lsu_ifu_icache_ptag[13]
  PIN lsu_ifu_icache_ptag[14]
    DIRECTION INPUT ;
    USE SIGNAL ;
    PORT
      LAYER metal6 ;
        RECT 1056.185 0.000 1056.325 0.560 ;
    END
  END lsu_ifu_icache_ptag[14]
  PIN lsu_ifu_icache_ptag[15]
    DIRECTION INPUT ;
    USE SIGNAL ;
    PORT
      LAYER metal4 ;
        RECT 1056.185 0.000 1056.325 0.560 ;
    END
  END lsu_ifu_icache_ptag[15]
  PIN lsu_ifu_icache_ptag[16]
    DIRECTION INPUT ;
    USE SIGNAL ;
    PORT
      LAYER metal6 ;
        RECT 1055.065 0.000 1055.205 0.560 ;
    END
  END lsu_ifu_icache_ptag[16]
  PIN lsu_ifu_icache_ptag[17]
    DIRECTION INPUT ;
    USE SIGNAL ;
    PORT
      LAYER metal4 ;
        RECT 1055.065 0.000 1055.205 0.560 ;
    END
  END lsu_ifu_icache_ptag[17]
  PIN lsu_ifu_icache_ptag[18]
    DIRECTION INPUT ;
    USE SIGNAL ;
    PORT
      LAYER metal6 ;
        RECT 1053.945 0.000 1054.085 0.560 ;
    END
  END lsu_ifu_icache_ptag[18]
  PIN lsu_ifu_icache_ptag[19]
    DIRECTION INPUT ;
    USE SIGNAL ;
    PORT
      LAYER metal4 ;
        RECT 1053.945 0.000 1054.085 0.560 ;
    END
  END lsu_ifu_icache_ptag[19]
  PIN lsu_ifu_icache_ptag[1]
    DIRECTION INPUT ;
    USE SIGNAL ;
    PORT
      LAYER metal4 ;
        RECT 1064.025 0.000 1064.165 0.560 ;
    END
  END lsu_ifu_icache_ptag[1]
  PIN lsu_ifu_icache_ptag[20]
    DIRECTION INPUT ;
    USE SIGNAL ;
    PORT
      LAYER metal6 ;
        RECT 1052.825 0.000 1052.965 0.560 ;
    END
  END lsu_ifu_icache_ptag[20]
  PIN lsu_ifu_icache_ptag[21]
    DIRECTION INPUT ;
    USE SIGNAL ;
    PORT
      LAYER metal4 ;
        RECT 1052.825 0.000 1052.965 0.560 ;
    END
  END lsu_ifu_icache_ptag[21]
  PIN lsu_ifu_icache_ptag[22]
    DIRECTION INPUT ;
    USE SIGNAL ;
    PORT
      LAYER metal6 ;
        RECT 1051.705 0.000 1051.845 0.560 ;
    END
  END lsu_ifu_icache_ptag[22]
  PIN lsu_ifu_icache_ptag[23]
    DIRECTION INPUT ;
    USE SIGNAL ;
    PORT
      LAYER metal4 ;
        RECT 1051.705 0.000 1051.845 0.560 ;
    END
  END lsu_ifu_icache_ptag[23]
  PIN lsu_ifu_icache_ptag[24]
    DIRECTION INPUT ;
    USE SIGNAL ;
    PORT
      LAYER metal6 ;
        RECT 1050.585 0.000 1050.725 0.560 ;
    END
  END lsu_ifu_icache_ptag[24]
  PIN lsu_ifu_icache_ptag[25]
    DIRECTION INPUT ;
    USE SIGNAL ;
    PORT
      LAYER metal4 ;
        RECT 1050.585 0.000 1050.725 0.560 ;
    END
  END lsu_ifu_icache_ptag[25]
  PIN lsu_ifu_icache_ptag[26]
    DIRECTION INPUT ;
    USE SIGNAL ;
    PORT
      LAYER metal6 ;
        RECT 1049.465 0.000 1049.605 0.560 ;
    END
  END lsu_ifu_icache_ptag[26]
  PIN lsu_ifu_icache_ptag[27]
    DIRECTION INPUT ;
    USE SIGNAL ;
    PORT
      LAYER metal4 ;
        RECT 1049.465 0.000 1049.605 0.560 ;
    END
  END lsu_ifu_icache_ptag[27]
  PIN lsu_ifu_icache_ptag[2]
    DIRECTION INPUT ;
    USE SIGNAL ;
    PORT
      LAYER metal6 ;
        RECT 1062.905 0.000 1063.045 0.560 ;
    END
  END lsu_ifu_icache_ptag[2]
  PIN lsu_ifu_icache_ptag[3]
    DIRECTION INPUT ;
    USE SIGNAL ;
    PORT
      LAYER metal4 ;
        RECT 1062.905 0.000 1063.045 0.560 ;
    END
  END lsu_ifu_icache_ptag[3]
  PIN lsu_ifu_icache_ptag[4]
    DIRECTION INPUT ;
    USE SIGNAL ;
    PORT
      LAYER metal6 ;
        RECT 1061.785 0.000 1061.925 0.560 ;
    END
  END lsu_ifu_icache_ptag[4]
  PIN lsu_ifu_icache_ptag[5]
    DIRECTION INPUT ;
    USE SIGNAL ;
    PORT
      LAYER metal4 ;
        RECT 1061.785 0.000 1061.925 0.560 ;
    END
  END lsu_ifu_icache_ptag[5]
  PIN lsu_ifu_icache_ptag[6]
    DIRECTION INPUT ;
    USE SIGNAL ;
    PORT
      LAYER metal6 ;
        RECT 1060.665 0.000 1060.805 0.560 ;
    END
  END lsu_ifu_icache_ptag[6]
  PIN lsu_ifu_icache_ptag[7]
    DIRECTION INPUT ;
    USE SIGNAL ;
    PORT
      LAYER metal4 ;
        RECT 1060.665 0.000 1060.805 0.560 ;
    END
  END lsu_ifu_icache_ptag[7]
  PIN lsu_ifu_icache_ptag[8]
    DIRECTION INPUT ;
    USE SIGNAL ;
    PORT
      LAYER metal6 ;
        RECT 1059.545 0.000 1059.685 0.560 ;
    END
  END lsu_ifu_icache_ptag[8]
  PIN lsu_ifu_icache_ptag[9]
    DIRECTION INPUT ;
    USE SIGNAL ;
    PORT
      LAYER metal4 ;
        RECT 1059.545 0.000 1059.685 0.560 ;
    END
  END lsu_ifu_icache_ptag[9]
  PIN mmu_ifu_buf
    DIRECTION INPUT ;
    USE SIGNAL ;
    PORT
      LAYER metal4 ;
        RECT 1065.145 0.000 1065.285 0.560 ;
    END
  END mmu_ifu_buf
  PIN mmu_ifu_ca
    DIRECTION INPUT ;
    USE SIGNAL ;
    PORT
      LAYER metal6 ;
        RECT 1065.145 0.000 1065.285 0.560 ;
    END
  END mmu_ifu_ca
  PIN mmu_ifu_deny
    DIRECTION INPUT ;
    USE SIGNAL ;
    PORT
      LAYER metal4 ;
        RECT 1066.265 0.000 1066.405 0.560 ;
    END
  END mmu_ifu_deny
  PIN mmu_ifu_pa[0]
    DIRECTION INPUT ;
    USE SIGNAL ;
    PORT
      LAYER metal4 ;
        RECT 1081.945 0.000 1082.085 0.560 ;
    END
  END mmu_ifu_pa[0]
  PIN mmu_ifu_pa[10]
    DIRECTION INPUT ;
    USE SIGNAL ;
    PORT
      LAYER metal4 ;
        RECT 1076.345 0.000 1076.485 0.560 ;
    END
  END mmu_ifu_pa[10]
  PIN mmu_ifu_pa[11]
    DIRECTION INPUT ;
    USE SIGNAL ;
    PORT
      LAYER metal6 ;
        RECT 1075.225 0.000 1075.365 0.560 ;
    END
  END mmu_ifu_pa[11]
  PIN mmu_ifu_pa[12]
    DIRECTION INPUT ;
    USE SIGNAL ;
    PORT
      LAYER metal4 ;
        RECT 1075.225 0.000 1075.365 0.560 ;
    END
  END mmu_ifu_pa[12]
  PIN mmu_ifu_pa[13]
    DIRECTION INPUT ;
    USE SIGNAL ;
    PORT
      LAYER metal6 ;
        RECT 1074.105 0.000 1074.245 0.560 ;
    END
  END mmu_ifu_pa[13]
  PIN mmu_ifu_pa[14]
    DIRECTION INPUT ;
    USE SIGNAL ;
    PORT
      LAYER metal4 ;
        RECT 1074.105 0.000 1074.245 0.560 ;
    END
  END mmu_ifu_pa[14]
  PIN mmu_ifu_pa[15]
    DIRECTION INPUT ;
    USE SIGNAL ;
    PORT
      LAYER metal6 ;
        RECT 1072.985 0.000 1073.125 0.560 ;
    END
  END mmu_ifu_pa[15]
  PIN mmu_ifu_pa[16]
    DIRECTION INPUT ;
    USE SIGNAL ;
    PORT
      LAYER metal4 ;
        RECT 1072.985 0.000 1073.125 0.560 ;
    END
  END mmu_ifu_pa[16]
  PIN mmu_ifu_pa[17]
    DIRECTION INPUT ;
    USE SIGNAL ;
    PORT
      LAYER metal6 ;
        RECT 1071.865 0.000 1072.005 0.560 ;
    END
  END mmu_ifu_pa[17]
  PIN mmu_ifu_pa[18]
    DIRECTION INPUT ;
    USE SIGNAL ;
    PORT
      LAYER metal4 ;
        RECT 1071.865 0.000 1072.005 0.560 ;
    END
  END mmu_ifu_pa[18]
  PIN mmu_ifu_pa[19]
    DIRECTION INPUT ;
    USE SIGNAL ;
    PORT
      LAYER metal6 ;
        RECT 1070.745 0.000 1070.885 0.560 ;
    END
  END mmu_ifu_pa[19]
  PIN mmu_ifu_pa[1]
    DIRECTION INPUT ;
    USE SIGNAL ;
    PORT
      LAYER metal6 ;
        RECT 1080.825 0.000 1080.965 0.560 ;
    END
  END mmu_ifu_pa[1]
  PIN mmu_ifu_pa[20]
    DIRECTION INPUT ;
    USE SIGNAL ;
    PORT
      LAYER metal4 ;
        RECT 1070.745 0.000 1070.885 0.560 ;
    END
  END mmu_ifu_pa[20]
  PIN mmu_ifu_pa[21]
    DIRECTION INPUT ;
    USE SIGNAL ;
    PORT
      LAYER metal6 ;
        RECT 1069.625 0.000 1069.765 0.560 ;
    END
  END mmu_ifu_pa[21]
  PIN mmu_ifu_pa[22]
    DIRECTION INPUT ;
    USE SIGNAL ;
    PORT
      LAYER metal4 ;
        RECT 1069.625 0.000 1069.765 0.560 ;
    END
  END mmu_ifu_pa[22]
  PIN mmu_ifu_pa[23]
    DIRECTION INPUT ;
    USE SIGNAL ;
    PORT
      LAYER metal6 ;
        RECT 1068.505 0.000 1068.645 0.560 ;
    END
  END mmu_ifu_pa[23]
  PIN mmu_ifu_pa[24]
    DIRECTION INPUT ;
    USE SIGNAL ;
    PORT
      LAYER metal4 ;
        RECT 1068.505 0.000 1068.645 0.560 ;
    END
  END mmu_ifu_pa[24]
  PIN mmu_ifu_pa[25]
    DIRECTION INPUT ;
    USE SIGNAL ;
    PORT
      LAYER metal6 ;
        RECT 1067.385 0.000 1067.525 0.560 ;
    END
  END mmu_ifu_pa[25]
  PIN mmu_ifu_pa[26]
    DIRECTION INPUT ;
    USE SIGNAL ;
    PORT
      LAYER metal4 ;
        RECT 1067.385 0.000 1067.525 0.560 ;
    END
  END mmu_ifu_pa[26]
  PIN mmu_ifu_pa[27]
    DIRECTION INPUT ;
    USE SIGNAL ;
    PORT
      LAYER metal6 ;
        RECT 1066.265 0.000 1066.405 0.560 ;
    END
  END mmu_ifu_pa[27]
  PIN mmu_ifu_pa[2]
    DIRECTION INPUT ;
    USE SIGNAL ;
    PORT
      LAYER metal4 ;
        RECT 1080.825 0.000 1080.965 0.560 ;
    END
  END mmu_ifu_pa[2]
  PIN mmu_ifu_pa[3]
    DIRECTION INPUT ;
    USE SIGNAL ;
    PORT
      LAYER metal6 ;
        RECT 1079.705 0.000 1079.845 0.560 ;
    END
  END mmu_ifu_pa[3]
  PIN mmu_ifu_pa[4]
    DIRECTION INPUT ;
    USE SIGNAL ;
    PORT
      LAYER metal4 ;
        RECT 1079.705 0.000 1079.845 0.560 ;
    END
  END mmu_ifu_pa[4]
  PIN mmu_ifu_pa[5]
    DIRECTION INPUT ;
    USE SIGNAL ;
    PORT
      LAYER metal6 ;
        RECT 1078.585 0.000 1078.725 0.560 ;
    END
  END mmu_ifu_pa[5]
  PIN mmu_ifu_pa[6]
    DIRECTION INPUT ;
    USE SIGNAL ;
    PORT
      LAYER metal4 ;
        RECT 1078.585 0.000 1078.725 0.560 ;
    END
  END mmu_ifu_pa[6]
  PIN mmu_ifu_pa[7]
    DIRECTION INPUT ;
    USE SIGNAL ;
    PORT
      LAYER metal6 ;
        RECT 1077.465 0.000 1077.605 0.560 ;
    END
  END mmu_ifu_pa[7]
  PIN mmu_ifu_pa[8]
    DIRECTION INPUT ;
    USE SIGNAL ;
    PORT
      LAYER metal4 ;
        RECT 1077.465 0.000 1077.605 0.560 ;
    END
  END mmu_ifu_pa[8]
  PIN mmu_ifu_pa[9]
    DIRECTION INPUT ;
    USE SIGNAL ;
    PORT
      LAYER metal6 ;
        RECT 1076.345 0.000 1076.485 0.560 ;
    END
  END mmu_ifu_pa[9]
  PIN mmu_ifu_pavld
    DIRECTION INPUT ;
    USE SIGNAL ;
    PORT
      LAYER metal6 ;
        RECT 1081.945 0.000 1082.085 0.560 ;
    END
  END mmu_ifu_pavld
  PIN mmu_ifu_pgflt
    DIRECTION INPUT ;
    USE SIGNAL ;
    PORT
      LAYER metal4 ;
        RECT 1083.065 0.000 1083.205 0.560 ;
    END
  END mmu_ifu_pgflt
  PIN mmu_ifu_sec
    DIRECTION INPUT ;
    USE SIGNAL ;
    PORT
      LAYER metal6 ;
        RECT 1083.065 0.000 1083.205 0.560 ;
    END
  END mmu_ifu_sec
  PIN mmu_xx_mmu_en
    DIRECTION INPUT ;
    USE SIGNAL ;
    PORT
      LAYER metal4 ;
        RECT 1084.185 0.000 1084.325 0.560 ;
    END
  END mmu_xx_mmu_en
  PIN pad_yy_icg_scan_en
    DIRECTION INPUT ;
    USE SIGNAL ;
    PORT
      LAYER metal4 ;
        RECT 1327.785 0.000 1327.925 0.560 ;
    END
  END pad_yy_icg_scan_en
  PIN rtu_ifu_chgflw_pc[0]
    DIRECTION INPUT ;
    USE SIGNAL ;
    PORT
      LAYER metal6 ;
        RECT 1105.465 0.000 1105.605 0.560 ;
    END
  END rtu_ifu_chgflw_pc[0]
  PIN rtu_ifu_chgflw_pc[10]
    DIRECTION INPUT ;
    USE SIGNAL ;
    PORT
      LAYER metal6 ;
        RECT 1099.865 0.000 1100.005 0.560 ;
    END
  END rtu_ifu_chgflw_pc[10]
  PIN rtu_ifu_chgflw_pc[11]
    DIRECTION INPUT ;
    USE SIGNAL ;
    PORT
      LAYER metal4 ;
        RECT 1099.865 0.000 1100.005 0.560 ;
    END
  END rtu_ifu_chgflw_pc[11]
  PIN rtu_ifu_chgflw_pc[12]
    DIRECTION INPUT ;
    USE SIGNAL ;
    PORT
      LAYER metal6 ;
        RECT 1098.745 0.000 1098.885 0.560 ;
    END
  END rtu_ifu_chgflw_pc[12]
  PIN rtu_ifu_chgflw_pc[13]
    DIRECTION INPUT ;
    USE SIGNAL ;
    PORT
      LAYER metal4 ;
        RECT 1098.745 0.000 1098.885 0.560 ;
    END
  END rtu_ifu_chgflw_pc[13]
  PIN rtu_ifu_chgflw_pc[14]
    DIRECTION INPUT ;
    USE SIGNAL ;
    PORT
      LAYER metal6 ;
        RECT 1097.625 0.000 1097.765 0.560 ;
    END
  END rtu_ifu_chgflw_pc[14]
  PIN rtu_ifu_chgflw_pc[15]
    DIRECTION INPUT ;
    USE SIGNAL ;
    PORT
      LAYER metal4 ;
        RECT 1097.625 0.000 1097.765 0.560 ;
    END
  END rtu_ifu_chgflw_pc[15]
  PIN rtu_ifu_chgflw_pc[16]
    DIRECTION INPUT ;
    USE SIGNAL ;
    PORT
      LAYER metal6 ;
        RECT 1096.505 0.000 1096.645 0.560 ;
    END
  END rtu_ifu_chgflw_pc[16]
  PIN rtu_ifu_chgflw_pc[17]
    DIRECTION INPUT ;
    USE SIGNAL ;
    PORT
      LAYER metal4 ;
        RECT 1096.505 0.000 1096.645 0.560 ;
    END
  END rtu_ifu_chgflw_pc[17]
  PIN rtu_ifu_chgflw_pc[18]
    DIRECTION INPUT ;
    USE SIGNAL ;
    PORT
      LAYER metal6 ;
        RECT 1095.385 0.000 1095.525 0.560 ;
    END
  END rtu_ifu_chgflw_pc[18]
  PIN rtu_ifu_chgflw_pc[19]
    DIRECTION INPUT ;
    USE SIGNAL ;
    PORT
      LAYER metal4 ;
        RECT 1095.385 0.000 1095.525 0.560 ;
    END
  END rtu_ifu_chgflw_pc[19]
  PIN rtu_ifu_chgflw_pc[1]
    DIRECTION INPUT ;
    USE SIGNAL ;
    PORT
      LAYER metal4 ;
        RECT 1105.465 0.000 1105.605 0.560 ;
    END
  END rtu_ifu_chgflw_pc[1]
  PIN rtu_ifu_chgflw_pc[20]
    DIRECTION INPUT ;
    USE SIGNAL ;
    PORT
      LAYER metal6 ;
        RECT 1094.265 0.000 1094.405 0.560 ;
    END
  END rtu_ifu_chgflw_pc[20]
  PIN rtu_ifu_chgflw_pc[21]
    DIRECTION INPUT ;
    USE SIGNAL ;
    PORT
      LAYER metal4 ;
        RECT 1094.265 0.000 1094.405 0.560 ;
    END
  END rtu_ifu_chgflw_pc[21]
  PIN rtu_ifu_chgflw_pc[22]
    DIRECTION INPUT ;
    USE SIGNAL ;
    PORT
      LAYER metal6 ;
        RECT 1093.145 0.000 1093.285 0.560 ;
    END
  END rtu_ifu_chgflw_pc[22]
  PIN rtu_ifu_chgflw_pc[23]
    DIRECTION INPUT ;
    USE SIGNAL ;
    PORT
      LAYER metal4 ;
        RECT 1093.145 0.000 1093.285 0.560 ;
    END
  END rtu_ifu_chgflw_pc[23]
  PIN rtu_ifu_chgflw_pc[24]
    DIRECTION INPUT ;
    USE SIGNAL ;
    PORT
      LAYER metal6 ;
        RECT 1092.025 0.000 1092.165 0.560 ;
    END
  END rtu_ifu_chgflw_pc[24]
  PIN rtu_ifu_chgflw_pc[25]
    DIRECTION INPUT ;
    USE SIGNAL ;
    PORT
      LAYER metal4 ;
        RECT 1092.025 0.000 1092.165 0.560 ;
    END
  END rtu_ifu_chgflw_pc[25]
  PIN rtu_ifu_chgflw_pc[26]
    DIRECTION INPUT ;
    USE SIGNAL ;
    PORT
      LAYER metal6 ;
        RECT 1090.905 0.000 1091.045 0.560 ;
    END
  END rtu_ifu_chgflw_pc[26]
  PIN rtu_ifu_chgflw_pc[27]
    DIRECTION INPUT ;
    USE SIGNAL ;
    PORT
      LAYER metal4 ;
        RECT 1090.905 0.000 1091.045 0.560 ;
    END
  END rtu_ifu_chgflw_pc[27]
  PIN rtu_ifu_chgflw_pc[28]
    DIRECTION INPUT ;
    USE SIGNAL ;
    PORT
      LAYER metal6 ;
        RECT 1089.785 0.000 1089.925 0.560 ;
    END
  END rtu_ifu_chgflw_pc[28]
  PIN rtu_ifu_chgflw_pc[29]
    DIRECTION INPUT ;
    USE SIGNAL ;
    PORT
      LAYER metal4 ;
        RECT 1089.785 0.000 1089.925 0.560 ;
    END
  END rtu_ifu_chgflw_pc[29]
  PIN rtu_ifu_chgflw_pc[2]
    DIRECTION INPUT ;
    USE SIGNAL ;
    PORT
      LAYER metal6 ;
        RECT 1104.345 0.000 1104.485 0.560 ;
    END
  END rtu_ifu_chgflw_pc[2]
  PIN rtu_ifu_chgflw_pc[30]
    DIRECTION INPUT ;
    USE SIGNAL ;
    PORT
      LAYER metal6 ;
        RECT 1088.665 0.000 1088.805 0.560 ;
    END
  END rtu_ifu_chgflw_pc[30]
  PIN rtu_ifu_chgflw_pc[31]
    DIRECTION INPUT ;
    USE SIGNAL ;
    PORT
      LAYER metal4 ;
        RECT 1088.665 0.000 1088.805 0.560 ;
    END
  END rtu_ifu_chgflw_pc[31]
  PIN rtu_ifu_chgflw_pc[32]
    DIRECTION INPUT ;
    USE SIGNAL ;
    PORT
      LAYER metal6 ;
        RECT 1087.545 0.000 1087.685 0.560 ;
    END
  END rtu_ifu_chgflw_pc[32]
  PIN rtu_ifu_chgflw_pc[33]
    DIRECTION INPUT ;
    USE SIGNAL ;
    PORT
      LAYER metal4 ;
        RECT 1087.545 0.000 1087.685 0.560 ;
    END
  END rtu_ifu_chgflw_pc[33]
  PIN rtu_ifu_chgflw_pc[34]
    DIRECTION INPUT ;
    USE SIGNAL ;
    PORT
      LAYER metal6 ;
        RECT 1086.425 0.000 1086.565 0.560 ;
    END
  END rtu_ifu_chgflw_pc[34]
  PIN rtu_ifu_chgflw_pc[35]
    DIRECTION INPUT ;
    USE SIGNAL ;
    PORT
      LAYER metal4 ;
        RECT 1086.425 0.000 1086.565 0.560 ;
    END
  END rtu_ifu_chgflw_pc[35]
  PIN rtu_ifu_chgflw_pc[36]
    DIRECTION INPUT ;
    USE SIGNAL ;
    PORT
      LAYER metal6 ;
        RECT 1085.305 0.000 1085.445 0.560 ;
    END
  END rtu_ifu_chgflw_pc[36]
  PIN rtu_ifu_chgflw_pc[37]
    DIRECTION INPUT ;
    USE SIGNAL ;
    PORT
      LAYER metal4 ;
        RECT 1085.305 0.000 1085.445 0.560 ;
    END
  END rtu_ifu_chgflw_pc[37]
  PIN rtu_ifu_chgflw_pc[38]
    DIRECTION INPUT ;
    USE SIGNAL ;
    PORT
      LAYER metal6 ;
        RECT 1084.185 0.000 1084.325 0.560 ;
    END
  END rtu_ifu_chgflw_pc[38]
  PIN rtu_ifu_chgflw_pc[3]
    DIRECTION INPUT ;
    USE SIGNAL ;
    PORT
      LAYER metal4 ;
        RECT 1104.345 0.000 1104.485 0.560 ;
    END
  END rtu_ifu_chgflw_pc[3]
  PIN rtu_ifu_chgflw_pc[4]
    DIRECTION INPUT ;
    USE SIGNAL ;
    PORT
      LAYER metal6 ;
        RECT 1103.225 0.000 1103.365 0.560 ;
    END
  END rtu_ifu_chgflw_pc[4]
  PIN rtu_ifu_chgflw_pc[5]
    DIRECTION INPUT ;
    USE SIGNAL ;
    PORT
      LAYER metal4 ;
        RECT 1103.225 0.000 1103.365 0.560 ;
    END
  END rtu_ifu_chgflw_pc[5]
  PIN rtu_ifu_chgflw_pc[6]
    DIRECTION INPUT ;
    USE SIGNAL ;
    PORT
      LAYER metal6 ;
        RECT 1102.105 0.000 1102.245 0.560 ;
    END
  END rtu_ifu_chgflw_pc[6]
  PIN rtu_ifu_chgflw_pc[7]
    DIRECTION INPUT ;
    USE SIGNAL ;
    PORT
      LAYER metal4 ;
        RECT 1102.105 0.000 1102.245 0.560 ;
    END
  END rtu_ifu_chgflw_pc[7]
  PIN rtu_ifu_chgflw_pc[8]
    DIRECTION INPUT ;
    USE SIGNAL ;
    PORT
      LAYER metal6 ;
        RECT 1100.985 0.000 1101.125 0.560 ;
    END
  END rtu_ifu_chgflw_pc[8]
  PIN rtu_ifu_chgflw_pc[9]
    DIRECTION INPUT ;
    USE SIGNAL ;
    PORT
      LAYER metal4 ;
        RECT 1100.985 0.000 1101.125 0.560 ;
    END
  END rtu_ifu_chgflw_pc[9]
  PIN rtu_ifu_chgflw_vld
    DIRECTION INPUT ;
    USE SIGNAL ;
    PORT
      LAYER metal4 ;
        RECT 1106.585 0.000 1106.725 0.560 ;
    END
  END rtu_ifu_chgflw_vld
  PIN rtu_ifu_flush
    DIRECTION INPUT ;
    USE SIGNAL ;
    PORT
      LAYER metal6 ;
        RECT 1106.585 0.000 1106.725 0.560 ;
    END
  END rtu_ifu_flush
  PIN rtu_ifu_retire0_chk_idx[0]
    DIRECTION INPUT ;
    USE SIGNAL ;
    PORT
      LAYER metal6 ;
        RECT 1111.065 0.000 1111.205 0.560 ;
    END
  END rtu_ifu_retire0_chk_idx[0]
  PIN rtu_ifu_retire0_chk_idx[1]
    DIRECTION INPUT ;
    USE SIGNAL ;
    PORT
      LAYER metal4 ;
        RECT 1111.065 0.000 1111.205 0.560 ;
    END
  END rtu_ifu_retire0_chk_idx[1]
  PIN rtu_ifu_retire0_chk_idx[2]
    DIRECTION INPUT ;
    USE SIGNAL ;
    PORT
      LAYER metal6 ;
        RECT 1109.945 0.000 1110.085 0.560 ;
    END
  END rtu_ifu_retire0_chk_idx[2]
  PIN rtu_ifu_retire0_chk_idx[3]
    DIRECTION INPUT ;
    USE SIGNAL ;
    PORT
      LAYER metal4 ;
        RECT 1109.945 0.000 1110.085 0.560 ;
    END
  END rtu_ifu_retire0_chk_idx[3]
  PIN rtu_ifu_retire0_chk_idx[4]
    DIRECTION INPUT ;
    USE SIGNAL ;
    PORT
      LAYER metal6 ;
        RECT 1108.825 0.000 1108.965 0.560 ;
    END
  END rtu_ifu_retire0_chk_idx[4]
  PIN rtu_ifu_retire0_chk_idx[5]
    DIRECTION INPUT ;
    USE SIGNAL ;
    PORT
      LAYER metal4 ;
        RECT 1108.825 0.000 1108.965 0.560 ;
    END
  END rtu_ifu_retire0_chk_idx[5]
  PIN rtu_ifu_retire0_chk_idx[6]
    DIRECTION INPUT ;
    USE SIGNAL ;
    PORT
      LAYER metal6 ;
        RECT 1107.705 0.000 1107.845 0.560 ;
    END
  END rtu_ifu_retire0_chk_idx[6]
  PIN rtu_ifu_retire0_chk_idx[7]
    DIRECTION INPUT ;
    USE SIGNAL ;
    PORT
      LAYER metal4 ;
        RECT 1107.705 0.000 1107.845 0.560 ;
    END
  END rtu_ifu_retire0_chk_idx[7]
  PIN rtu_ifu_retire0_condbr
    DIRECTION INPUT ;
    USE SIGNAL ;
    PORT
      LAYER metal4 ;
        RECT 1112.185 0.000 1112.325 0.560 ;
    END
  END rtu_ifu_retire0_condbr
  PIN rtu_ifu_retire0_condbr_taken
    DIRECTION INPUT ;
    USE SIGNAL ;
    PORT
      LAYER metal6 ;
        RECT 1112.185 0.000 1112.325 0.560 ;
    END
  END rtu_ifu_retire0_condbr_taken
  PIN rtu_ifu_retire0_inc_pc[0]
    DIRECTION INPUT ;
    USE SIGNAL ;
    PORT
      LAYER metal4 ;
        RECT 1134.585 0.000 1134.725 0.560 ;
    END
  END rtu_ifu_retire0_inc_pc[0]
  PIN rtu_ifu_retire0_inc_pc[10]
    DIRECTION INPUT ;
    USE SIGNAL ;
    PORT
      LAYER metal4 ;
        RECT 1128.985 0.000 1129.125 0.560 ;
    END
  END rtu_ifu_retire0_inc_pc[10]
  PIN rtu_ifu_retire0_inc_pc[11]
    DIRECTION INPUT ;
    USE SIGNAL ;
    PORT
      LAYER metal6 ;
        RECT 1127.865 0.000 1128.005 0.560 ;
    END
  END rtu_ifu_retire0_inc_pc[11]
  PIN rtu_ifu_retire0_inc_pc[12]
    DIRECTION INPUT ;
    USE SIGNAL ;
    PORT
      LAYER metal4 ;
        RECT 1127.865 0.000 1128.005 0.560 ;
    END
  END rtu_ifu_retire0_inc_pc[12]
  PIN rtu_ifu_retire0_inc_pc[13]
    DIRECTION INPUT ;
    USE SIGNAL ;
    PORT
      LAYER metal6 ;
        RECT 1126.745 0.000 1126.885 0.560 ;
    END
  END rtu_ifu_retire0_inc_pc[13]
  PIN rtu_ifu_retire0_inc_pc[14]
    DIRECTION INPUT ;
    USE SIGNAL ;
    PORT
      LAYER metal4 ;
        RECT 1126.745 0.000 1126.885 0.560 ;
    END
  END rtu_ifu_retire0_inc_pc[14]
  PIN rtu_ifu_retire0_inc_pc[15]
    DIRECTION INPUT ;
    USE SIGNAL ;
    PORT
      LAYER metal6 ;
        RECT 1125.625 0.000 1125.765 0.560 ;
    END
  END rtu_ifu_retire0_inc_pc[15]
  PIN rtu_ifu_retire0_inc_pc[16]
    DIRECTION INPUT ;
    USE SIGNAL ;
    PORT
      LAYER metal4 ;
        RECT 1125.625 0.000 1125.765 0.560 ;
    END
  END rtu_ifu_retire0_inc_pc[16]
  PIN rtu_ifu_retire0_inc_pc[17]
    DIRECTION INPUT ;
    USE SIGNAL ;
    PORT
      LAYER metal6 ;
        RECT 1124.505 0.000 1124.645 0.560 ;
    END
  END rtu_ifu_retire0_inc_pc[17]
  PIN rtu_ifu_retire0_inc_pc[18]
    DIRECTION INPUT ;
    USE SIGNAL ;
    PORT
      LAYER metal4 ;
        RECT 1124.505 0.000 1124.645 0.560 ;
    END
  END rtu_ifu_retire0_inc_pc[18]
  PIN rtu_ifu_retire0_inc_pc[19]
    DIRECTION INPUT ;
    USE SIGNAL ;
    PORT
      LAYER metal6 ;
        RECT 1123.385 0.000 1123.525 0.560 ;
    END
  END rtu_ifu_retire0_inc_pc[19]
  PIN rtu_ifu_retire0_inc_pc[1]
    DIRECTION INPUT ;
    USE SIGNAL ;
    PORT
      LAYER metal6 ;
        RECT 1133.465 0.000 1133.605 0.560 ;
    END
  END rtu_ifu_retire0_inc_pc[1]
  PIN rtu_ifu_retire0_inc_pc[20]
    DIRECTION INPUT ;
    USE SIGNAL ;
    PORT
      LAYER metal4 ;
        RECT 1123.385 0.000 1123.525 0.560 ;
    END
  END rtu_ifu_retire0_inc_pc[20]
  PIN rtu_ifu_retire0_inc_pc[21]
    DIRECTION INPUT ;
    USE SIGNAL ;
    PORT
      LAYER metal6 ;
        RECT 1122.265 0.000 1122.405 0.560 ;
    END
  END rtu_ifu_retire0_inc_pc[21]
  PIN rtu_ifu_retire0_inc_pc[22]
    DIRECTION INPUT ;
    USE SIGNAL ;
    PORT
      LAYER metal4 ;
        RECT 1122.265 0.000 1122.405 0.560 ;
    END
  END rtu_ifu_retire0_inc_pc[22]
  PIN rtu_ifu_retire0_inc_pc[23]
    DIRECTION INPUT ;
    USE SIGNAL ;
    PORT
      LAYER metal6 ;
        RECT 1121.145 0.000 1121.285 0.560 ;
    END
  END rtu_ifu_retire0_inc_pc[23]
  PIN rtu_ifu_retire0_inc_pc[24]
    DIRECTION INPUT ;
    USE SIGNAL ;
    PORT
      LAYER metal4 ;
        RECT 1121.145 0.000 1121.285 0.560 ;
    END
  END rtu_ifu_retire0_inc_pc[24]
  PIN rtu_ifu_retire0_inc_pc[25]
    DIRECTION INPUT ;
    USE SIGNAL ;
    PORT
      LAYER metal6 ;
        RECT 1120.025 0.000 1120.165 0.560 ;
    END
  END rtu_ifu_retire0_inc_pc[25]
  PIN rtu_ifu_retire0_inc_pc[26]
    DIRECTION INPUT ;
    USE SIGNAL ;
    PORT
      LAYER metal4 ;
        RECT 1120.025 0.000 1120.165 0.560 ;
    END
  END rtu_ifu_retire0_inc_pc[26]
  PIN rtu_ifu_retire0_inc_pc[27]
    DIRECTION INPUT ;
    USE SIGNAL ;
    PORT
      LAYER metal6 ;
        RECT 1118.905 0.000 1119.045 0.560 ;
    END
  END rtu_ifu_retire0_inc_pc[27]
  PIN rtu_ifu_retire0_inc_pc[28]
    DIRECTION INPUT ;
    USE SIGNAL ;
    PORT
      LAYER metal4 ;
        RECT 1118.905 0.000 1119.045 0.560 ;
    END
  END rtu_ifu_retire0_inc_pc[28]
  PIN rtu_ifu_retire0_inc_pc[29]
    DIRECTION INPUT ;
    USE SIGNAL ;
    PORT
      LAYER metal6 ;
        RECT 1117.785 0.000 1117.925 0.560 ;
    END
  END rtu_ifu_retire0_inc_pc[29]
  PIN rtu_ifu_retire0_inc_pc[2]
    DIRECTION INPUT ;
    USE SIGNAL ;
    PORT
      LAYER metal4 ;
        RECT 1133.465 0.000 1133.605 0.560 ;
    END
  END rtu_ifu_retire0_inc_pc[2]
  PIN rtu_ifu_retire0_inc_pc[30]
    DIRECTION INPUT ;
    USE SIGNAL ;
    PORT
      LAYER metal4 ;
        RECT 1117.785 0.000 1117.925 0.560 ;
    END
  END rtu_ifu_retire0_inc_pc[30]
  PIN rtu_ifu_retire0_inc_pc[31]
    DIRECTION INPUT ;
    USE SIGNAL ;
    PORT
      LAYER metal6 ;
        RECT 1116.665 0.000 1116.805 0.560 ;
    END
  END rtu_ifu_retire0_inc_pc[31]
  PIN rtu_ifu_retire0_inc_pc[32]
    DIRECTION INPUT ;
    USE SIGNAL ;
    PORT
      LAYER metal4 ;
        RECT 1116.665 0.000 1116.805 0.560 ;
    END
  END rtu_ifu_retire0_inc_pc[32]
  PIN rtu_ifu_retire0_inc_pc[33]
    DIRECTION INPUT ;
    USE SIGNAL ;
    PORT
      LAYER metal6 ;
        RECT 1115.545 0.000 1115.685 0.560 ;
    END
  END rtu_ifu_retire0_inc_pc[33]
  PIN rtu_ifu_retire0_inc_pc[34]
    DIRECTION INPUT ;
    USE SIGNAL ;
    PORT
      LAYER metal4 ;
        RECT 1115.545 0.000 1115.685 0.560 ;
    END
  END rtu_ifu_retire0_inc_pc[34]
  PIN rtu_ifu_retire0_inc_pc[35]
    DIRECTION INPUT ;
    USE SIGNAL ;
    PORT
      LAYER metal6 ;
        RECT 1114.425 0.000 1114.565 0.560 ;
    END
  END rtu_ifu_retire0_inc_pc[35]
  PIN rtu_ifu_retire0_inc_pc[36]
    DIRECTION INPUT ;
    USE SIGNAL ;
    PORT
      LAYER metal4 ;
        RECT 1114.425 0.000 1114.565 0.560 ;
    END
  END rtu_ifu_retire0_inc_pc[36]
  PIN rtu_ifu_retire0_inc_pc[37]
    DIRECTION INPUT ;
    USE SIGNAL ;
    PORT
      LAYER metal6 ;
        RECT 1113.305 0.000 1113.445 0.560 ;
    END
  END rtu_ifu_retire0_inc_pc[37]
  PIN rtu_ifu_retire0_inc_pc[38]
    DIRECTION INPUT ;
    USE SIGNAL ;
    PORT
      LAYER metal4 ;
        RECT 1113.305 0.000 1113.445 0.560 ;
    END
  END rtu_ifu_retire0_inc_pc[38]
  PIN rtu_ifu_retire0_inc_pc[3]
    DIRECTION INPUT ;
    USE SIGNAL ;
    PORT
      LAYER metal6 ;
        RECT 1132.345 0.000 1132.485 0.560 ;
    END
  END rtu_ifu_retire0_inc_pc[3]
  PIN rtu_ifu_retire0_inc_pc[4]
    DIRECTION INPUT ;
    USE SIGNAL ;
    PORT
      LAYER metal4 ;
        RECT 1132.345 0.000 1132.485 0.560 ;
    END
  END rtu_ifu_retire0_inc_pc[4]
  PIN rtu_ifu_retire0_inc_pc[5]
    DIRECTION INPUT ;
    USE SIGNAL ;
    PORT
      LAYER metal6 ;
        RECT 1131.225 0.000 1131.365 0.560 ;
    END
  END rtu_ifu_retire0_inc_pc[5]
  PIN rtu_ifu_retire0_inc_pc[6]
    DIRECTION INPUT ;
    USE SIGNAL ;
    PORT
      LAYER metal4 ;
        RECT 1131.225 0.000 1131.365 0.560 ;
    END
  END rtu_ifu_retire0_inc_pc[6]
  PIN rtu_ifu_retire0_inc_pc[7]
    DIRECTION INPUT ;
    USE SIGNAL ;
    PORT
      LAYER metal6 ;
        RECT 1130.105 0.000 1130.245 0.560 ;
    END
  END rtu_ifu_retire0_inc_pc[7]
  PIN rtu_ifu_retire0_inc_pc[8]
    DIRECTION INPUT ;
    USE SIGNAL ;
    PORT
      LAYER metal4 ;
        RECT 1130.105 0.000 1130.245 0.560 ;
    END
  END rtu_ifu_retire0_inc_pc[8]
  PIN rtu_ifu_retire0_inc_pc[9]
    DIRECTION INPUT ;
    USE SIGNAL ;
    PORT
      LAYER metal6 ;
        RECT 1128.985 0.000 1129.125 0.560 ;
    END
  END rtu_ifu_retire0_inc_pc[9]
  PIN rtu_ifu_retire0_jmp
    DIRECTION INPUT ;
    USE SIGNAL ;
    PORT
      LAYER metal6 ;
        RECT 1134.585 0.000 1134.725 0.560 ;
    END
  END rtu_ifu_retire0_jmp
  PIN rtu_ifu_retire0_jmp_mispred
    DIRECTION INPUT ;
    USE SIGNAL ;
    PORT
      LAYER metal4 ;
        RECT 1135.705 0.000 1135.845 0.560 ;
    END
  END rtu_ifu_retire0_jmp_mispred
  PIN rtu_ifu_retire0_mispred
    DIRECTION INPUT ;
    USE SIGNAL ;
    PORT
      LAYER metal6 ;
        RECT 1135.705 0.000 1135.845 0.560 ;
    END
  END rtu_ifu_retire0_mispred
  PIN rtu_ifu_retire0_next_pc[0]
    DIRECTION INPUT ;
    USE SIGNAL ;
    PORT
      LAYER metal4 ;
        RECT 1158.105 0.000 1158.245 0.560 ;
    END
  END rtu_ifu_retire0_next_pc[0]
  PIN rtu_ifu_retire0_next_pc[10]
    DIRECTION INPUT ;
    USE SIGNAL ;
    PORT
      LAYER metal4 ;
        RECT 1152.505 0.000 1152.645 0.560 ;
    END
  END rtu_ifu_retire0_next_pc[10]
  PIN rtu_ifu_retire0_next_pc[11]
    DIRECTION INPUT ;
    USE SIGNAL ;
    PORT
      LAYER metal6 ;
        RECT 1151.385 0.000 1151.525 0.560 ;
    END
  END rtu_ifu_retire0_next_pc[11]
  PIN rtu_ifu_retire0_next_pc[12]
    DIRECTION INPUT ;
    USE SIGNAL ;
    PORT
      LAYER metal4 ;
        RECT 1151.385 0.000 1151.525 0.560 ;
    END
  END rtu_ifu_retire0_next_pc[12]
  PIN rtu_ifu_retire0_next_pc[13]
    DIRECTION INPUT ;
    USE SIGNAL ;
    PORT
      LAYER metal6 ;
        RECT 1150.265 0.000 1150.405 0.560 ;
    END
  END rtu_ifu_retire0_next_pc[13]
  PIN rtu_ifu_retire0_next_pc[14]
    DIRECTION INPUT ;
    USE SIGNAL ;
    PORT
      LAYER metal4 ;
        RECT 1150.265 0.000 1150.405 0.560 ;
    END
  END rtu_ifu_retire0_next_pc[14]
  PIN rtu_ifu_retire0_next_pc[15]
    DIRECTION INPUT ;
    USE SIGNAL ;
    PORT
      LAYER metal6 ;
        RECT 1149.145 0.000 1149.285 0.560 ;
    END
  END rtu_ifu_retire0_next_pc[15]
  PIN rtu_ifu_retire0_next_pc[16]
    DIRECTION INPUT ;
    USE SIGNAL ;
    PORT
      LAYER metal4 ;
        RECT 1149.145 0.000 1149.285 0.560 ;
    END
  END rtu_ifu_retire0_next_pc[16]
  PIN rtu_ifu_retire0_next_pc[17]
    DIRECTION INPUT ;
    USE SIGNAL ;
    PORT
      LAYER metal6 ;
        RECT 1148.025 0.000 1148.165 0.560 ;
    END
  END rtu_ifu_retire0_next_pc[17]
  PIN rtu_ifu_retire0_next_pc[18]
    DIRECTION INPUT ;
    USE SIGNAL ;
    PORT
      LAYER metal4 ;
        RECT 1148.025 0.000 1148.165 0.560 ;
    END
  END rtu_ifu_retire0_next_pc[18]
  PIN rtu_ifu_retire0_next_pc[19]
    DIRECTION INPUT ;
    USE SIGNAL ;
    PORT
      LAYER metal6 ;
        RECT 1146.905 0.000 1147.045 0.560 ;
    END
  END rtu_ifu_retire0_next_pc[19]
  PIN rtu_ifu_retire0_next_pc[1]
    DIRECTION INPUT ;
    USE SIGNAL ;
    PORT
      LAYER metal6 ;
        RECT 1156.985 0.000 1157.125 0.560 ;
    END
  END rtu_ifu_retire0_next_pc[1]
  PIN rtu_ifu_retire0_next_pc[20]
    DIRECTION INPUT ;
    USE SIGNAL ;
    PORT
      LAYER metal4 ;
        RECT 1146.905 0.000 1147.045 0.560 ;
    END
  END rtu_ifu_retire0_next_pc[20]
  PIN rtu_ifu_retire0_next_pc[21]
    DIRECTION INPUT ;
    USE SIGNAL ;
    PORT
      LAYER metal6 ;
        RECT 1145.785 0.000 1145.925 0.560 ;
    END
  END rtu_ifu_retire0_next_pc[21]
  PIN rtu_ifu_retire0_next_pc[22]
    DIRECTION INPUT ;
    USE SIGNAL ;
    PORT
      LAYER metal4 ;
        RECT 1145.785 0.000 1145.925 0.560 ;
    END
  END rtu_ifu_retire0_next_pc[22]
  PIN rtu_ifu_retire0_next_pc[23]
    DIRECTION INPUT ;
    USE SIGNAL ;
    PORT
      LAYER metal6 ;
        RECT 1144.665 0.000 1144.805 0.560 ;
    END
  END rtu_ifu_retire0_next_pc[23]
  PIN rtu_ifu_retire0_next_pc[24]
    DIRECTION INPUT ;
    USE SIGNAL ;
    PORT
      LAYER metal4 ;
        RECT 1144.665 0.000 1144.805 0.560 ;
    END
  END rtu_ifu_retire0_next_pc[24]
  PIN rtu_ifu_retire0_next_pc[25]
    DIRECTION INPUT ;
    USE SIGNAL ;
    PORT
      LAYER metal6 ;
        RECT 1143.545 0.000 1143.685 0.560 ;
    END
  END rtu_ifu_retire0_next_pc[25]
  PIN rtu_ifu_retire0_next_pc[26]
    DIRECTION INPUT ;
    USE SIGNAL ;
    PORT
      LAYER metal4 ;
        RECT 1143.545 0.000 1143.685 0.560 ;
    END
  END rtu_ifu_retire0_next_pc[26]
  PIN rtu_ifu_retire0_next_pc[27]
    DIRECTION INPUT ;
    USE SIGNAL ;
    PORT
      LAYER metal6 ;
        RECT 1142.425 0.000 1142.565 0.560 ;
    END
  END rtu_ifu_retire0_next_pc[27]
  PIN rtu_ifu_retire0_next_pc[28]
    DIRECTION INPUT ;
    USE SIGNAL ;
    PORT
      LAYER metal4 ;
        RECT 1142.425 0.000 1142.565 0.560 ;
    END
  END rtu_ifu_retire0_next_pc[28]
  PIN rtu_ifu_retire0_next_pc[29]
    DIRECTION INPUT ;
    USE SIGNAL ;
    PORT
      LAYER metal6 ;
        RECT 1141.305 0.000 1141.445 0.560 ;
    END
  END rtu_ifu_retire0_next_pc[29]
  PIN rtu_ifu_retire0_next_pc[2]
    DIRECTION INPUT ;
    USE SIGNAL ;
    PORT
      LAYER metal4 ;
        RECT 1156.985 0.000 1157.125 0.560 ;
    END
  END rtu_ifu_retire0_next_pc[2]
  PIN rtu_ifu_retire0_next_pc[30]
    DIRECTION INPUT ;
    USE SIGNAL ;
    PORT
      LAYER metal4 ;
        RECT 1141.305 0.000 1141.445 0.560 ;
    END
  END rtu_ifu_retire0_next_pc[30]
  PIN rtu_ifu_retire0_next_pc[31]
    DIRECTION INPUT ;
    USE SIGNAL ;
    PORT
      LAYER metal6 ;
        RECT 1140.185 0.000 1140.325 0.560 ;
    END
  END rtu_ifu_retire0_next_pc[31]
  PIN rtu_ifu_retire0_next_pc[32]
    DIRECTION INPUT ;
    USE SIGNAL ;
    PORT
      LAYER metal4 ;
        RECT 1140.185 0.000 1140.325 0.560 ;
    END
  END rtu_ifu_retire0_next_pc[32]
  PIN rtu_ifu_retire0_next_pc[33]
    DIRECTION INPUT ;
    USE SIGNAL ;
    PORT
      LAYER metal6 ;
        RECT 1139.065 0.000 1139.205 0.560 ;
    END
  END rtu_ifu_retire0_next_pc[33]
  PIN rtu_ifu_retire0_next_pc[34]
    DIRECTION INPUT ;
    USE SIGNAL ;
    PORT
      LAYER metal4 ;
        RECT 1139.065 0.000 1139.205 0.560 ;
    END
  END rtu_ifu_retire0_next_pc[34]
  PIN rtu_ifu_retire0_next_pc[35]
    DIRECTION INPUT ;
    USE SIGNAL ;
    PORT
      LAYER metal6 ;
        RECT 1137.945 0.000 1138.085 0.560 ;
    END
  END rtu_ifu_retire0_next_pc[35]
  PIN rtu_ifu_retire0_next_pc[36]
    DIRECTION INPUT ;
    USE SIGNAL ;
    PORT
      LAYER metal4 ;
        RECT 1137.945 0.000 1138.085 0.560 ;
    END
  END rtu_ifu_retire0_next_pc[36]
  PIN rtu_ifu_retire0_next_pc[37]
    DIRECTION INPUT ;
    USE SIGNAL ;
    PORT
      LAYER metal6 ;
        RECT 1136.825 0.000 1136.965 0.560 ;
    END
  END rtu_ifu_retire0_next_pc[37]
  PIN rtu_ifu_retire0_next_pc[38]
    DIRECTION INPUT ;
    USE SIGNAL ;
    PORT
      LAYER metal4 ;
        RECT 1136.825 0.000 1136.965 0.560 ;
    END
  END rtu_ifu_retire0_next_pc[38]
  PIN rtu_ifu_retire0_next_pc[3]
    DIRECTION INPUT ;
    USE SIGNAL ;
    PORT
      LAYER metal6 ;
        RECT 1155.865 0.000 1156.005 0.560 ;
    END
  END rtu_ifu_retire0_next_pc[3]
  PIN rtu_ifu_retire0_next_pc[4]
    DIRECTION INPUT ;
    USE SIGNAL ;
    PORT
      LAYER metal4 ;
        RECT 1155.865 0.000 1156.005 0.560 ;
    END
  END rtu_ifu_retire0_next_pc[4]
  PIN rtu_ifu_retire0_next_pc[5]
    DIRECTION INPUT ;
    USE SIGNAL ;
    PORT
      LAYER metal6 ;
        RECT 1154.745 0.000 1154.885 0.560 ;
    END
  END rtu_ifu_retire0_next_pc[5]
  PIN rtu_ifu_retire0_next_pc[6]
    DIRECTION INPUT ;
    USE SIGNAL ;
    PORT
      LAYER metal4 ;
        RECT 1154.745 0.000 1154.885 0.560 ;
    END
  END rtu_ifu_retire0_next_pc[6]
  PIN rtu_ifu_retire0_next_pc[7]
    DIRECTION INPUT ;
    USE SIGNAL ;
    PORT
      LAYER metal6 ;
        RECT 1153.625 0.000 1153.765 0.560 ;
    END
  END rtu_ifu_retire0_next_pc[7]
  PIN rtu_ifu_retire0_next_pc[8]
    DIRECTION INPUT ;
    USE SIGNAL ;
    PORT
      LAYER metal4 ;
        RECT 1153.625 0.000 1153.765 0.560 ;
    END
  END rtu_ifu_retire0_next_pc[8]
  PIN rtu_ifu_retire0_next_pc[9]
    DIRECTION INPUT ;
    USE SIGNAL ;
    PORT
      LAYER metal6 ;
        RECT 1152.505 0.000 1152.645 0.560 ;
    END
  END rtu_ifu_retire0_next_pc[9]
  PIN rtu_ifu_retire0_pcall
    DIRECTION INPUT ;
    USE SIGNAL ;
    PORT
      LAYER metal6 ;
        RECT 1158.105 0.000 1158.245 0.560 ;
    END
  END rtu_ifu_retire0_pcall
  PIN rtu_ifu_retire0_preturn
    DIRECTION INPUT ;
    USE SIGNAL ;
    PORT
      LAYER metal4 ;
        RECT 1159.225 0.000 1159.365 0.560 ;
    END
  END rtu_ifu_retire0_preturn
  PIN rtu_ifu_retire1_chk_idx[0]
    DIRECTION INPUT ;
    USE SIGNAL ;
    PORT
      LAYER metal4 ;
        RECT 1163.705 0.000 1163.845 0.560 ;
    END
  END rtu_ifu_retire1_chk_idx[0]
  PIN rtu_ifu_retire1_chk_idx[1]
    DIRECTION INPUT ;
    USE SIGNAL ;
    PORT
      LAYER metal6 ;
        RECT 1162.585 0.000 1162.725 0.560 ;
    END
  END rtu_ifu_retire1_chk_idx[1]
  PIN rtu_ifu_retire1_chk_idx[2]
    DIRECTION INPUT ;
    USE SIGNAL ;
    PORT
      LAYER metal4 ;
        RECT 1162.585 0.000 1162.725 0.560 ;
    END
  END rtu_ifu_retire1_chk_idx[2]
  PIN rtu_ifu_retire1_chk_idx[3]
    DIRECTION INPUT ;
    USE SIGNAL ;
    PORT
      LAYER metal6 ;
        RECT 1161.465 0.000 1161.605 0.560 ;
    END
  END rtu_ifu_retire1_chk_idx[3]
  PIN rtu_ifu_retire1_chk_idx[4]
    DIRECTION INPUT ;
    USE SIGNAL ;
    PORT
      LAYER metal4 ;
        RECT 1161.465 0.000 1161.605 0.560 ;
    END
  END rtu_ifu_retire1_chk_idx[4]
  PIN rtu_ifu_retire1_chk_idx[5]
    DIRECTION INPUT ;
    USE SIGNAL ;
    PORT
      LAYER metal6 ;
        RECT 1160.345 0.000 1160.485 0.560 ;
    END
  END rtu_ifu_retire1_chk_idx[5]
  PIN rtu_ifu_retire1_chk_idx[6]
    DIRECTION INPUT ;
    USE SIGNAL ;
    PORT
      LAYER metal4 ;
        RECT 1160.345 0.000 1160.485 0.560 ;
    END
  END rtu_ifu_retire1_chk_idx[6]
  PIN rtu_ifu_retire1_chk_idx[7]
    DIRECTION INPUT ;
    USE SIGNAL ;
    PORT
      LAYER metal6 ;
        RECT 1159.225 0.000 1159.365 0.560 ;
    END
  END rtu_ifu_retire1_chk_idx[7]
  PIN rtu_ifu_retire1_condbr
    DIRECTION INPUT ;
    USE SIGNAL ;
    PORT
      LAYER metal6 ;
        RECT 1163.705 0.000 1163.845 0.560 ;
    END
  END rtu_ifu_retire1_condbr
  PIN rtu_ifu_retire1_condbr_taken
    DIRECTION INPUT ;
    USE SIGNAL ;
    PORT
      LAYER metal4 ;
        RECT 1164.825 0.000 1164.965 0.560 ;
    END
  END rtu_ifu_retire1_condbr_taken
  PIN rtu_ifu_retire1_jmp
    DIRECTION INPUT ;
    USE SIGNAL ;
    PORT
      LAYER metal6 ;
        RECT 1164.825 0.000 1164.965 0.560 ;
    END
  END rtu_ifu_retire1_jmp
  PIN rtu_ifu_retire2_chk_idx[0]
    DIRECTION INPUT ;
    USE SIGNAL ;
    PORT
      LAYER metal6 ;
        RECT 1169.305 0.000 1169.445 0.560 ;
    END
  END rtu_ifu_retire2_chk_idx[0]
  PIN rtu_ifu_retire2_chk_idx[1]
    DIRECTION INPUT ;
    USE SIGNAL ;
    PORT
      LAYER metal4 ;
        RECT 1169.305 0.000 1169.445 0.560 ;
    END
  END rtu_ifu_retire2_chk_idx[1]
  PIN rtu_ifu_retire2_chk_idx[2]
    DIRECTION INPUT ;
    USE SIGNAL ;
    PORT
      LAYER metal6 ;
        RECT 1168.185 0.000 1168.325 0.560 ;
    END
  END rtu_ifu_retire2_chk_idx[2]
  PIN rtu_ifu_retire2_chk_idx[3]
    DIRECTION INPUT ;
    USE SIGNAL ;
    PORT
      LAYER metal4 ;
        RECT 1168.185 0.000 1168.325 0.560 ;
    END
  END rtu_ifu_retire2_chk_idx[3]
  PIN rtu_ifu_retire2_chk_idx[4]
    DIRECTION INPUT ;
    USE SIGNAL ;
    PORT
      LAYER metal6 ;
        RECT 1167.065 0.000 1167.205 0.560 ;
    END
  END rtu_ifu_retire2_chk_idx[4]
  PIN rtu_ifu_retire2_chk_idx[5]
    DIRECTION INPUT ;
    USE SIGNAL ;
    PORT
      LAYER metal4 ;
        RECT 1167.065 0.000 1167.205 0.560 ;
    END
  END rtu_ifu_retire2_chk_idx[5]
  PIN rtu_ifu_retire2_chk_idx[6]
    DIRECTION INPUT ;
    USE SIGNAL ;
    PORT
      LAYER metal6 ;
        RECT 1165.945 0.000 1166.085 0.560 ;
    END
  END rtu_ifu_retire2_chk_idx[6]
  PIN rtu_ifu_retire2_chk_idx[7]
    DIRECTION INPUT ;
    USE SIGNAL ;
    PORT
      LAYER metal4 ;
        RECT 1165.945 0.000 1166.085 0.560 ;
    END
  END rtu_ifu_retire2_chk_idx[7]
  PIN rtu_ifu_retire2_condbr
    DIRECTION INPUT ;
    USE SIGNAL ;
    PORT
      LAYER metal4 ;
        RECT 1170.425 0.000 1170.565 0.560 ;
    END
  END rtu_ifu_retire2_condbr
  PIN rtu_ifu_retire2_condbr_taken
    DIRECTION INPUT ;
    USE SIGNAL ;
    PORT
      LAYER metal6 ;
        RECT 1170.425 0.000 1170.565 0.560 ;
    END
  END rtu_ifu_retire2_condbr_taken
  PIN rtu_ifu_retire2_jmp
    DIRECTION INPUT ;
    USE SIGNAL ;
    PORT
      LAYER metal4 ;
        RECT 1171.545 0.000 1171.685 0.560 ;
    END
  END rtu_ifu_retire2_jmp
  PIN rtu_ifu_retire_inst0_cur_pc[0]
    DIRECTION INPUT ;
    USE SIGNAL ;
    PORT
      LAYER metal6 ;
        RECT 1192.825 0.000 1192.965 0.560 ;
    END
  END rtu_ifu_retire_inst0_cur_pc[0]
  PIN rtu_ifu_retire_inst0_cur_pc[10]
    DIRECTION INPUT ;
    USE SIGNAL ;
    PORT
      LAYER metal6 ;
        RECT 1187.225 0.000 1187.365 0.560 ;
    END
  END rtu_ifu_retire_inst0_cur_pc[10]
  PIN rtu_ifu_retire_inst0_cur_pc[11]
    DIRECTION INPUT ;
    USE SIGNAL ;
    PORT
      LAYER metal4 ;
        RECT 1187.225 0.000 1187.365 0.560 ;
    END
  END rtu_ifu_retire_inst0_cur_pc[11]
  PIN rtu_ifu_retire_inst0_cur_pc[12]
    DIRECTION INPUT ;
    USE SIGNAL ;
    PORT
      LAYER metal6 ;
        RECT 1186.105 0.000 1186.245 0.560 ;
    END
  END rtu_ifu_retire_inst0_cur_pc[12]
  PIN rtu_ifu_retire_inst0_cur_pc[13]
    DIRECTION INPUT ;
    USE SIGNAL ;
    PORT
      LAYER metal4 ;
        RECT 1186.105 0.000 1186.245 0.560 ;
    END
  END rtu_ifu_retire_inst0_cur_pc[13]
  PIN rtu_ifu_retire_inst0_cur_pc[14]
    DIRECTION INPUT ;
    USE SIGNAL ;
    PORT
      LAYER metal6 ;
        RECT 1184.985 0.000 1185.125 0.560 ;
    END
  END rtu_ifu_retire_inst0_cur_pc[14]
  PIN rtu_ifu_retire_inst0_cur_pc[15]
    DIRECTION INPUT ;
    USE SIGNAL ;
    PORT
      LAYER metal4 ;
        RECT 1184.985 0.000 1185.125 0.560 ;
    END
  END rtu_ifu_retire_inst0_cur_pc[15]
  PIN rtu_ifu_retire_inst0_cur_pc[16]
    DIRECTION INPUT ;
    USE SIGNAL ;
    PORT
      LAYER metal6 ;
        RECT 1183.865 0.000 1184.005 0.560 ;
    END
  END rtu_ifu_retire_inst0_cur_pc[16]
  PIN rtu_ifu_retire_inst0_cur_pc[17]
    DIRECTION INPUT ;
    USE SIGNAL ;
    PORT
      LAYER metal4 ;
        RECT 1183.865 0.000 1184.005 0.560 ;
    END
  END rtu_ifu_retire_inst0_cur_pc[17]
  PIN rtu_ifu_retire_inst0_cur_pc[18]
    DIRECTION INPUT ;
    USE SIGNAL ;
    PORT
      LAYER metal6 ;
        RECT 1182.745 0.000 1182.885 0.560 ;
    END
  END rtu_ifu_retire_inst0_cur_pc[18]
  PIN rtu_ifu_retire_inst0_cur_pc[19]
    DIRECTION INPUT ;
    USE SIGNAL ;
    PORT
      LAYER metal4 ;
        RECT 1182.745 0.000 1182.885 0.560 ;
    END
  END rtu_ifu_retire_inst0_cur_pc[19]
  PIN rtu_ifu_retire_inst0_cur_pc[1]
    DIRECTION INPUT ;
    USE SIGNAL ;
    PORT
      LAYER metal4 ;
        RECT 1192.825 0.000 1192.965 0.560 ;
    END
  END rtu_ifu_retire_inst0_cur_pc[1]
  PIN rtu_ifu_retire_inst0_cur_pc[20]
    DIRECTION INPUT ;
    USE SIGNAL ;
    PORT
      LAYER metal6 ;
        RECT 1181.625 0.000 1181.765 0.560 ;
    END
  END rtu_ifu_retire_inst0_cur_pc[20]
  PIN rtu_ifu_retire_inst0_cur_pc[21]
    DIRECTION INPUT ;
    USE SIGNAL ;
    PORT
      LAYER metal4 ;
        RECT 1181.625 0.000 1181.765 0.560 ;
    END
  END rtu_ifu_retire_inst0_cur_pc[21]
  PIN rtu_ifu_retire_inst0_cur_pc[22]
    DIRECTION INPUT ;
    USE SIGNAL ;
    PORT
      LAYER metal6 ;
        RECT 1180.505 0.000 1180.645 0.560 ;
    END
  END rtu_ifu_retire_inst0_cur_pc[22]
  PIN rtu_ifu_retire_inst0_cur_pc[23]
    DIRECTION INPUT ;
    USE SIGNAL ;
    PORT
      LAYER metal4 ;
        RECT 1180.505 0.000 1180.645 0.560 ;
    END
  END rtu_ifu_retire_inst0_cur_pc[23]
  PIN rtu_ifu_retire_inst0_cur_pc[24]
    DIRECTION INPUT ;
    USE SIGNAL ;
    PORT
      LAYER metal6 ;
        RECT 1179.385 0.000 1179.525 0.560 ;
    END
  END rtu_ifu_retire_inst0_cur_pc[24]
  PIN rtu_ifu_retire_inst0_cur_pc[25]
    DIRECTION INPUT ;
    USE SIGNAL ;
    PORT
      LAYER metal4 ;
        RECT 1179.385 0.000 1179.525 0.560 ;
    END
  END rtu_ifu_retire_inst0_cur_pc[25]
  PIN rtu_ifu_retire_inst0_cur_pc[26]
    DIRECTION INPUT ;
    USE SIGNAL ;
    PORT
      LAYER metal6 ;
        RECT 1178.265 0.000 1178.405 0.560 ;
    END
  END rtu_ifu_retire_inst0_cur_pc[26]
  PIN rtu_ifu_retire_inst0_cur_pc[27]
    DIRECTION INPUT ;
    USE SIGNAL ;
    PORT
      LAYER metal4 ;
        RECT 1178.265 0.000 1178.405 0.560 ;
    END
  END rtu_ifu_retire_inst0_cur_pc[27]
  PIN rtu_ifu_retire_inst0_cur_pc[28]
    DIRECTION INPUT ;
    USE SIGNAL ;
    PORT
      LAYER metal6 ;
        RECT 1177.145 0.000 1177.285 0.560 ;
    END
  END rtu_ifu_retire_inst0_cur_pc[28]
  PIN rtu_ifu_retire_inst0_cur_pc[29]
    DIRECTION INPUT ;
    USE SIGNAL ;
    PORT
      LAYER metal4 ;
        RECT 1177.145 0.000 1177.285 0.560 ;
    END
  END rtu_ifu_retire_inst0_cur_pc[29]
  PIN rtu_ifu_retire_inst0_cur_pc[2]
    DIRECTION INPUT ;
    USE SIGNAL ;
    PORT
      LAYER metal6 ;
        RECT 1191.705 0.000 1191.845 0.560 ;
    END
  END rtu_ifu_retire_inst0_cur_pc[2]
  PIN rtu_ifu_retire_inst0_cur_pc[30]
    DIRECTION INPUT ;
    USE SIGNAL ;
    PORT
      LAYER metal6 ;
        RECT 1176.025 0.000 1176.165 0.560 ;
    END
  END rtu_ifu_retire_inst0_cur_pc[30]
  PIN rtu_ifu_retire_inst0_cur_pc[31]
    DIRECTION INPUT ;
    USE SIGNAL ;
    PORT
      LAYER metal4 ;
        RECT 1176.025 0.000 1176.165 0.560 ;
    END
  END rtu_ifu_retire_inst0_cur_pc[31]
  PIN rtu_ifu_retire_inst0_cur_pc[32]
    DIRECTION INPUT ;
    USE SIGNAL ;
    PORT
      LAYER metal6 ;
        RECT 1174.905 0.000 1175.045 0.560 ;
    END
  END rtu_ifu_retire_inst0_cur_pc[32]
  PIN rtu_ifu_retire_inst0_cur_pc[33]
    DIRECTION INPUT ;
    USE SIGNAL ;
    PORT
      LAYER metal4 ;
        RECT 1174.905 0.000 1175.045 0.560 ;
    END
  END rtu_ifu_retire_inst0_cur_pc[33]
  PIN rtu_ifu_retire_inst0_cur_pc[34]
    DIRECTION INPUT ;
    USE SIGNAL ;
    PORT
      LAYER metal6 ;
        RECT 1173.785 0.000 1173.925 0.560 ;
    END
  END rtu_ifu_retire_inst0_cur_pc[34]
  PIN rtu_ifu_retire_inst0_cur_pc[35]
    DIRECTION INPUT ;
    USE SIGNAL ;
    PORT
      LAYER metal4 ;
        RECT 1173.785 0.000 1173.925 0.560 ;
    END
  END rtu_ifu_retire_inst0_cur_pc[35]
  PIN rtu_ifu_retire_inst0_cur_pc[36]
    DIRECTION INPUT ;
    USE SIGNAL ;
    PORT
      LAYER metal6 ;
        RECT 1172.665 0.000 1172.805 0.560 ;
    END
  END rtu_ifu_retire_inst0_cur_pc[36]
  PIN rtu_ifu_retire_inst0_cur_pc[37]
    DIRECTION INPUT ;
    USE SIGNAL ;
    PORT
      LAYER metal4 ;
        RECT 1172.665 0.000 1172.805 0.560 ;
    END
  END rtu_ifu_retire_inst0_cur_pc[37]
  PIN rtu_ifu_retire_inst0_cur_pc[38]
    DIRECTION INPUT ;
    USE SIGNAL ;
    PORT
      LAYER metal6 ;
        RECT 1171.545 0.000 1171.685 0.560 ;
    END
  END rtu_ifu_retire_inst0_cur_pc[38]
  PIN rtu_ifu_retire_inst0_cur_pc[3]
    DIRECTION INPUT ;
    USE SIGNAL ;
    PORT
      LAYER metal4 ;
        RECT 1191.705 0.000 1191.845 0.560 ;
    END
  END rtu_ifu_retire_inst0_cur_pc[3]
  PIN rtu_ifu_retire_inst0_cur_pc[4]
    DIRECTION INPUT ;
    USE SIGNAL ;
    PORT
      LAYER metal6 ;
        RECT 1190.585 0.000 1190.725 0.560 ;
    END
  END rtu_ifu_retire_inst0_cur_pc[4]
  PIN rtu_ifu_retire_inst0_cur_pc[5]
    DIRECTION INPUT ;
    USE SIGNAL ;
    PORT
      LAYER metal4 ;
        RECT 1190.585 0.000 1190.725 0.560 ;
    END
  END rtu_ifu_retire_inst0_cur_pc[5]
  PIN rtu_ifu_retire_inst0_cur_pc[6]
    DIRECTION INPUT ;
    USE SIGNAL ;
    PORT
      LAYER metal6 ;
        RECT 1189.465 0.000 1189.605 0.560 ;
    END
  END rtu_ifu_retire_inst0_cur_pc[6]
  PIN rtu_ifu_retire_inst0_cur_pc[7]
    DIRECTION INPUT ;
    USE SIGNAL ;
    PORT
      LAYER metal4 ;
        RECT 1189.465 0.000 1189.605 0.560 ;
    END
  END rtu_ifu_retire_inst0_cur_pc[7]
  PIN rtu_ifu_retire_inst0_cur_pc[8]
    DIRECTION INPUT ;
    USE SIGNAL ;
    PORT
      LAYER metal6 ;
        RECT 1188.345 0.000 1188.485 0.560 ;
    END
  END rtu_ifu_retire_inst0_cur_pc[8]
  PIN rtu_ifu_retire_inst0_cur_pc[9]
    DIRECTION INPUT ;
    USE SIGNAL ;
    PORT
      LAYER metal4 ;
        RECT 1188.345 0.000 1188.485 0.560 ;
    END
  END rtu_ifu_retire_inst0_cur_pc[9]
  PIN rtu_ifu_retire_inst0_load
    DIRECTION INPUT ;
    USE SIGNAL ;
    PORT
      LAYER metal4 ;
        RECT 1193.945 0.000 1194.085 0.560 ;
    END
  END rtu_ifu_retire_inst0_load
  PIN rtu_ifu_retire_inst0_no_spec_hit
    DIRECTION INPUT ;
    USE SIGNAL ;
    PORT
      LAYER metal6 ;
        RECT 1193.945 0.000 1194.085 0.560 ;
    END
  END rtu_ifu_retire_inst0_no_spec_hit
  PIN rtu_ifu_retire_inst0_no_spec_mispred
    DIRECTION INPUT ;
    USE SIGNAL ;
    PORT
      LAYER metal4 ;
        RECT 1195.065 0.000 1195.205 0.560 ;
    END
  END rtu_ifu_retire_inst0_no_spec_mispred
  PIN rtu_ifu_retire_inst0_no_spec_miss
    DIRECTION INPUT ;
    USE SIGNAL ;
    PORT
      LAYER metal6 ;
        RECT 1195.065 0.000 1195.205 0.560 ;
    END
  END rtu_ifu_retire_inst0_no_spec_miss
  PIN rtu_ifu_retire_inst0_store
    DIRECTION INPUT ;
    USE SIGNAL ;
    PORT
      LAYER metal4 ;
        RECT 1196.185 0.000 1196.325 0.560 ;
    END
  END rtu_ifu_retire_inst0_store
  PIN rtu_ifu_retire_inst0_vl_hit
    DIRECTION INPUT ;
    USE SIGNAL ;
    PORT
      LAYER metal6 ;
        RECT 1196.185 0.000 1196.325 0.560 ;
    END
  END rtu_ifu_retire_inst0_vl_hit
  PIN rtu_ifu_retire_inst0_vl_mispred
    DIRECTION INPUT ;
    USE SIGNAL ;
    PORT
      LAYER metal4 ;
        RECT 1197.305 0.000 1197.445 0.560 ;
    END
  END rtu_ifu_retire_inst0_vl_mispred
  PIN rtu_ifu_retire_inst0_vl_miss
    DIRECTION INPUT ;
    USE SIGNAL ;
    PORT
      LAYER metal6 ;
        RECT 1197.305 0.000 1197.445 0.560 ;
    END
  END rtu_ifu_retire_inst0_vl_miss
  PIN rtu_ifu_retire_inst0_vl_pred
    DIRECTION INPUT ;
    USE SIGNAL ;
    PORT
      LAYER metal4 ;
        RECT 1198.425 0.000 1198.565 0.560 ;
    END
  END rtu_ifu_retire_inst0_vl_pred
  PIN rtu_ifu_retire_inst1_cur_pc[0]
    DIRECTION INPUT ;
    USE SIGNAL ;
    PORT
      LAYER metal6 ;
        RECT 1219.705 0.000 1219.845 0.560 ;
    END
  END rtu_ifu_retire_inst1_cur_pc[0]
  PIN rtu_ifu_retire_inst1_cur_pc[10]
    DIRECTION INPUT ;
    USE SIGNAL ;
    PORT
      LAYER metal6 ;
        RECT 1214.105 0.000 1214.245 0.560 ;
    END
  END rtu_ifu_retire_inst1_cur_pc[10]
  PIN rtu_ifu_retire_inst1_cur_pc[11]
    DIRECTION INPUT ;
    USE SIGNAL ;
    PORT
      LAYER metal4 ;
        RECT 1214.105 0.000 1214.245 0.560 ;
    END
  END rtu_ifu_retire_inst1_cur_pc[11]
  PIN rtu_ifu_retire_inst1_cur_pc[12]
    DIRECTION INPUT ;
    USE SIGNAL ;
    PORT
      LAYER metal6 ;
        RECT 1212.985 0.000 1213.125 0.560 ;
    END
  END rtu_ifu_retire_inst1_cur_pc[12]
  PIN rtu_ifu_retire_inst1_cur_pc[13]
    DIRECTION INPUT ;
    USE SIGNAL ;
    PORT
      LAYER metal4 ;
        RECT 1212.985 0.000 1213.125 0.560 ;
    END
  END rtu_ifu_retire_inst1_cur_pc[13]
  PIN rtu_ifu_retire_inst1_cur_pc[14]
    DIRECTION INPUT ;
    USE SIGNAL ;
    PORT
      LAYER metal6 ;
        RECT 1211.865 0.000 1212.005 0.560 ;
    END
  END rtu_ifu_retire_inst1_cur_pc[14]
  PIN rtu_ifu_retire_inst1_cur_pc[15]
    DIRECTION INPUT ;
    USE SIGNAL ;
    PORT
      LAYER metal4 ;
        RECT 1211.865 0.000 1212.005 0.560 ;
    END
  END rtu_ifu_retire_inst1_cur_pc[15]
  PIN rtu_ifu_retire_inst1_cur_pc[16]
    DIRECTION INPUT ;
    USE SIGNAL ;
    PORT
      LAYER metal6 ;
        RECT 1210.745 0.000 1210.885 0.560 ;
    END
  END rtu_ifu_retire_inst1_cur_pc[16]
  PIN rtu_ifu_retire_inst1_cur_pc[17]
    DIRECTION INPUT ;
    USE SIGNAL ;
    PORT
      LAYER metal4 ;
        RECT 1210.745 0.000 1210.885 0.560 ;
    END
  END rtu_ifu_retire_inst1_cur_pc[17]
  PIN rtu_ifu_retire_inst1_cur_pc[18]
    DIRECTION INPUT ;
    USE SIGNAL ;
    PORT
      LAYER metal6 ;
        RECT 1209.625 0.000 1209.765 0.560 ;
    END
  END rtu_ifu_retire_inst1_cur_pc[18]
  PIN rtu_ifu_retire_inst1_cur_pc[19]
    DIRECTION INPUT ;
    USE SIGNAL ;
    PORT
      LAYER metal4 ;
        RECT 1209.625 0.000 1209.765 0.560 ;
    END
  END rtu_ifu_retire_inst1_cur_pc[19]
  PIN rtu_ifu_retire_inst1_cur_pc[1]
    DIRECTION INPUT ;
    USE SIGNAL ;
    PORT
      LAYER metal4 ;
        RECT 1219.705 0.000 1219.845 0.560 ;
    END
  END rtu_ifu_retire_inst1_cur_pc[1]
  PIN rtu_ifu_retire_inst1_cur_pc[20]
    DIRECTION INPUT ;
    USE SIGNAL ;
    PORT
      LAYER metal6 ;
        RECT 1208.505 0.000 1208.645 0.560 ;
    END
  END rtu_ifu_retire_inst1_cur_pc[20]
  PIN rtu_ifu_retire_inst1_cur_pc[21]
    DIRECTION INPUT ;
    USE SIGNAL ;
    PORT
      LAYER metal4 ;
        RECT 1208.505 0.000 1208.645 0.560 ;
    END
  END rtu_ifu_retire_inst1_cur_pc[21]
  PIN rtu_ifu_retire_inst1_cur_pc[22]
    DIRECTION INPUT ;
    USE SIGNAL ;
    PORT
      LAYER metal6 ;
        RECT 1207.385 0.000 1207.525 0.560 ;
    END
  END rtu_ifu_retire_inst1_cur_pc[22]
  PIN rtu_ifu_retire_inst1_cur_pc[23]
    DIRECTION INPUT ;
    USE SIGNAL ;
    PORT
      LAYER metal4 ;
        RECT 1207.385 0.000 1207.525 0.560 ;
    END
  END rtu_ifu_retire_inst1_cur_pc[23]
  PIN rtu_ifu_retire_inst1_cur_pc[24]
    DIRECTION INPUT ;
    USE SIGNAL ;
    PORT
      LAYER metal6 ;
        RECT 1206.265 0.000 1206.405 0.560 ;
    END
  END rtu_ifu_retire_inst1_cur_pc[24]
  PIN rtu_ifu_retire_inst1_cur_pc[25]
    DIRECTION INPUT ;
    USE SIGNAL ;
    PORT
      LAYER metal4 ;
        RECT 1206.265 0.000 1206.405 0.560 ;
    END
  END rtu_ifu_retire_inst1_cur_pc[25]
  PIN rtu_ifu_retire_inst1_cur_pc[26]
    DIRECTION INPUT ;
    USE SIGNAL ;
    PORT
      LAYER metal6 ;
        RECT 1205.145 0.000 1205.285 0.560 ;
    END
  END rtu_ifu_retire_inst1_cur_pc[26]
  PIN rtu_ifu_retire_inst1_cur_pc[27]
    DIRECTION INPUT ;
    USE SIGNAL ;
    PORT
      LAYER metal4 ;
        RECT 1205.145 0.000 1205.285 0.560 ;
    END
  END rtu_ifu_retire_inst1_cur_pc[27]
  PIN rtu_ifu_retire_inst1_cur_pc[28]
    DIRECTION INPUT ;
    USE SIGNAL ;
    PORT
      LAYER metal6 ;
        RECT 1204.025 0.000 1204.165 0.560 ;
    END
  END rtu_ifu_retire_inst1_cur_pc[28]
  PIN rtu_ifu_retire_inst1_cur_pc[29]
    DIRECTION INPUT ;
    USE SIGNAL ;
    PORT
      LAYER metal4 ;
        RECT 1204.025 0.000 1204.165 0.560 ;
    END
  END rtu_ifu_retire_inst1_cur_pc[29]
  PIN rtu_ifu_retire_inst1_cur_pc[2]
    DIRECTION INPUT ;
    USE SIGNAL ;
    PORT
      LAYER metal6 ;
        RECT 1218.585 0.000 1218.725 0.560 ;
    END
  END rtu_ifu_retire_inst1_cur_pc[2]
  PIN rtu_ifu_retire_inst1_cur_pc[30]
    DIRECTION INPUT ;
    USE SIGNAL ;
    PORT
      LAYER metal6 ;
        RECT 1202.905 0.000 1203.045 0.560 ;
    END
  END rtu_ifu_retire_inst1_cur_pc[30]
  PIN rtu_ifu_retire_inst1_cur_pc[31]
    DIRECTION INPUT ;
    USE SIGNAL ;
    PORT
      LAYER metal4 ;
        RECT 1202.905 0.000 1203.045 0.560 ;
    END
  END rtu_ifu_retire_inst1_cur_pc[31]
  PIN rtu_ifu_retire_inst1_cur_pc[32]
    DIRECTION INPUT ;
    USE SIGNAL ;
    PORT
      LAYER metal6 ;
        RECT 1201.785 0.000 1201.925 0.560 ;
    END
  END rtu_ifu_retire_inst1_cur_pc[32]
  PIN rtu_ifu_retire_inst1_cur_pc[33]
    DIRECTION INPUT ;
    USE SIGNAL ;
    PORT
      LAYER metal4 ;
        RECT 1201.785 0.000 1201.925 0.560 ;
    END
  END rtu_ifu_retire_inst1_cur_pc[33]
  PIN rtu_ifu_retire_inst1_cur_pc[34]
    DIRECTION INPUT ;
    USE SIGNAL ;
    PORT
      LAYER metal6 ;
        RECT 1200.665 0.000 1200.805 0.560 ;
    END
  END rtu_ifu_retire_inst1_cur_pc[34]
  PIN rtu_ifu_retire_inst1_cur_pc[35]
    DIRECTION INPUT ;
    USE SIGNAL ;
    PORT
      LAYER metal4 ;
        RECT 1200.665 0.000 1200.805 0.560 ;
    END
  END rtu_ifu_retire_inst1_cur_pc[35]
  PIN rtu_ifu_retire_inst1_cur_pc[36]
    DIRECTION INPUT ;
    USE SIGNAL ;
    PORT
      LAYER metal6 ;
        RECT 1199.545 0.000 1199.685 0.560 ;
    END
  END rtu_ifu_retire_inst1_cur_pc[36]
  PIN rtu_ifu_retire_inst1_cur_pc[37]
    DIRECTION INPUT ;
    USE SIGNAL ;
    PORT
      LAYER metal4 ;
        RECT 1199.545 0.000 1199.685 0.560 ;
    END
  END rtu_ifu_retire_inst1_cur_pc[37]
  PIN rtu_ifu_retire_inst1_cur_pc[38]
    DIRECTION INPUT ;
    USE SIGNAL ;
    PORT
      LAYER metal6 ;
        RECT 1198.425 0.000 1198.565 0.560 ;
    END
  END rtu_ifu_retire_inst1_cur_pc[38]
  PIN rtu_ifu_retire_inst1_cur_pc[3]
    DIRECTION INPUT ;
    USE SIGNAL ;
    PORT
      LAYER metal4 ;
        RECT 1218.585 0.000 1218.725 0.560 ;
    END
  END rtu_ifu_retire_inst1_cur_pc[3]
  PIN rtu_ifu_retire_inst1_cur_pc[4]
    DIRECTION INPUT ;
    USE SIGNAL ;
    PORT
      LAYER metal6 ;
        RECT 1217.465 0.000 1217.605 0.560 ;
    END
  END rtu_ifu_retire_inst1_cur_pc[4]
  PIN rtu_ifu_retire_inst1_cur_pc[5]
    DIRECTION INPUT ;
    USE SIGNAL ;
    PORT
      LAYER metal4 ;
        RECT 1217.465 0.000 1217.605 0.560 ;
    END
  END rtu_ifu_retire_inst1_cur_pc[5]
  PIN rtu_ifu_retire_inst1_cur_pc[6]
    DIRECTION INPUT ;
    USE SIGNAL ;
    PORT
      LAYER metal6 ;
        RECT 1216.345 0.000 1216.485 0.560 ;
    END
  END rtu_ifu_retire_inst1_cur_pc[6]
  PIN rtu_ifu_retire_inst1_cur_pc[7]
    DIRECTION INPUT ;
    USE SIGNAL ;
    PORT
      LAYER metal4 ;
        RECT 1216.345 0.000 1216.485 0.560 ;
    END
  END rtu_ifu_retire_inst1_cur_pc[7]
  PIN rtu_ifu_retire_inst1_cur_pc[8]
    DIRECTION INPUT ;
    USE SIGNAL ;
    PORT
      LAYER metal6 ;
        RECT 1215.225 0.000 1215.365 0.560 ;
    END
  END rtu_ifu_retire_inst1_cur_pc[8]
  PIN rtu_ifu_retire_inst1_cur_pc[9]
    DIRECTION INPUT ;
    USE SIGNAL ;
    PORT
      LAYER metal4 ;
        RECT 1215.225 0.000 1215.365 0.560 ;
    END
  END rtu_ifu_retire_inst1_cur_pc[9]
  PIN rtu_ifu_retire_inst1_load
    DIRECTION INPUT ;
    USE SIGNAL ;
    PORT
      LAYER metal4 ;
        RECT 1220.825 0.000 1220.965 0.560 ;
    END
  END rtu_ifu_retire_inst1_load
  PIN rtu_ifu_retire_inst1_no_spec_hit
    DIRECTION INPUT ;
    USE SIGNAL ;
    PORT
      LAYER metal6 ;
        RECT 1220.825 0.000 1220.965 0.560 ;
    END
  END rtu_ifu_retire_inst1_no_spec_hit
  PIN rtu_ifu_retire_inst1_no_spec_mispred
    DIRECTION INPUT ;
    USE SIGNAL ;
    PORT
      LAYER metal4 ;
        RECT 1221.945 0.000 1222.085 0.560 ;
    END
  END rtu_ifu_retire_inst1_no_spec_mispred
  PIN rtu_ifu_retire_inst1_no_spec_miss
    DIRECTION INPUT ;
    USE SIGNAL ;
    PORT
      LAYER metal6 ;
        RECT 1221.945 0.000 1222.085 0.560 ;
    END
  END rtu_ifu_retire_inst1_no_spec_miss
  PIN rtu_ifu_retire_inst1_store
    DIRECTION INPUT ;
    USE SIGNAL ;
    PORT
      LAYER metal4 ;
        RECT 1223.065 0.000 1223.205 0.560 ;
    END
  END rtu_ifu_retire_inst1_store
  PIN rtu_ifu_retire_inst1_vl_pred
    DIRECTION INPUT ;
    USE SIGNAL ;
    PORT
      LAYER metal6 ;
        RECT 1223.065 0.000 1223.205 0.560 ;
    END
  END rtu_ifu_retire_inst1_vl_pred
  PIN rtu_ifu_retire_inst2_cur_pc[0]
    DIRECTION INPUT ;
    USE SIGNAL ;
    PORT
      LAYER metal4 ;
        RECT 1245.465 0.000 1245.605 0.560 ;
    END
  END rtu_ifu_retire_inst2_cur_pc[0]
  PIN rtu_ifu_retire_inst2_cur_pc[10]
    DIRECTION INPUT ;
    USE SIGNAL ;
    PORT
      LAYER metal4 ;
        RECT 1239.865 0.000 1240.005 0.560 ;
    END
  END rtu_ifu_retire_inst2_cur_pc[10]
  PIN rtu_ifu_retire_inst2_cur_pc[11]
    DIRECTION INPUT ;
    USE SIGNAL ;
    PORT
      LAYER metal6 ;
        RECT 1238.745 0.000 1238.885 0.560 ;
    END
  END rtu_ifu_retire_inst2_cur_pc[11]
  PIN rtu_ifu_retire_inst2_cur_pc[12]
    DIRECTION INPUT ;
    USE SIGNAL ;
    PORT
      LAYER metal4 ;
        RECT 1238.745 0.000 1238.885 0.560 ;
    END
  END rtu_ifu_retire_inst2_cur_pc[12]
  PIN rtu_ifu_retire_inst2_cur_pc[13]
    DIRECTION INPUT ;
    USE SIGNAL ;
    PORT
      LAYER metal6 ;
        RECT 1237.625 0.000 1237.765 0.560 ;
    END
  END rtu_ifu_retire_inst2_cur_pc[13]
  PIN rtu_ifu_retire_inst2_cur_pc[14]
    DIRECTION INPUT ;
    USE SIGNAL ;
    PORT
      LAYER metal4 ;
        RECT 1237.625 0.000 1237.765 0.560 ;
    END
  END rtu_ifu_retire_inst2_cur_pc[14]
  PIN rtu_ifu_retire_inst2_cur_pc[15]
    DIRECTION INPUT ;
    USE SIGNAL ;
    PORT
      LAYER metal6 ;
        RECT 1236.505 0.000 1236.645 0.560 ;
    END
  END rtu_ifu_retire_inst2_cur_pc[15]
  PIN rtu_ifu_retire_inst2_cur_pc[16]
    DIRECTION INPUT ;
    USE SIGNAL ;
    PORT
      LAYER metal4 ;
        RECT 1236.505 0.000 1236.645 0.560 ;
    END
  END rtu_ifu_retire_inst2_cur_pc[16]
  PIN rtu_ifu_retire_inst2_cur_pc[17]
    DIRECTION INPUT ;
    USE SIGNAL ;
    PORT
      LAYER metal6 ;
        RECT 1235.385 0.000 1235.525 0.560 ;
    END
  END rtu_ifu_retire_inst2_cur_pc[17]
  PIN rtu_ifu_retire_inst2_cur_pc[18]
    DIRECTION INPUT ;
    USE SIGNAL ;
    PORT
      LAYER metal4 ;
        RECT 1235.385 0.000 1235.525 0.560 ;
    END
  END rtu_ifu_retire_inst2_cur_pc[18]
  PIN rtu_ifu_retire_inst2_cur_pc[19]
    DIRECTION INPUT ;
    USE SIGNAL ;
    PORT
      LAYER metal6 ;
        RECT 1234.265 0.000 1234.405 0.560 ;
    END
  END rtu_ifu_retire_inst2_cur_pc[19]
  PIN rtu_ifu_retire_inst2_cur_pc[1]
    DIRECTION INPUT ;
    USE SIGNAL ;
    PORT
      LAYER metal6 ;
        RECT 1244.345 0.000 1244.485 0.560 ;
    END
  END rtu_ifu_retire_inst2_cur_pc[1]
  PIN rtu_ifu_retire_inst2_cur_pc[20]
    DIRECTION INPUT ;
    USE SIGNAL ;
    PORT
      LAYER metal4 ;
        RECT 1234.265 0.000 1234.405 0.560 ;
    END
  END rtu_ifu_retire_inst2_cur_pc[20]
  PIN rtu_ifu_retire_inst2_cur_pc[21]
    DIRECTION INPUT ;
    USE SIGNAL ;
    PORT
      LAYER metal6 ;
        RECT 1233.145 0.000 1233.285 0.560 ;
    END
  END rtu_ifu_retire_inst2_cur_pc[21]
  PIN rtu_ifu_retire_inst2_cur_pc[22]
    DIRECTION INPUT ;
    USE SIGNAL ;
    PORT
      LAYER metal4 ;
        RECT 1233.145 0.000 1233.285 0.560 ;
    END
  END rtu_ifu_retire_inst2_cur_pc[22]
  PIN rtu_ifu_retire_inst2_cur_pc[23]
    DIRECTION INPUT ;
    USE SIGNAL ;
    PORT
      LAYER metal6 ;
        RECT 1232.025 0.000 1232.165 0.560 ;
    END
  END rtu_ifu_retire_inst2_cur_pc[23]
  PIN rtu_ifu_retire_inst2_cur_pc[24]
    DIRECTION INPUT ;
    USE SIGNAL ;
    PORT
      LAYER metal4 ;
        RECT 1232.025 0.000 1232.165 0.560 ;
    END
  END rtu_ifu_retire_inst2_cur_pc[24]
  PIN rtu_ifu_retire_inst2_cur_pc[25]
    DIRECTION INPUT ;
    USE SIGNAL ;
    PORT
      LAYER metal6 ;
        RECT 1230.905 0.000 1231.045 0.560 ;
    END
  END rtu_ifu_retire_inst2_cur_pc[25]
  PIN rtu_ifu_retire_inst2_cur_pc[26]
    DIRECTION INPUT ;
    USE SIGNAL ;
    PORT
      LAYER metal4 ;
        RECT 1230.905 0.000 1231.045 0.560 ;
    END
  END rtu_ifu_retire_inst2_cur_pc[26]
  PIN rtu_ifu_retire_inst2_cur_pc[27]
    DIRECTION INPUT ;
    USE SIGNAL ;
    PORT
      LAYER metal6 ;
        RECT 1229.785 0.000 1229.925 0.560 ;
    END
  END rtu_ifu_retire_inst2_cur_pc[27]
  PIN rtu_ifu_retire_inst2_cur_pc[28]
    DIRECTION INPUT ;
    USE SIGNAL ;
    PORT
      LAYER metal4 ;
        RECT 1229.785 0.000 1229.925 0.560 ;
    END
  END rtu_ifu_retire_inst2_cur_pc[28]
  PIN rtu_ifu_retire_inst2_cur_pc[29]
    DIRECTION INPUT ;
    USE SIGNAL ;
    PORT
      LAYER metal6 ;
        RECT 1228.665 0.000 1228.805 0.560 ;
    END
  END rtu_ifu_retire_inst2_cur_pc[29]
  PIN rtu_ifu_retire_inst2_cur_pc[2]
    DIRECTION INPUT ;
    USE SIGNAL ;
    PORT
      LAYER metal4 ;
        RECT 1244.345 0.000 1244.485 0.560 ;
    END
  END rtu_ifu_retire_inst2_cur_pc[2]
  PIN rtu_ifu_retire_inst2_cur_pc[30]
    DIRECTION INPUT ;
    USE SIGNAL ;
    PORT
      LAYER metal4 ;
        RECT 1228.665 0.000 1228.805 0.560 ;
    END
  END rtu_ifu_retire_inst2_cur_pc[30]
  PIN rtu_ifu_retire_inst2_cur_pc[31]
    DIRECTION INPUT ;
    USE SIGNAL ;
    PORT
      LAYER metal6 ;
        RECT 1227.545 0.000 1227.685 0.560 ;
    END
  END rtu_ifu_retire_inst2_cur_pc[31]
  PIN rtu_ifu_retire_inst2_cur_pc[32]
    DIRECTION INPUT ;
    USE SIGNAL ;
    PORT
      LAYER metal4 ;
        RECT 1227.545 0.000 1227.685 0.560 ;
    END
  END rtu_ifu_retire_inst2_cur_pc[32]
  PIN rtu_ifu_retire_inst2_cur_pc[33]
    DIRECTION INPUT ;
    USE SIGNAL ;
    PORT
      LAYER metal6 ;
        RECT 1226.425 0.000 1226.565 0.560 ;
    END
  END rtu_ifu_retire_inst2_cur_pc[33]
  PIN rtu_ifu_retire_inst2_cur_pc[34]
    DIRECTION INPUT ;
    USE SIGNAL ;
    PORT
      LAYER metal4 ;
        RECT 1226.425 0.000 1226.565 0.560 ;
    END
  END rtu_ifu_retire_inst2_cur_pc[34]
  PIN rtu_ifu_retire_inst2_cur_pc[35]
    DIRECTION INPUT ;
    USE SIGNAL ;
    PORT
      LAYER metal6 ;
        RECT 1225.305 0.000 1225.445 0.560 ;
    END
  END rtu_ifu_retire_inst2_cur_pc[35]
  PIN rtu_ifu_retire_inst2_cur_pc[36]
    DIRECTION INPUT ;
    USE SIGNAL ;
    PORT
      LAYER metal4 ;
        RECT 1225.305 0.000 1225.445 0.560 ;
    END
  END rtu_ifu_retire_inst2_cur_pc[36]
  PIN rtu_ifu_retire_inst2_cur_pc[37]
    DIRECTION INPUT ;
    USE SIGNAL ;
    PORT
      LAYER metal6 ;
        RECT 1224.185 0.000 1224.325 0.560 ;
    END
  END rtu_ifu_retire_inst2_cur_pc[37]
  PIN rtu_ifu_retire_inst2_cur_pc[38]
    DIRECTION INPUT ;
    USE SIGNAL ;
    PORT
      LAYER metal4 ;
        RECT 1224.185 0.000 1224.325 0.560 ;
    END
  END rtu_ifu_retire_inst2_cur_pc[38]
  PIN rtu_ifu_retire_inst2_cur_pc[3]
    DIRECTION INPUT ;
    USE SIGNAL ;
    PORT
      LAYER metal6 ;
        RECT 1243.225 0.000 1243.365 0.560 ;
    END
  END rtu_ifu_retire_inst2_cur_pc[3]
  PIN rtu_ifu_retire_inst2_cur_pc[4]
    DIRECTION INPUT ;
    USE SIGNAL ;
    PORT
      LAYER metal4 ;
        RECT 1243.225 0.000 1243.365 0.560 ;
    END
  END rtu_ifu_retire_inst2_cur_pc[4]
  PIN rtu_ifu_retire_inst2_cur_pc[5]
    DIRECTION INPUT ;
    USE SIGNAL ;
    PORT
      LAYER metal6 ;
        RECT 1242.105 0.000 1242.245 0.560 ;
    END
  END rtu_ifu_retire_inst2_cur_pc[5]
  PIN rtu_ifu_retire_inst2_cur_pc[6]
    DIRECTION INPUT ;
    USE SIGNAL ;
    PORT
      LAYER metal4 ;
        RECT 1242.105 0.000 1242.245 0.560 ;
    END
  END rtu_ifu_retire_inst2_cur_pc[6]
  PIN rtu_ifu_retire_inst2_cur_pc[7]
    DIRECTION INPUT ;
    USE SIGNAL ;
    PORT
      LAYER metal6 ;
        RECT 1240.985 0.000 1241.125 0.560 ;
    END
  END rtu_ifu_retire_inst2_cur_pc[7]
  PIN rtu_ifu_retire_inst2_cur_pc[8]
    DIRECTION INPUT ;
    USE SIGNAL ;
    PORT
      LAYER metal4 ;
        RECT 1240.985 0.000 1241.125 0.560 ;
    END
  END rtu_ifu_retire_inst2_cur_pc[8]
  PIN rtu_ifu_retire_inst2_cur_pc[9]
    DIRECTION INPUT ;
    USE SIGNAL ;
    PORT
      LAYER metal6 ;
        RECT 1239.865 0.000 1240.005 0.560 ;
    END
  END rtu_ifu_retire_inst2_cur_pc[9]
  PIN rtu_ifu_retire_inst2_load
    DIRECTION INPUT ;
    USE SIGNAL ;
    PORT
      LAYER metal6 ;
        RECT 1245.465 0.000 1245.605 0.560 ;
    END
  END rtu_ifu_retire_inst2_load
  PIN rtu_ifu_retire_inst2_no_spec_hit
    DIRECTION INPUT ;
    USE SIGNAL ;
    PORT
      LAYER metal4 ;
        RECT 1246.585 0.000 1246.725 0.560 ;
    END
  END rtu_ifu_retire_inst2_no_spec_hit
  PIN rtu_ifu_retire_inst2_no_spec_mispred
    DIRECTION INPUT ;
    USE SIGNAL ;
    PORT
      LAYER metal6 ;
        RECT 1246.585 0.000 1246.725 0.560 ;
    END
  END rtu_ifu_retire_inst2_no_spec_mispred
  PIN rtu_ifu_retire_inst2_no_spec_miss
    DIRECTION INPUT ;
    USE SIGNAL ;
    PORT
      LAYER metal4 ;
        RECT 1247.705 0.000 1247.845 0.560 ;
    END
  END rtu_ifu_retire_inst2_no_spec_miss
  PIN rtu_ifu_retire_inst2_store
    DIRECTION INPUT ;
    USE SIGNAL ;
    PORT
      LAYER metal6 ;
        RECT 1247.705 0.000 1247.845 0.560 ;
    END
  END rtu_ifu_retire_inst2_store
  PIN rtu_ifu_retire_inst2_vl_pred
    DIRECTION INPUT ;
    USE SIGNAL ;
    PORT
      LAYER metal4 ;
        RECT 1248.825 0.000 1248.965 0.560 ;
    END
  END rtu_ifu_retire_inst2_vl_pred
  PIN rtu_ifu_xx_dbgon
    DIRECTION INPUT ;
    USE SIGNAL ;
    PORT
      LAYER metal6 ;
        RECT 1248.825 0.000 1248.965 0.560 ;
    END
  END rtu_ifu_xx_dbgon
  PIN rtu_ifu_xx_expt_vec[0]
    DIRECTION INPUT ;
    USE SIGNAL ;
    PORT
      LAYER metal6 ;
        RECT 1252.185 0.000 1252.325 0.560 ;
    END
  END rtu_ifu_xx_expt_vec[0]
  PIN rtu_ifu_xx_expt_vec[1]
    DIRECTION INPUT ;
    USE SIGNAL ;
    PORT
      LAYER metal4 ;
        RECT 1252.185 0.000 1252.325 0.560 ;
    END
  END rtu_ifu_xx_expt_vec[1]
  PIN rtu_ifu_xx_expt_vec[2]
    DIRECTION INPUT ;
    USE SIGNAL ;
    PORT
      LAYER metal6 ;
        RECT 1251.065 0.000 1251.205 0.560 ;
    END
  END rtu_ifu_xx_expt_vec[2]
  PIN rtu_ifu_xx_expt_vec[3]
    DIRECTION INPUT ;
    USE SIGNAL ;
    PORT
      LAYER metal4 ;
        RECT 1251.065 0.000 1251.205 0.560 ;
    END
  END rtu_ifu_xx_expt_vec[3]
  PIN rtu_ifu_xx_expt_vec[4]
    DIRECTION INPUT ;
    USE SIGNAL ;
    PORT
      LAYER metal6 ;
        RECT 1249.945 0.000 1250.085 0.560 ;
    END
  END rtu_ifu_xx_expt_vec[4]
  PIN rtu_ifu_xx_expt_vec[5]
    DIRECTION INPUT ;
    USE SIGNAL ;
    PORT
      LAYER metal4 ;
        RECT 1249.945 0.000 1250.085 0.560 ;
    END
  END rtu_ifu_xx_expt_vec[5]
  PIN rtu_ifu_xx_expt_vld
    DIRECTION INPUT ;
    USE SIGNAL ;
    PORT
      LAYER metal4 ;
        RECT 1253.305 0.000 1253.445 0.560 ;
    END
  END rtu_ifu_xx_expt_vld
  PIN rtu_yy_xx_dbgon
    DIRECTION INPUT ;
    USE SIGNAL ;
    PORT
      LAYER metal6 ;
        RECT 1253.305 0.000 1253.445 0.560 ;
    END
  END rtu_yy_xx_dbgon
  PIN vfdsu_ifu_debug_ex2_wait
    DIRECTION INPUT ;
    USE SIGNAL ;
    PORT
      LAYER metal4 ;
        RECT 1254.425 0.000 1254.565 0.560 ;
    END
  END vfdsu_ifu_debug_ex2_wait
  PIN vfdsu_ifu_debug_idle
    DIRECTION INPUT ;
    USE SIGNAL ;
    PORT
      LAYER metal6 ;
        RECT 1254.425 0.000 1254.565 0.560 ;
    END
  END vfdsu_ifu_debug_idle
  PIN vfdsu_ifu_debug_pipe_busy
    DIRECTION INPUT ;
    USE SIGNAL ;
    PORT
      LAYER metal4 ;
        RECT 1255.545 0.000 1255.685 0.560 ;
    END
  END vfdsu_ifu_debug_pipe_busy
  PIN VDD
    DIRECTION INOUT ;
    USE POWER ;
    PORT
      LAYER metal7 ;
        RECT 0.000 8.970 1356.790 10.370 ;
        RECT 0.000 48.970 1356.790 50.370 ;
        RECT 0.000 88.970 1356.790 90.370 ;
        RECT 0.000 128.970 1356.790 130.370 ;
        RECT 0.000 168.970 1356.790 170.370 ;
        RECT 0.000 208.970 1356.790 210.370 ;
        RECT 0.000 248.970 1356.790 250.370 ;
        RECT 0.000 288.970 1356.790 290.370 ;
        RECT 0.000 328.970 1356.790 330.370 ;
        RECT 0.000 368.970 1356.790 370.370 ;
        RECT 0.000 408.970 1356.790 410.370 ;
        RECT 0.000 448.970 1356.790 450.370 ;
        RECT 0.000 488.970 1356.790 490.370 ;
        RECT 0.000 528.970 1356.790 530.370 ;
        RECT 0.000 568.970 1356.790 570.370 ;
        RECT 0.000 608.970 1356.790 610.370 ;
        RECT 0.000 648.970 1356.790 650.370 ;
        RECT 0.000 688.970 1356.790 690.370 ;
    END
  END VDD
  PIN VSS
    DIRECTION INOUT ;
    USE GROUND ;
    PORT
      LAYER metal7 ;
        RECT 0.000 28.970 1356.790 30.370 ;
        RECT 0.000 68.970 1356.790 70.370 ;
        RECT 0.000 108.970 1356.790 110.370 ;
        RECT 0.000 148.970 1356.790 150.370 ;
        RECT 0.000 188.970 1356.790 190.370 ;
        RECT 0.000 228.970 1356.790 230.370 ;
        RECT 0.000 268.970 1356.790 270.370 ;
        RECT 0.000 308.970 1356.790 310.370 ;
        RECT 0.000 348.970 1356.790 350.370 ;
        RECT 0.000 388.970 1356.790 390.370 ;
        RECT 0.000 428.970 1356.790 430.370 ;
        RECT 0.000 468.970 1356.790 470.370 ;
        RECT 0.000 508.970 1356.790 510.370 ;
        RECT 0.000 548.970 1356.790 550.370 ;
        RECT 0.000 588.970 1356.790 590.370 ;
        RECT 0.000 628.970 1356.790 630.370 ;
        RECT 0.000 668.970 1356.790 670.370 ;
        RECT 0.000 708.970 1356.790 710.370 ;
    END
  END VSS
  OBS
    LAYER metal1 ;
      RECT 0 0 1356.790 728.000 ;
    LAYER metal2 ;
      RECT 0 0 1356.790 728.000 ;
    LAYER metal3 ;
      RECT 0.7 0.7 1356.090 727.300 ;
    LAYER metal4 ;
      RECT 0.7 0.7 1356.090 727.300 ;
    LAYER metal5 ;
      RECT 0.7 0.7 1356.090 727.300 ;
    LAYER metal6 ;
      RECT 0.7 0.7 1356.090 727.300 ;
    LAYER metal7 ;
      RECT 0 0.000 1356.790 8.570 ;
      RECT 0 10.770 1356.790 28.570 ;
      RECT 0 30.770 1356.790 48.570 ;
      RECT 0 50.770 1356.790 68.570 ;
      RECT 0 70.770 1356.790 88.570 ;
      RECT 0 90.770 1356.790 108.570 ;
      RECT 0 110.770 1356.790 128.570 ;
      RECT 0 130.770 1356.790 148.570 ;
      RECT 0 150.770 1356.790 168.570 ;
      RECT 0 170.770 1356.790 188.570 ;
      RECT 0 190.770 1356.790 208.570 ;
      RECT 0 210.770 1356.790 228.570 ;
      RECT 0 230.770 1356.790 248.570 ;
      RECT 0 250.770 1356.790 268.570 ;
      RECT 0 270.770 1356.790 288.570 ;
      RECT 0 290.770 1356.790 308.570 ;
      RECT 0 310.770 1356.790 328.570 ;
      RECT 0 330.770 1356.790 348.570 ;
      RECT 0 350.770 1356.790 368.570 ;
      RECT 0 370.770 1356.790 388.570 ;
      RECT 0 390.770 1356.790 408.570 ;
      RECT 0 410.770 1356.790 428.570 ;
      RECT 0 430.770 1356.790 448.570 ;
      RECT 0 450.770 1356.790 468.570 ;
      RECT 0 470.770 1356.790 488.570 ;
      RECT 0 490.770 1356.790 508.570 ;
      RECT 0 510.770 1356.790 528.570 ;
      RECT 0 530.770 1356.790 548.570 ;
      RECT 0 550.770 1356.790 568.570 ;
      RECT 0 570.770 1356.790 588.570 ;
      RECT 0 590.770 1356.790 608.570 ;
      RECT 0 610.770 1356.790 628.570 ;
      RECT 0 630.770 1356.790 648.570 ;
      RECT 0 650.770 1356.790 668.570 ;
      RECT 0 670.770 1356.790 688.570 ;
      RECT 0 690.770 1356.790 708.570 ;
      RECT 0 710.770 1356.790 728.000 ;
  END
END ct_ifu_top

END LIBRARY
